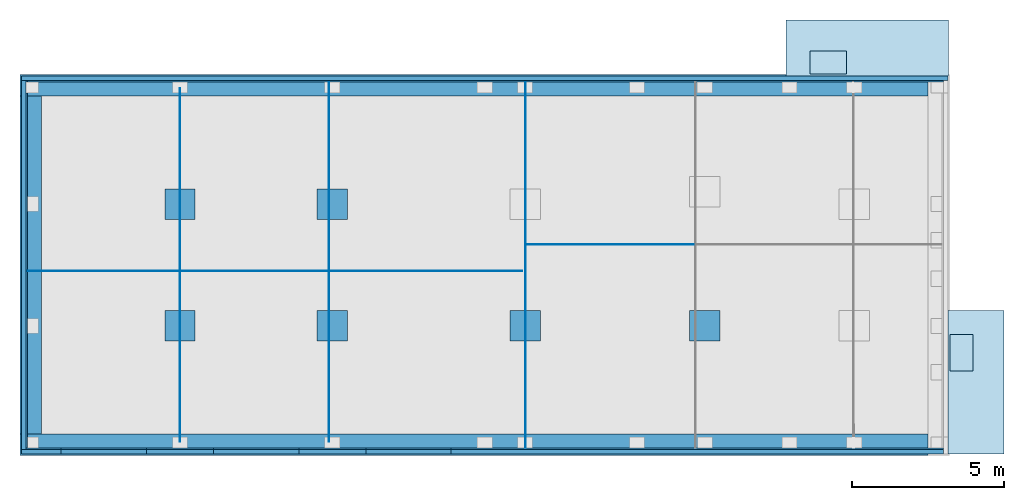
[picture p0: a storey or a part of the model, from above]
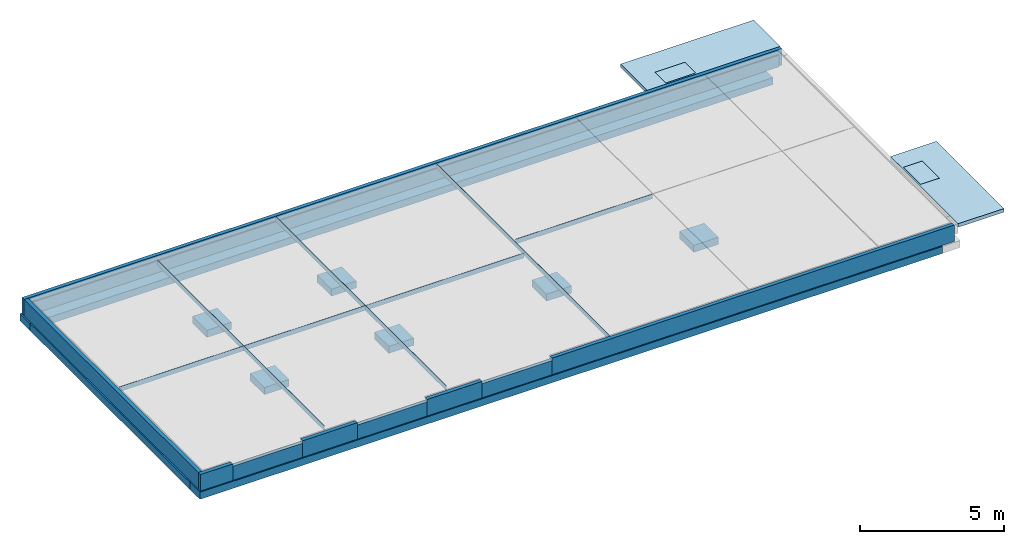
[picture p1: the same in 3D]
Properties of the parts of a building model (IFC2X3), part 1 of 7

# File
Description: IFC2x3 Coordination View
File name: Z:\11023 HEKF Nybygg Måkeveien\00 Tegninger\00 sibsas\HEKF Administrasjonbygg måkeveien Bygg.ifc
Time: 2018-05-01T14:40:47
Author: Bård Sørensen
Organization: Sivilingeniør Bård Sørensen AS, Pb 28, 8455 Stokmarknes, Mob 906 34 144
Written by: EDMsix Version 2.0100.09 Sep 7 2016
Made in: Allplan 2018.0 22.03.2018 - 09:24:33

# IfcBuildingStorey (3)
In: HEKF Administrasjonbygg
Name | Elevation (mm)
Konstruksjoner i grunnen | 6300
Plan 1 | 6500
Plan 2 | 9900

# IfcSpace (44)
InteriorOrExteriorSpace: INTERNAL
Allplan Attributes - Building alteration category: New building; Unit: m²; Area_type_floor_space: 0; BauNVO_FA: 0; BauNVO_FS: 0; Space below stairs (flr spc only > 2m): 0; Factor_floor_area_room: 1; Factor_277: 1
Name | In | LongName | FloorCovering | CeilingCovering | FinishFloorHigh (m) | FinishCeilingHigh (m) | ElevationWithFlooring (m) | GrossWallArea (m2) | NetVolume (m3) | NetFloorArea (m2) | GrossVolume (m3) | CrossSectionArea (m2) | NetPerimeter (m) | NetWallArea (m2) | Allright_Comp_ID | Local_code_story_name | NOI_UUID
101 | Plan 1 | Kontor | Banebelegg, acustikk | Støvbinding, Systemhimling | 0.003 | 2.937 | 6503 | 39.5128 | 30.5853 | 10.4138 | 31.8314 | 10.6105 | 13.1709 | 39.5128 | 0019Roo0000000002 | 1 | ac553d8b-398e-4058-95c3-ac796ec1c327--2 | Pset_SpaceCommon - WallCovering: Ubehandlet SW
107 | Plan 1 | BK | våtromsbelegg m oppkant | støvbinding, systemhimling | 0.003 | 2.937 | 6503 | 21.51 | 8.27036 | 2.81592 | 8.62474 | 2.87491 | 7.17 | 21.51 | 0019Roo0000000085 | 1 | ac553d8b-398e-4058-95c3-ac796ec1c327--85 | Pset_SpaceCommon - WallCovering: Ubehandlet SW
108 | Plan 1 | RWC | våtromsbelegg m oppkant | støvbinding, systemhimling | 0.003 | 2.937 | 6503 | 27.588 | 15.5067 | 5.27978 | 15.8393 | 5.27978 | 9.196 | 27.588 | 0019Roo0000000095 | 1 | ac553d8b-398e-4058-95c3-ac796ec1c327--95
109 | Plan 1 | WCD | våtromsbelegg m oppkant | støvbinding, systemhimling | 0.003 | 2.937 | 6503 | 17.786 | 6.0816 | 2.07068 | 6.36985 | 2.12328 | 5.92866 | 17.786 | 0019Roo0000000105 | 1 | ac553d8b-398e-4058-95c3-ac796ec1c327--105 | Pset_SpaceCommon - WallCovering: Ubehandlet SW
110 | Plan 1 | Fingard-D | våtromsbelegg m oppkant | støvbinding, systemhimling | 0.003 | 2.937 | 6503 | 47.5798 | 37.7168 | 12.842 | 38.7449 | 12.915 | 15.8599 | 47.5798 | 0019Roo0000000115 | 1 | ac553d8b-398e-4058-95c3-ac796ec1c327--115 | Pset_SpaceCommon - WallCovering: Ubehandlet SW
114 | Plan 1 | WCH | våtromsbelegg m oppkant | støvbinding, systemhimling | 0.003 | 2.937 | 6503 | 18.276 | 6.8054 | 2.31713 | 6.95138 | 2.31713 | 6.092 | 18.276 | 0019Roo0000000155 | 1 | ac553d8b-398e-4058-95c3-ac796ec1c327--155
111 | Plan 1 | Dusj D | våtromsbelegg m oppkant | støvbinding, systemhimling | 0.003 | 2.937 | 6503 | 22.8664 | 10.3971 | 3.54004 | 10.6201 | 3.54004 | 7.62212 | 22.8664 | 0019Roo0000000125 | 1 | ac553d8b-398e-4058-95c3-ac796ec1c327--125
115 | Plan 1 | Dusj H | våtromsbelegg m oppkant | støvbinding, systemhimling | 0.003 | 2.937 | 6503 | 20.466 | 8.38554 | 2.85514 | 8.56541 | 2.85514 | 6.822 | 20.466 | 0019Roo0000000165 | 1 | ac553d8b-398e-4058-95c3-ac796ec1c327--165
116 | Plan 1 | Fingard-H | våtromsbelegg m oppkant | støvbinding, systemhimling | 0.003 | 2.937 | 6503 | 52.0936 | 40.4039 | 13.7569 | 41.4585 | 13.8195 | 17.3645 | 52.0936 | 0019Roo0000000185 | 1 | ac553d8b-398e-4058-95c3-ac796ec1c327--185 | Pset_SpaceCommon - WallCovering: Ubehandlet SW
117 | Plan 1 | Grovgard-H | våtromsbelegg m oppkant | støvbinding, systemhimling | 0.03 | 2.91 | 6530 | 48.666 | 38.0572 | 13.0781 | 39.5514 | 13.1838 | 16.222 | 48.666 | 0019Roo0000000175 | 1 | ac553d8b-398e-4058-95c3-ac796ec1c327--175 | Pset_SpaceCommon - WallCovering: Ubehandlet SW
113 | Plan 1 | Gang | Våtromsbelegg | Støvbinding, Systemhimling | 0.003 | 2.937 | 6503 | 24.744 | 12.4317 | 4.2328 | 12.6984 | 4.2328 | 8.248 | 24.744 | 0019Roo0000000145 | 1 | ac553d8b-398e-4058-95c3-ac796ec1c327--145
120 | Plan 1 | Teknisk rom | Golvmaling | Støvbinding x2 | 0.003 | 2.967 | 6503 | 55.866 | 55.4831 | 18.7001 | 56.6694 | 18.8898 | 18.622 | 55.866 | 0019Roo0000000217 | 1 | ac553d8b-398e-4058-95c3-ac796ec1c327--217 | Pset_SpaceCommon - WallCovering: Ubehandlet SW
119 | Plan 1 | Vask | Våtromsbelegg | Støvbinding x2 | 0.003 | 2.967 | 6503 | 25.069 | 12.6974 | 4.27953 | 12.8386 | 4.27953 | 8.35633 | 25.069 | 0019Roo0000000207 | 1 | ac553d8b-398e-4058-95c3-ac796ec1c327--207
121 | Plan 1 | WC | Våtromsbelegg | Støvbinding x2 | 0.003 | 2.967 | 6503 | 18.0177 | 6.42801 | 2.1665 | 6.4995 | 2.1665 | 6.0059 | 18.0177 | 0019Roo0000000227 | 1 | ac553d8b-398e-4058-95c3-ac796ec1c327--227
122 | Plan 1 | Lager | Golvmaling | Støvbinding x2 | 0.003 | 2.967 | 6503 | 31.7213 | 20.5405 | 6.92299 | 20.769 | 6.92299 | 10.5738 | 31.7213 | 0019Roo0000000237 | 1 | ac553d8b-398e-4058-95c3-ac796ec1c327--237
123 | Plan 1 | Lager | Golvmaling | Støvbinding x2 | 0.003 | 2.967 | 6503 | 100.042 | 165.987 | 55.9444 | 168.253 | 56.0843 | 33.3474 | 100.042 | 0019Roo0000000254 | 1 | ac553d8b-398e-4058-95c3-ac796ec1c327--254 | Pset_SpaceCommon - WallCovering: Ubehandlet SW
124 | Plan 1 | Lager | Golvmaling | Støvbinding x2 | 0.003 | 2.967 | 6503 | 101.62 | 174.887 | 58.9441 | 177.721 | 59.2403 | 33.8734 | 101.62 | 0019Roo0000000271 | 1 | ac553d8b-398e-4058-95c3-ac796ec1c327--271 | Pset_SpaceCommon - WallCovering: Ubehandlet SW
118 | Plan 1 | Lager | Golvmaling | Støvbinding x2 | 0.03 | 2.94 | 6530 | 79.422 | 119.839 | 40.7617 | 122.854 | 40.9514 | 26.474 | 79.422 | 0019Roo0000000195 | 1 | ac553d8b-398e-4058-95c3-ac796ec1c327--195 | Pset_SpaceCommon - WallCovering: Ubehandlet SW
102 | Plan 1 | Trapperom | Golvflis | Støvbinding, Systemhimling | 0.003 | 2.937 | 6503 | 40.7104 | 32.4609 | 11.0524 | 33.5148 | 11.1716 | 13.5701 | 32.2758 | 0019Roo0000000046 | 1 | ac553d8b-398e-4058-95c3-ac796ec1c327--46 | Pset_SpaceCommon - WallCovering: Ubehandlet SW
105 | Plan 1 | Kantine | Banebelegg, homogent | Støvbinding, Systemhimling | 0.003 | 2.937 | 6503 | 68.1436 | 92.307 | 31.429 | 94.287 | 31.429 | 22.7145 | 68.1436 | 0019Roo0000000022 | 1 | ac553d8b-398e-4058-95c3-ac796ec1c327--22 | Pset_SpaceCommon - WallCovering: Ubehandlet SW
112 | Plan 1 | Grovgard-D | våtromsbelegg m oppkant | støvbinding, systemhimling | 0.003 | 2.937 | 6503 | 41.31 | 27.864 | 9.48724 | 28.6349 | 9.54496 | 13.77 | 41.31 | 0019Roo0000000135 | 1 | ac553d8b-398e-4058-95c3-ac796ec1c327--135 | Pset_SpaceCommon - WallCovering: Ubehandlet SW; Allplan Attributes - Enclosure: R; Area_type_277: N; Occupancy_type_Din277: USA
103.1 | Plan 1 | Gang | Golvflis | Støvbinding, Systemhimling | 0.003 | 2.937 | 6503 | 30.5276 | 18.5966 | 6.33183 | 19.2004 | 6.40012 | 10.1759 | 17.743 | 0019Roo0000000032 | 1 | ac553d8b-398e-4058-95c3-ac796ec1c327--32 | Pset_SpaceCommon - WallCovering: Ubehandlet SW
103.2 | Plan 1 | Heis |  |  | 0 | 3 | 6500 | 19.8 | 7.7532 | 2.5844 | 8.0475 | 2.6825 | 6.6 | 15.45 | 0019Roo0779929851 | 1 | ac553d8b-398e-4058-95c3-ac796ec1c327--779929851 | Allplan Attributes - Enclosure: R; Area_type_277: N; Occupancy_type_Din277: USA
104 | Plan 1 | Tavlerom | Våtromsbelegg | Støvbinding, Systemhimling | 0.03 | 2.91 | 6530 | 17.7568 | 6.09027 | 2.09287 | 6.38982 | 2.12994 | 5.91893 | 17.7568 | 0019Roo0779929835 | 1 | ac553d8b-398e-4058-95c3-ac796ec1c327--779929835
106 | Plan 1 | Gang | Banebelegg, homogent | Støvbinding, Systemhimling | 0.003 | 2.937 | 6503 | 69.344 | 46.7483 | 15.917 | 47.8954 | 15.9651 | 23.1147 | 69.344 | 0019Roo0000000012 | 1 | ac553d8b-398e-4058-95c3-ac796ec1c327--12 | Pset_SpaceCommon - WallCovering: Ubehandlet SW; Allplan Attributes - Enclosure: R; Area_type_277: N; Occupancy_type_Din277: USA
215 | Plan 2 | BK | Våtromsbelegg m oppkant | Systemhimling | 0.003 | 3.5724 | 9903 | 26.5806 | 11.1277 | 3.11497 | 11.2307 | 3.11497 | 7.37243 | 26.5806 | 0029Roo0000000164 | 2 | ba775db5-6acf-44d4-98dd-11fdd85c2627--164
204 | Plan 2 | WC-H | Våtromsbelegg m oppkant | Systemhimling | 0.03 | 3.5454 | 9930 | 19.3372 | 6.37114 | 1.79705 | 6.47909 | 1.79705 | 5.36341 | 19.3372 | 0029Roo0000000054 | 2 | ba775db5-6acf-44d4-98dd-11fdd85c2627--54
203 | Plan 2 | RWC | Våtromsbelegg m oppkant | Systemhimling | 0.03 | 3.76167 | 9930 | 34.7772 | 19.4475 | 5.17 | 19.758 | 5.17 | 9.1 | 34.7772 | 0029Roo0000000044 | 2 | ba775db5-6acf-44d4-98dd-11fdd85c2627--44
206 | Plan 2 | Kontor |  |  | 0 | 3.26917 | 9900 | 51.3194 | 46.0235 | 14.078 | 46.0235 | 14.078 | 15.698 | 51.3194 | 0029Roo0000000074 | 2 | ba775db5-6acf-44d4-98dd-11fdd85c2627--74
208 | Plan 2 | Kontor |  |  | 0 | 3.26917 | 9900 | 51.3194 | 46.0235 | 14.078 | 46.0235 | 14.078 | 15.698 | 51.3194 | 0029Roo0000000094 | 2 | ba775db5-6acf-44d4-98dd-11fdd85c2627--94
210 | Plan 2 | Kontor |  |  | 0 | 3.26917 | 9900 | 54.9921 | 55.3429 | 16.9288 | 55.3429 | 16.9288 | 16.8214 | 54.9921 | 0029Roo0000000114 | 2 | ba775db5-6acf-44d4-98dd-11fdd85c2627--114
211 | Plan 2 | Kontor |  |  | 0 | 3.73083 | 9900 | 58.2905 | 51.8223 | 13.8903 | 51.8223 | 13.8903 | 15.624 | 58.2905 | 0029Roo0000000124 | 2 | ba775db5-6acf-44d4-98dd-11fdd85c2627--124
207 | Plan 2 | Kontor |  |  | 0 | 3.26917 | 9900 | 51.3194 | 46.0235 | 14.078 | 46.0235 | 14.078 | 15.698 | 51.3194 | 0029Roo0000000084 | 2 | ba775db5-6acf-44d4-98dd-11fdd85c2627--84
213 | Plan 2 | Kontor |  |  | 0 | 3.73083 | 9900 | 58.2009 | 51.5951 | 13.8294 | 51.5951 | 13.8294 | 15.6 | 58.201 | 0029Roo0000000144 | 2 | ba775db5-6acf-44d4-98dd-11fdd85c2627--144
212 | Plan 2 | Kontor |  |  | 0 | 3.73083 | 9900 | 58.186 | 51.5572 | 13.8192 | 51.5572 | 13.8192 | 15.596 | 58.1861 | 0029Roo0000000134 | 2 | ba775db5-6acf-44d4-98dd-11fdd85c2627--134
202 | Plan 2 | Korridor |  |  | 0 | 3.44226 | 9900 | 170.154 | 136.68 | 39.7065 | 136.68 | 39.7065 | 49.4308 | 170.177 | 0029Roo0000000032 | 2 | ba775db5-6acf-44d4-98dd-11fdd85c2627--32
205 | Plan 2 | Garderobe |  |  | 0 | 3.2258 | 9900 | 42.39 | 34.0447 | 10.5539 | 34.0447 | 10.5539 | 13.1409 | 42.39 | 0029Roo0000000064 | 2 | ba775db5-6acf-44d4-98dd-11fdd85c2627--64
209 | Plan 2 | Arkiv/kopi |  |  | 0 | 3.31503 | 9900 | 42.6067 | 33.4428 | 10.0882 | 33.4428 | 10.0882 | 12.8526 | 42.6067 | 0029Roo0000000104 | 2 | ba775db5-6acf-44d4-98dd-11fdd85c2627--104
214 | Plan 2 | Møterom | banebelegg acustikk | Systemhimling | 0.003 | 3.73663 | 9903 | 80.0588 | 91.3179 | 24.439 | 92.126 | 24.439 | 21.2378 | 79.9513 | 0029Roo0000000154 | 2 | ba775db5-6acf-44d4-98dd-11fdd85c2627--154
216 | Plan 2 | IKT | banebelegg acustikk | Systemhimling | 0.003 | 3.80953 | 9903 | 22.2028 | 7.6517 | 2.0086 | 7.71812 | 2.0086 | 5.77816 | 22.2028 | 0029Roo0780027036 | 2 | ba775db5-6acf-44d4-98dd-11fdd85c2627--780027036
218 | Plan 2 | Sjakt |  |  | 0 | 3.14 | 9900 | 24.6633 | 10.2764 | 3.27274 | 10.2764 | 3.27274 | 7.85457 | 24.6633 | 0029Roo0780027340 | 2 | ba775db5-6acf-44d4-98dd-11fdd85c2627--780027340
201 | Plan 2 | Gang | Golvflis | Systemhimling | 0.003 | 3.64271 | 9903 | 60.9532 | 44.2319 | 12.1411 | 44.6334 | 12.1428 | 16.5827 | 41.7609 | 0029Roo0000000020 | 2 | ba775db5-6acf-44d4-98dd-11fdd85c2627--20
200 | Plan 2 | Trapperom | Golvflis | Systemhimling | 0.003 | 3.46033 | 9903 | 47.5754 | 38.886 | 11.2379 | 39.2576 | 11.2379 | 13.6189 | 33.8822 | 0029Roo0000000007 | 2 | ba775db5-6acf-44d4-98dd-11fdd85c2627--7
217 | Plan 2 | Heis |  |  | 0 | 3.83833 | 9900 | 25.333 | 10.2963 | 2.6825 | 10.2963 | 2.6825 | 6.6 | 19.8568 | 0029Roo0780027106 | 2 | ba775db5-6acf-44d4-98dd-11fdd85c2627--780027106

# IfcAnnotation (2236)
Name | In | NOI_UUID
 | HEKF Administrasjonbygg | f3b9140b-d331-4fc5-a6fb-2d5accb557e5--59120
 | HEKF Administrasjonbygg | f3b9140b-d331-4fc5-a6fb-2d5accb557e5--59619
 | HEKF Administrasjonbygg | f3b9140b-d331-4fc5-a6fb-2d5accb557e5--59620
 | HEKF Administrasjonbygg | f3b9140b-d331-4fc5-a6fb-2d5accb557e5--59621
 | HEKF Administrasjonbygg | f3b9140b-d331-4fc5-a6fb-2d5accb557e5--59622
 | HEKF Administrasjonbygg | f3b9140b-d331-4fc5-a6fb-2d5accb557e5--59623
 | HEKF Administrasjonbygg | f3b9140b-d331-4fc5-a6fb-2d5accb557e5--59624
 | HEKF Administrasjonbygg | f3b9140b-d331-4fc5-a6fb-2d5accb557e5--59625
 | HEKF Administrasjonbygg | f3b9140b-d331-4fc5-a6fb-2d5accb557e5--59626
 | HEKF Administrasjonbygg | f3b9140b-d331-4fc5-a6fb-2d5accb557e5--59627
 | HEKF Administrasjonbygg | f3b9140b-d331-4fc5-a6fb-2d5accb557e5--59628
 | HEKF Administrasjonbygg | f3b9140b-d331-4fc5-a6fb-2d5accb557e5--59629
 | HEKF Administrasjonbygg | f3b9140b-d331-4fc5-a6fb-2d5accb557e5--59129
 | HEKF Administrasjonbygg | f3b9140b-d331-4fc5-a6fb-2d5accb557e5--59130
 | HEKF Administrasjonbygg | f3b9140b-d331-4fc5-a6fb-2d5accb557e5--59136
 | HEKF Administrasjonbygg | f3b9140b-d331-4fc5-a6fb-2d5accb557e5--59137
 | HEKF Administrasjonbygg | f3b9140b-d331-4fc5-a6fb-2d5accb557e5--59141
 | HEKF Administrasjonbygg | f3b9140b-d331-4fc5-a6fb-2d5accb557e5--59142
 | HEKF Administrasjonbygg | f3b9140b-d331-4fc5-a6fb-2d5accb557e5--59160
 | HEKF Administrasjonbygg | f3b9140b-d331-4fc5-a6fb-2d5accb557e5--59161
 | HEKF Administrasjonbygg | f3b9140b-d331-4fc5-a6fb-2d5accb557e5--59163
 | HEKF Administrasjonbygg | f3b9140b-d331-4fc5-a6fb-2d5accb557e5--59164
 | HEKF Administrasjonbygg | f3b9140b-d331-4fc5-a6fb-2d5accb557e5--59157
 | HEKF Administrasjonbygg | f3b9140b-d331-4fc5-a6fb-2d5accb557e5--59158
 | HEKF Administrasjonbygg | f3b9140b-d331-4fc5-a6fb-2d5accb557e5--59569
 | HEKF Administrasjonbygg | f3b9140b-d331-4fc5-a6fb-2d5accb557e5--59571
 | HEKF Administrasjonbygg | f3b9140b-d331-4fc5-a6fb-2d5accb557e5--59573
 | HEKF Administrasjonbygg | f3b9140b-d331-4fc5-a6fb-2d5accb557e5--59575
 | HEKF Administrasjonbygg | f3b9140b-d331-4fc5-a6fb-2d5accb557e5--59580
 | HEKF Administrasjonbygg | f3b9140b-d331-4fc5-a6fb-2d5accb557e5--59582
 | HEKF Administrasjonbygg | f3b9140b-d331-4fc5-a6fb-2d5accb557e5--59584
 | HEKF Administrasjonbygg | f3b9140b-d331-4fc5-a6fb-2d5accb557e5--59586
 | HEKF Administrasjonbygg | f3b9140b-d331-4fc5-a6fb-2d5accb557e5--59591
 | HEKF Administrasjonbygg | f3b9140b-d331-4fc5-a6fb-2d5accb557e5--59593
 | HEKF Administrasjonbygg | f3b9140b-d331-4fc5-a6fb-2d5accb557e5--59595
 | HEKF Administrasjonbygg | f3b9140b-d331-4fc5-a6fb-2d5accb557e5--59597
 | HEKF Administrasjonbygg | f3b9140b-d331-4fc5-a6fb-2d5accb557e5--59323
 | HEKF Administrasjonbygg | f3b9140b-d331-4fc5-a6fb-2d5accb557e5--59325
 | HEKF Administrasjonbygg | f3b9140b-d331-4fc5-a6fb-2d5accb557e5--59327
 | HEKF Administrasjonbygg | f3b9140b-d331-4fc5-a6fb-2d5accb557e5--59329
 | HEKF Administrasjonbygg | f3b9140b-d331-4fc5-a6fb-2d5accb557e5--59331
 | HEKF Administrasjonbygg | f3b9140b-d331-4fc5-a6fb-2d5accb557e5--59333
 | HEKF Administrasjonbygg | f3b9140b-d331-4fc5-a6fb-2d5accb557e5--59335
 | HEKF Administrasjonbygg | f3b9140b-d331-4fc5-a6fb-2d5accb557e5--59343
 | HEKF Administrasjonbygg | f3b9140b-d331-4fc5-a6fb-2d5accb557e5--59345
 | HEKF Administrasjonbygg | f3b9140b-d331-4fc5-a6fb-2d5accb557e5--59347
 | HEKF Administrasjonbygg | f3b9140b-d331-4fc5-a6fb-2d5accb557e5--59349
 | HEKF Administrasjonbygg | f3b9140b-d331-4fc5-a6fb-2d5accb557e5--59351
 | HEKF Administrasjonbygg | f3b9140b-d331-4fc5-a6fb-2d5accb557e5--59353
 | HEKF Administrasjonbygg | f3b9140b-d331-4fc5-a6fb-2d5accb557e5--59355
 | HEKF Administrasjonbygg | f3b9140b-d331-4fc5-a6fb-2d5accb557e5--59361
 | HEKF Administrasjonbygg | f3b9140b-d331-4fc5-a6fb-2d5accb557e5--59363
 | HEKF Administrasjonbygg | f3b9140b-d331-4fc5-a6fb-2d5accb557e5--59365
 | HEKF Administrasjonbygg | f3b9140b-d331-4fc5-a6fb-2d5accb557e5--59367
 | HEKF Administrasjonbygg | f3b9140b-d331-4fc5-a6fb-2d5accb557e5--59369
 | HEKF Administrasjonbygg | f3b9140b-d331-4fc5-a6fb-2d5accb557e5--59371
 | HEKF Administrasjonbygg | f3b9140b-d331-4fc5-a6fb-2d5accb557e5--59373
6 x  | HEKF Administrasjonbygg | f3b9140b-d331-4fc5-a6fb-2d5accb557e5--0
 | Konstruksjoner i grunnen | dea4e5d4-67a8-4f71-a690-1e4c8fd9c290--779824159
 | Konstruksjoner i grunnen | dea4e5d4-67a8-4f71-a690-1e4c8fd9c290--779824162
 | Konstruksjoner i grunnen | dea4e5d4-67a8-4f71-a690-1e4c8fd9c290--779847592
 | Konstruksjoner i grunnen | dea4e5d4-67a8-4f71-a690-1e4c8fd9c290--779847591
 | Konstruksjoner i grunnen | dea4e5d4-67a8-4f71-a690-1e4c8fd9c290--779847593
 | Konstruksjoner i grunnen | dea4e5d4-67a8-4f71-a690-1e4c8fd9c290--779847594
 | Konstruksjoner i grunnen | dea4e5d4-67a8-4f71-a690-1e4c8fd9c290--779847596
 | Konstruksjoner i grunnen | dea4e5d4-67a8-4f71-a690-1e4c8fd9c290--779847595
 | Konstruksjoner i grunnen | dea4e5d4-67a8-4f71-a690-1e4c8fd9c290--779847590
 | Konstruksjoner i grunnen | dea4e5d4-67a8-4f71-a690-1e4c8fd9c290--779847589
 | Konstruksjoner i grunnen | dea4e5d4-67a8-4f71-a690-1e4c8fd9c290--779847619
 | Konstruksjoner i grunnen | dea4e5d4-67a8-4f71-a690-1e4c8fd9c290--779847625
 | Konstruksjoner i grunnen | dea4e5d4-67a8-4f71-a690-1e4c8fd9c290--779847626
 | Konstruksjoner i grunnen | dea4e5d4-67a8-4f71-a690-1e4c8fd9c290--779847631
 | Konstruksjoner i grunnen | dea4e5d4-67a8-4f71-a690-1e4c8fd9c290--779847688
 | Konstruksjoner i grunnen | dea4e5d4-67a8-4f71-a690-1e4c8fd9c290--779847689
 | Konstruksjoner i grunnen | dea4e5d4-67a8-4f71-a690-1e4c8fd9c290--779847690
 | Konstruksjoner i grunnen | dea4e5d4-67a8-4f71-a690-1e4c8fd9c290--779847691
 | Konstruksjoner i grunnen | dea4e5d4-67a8-4f71-a690-1e4c8fd9c290--779847692
 | Konstruksjoner i grunnen | dea4e5d4-67a8-4f71-a690-1e4c8fd9c290--779847693
 | Konstruksjoner i grunnen | dea4e5d4-67a8-4f71-a690-1e4c8fd9c290--779847694
 | Konstruksjoner i grunnen | dea4e5d4-67a8-4f71-a690-1e4c8fd9c290--779847695
 | Konstruksjoner i grunnen | dea4e5d4-67a8-4f71-a690-1e4c8fd9c290--779847711
 | Konstruksjoner i grunnen | dea4e5d4-67a8-4f71-a690-1e4c8fd9c290--779847712
 | Konstruksjoner i grunnen | dea4e5d4-67a8-4f71-a690-1e4c8fd9c290--779847713
 | Konstruksjoner i grunnen | dea4e5d4-67a8-4f71-a690-1e4c8fd9c290--779847714
 | Konstruksjoner i grunnen | dea4e5d4-67a8-4f71-a690-1e4c8fd9c290--779847715
 | Konstruksjoner i grunnen | dea4e5d4-67a8-4f71-a690-1e4c8fd9c290--779847716
 | Konstruksjoner i grunnen | dea4e5d4-67a8-4f71-a690-1e4c8fd9c290--779847717
 | Konstruksjoner i grunnen | dea4e5d4-67a8-4f71-a690-1e4c8fd9c290--779847718
 | Konstruksjoner i grunnen | dea4e5d4-67a8-4f71-a690-1e4c8fd9c290--779847719
 | Konstruksjoner i grunnen | dea4e5d4-67a8-4f71-a690-1e4c8fd9c290--779847720
 | Konstruksjoner i grunnen | dea4e5d4-67a8-4f71-a690-1e4c8fd9c290--779847721
 | Konstruksjoner i grunnen | dea4e5d4-67a8-4f71-a690-1e4c8fd9c290--779847722
 | Konstruksjoner i grunnen | dea4e5d4-67a8-4f71-a690-1e4c8fd9c290--779847723
 | Konstruksjoner i grunnen | dea4e5d4-67a8-4f71-a690-1e4c8fd9c290--779847724
 | Konstruksjoner i grunnen | dea4e5d4-67a8-4f71-a690-1e4c8fd9c290--779847725
 | Konstruksjoner i grunnen | dea4e5d4-67a8-4f71-a690-1e4c8fd9c290--779847726
 | Konstruksjoner i grunnen | dea4e5d4-67a8-4f71-a690-1e4c8fd9c290--779847727
 | Konstruksjoner i grunnen | dea4e5d4-67a8-4f71-a690-1e4c8fd9c290--779847728
 | Konstruksjoner i grunnen | dea4e5d4-67a8-4f71-a690-1e4c8fd9c290--779847729
 | Konstruksjoner i grunnen | dea4e5d4-67a8-4f71-a690-1e4c8fd9c290--779847730
 | Konstruksjoner i grunnen | dea4e5d4-67a8-4f71-a690-1e4c8fd9c290--779847731
 | Konstruksjoner i grunnen | dea4e5d4-67a8-4f71-a690-1e4c8fd9c290--779847732
 | Konstruksjoner i grunnen | dea4e5d4-67a8-4f71-a690-1e4c8fd9c290--779847733
 | Konstruksjoner i grunnen | dea4e5d4-67a8-4f71-a690-1e4c8fd9c290--779847734
 | Konstruksjoner i grunnen | dea4e5d4-67a8-4f71-a690-1e4c8fd9c290--779847735
 | Konstruksjoner i grunnen | dea4e5d4-67a8-4f71-a690-1e4c8fd9c290--779847736
 | Konstruksjoner i grunnen | dea4e5d4-67a8-4f71-a690-1e4c8fd9c290--779847737
 | Konstruksjoner i grunnen | dea4e5d4-67a8-4f71-a690-1e4c8fd9c290--779847700
 | Konstruksjoner i grunnen | dea4e5d4-67a8-4f71-a690-1e4c8fd9c290--779847701
 | Konstruksjoner i grunnen | dea4e5d4-67a8-4f71-a690-1e4c8fd9c290--779847702
 | Konstruksjoner i grunnen | dea4e5d4-67a8-4f71-a690-1e4c8fd9c290--779847703
 | Konstruksjoner i grunnen | dea4e5d4-67a8-4f71-a690-1e4c8fd9c290--779847704
 | Konstruksjoner i grunnen | dea4e5d4-67a8-4f71-a690-1e4c8fd9c290--779847705
 | Konstruksjoner i grunnen | dea4e5d4-67a8-4f71-a690-1e4c8fd9c290--779847706
 | Konstruksjoner i grunnen | dea4e5d4-67a8-4f71-a690-1e4c8fd9c290--779847707
 | Konstruksjoner i grunnen | dea4e5d4-67a8-4f71-a690-1e4c8fd9c290--779847708
 | Konstruksjoner i grunnen | dea4e5d4-67a8-4f71-a690-1e4c8fd9c290--779847745
 | Konstruksjoner i grunnen | dea4e5d4-67a8-4f71-a690-1e4c8fd9c290--779847623
 | Konstruksjoner i grunnen | dea4e5d4-67a8-4f71-a690-1e4c8fd9c290--779847624
 | Konstruksjoner i grunnen | dea4e5d4-67a8-4f71-a690-1e4c8fd9c290--779847621
 | Konstruksjoner i grunnen | dea4e5d4-67a8-4f71-a690-1e4c8fd9c290--779847622
 | Konstruksjoner i grunnen | dea4e5d4-67a8-4f71-a690-1e4c8fd9c290--779847627
 | Konstruksjoner i grunnen | dea4e5d4-67a8-4f71-a690-1e4c8fd9c290--779847628
 | Konstruksjoner i grunnen | dea4e5d4-67a8-4f71-a690-1e4c8fd9c290--779847629
 | Konstruksjoner i grunnen | dea4e5d4-67a8-4f71-a690-1e4c8fd9c290--779847630
 | Konstruksjoner i grunnen | dea4e5d4-67a8-4f71-a690-1e4c8fd9c290--780050101
 | Konstruksjoner i grunnen | dea4e5d4-67a8-4f71-a690-1e4c8fd9c290--780050104
 | Konstruksjoner i grunnen | dea4e5d4-67a8-4f71-a690-1e4c8fd9c290--780050085
 | Konstruksjoner i grunnen | dea4e5d4-67a8-4f71-a690-1e4c8fd9c290--780050108
 | Konstruksjoner i grunnen | dea4e5d4-67a8-4f71-a690-1e4c8fd9c290--780050110
 | Konstruksjoner i grunnen | dea4e5d4-67a8-4f71-a690-1e4c8fd9c290--780050111
 | Konstruksjoner i grunnen | dea4e5d4-67a8-4f71-a690-1e4c8fd9c290--780050083
 | Konstruksjoner i grunnen | dea4e5d4-67a8-4f71-a690-1e4c8fd9c290--780050084
 | Konstruksjoner i grunnen | dea4e5d4-67a8-4f71-a690-1e4c8fd9c290--779847743
 | Konstruksjoner i grunnen | dea4e5d4-67a8-4f71-a690-1e4c8fd9c290--779847744
 | Konstruksjoner i grunnen | dea4e5d4-67a8-4f71-a690-1e4c8fd9c290--779824157
 | Konstruksjoner i grunnen | dea4e5d4-67a8-4f71-a690-1e4c8fd9c290--779824158
 | Konstruksjoner i grunnen | dea4e5d4-67a8-4f71-a690-1e4c8fd9c290--779824160
 | Konstruksjoner i grunnen | dea4e5d4-67a8-4f71-a690-1e4c8fd9c290--779824161
 | Konstruksjoner i grunnen | dea4e5d4-67a8-4f71-a690-1e4c8fd9c290--780050214
 | Konstruksjoner i grunnen | dea4e5d4-67a8-4f71-a690-1e4c8fd9c290--780050222
 | Konstruksjoner i grunnen | dea4e5d4-67a8-4f71-a690-1e4c8fd9c290--780050223
 | Konstruksjoner i grunnen | dea4e5d4-67a8-4f71-a690-1e4c8fd9c290--780050224
 | Konstruksjoner i grunnen | dea4e5d4-67a8-4f71-a690-1e4c8fd9c290--780050225
 | Konstruksjoner i grunnen | dea4e5d4-67a8-4f71-a690-1e4c8fd9c290--780050226
 | Konstruksjoner i grunnen | dea4e5d4-67a8-4f71-a690-1e4c8fd9c290--780050227
 | Konstruksjoner i grunnen | dea4e5d4-67a8-4f71-a690-1e4c8fd9c290--780050228
 | Konstruksjoner i grunnen | dea4e5d4-67a8-4f71-a690-1e4c8fd9c290--780050229
 | Konstruksjoner i grunnen | dea4e5d4-67a8-4f71-a690-1e4c8fd9c290--780050230
 | Konstruksjoner i grunnen | dea4e5d4-67a8-4f71-a690-1e4c8fd9c290--780050240
 | Konstruksjoner i grunnen | dea4e5d4-67a8-4f71-a690-1e4c8fd9c290--780050166
 | Konstruksjoner i grunnen | dea4e5d4-67a8-4f71-a690-1e4c8fd9c290--780050167
 | Konstruksjoner i grunnen | dea4e5d4-67a8-4f71-a690-1e4c8fd9c290--780050168
 | Konstruksjoner i grunnen | dea4e5d4-67a8-4f71-a690-1e4c8fd9c290--780050179
 | Konstruksjoner i grunnen | dea4e5d4-67a8-4f71-a690-1e4c8fd9c290--780050182
 | Konstruksjoner i grunnen | dea4e5d4-67a8-4f71-a690-1e4c8fd9c290--780050185
 | Konstruksjoner i grunnen | dea4e5d4-67a8-4f71-a690-1e4c8fd9c290--780050190
 | Konstruksjoner i grunnen | dea4e5d4-67a8-4f71-a690-1e4c8fd9c290--780050193
 | Konstruksjoner i grunnen | dea4e5d4-67a8-4f71-a690-1e4c8fd9c290--780050196
 | Konstruksjoner i grunnen | dea4e5d4-67a8-4f71-a690-1e4c8fd9c290--780050199
 | Konstruksjoner i grunnen | dea4e5d4-67a8-4f71-a690-1e4c8fd9c290--780050202
 | Konstruksjoner i grunnen | dea4e5d4-67a8-4f71-a690-1e4c8fd9c290--780050205
 | Konstruksjoner i grunnen | dea4e5d4-67a8-4f71-a690-1e4c8fd9c290--780050237
 | Konstruksjoner i grunnen | dea4e5d4-67a8-4f71-a690-1e4c8fd9c290--780050209
 | Konstruksjoner i grunnen | dea4e5d4-67a8-4f71-a690-1e4c8fd9c290--779824197
 | Konstruksjoner i grunnen | dea4e5d4-67a8-4f71-a690-1e4c8fd9c290--779824207
 | Konstruksjoner i grunnen | dea4e5d4-67a8-4f71-a690-1e4c8fd9c290--779824217
 | Konstruksjoner i grunnen | dea4e5d4-67a8-4f71-a690-1e4c8fd9c290--779824227
 | Konstruksjoner i grunnen | dea4e5d4-67a8-4f71-a690-1e4c8fd9c290--779824237
 | Konstruksjoner i grunnen | dea4e5d4-67a8-4f71-a690-1e4c8fd9c290--779999040
 | Konstruksjoner i grunnen | dea4e5d4-67a8-4f71-a690-1e4c8fd9c290--779999089
 | Konstruksjoner i grunnen | dea4e5d4-67a8-4f71-a690-1e4c8fd9c290--780050217
 | Konstruksjoner i grunnen | dea4e5d4-67a8-4f71-a690-1e4c8fd9c290--780050270
 | Konstruksjoner i grunnen | dea4e5d4-67a8-4f71-a690-1e4c8fd9c290--779847588
 | Konstruksjoner i grunnen | dea4e5d4-67a8-4f71-a690-1e4c8fd9c290--779847587
 | Konstruksjoner i grunnen | dea4e5d4-67a8-4f71-a690-1e4c8fd9c290--779847618
 | Konstruksjoner i grunnen | dea4e5d4-67a8-4f71-a690-1e4c8fd9c290--779847614
 | Konstruksjoner i grunnen | dea4e5d4-67a8-4f71-a690-1e4c8fd9c290--779847610
 | Konstruksjoner i grunnen | dea4e5d4-67a8-4f71-a690-1e4c8fd9c290--779847603
 | Konstruksjoner i grunnen | dea4e5d4-67a8-4f71-a690-1e4c8fd9c290--779847647
 | Konstruksjoner i grunnen | dea4e5d4-67a8-4f71-a690-1e4c8fd9c290--779847639
 | Konstruksjoner i grunnen | dea4e5d4-67a8-4f71-a690-1e4c8fd9c290--779847635
 | Konstruksjoner i grunnen | dea4e5d4-67a8-4f71-a690-1e4c8fd9c290--779824203
 | Konstruksjoner i grunnen | dea4e5d4-67a8-4f71-a690-1e4c8fd9c290--779847675
 | Konstruksjoner i grunnen | dea4e5d4-67a8-4f71-a690-1e4c8fd9c290--779847671
 | Konstruksjoner i grunnen | dea4e5d4-67a8-4f71-a690-1e4c8fd9c290--779847679
 | Konstruksjoner i grunnen | dea4e5d4-67a8-4f71-a690-1e4c8fd9c290--779847663
 | Konstruksjoner i grunnen | dea4e5d4-67a8-4f71-a690-1e4c8fd9c290--779847651
 | Konstruksjoner i grunnen | dea4e5d4-67a8-4f71-a690-1e4c8fd9c290--779847659
 | Konstruksjoner i grunnen | dea4e5d4-67a8-4f71-a690-1e4c8fd9c290--779847655
 | Konstruksjoner i grunnen | dea4e5d4-67a8-4f71-a690-1e4c8fd9c290--779847667
 | Konstruksjoner i grunnen | dea4e5d4-67a8-4f71-a690-1e4c8fd9c290--779998561
 | Konstruksjoner i grunnen | dea4e5d4-67a8-4f71-a690-1e4c8fd9c290--779998562
 | Konstruksjoner i grunnen | dea4e5d4-67a8-4f71-a690-1e4c8fd9c290--779998563
 | Konstruksjoner i grunnen | dea4e5d4-67a8-4f71-a690-1e4c8fd9c290--779998565
 | Konstruksjoner i grunnen | dea4e5d4-67a8-4f71-a690-1e4c8fd9c290--779998566
 | Konstruksjoner i grunnen | dea4e5d4-67a8-4f71-a690-1e4c8fd9c290--779998567
 | Konstruksjoner i grunnen | dea4e5d4-67a8-4f71-a690-1e4c8fd9c290--779998568
 | Konstruksjoner i grunnen | dea4e5d4-67a8-4f71-a690-1e4c8fd9c290--779998692
 | Konstruksjoner i grunnen | dea4e5d4-67a8-4f71-a690-1e4c8fd9c290--779998564
 | Konstruksjoner i grunnen | dea4e5d4-67a8-4f71-a690-1e4c8fd9c290--780050215
 | Konstruksjoner i grunnen | dea4e5d4-67a8-4f71-a690-1e4c8fd9c290--780050216
 | Konstruksjoner i grunnen | dea4e5d4-67a8-4f71-a690-1e4c8fd9c290--780050233
 | Konstruksjoner i grunnen | 4201cc08-73ef-4c73-a438-824d10b54809--16813612
 | Konstruksjoner i grunnen | 4201cc08-73ef-4c73-a438-824d10b54809--16813613
 | Konstruksjoner i grunnen | 4201cc08-73ef-4c73-a438-824d10b54809--16813614
 | Konstruksjoner i grunnen | 4201cc08-73ef-4c73-a438-824d10b54809--16813615
 | Konstruksjoner i grunnen | 4201cc08-73ef-4c73-a438-824d10b54809--16813605
 | Konstruksjoner i grunnen | 4201cc08-73ef-4c73-a438-824d10b54809--16813606
 | Konstruksjoner i grunnen | 4201cc08-73ef-4c73-a438-824d10b54809--16813621
 | Konstruksjoner i grunnen | 4201cc08-73ef-4c73-a438-824d10b54809--16813622
 | Konstruksjoner i grunnen | 4201cc08-73ef-4c73-a438-824d10b54809--16813598
 | Konstruksjoner i grunnen | 4201cc08-73ef-4c73-a438-824d10b54809--16813599
 | Konstruksjoner i grunnen | 4201cc08-73ef-4c73-a438-824d10b54809--16813918
 | Konstruksjoner i grunnen | 4201cc08-73ef-4c73-a438-824d10b54809--16813919
 | Konstruksjoner i grunnen | 4201cc08-73ef-4c73-a438-824d10b54809--16814150
 | Konstruksjoner i grunnen | 4201cc08-73ef-4c73-a438-824d10b54809--16814151
 | Konstruksjoner i grunnen | 4201cc08-73ef-4c73-a438-824d10b54809--16814156
 | Konstruksjoner i grunnen | 4201cc08-73ef-4c73-a438-824d10b54809--16814157
 | Konstruksjoner i grunnen | 4201cc08-73ef-4c73-a438-824d10b54809--16814162
 | Konstruksjoner i grunnen | 4201cc08-73ef-4c73-a438-824d10b54809--16814163
 | Konstruksjoner i grunnen | 4201cc08-73ef-4c73-a438-824d10b54809--16814168
 | Konstruksjoner i grunnen | 4201cc08-73ef-4c73-a438-824d10b54809--16814169
 | Konstruksjoner i grunnen | 4201cc08-73ef-4c73-a438-824d10b54809--16814174
 | Konstruksjoner i grunnen | 4201cc08-73ef-4c73-a438-824d10b54809--16814175
 | Konstruksjoner i grunnen | 4201cc08-73ef-4c73-a438-824d10b54809--16814180
 | Konstruksjoner i grunnen | 4201cc08-73ef-4c73-a438-824d10b54809--16814181
 | Konstruksjoner i grunnen | 4201cc08-73ef-4c73-a438-824d10b54809--16814186
 | Konstruksjoner i grunnen | 4201cc08-73ef-4c73-a438-824d10b54809--16814187
 | Konstruksjoner i grunnen | 4201cc08-73ef-4c73-a438-824d10b54809--16814192
 | Konstruksjoner i grunnen | 4201cc08-73ef-4c73-a438-824d10b54809--16814193
 | Konstruksjoner i grunnen | 7f7a4b69-a8bb-45a3-b6d6-f0093fb4d01a--16819793
 | Konstruksjoner i grunnen | 7f7a4b69-a8bb-45a3-b6d6-f0093fb4d01a--16819828
 | Konstruksjoner i grunnen | 7f7a4b69-a8bb-45a3-b6d6-f0093fb4d01a--16819802
 | Konstruksjoner i grunnen | 7f7a4b69-a8bb-45a3-b6d6-f0093fb4d01a--16819829
 | Konstruksjoner i grunnen | 7f7a4b69-a8bb-45a3-b6d6-f0093fb4d01a--779928282
 | Konstruksjoner i grunnen | 7f7a4b69-a8bb-45a3-b6d6-f0093fb4d01a--779928283
 | Konstruksjoner i grunnen | 7f7a4b69-a8bb-45a3-b6d6-f0093fb4d01a--779928284
 | Konstruksjoner i grunnen | 7f7a4b69-a8bb-45a3-b6d6-f0093fb4d01a--779928285
 | Konstruksjoner i grunnen | 7f7a4b69-a8bb-45a3-b6d6-f0093fb4d01a--779928286
 | Konstruksjoner i grunnen | 7f7a4b69-a8bb-45a3-b6d6-f0093fb4d01a--779928287
 | Konstruksjoner i grunnen | 7f7a4b69-a8bb-45a3-b6d6-f0093fb4d01a--779928288
 | Konstruksjoner i grunnen | 7f7a4b69-a8bb-45a3-b6d6-f0093fb4d01a--779928289
 | Konstruksjoner i grunnen | 7f7a4b69-a8bb-45a3-b6d6-f0093fb4d01a--779928290
 | Konstruksjoner i grunnen | 7f7a4b69-a8bb-45a3-b6d6-f0093fb4d01a--779928291
 | Konstruksjoner i grunnen | 7f7a4b69-a8bb-45a3-b6d6-f0093fb4d01a--16819707
 | Konstruksjoner i grunnen | 7f7a4b69-a8bb-45a3-b6d6-f0093fb4d01a--16824202
 | Konstruksjoner i grunnen | 7f7a4b69-a8bb-45a3-b6d6-f0093fb4d01a--16824203
 | Konstruksjoner i grunnen | 7f7a4b69-a8bb-45a3-b6d6-f0093fb4d01a--779928930
 | Konstruksjoner i grunnen | 7f7a4b69-a8bb-45a3-b6d6-f0093fb4d01a--779928931
 | Konstruksjoner i grunnen | 7f7a4b69-a8bb-45a3-b6d6-f0093fb4d01a--779928933
 | Konstruksjoner i grunnen | 7f7a4b69-a8bb-45a3-b6d6-f0093fb4d01a--779928934
 | Konstruksjoner i grunnen | 7f7a4b69-a8bb-45a3-b6d6-f0093fb4d01a--779928882
 | Konstruksjoner i grunnen | 7f7a4b69-a8bb-45a3-b6d6-f0093fb4d01a--779928883
 | Konstruksjoner i grunnen | 7f7a4b69-a8bb-45a3-b6d6-f0093fb4d01a--779931406
 | Konstruksjoner i grunnen | 7f7a4b69-a8bb-45a3-b6d6-f0093fb4d01a--779931407
 | Konstruksjoner i grunnen | 7f7a4b69-a8bb-45a3-b6d6-f0093fb4d01a--779931417
 | Konstruksjoner i grunnen | 7f7a4b69-a8bb-45a3-b6d6-f0093fb4d01a--779931418
 | Konstruksjoner i grunnen | 7f7a4b69-a8bb-45a3-b6d6-f0093fb4d01a--779931428
 | Konstruksjoner i grunnen | 7f7a4b69-a8bb-45a3-b6d6-f0093fb4d01a--779931429
 | Konstruksjoner i grunnen | 7f7a4b69-a8bb-45a3-b6d6-f0093fb4d01a--16824249
 | Konstruksjoner i grunnen | 7f7a4b69-a8bb-45a3-b6d6-f0093fb4d01a--16824250
 | Konstruksjoner i grunnen | 7f7a4b69-a8bb-45a3-b6d6-f0093fb4d01a--16824229
 | Konstruksjoner i grunnen | 7f7a4b69-a8bb-45a3-b6d6-f0093fb4d01a--16824230
 | Konstruksjoner i grunnen | 7f7a4b69-a8bb-45a3-b6d6-f0093fb4d01a--16824219
 | Konstruksjoner i grunnen | 7f7a4b69-a8bb-45a3-b6d6-f0093fb4d01a--16824220
 | Konstruksjoner i grunnen | 7f7a4b69-a8bb-45a3-b6d6-f0093fb4d01a--779928296
 | Konstruksjoner i grunnen | 7f7a4b69-a8bb-45a3-b6d6-f0093fb4d01a--779928294
 | Konstruksjoner i grunnen | 7f7a4b69-a8bb-45a3-b6d6-f0093fb4d01a--779928292
 | Plan 1 | 3244f7b8-136b-492f-bad8-2462ae0dead0--16821207
 | Plan 1 | 3244f7b8-136b-492f-bad8-2462ae0dead0--16821208
 | Plan 1 | 3244f7b8-136b-492f-bad8-2462ae0dead0--16821233
 | Plan 1 | 3244f7b8-136b-492f-bad8-2462ae0dead0--16821240
 | Plan 1 | 3244f7b8-136b-492f-bad8-2462ae0dead0--16821253
 | Plan 1 | 480282cb-d55c-48df-bc97-d2a65b1fac34--6947
 | Plan 1 | 480282cb-d55c-48df-bc97-d2a65b1fac34--6948
 | Plan 1 | 480282cb-d55c-48df-bc97-d2a65b1fac34--6997
 | Plan 1 | 480282cb-d55c-48df-bc97-d2a65b1fac34--6998
 | Plan 1 | 480282cb-d55c-48df-bc97-d2a65b1fac34--7001
 | Plan 1 | 480282cb-d55c-48df-bc97-d2a65b1fac34--7002
 | Plan 1 | 480282cb-d55c-48df-bc97-d2a65b1fac34--7003
 | Plan 1 | 480282cb-d55c-48df-bc97-d2a65b1fac34--7004
 | Plan 1 | 480282cb-d55c-48df-bc97-d2a65b1fac34--7005
 | Plan 1 | 480282cb-d55c-48df-bc97-d2a65b1fac34--7006
 | Plan 1 | 480282cb-d55c-48df-bc97-d2a65b1fac34--7007
 | Plan 1 | 480282cb-d55c-48df-bc97-d2a65b1fac34--6999
 | Plan 1 | 480282cb-d55c-48df-bc97-d2a65b1fac34--7000
 | Plan 1 | d1eb0bd9-ddf6-4315-a806-967de25454b1--779969358
 | Plan 1 | d1eb0bd9-ddf6-4315-a806-967de25454b1--780004765
 | Plan 1 | d1eb0bd9-ddf6-4315-a806-967de25454b1--780004766
 | Plan 1 | d1eb0bd9-ddf6-4315-a806-967de25454b1--780004767
 | Plan 1 | d1eb0bd9-ddf6-4315-a806-967de25454b1--780004768
 | Plan 1 | d1eb0bd9-ddf6-4315-a806-967de25454b1--780004769
 | Plan 1 | d1eb0bd9-ddf6-4315-a806-967de25454b1--780004770
 | Plan 1 | d1eb0bd9-ddf6-4315-a806-967de25454b1--780004783
 | Plan 1 | d1eb0bd9-ddf6-4315-a806-967de25454b1--780004784
 | Plan 1 | d1eb0bd9-ddf6-4315-a806-967de25454b1--780004785
 | Plan 1 | d1eb0bd9-ddf6-4315-a806-967de25454b1--780004786
 | Plan 1 | d1eb0bd9-ddf6-4315-a806-967de25454b1--780004787
 | Plan 1 | d1eb0bd9-ddf6-4315-a806-967de25454b1--780004788
 | Plan 1 | d1eb0bd9-ddf6-4315-a806-967de25454b1--780050082
 | Plan 1 | d1eb0bd9-ddf6-4315-a806-967de25454b1--780050083
 | Plan 1 | d1eb0bd9-ddf6-4315-a806-967de25454b1--780050084
 | Plan 1 | d1eb0bd9-ddf6-4315-a806-967de25454b1--780050085
 | Plan 1 | d1eb0bd9-ddf6-4315-a806-967de25454b1--780050086
 | Plan 1 | d1eb0bd9-ddf6-4315-a806-967de25454b1--780050087
 | Plan 1 | d1eb0bd9-ddf6-4315-a806-967de25454b1--780050088
 | Plan 1 | d1eb0bd9-ddf6-4315-a806-967de25454b1--780050089
 | Plan 1 | d1eb0bd9-ddf6-4315-a806-967de25454b1--780004795
 | Plan 1 | d1eb0bd9-ddf6-4315-a806-967de25454b1--780004796
 | Plan 1 | d1eb0bd9-ddf6-4315-a806-967de25454b1--780004797
 | Plan 1 | d1eb0bd9-ddf6-4315-a806-967de25454b1--780004798
 | Plan 1 | d1eb0bd9-ddf6-4315-a806-967de25454b1--780004799
 | Plan 1 | d1eb0bd9-ddf6-4315-a806-967de25454b1--780004800
 | Plan 1 | d1eb0bd9-ddf6-4315-a806-967de25454b1--780006781
 | Plan 1 | d1eb0bd9-ddf6-4315-a806-967de25454b1--779994925
 | Plan 1 | d1eb0bd9-ddf6-4315-a806-967de25454b1--779994926
 | Plan 1 | d1eb0bd9-ddf6-4315-a806-967de25454b1--780006775
 | Plan 1 | d1eb0bd9-ddf6-4315-a806-967de25454b1--780050349
 | Plan 1 | d1eb0bd9-ddf6-4315-a806-967de25454b1--780006380
 | Plan 1 | d1eb0bd9-ddf6-4315-a806-967de25454b1--780006384
 | Plan 1 | d1eb0bd9-ddf6-4315-a806-967de25454b1--780050384
 | Plan 1 | d1eb0bd9-ddf6-4315-a806-967de25454b1--780050223
 | Plan 1 | d1eb0bd9-ddf6-4315-a806-967de25454b1--780050423
 | Plan 1 | d1eb0bd9-ddf6-4315-a806-967de25454b1--780050424
 | Plan 1 | d1eb0bd9-ddf6-4315-a806-967de25454b1--780050425
 | Plan 1 | d1eb0bd9-ddf6-4315-a806-967de25454b1--780050430
 | Plan 1 | d1eb0bd9-ddf6-4315-a806-967de25454b1--780050781
 | Plan 1 | d1eb0bd9-ddf6-4315-a806-967de25454b1--780050782
 | Plan 1 | d1eb0bd9-ddf6-4315-a806-967de25454b1--780050784
 | Plan 1 | d1eb0bd9-ddf6-4315-a806-967de25454b1--779993688
 | Plan 1 | d1eb0bd9-ddf6-4315-a806-967de25454b1--779993692
 | Plan 1 | d1eb0bd9-ddf6-4315-a806-967de25454b1--779969059
 | Plan 1 | d1eb0bd9-ddf6-4315-a806-967de25454b1--779969063
 | Plan 1 | d1eb0bd9-ddf6-4315-a806-967de25454b1--779993840
 | Plan 1 | d1eb0bd9-ddf6-4315-a806-967de25454b1--779993844
 | Plan 1 | d1eb0bd9-ddf6-4315-a806-967de25454b1--779993878
 | Plan 1 | d1eb0bd9-ddf6-4315-a806-967de25454b1--779993882
 | Plan 1 | d1eb0bd9-ddf6-4315-a806-967de25454b1--779993916
 | Plan 1 | d1eb0bd9-ddf6-4315-a806-967de25454b1--779993920
 | Plan 1 | d1eb0bd9-ddf6-4315-a806-967de25454b1--779993954
 | Plan 1 | d1eb0bd9-ddf6-4315-a806-967de25454b1--779993958
 | Plan 1 | d1eb0bd9-ddf6-4315-a806-967de25454b1--780006436
 | Plan 1 | d1eb0bd9-ddf6-4315-a806-967de25454b1--780006440
 | Plan 1 | d1eb0bd9-ddf6-4315-a806-967de25454b1--779993802
 | Plan 1 | d1eb0bd9-ddf6-4315-a806-967de25454b1--779993806
 | Plan 1 | d1eb0bd9-ddf6-4315-a806-967de25454b1--780051193
 | Plan 1 | d1eb0bd9-ddf6-4315-a806-967de25454b1--779972669
 | Plan 1 | d1eb0bd9-ddf6-4315-a806-967de25454b1--779972673
 | Plan 1 | d1eb0bd9-ddf6-4315-a806-967de25454b1--780051243
 | Plan 1 | d1eb0bd9-ddf6-4315-a806-967de25454b1--780050426
 | Plan 1 | d1eb0bd9-ddf6-4315-a806-967de25454b1--780051390
 | Plan 1 | d1eb0bd9-ddf6-4315-a806-967de25454b1--780051394
 | Plan 1 | d1eb0bd9-ddf6-4315-a806-967de25454b1--780050431
 | Plan 1 | d1eb0bd9-ddf6-4315-a806-967de25454b1--779993574
 | Plan 1 | d1eb0bd9-ddf6-4315-a806-967de25454b1--779993578
 | Plan 1 | d1eb0bd9-ddf6-4315-a806-967de25454b1--780051425
 | Plan 1 | d1eb0bd9-ddf6-4315-a806-967de25454b1--779993612
 | Plan 1 | d1eb0bd9-ddf6-4315-a806-967de25454b1--779993616
 | Plan 1 | d1eb0bd9-ddf6-4315-a806-967de25454b1--779993650
 | Plan 1 | d1eb0bd9-ddf6-4315-a806-967de25454b1--779993654
 | Plan 1 | d1eb0bd9-ddf6-4315-a806-967de25454b1--780051472
 | Plan 1 | d1eb0bd9-ddf6-4315-a806-967de25454b1--780051456
 | Plan 1 | d1eb0bd9-ddf6-4315-a806-967de25454b1--780051431
 | Plan 1 | d1eb0bd9-ddf6-4315-a806-967de25454b1--780050434
 | Plan 1 | d1eb0bd9-ddf6-4315-a806-967de25454b1--780050433
 | Plan 1 | d1eb0bd9-ddf6-4315-a806-967de25454b1--780050432
 | Plan 1 | d1eb0bd9-ddf6-4315-a806-967de25454b1--780051218
 | Plan 1 | d1eb0bd9-ddf6-4315-a806-967de25454b1--779993764
 | Plan 1 | d1eb0bd9-ddf6-4315-a806-967de25454b1--779993768
 | Plan 1 | b4870d4d-918a-46e5-81bc-d8f6664cc458--780028435
 | Plan 1 | b4870d4d-918a-46e5-81bc-d8f6664cc458--780024137
 | Plan 1 | b4870d4d-918a-46e5-81bc-d8f6664cc458--779996757
 | Plan 1 | b4870d4d-918a-46e5-81bc-d8f6664cc458--780023168
 | Plan 1 | b4870d4d-918a-46e5-81bc-d8f6664cc458--780025048
 | Plan 1 | b4870d4d-918a-46e5-81bc-d8f6664cc458--780028533
 | Plan 1 | b4870d4d-918a-46e5-81bc-d8f6664cc458--779979399
 | Plan 1 | b4870d4d-918a-46e5-81bc-d8f6664cc458--779979403
 | Plan 1 | b4870d4d-918a-46e5-81bc-d8f6664cc458--779981714
 | Plan 1 | b4870d4d-918a-46e5-81bc-d8f6664cc458--779981718
 | Plan 1 | b4870d4d-918a-46e5-81bc-d8f6664cc458--780029530
 | Plan 1 | b4870d4d-918a-46e5-81bc-d8f6664cc458--780030278
 | Plan 1 | b4870d4d-918a-46e5-81bc-d8f6664cc458--780030339
 | Plan 1 | b4870d4d-918a-46e5-81bc-d8f6664cc458--779979455
 | Plan 1 | b4870d4d-918a-46e5-81bc-d8f6664cc458--779979459
 | Plan 1 | b4870d4d-918a-46e5-81bc-d8f6664cc458--780030415
 | Plan 1 | b4870d4d-918a-46e5-81bc-d8f6664cc458--780030456
 | Plan 1 | b4870d4d-918a-46e5-81bc-d8f6664cc458--780030588
 | Plan 1 | b4870d4d-918a-46e5-81bc-d8f6664cc458--780030802
 | Plan 1 | b4870d4d-918a-46e5-81bc-d8f6664cc458--780030921
 | Plan 1 | b4870d4d-918a-46e5-81bc-d8f6664cc458--780030973
 | Plan 1 | b4870d4d-918a-46e5-81bc-d8f6664cc458--780031048
 | Plan 1 | b4870d4d-918a-46e5-81bc-d8f6664cc458--780031124
 | Plan 1 | b4870d4d-918a-46e5-81bc-d8f6664cc458--780031199
 | Plan 1 | b4870d4d-918a-46e5-81bc-d8f6664cc458--780031332
 | Plan 1 | b4870d4d-918a-46e5-81bc-d8f6664cc458--780028685
 | Plan 1 | b4870d4d-918a-46e5-81bc-d8f6664cc458--779969808
 | Plan 1 | b4870d4d-918a-46e5-81bc-d8f6664cc458--779969810
 | Plan 1 | b4870d4d-918a-46e5-81bc-d8f6664cc458--780031405
 | Plan 1 | b4870d4d-918a-46e5-81bc-d8f6664cc458--780031433
 | Plan 1 | b4870d4d-918a-46e5-81bc-d8f6664cc458--780031484
 | Plan 1 | b4870d4d-918a-46e5-81bc-d8f6664cc458--779980516
 | Plan 1 | b4870d4d-918a-46e5-81bc-d8f6664cc458--779980520
 | Plan 1 | b4870d4d-918a-46e5-81bc-d8f6664cc458--779981827
 | Plan 1 | b4870d4d-918a-46e5-81bc-d8f6664cc458--779981831
 | Plan 1 | b4870d4d-918a-46e5-81bc-d8f6664cc458--780031582
 | Plan 1 | b4870d4d-918a-46e5-81bc-d8f6664cc458--780031644
 | Plan 1 | b4870d4d-918a-46e5-81bc-d8f6664cc458--780025047
 | Plan 1 | b4870d4d-918a-46e5-81bc-d8f6664cc458--780031640
 | Plan 1 | b4870d4d-918a-46e5-81bc-d8f6664cc458--780028574
 | Plan 1 | b4870d4d-918a-46e5-81bc-d8f6664cc458--780028019
 | Plan 1 | b4870d4d-918a-46e5-81bc-d8f6664cc458--780032142
 | Plan 1 | b4870d4d-918a-46e5-81bc-d8f6664cc458--780032146
 | Plan 1 | b4870d4d-918a-46e5-81bc-d8f6664cc458--780032152
 | Plan 1 | b4870d4d-918a-46e5-81bc-d8f6664cc458--779979044
 | Plan 1 | b4870d4d-918a-46e5-81bc-d8f6664cc458--779979048
 | Plan 1 | b4870d4d-918a-46e5-81bc-d8f6664cc458--780024078
 | Plan 1 | b4870d4d-918a-46e5-81bc-d8f6664cc458--780024082
 | Plan 1 | b4870d4d-918a-46e5-81bc-d8f6664cc458--779982155
 | Plan 1 | b4870d4d-918a-46e5-81bc-d8f6664cc458--779982159
 | Plan 1 | b4870d4d-918a-46e5-81bc-d8f6664cc458--779982031
 | Plan 1 | b4870d4d-918a-46e5-81bc-d8f6664cc458--779982035
 | Plan 1 | b4870d4d-918a-46e5-81bc-d8f6664cc458--779980254
 | Plan 1 | b4870d4d-918a-46e5-81bc-d8f6664cc458--779980258
 | Plan 1 | b4870d4d-918a-46e5-81bc-d8f6664cc458--779996734
 | Plan 1 | b4870d4d-918a-46e5-81bc-d8f6664cc458--779996738
 | Plan 1 | b4870d4d-918a-46e5-81bc-d8f6664cc458--780022477
 | Plan 1 | b4870d4d-918a-46e5-81bc-d8f6664cc458--780022481
 | Plan 1 | b4870d4d-918a-46e5-81bc-d8f6664cc458--780022421
 | Plan 1 | b4870d4d-918a-46e5-81bc-d8f6664cc458--780022425
 | Plan 1 | b4870d4d-918a-46e5-81bc-d8f6664cc458--780022383
 | Plan 1 | b4870d4d-918a-46e5-81bc-d8f6664cc458--780022387
 | Plan 1 | b4870d4d-918a-46e5-81bc-d8f6664cc458--779980292
 | Plan 1 | b4870d4d-918a-46e5-81bc-d8f6664cc458--779980296
 | Plan 1 | b4870d4d-918a-46e5-81bc-d8f6664cc458--779981676
 | Plan 1 | b4870d4d-918a-46e5-81bc-d8f6664cc458--779981680
 | Plan 1 | b4870d4d-918a-46e5-81bc-d8f6664cc458--779980405
 | Plan 1 | b4870d4d-918a-46e5-81bc-d8f6664cc458--779980409
 | Plan 1 | b4870d4d-918a-46e5-81bc-d8f6664cc458--779996566
 | Plan 1 | b4870d4d-918a-46e5-81bc-d8f6664cc458--779996570
 | Plan 1 | b4870d4d-918a-46e5-81bc-d8f6664cc458--779980330
 | Plan 1 | b4870d4d-918a-46e5-81bc-d8f6664cc458--779980334
 | Plan 1 | b4870d4d-918a-46e5-81bc-d8f6664cc458--779979639
 | Plan 1 | b4870d4d-918a-46e5-81bc-d8f6664cc458--779979643
 | Plan 1 | b4870d4d-918a-46e5-81bc-d8f6664cc458--779969837
 | Plan 1 | b4870d4d-918a-46e5-81bc-d8f6664cc458--779969838
 | Plan 1 | b4870d4d-918a-46e5-81bc-d8f6664cc458--780028828
 | Plan 1 | b4870d4d-918a-46e5-81bc-d8f6664cc458--779983068
 | Plan 1 | b4870d4d-918a-46e5-81bc-d8f6664cc458--779983072
 | Plan 1 | b4870d4d-918a-46e5-81bc-d8f6664cc458--779979511
 | Plan 1 | b4870d4d-918a-46e5-81bc-d8f6664cc458--779979515
 | Plan 1 | b4870d4d-918a-46e5-81bc-d8f6664cc458--780032243
 | Plan 1 | b4870d4d-918a-46e5-81bc-d8f6664cc458--780026475
 | Plan 1 | b4870d4d-918a-46e5-81bc-d8f6664cc458--780026479
 | Plan 1 | b4870d4d-918a-46e5-81bc-d8f6664cc458--780032240
 | Plan 1 | b4870d4d-918a-46e5-81bc-d8f6664cc458--780026437
 | Plan 1 | b4870d4d-918a-46e5-81bc-d8f6664cc458--780026441
 | Plan 1 | cbab19c6-f7f3-4c25-9028-8574def17b1d--16826125
 | Plan 1 | cbab19c6-f7f3-4c25-9028-8574def17b1d--16826190
 | Plan 1 | cbab19c6-f7f3-4c25-9028-8574def17b1d--16826191
 | Plan 1 | cbab19c6-f7f3-4c25-9028-8574def17b1d--16826195
 | Plan 1 | cbab19c6-f7f3-4c25-9028-8574def17b1d--16826196
 | Plan 1 | cbab19c6-f7f3-4c25-9028-8574def17b1d--16826126
 | Plan 1 | cbab19c6-f7f3-4c25-9028-8574def17b1d--16826127
 | Plan 1 | cbab19c6-f7f3-4c25-9028-8574def17b1d--16826192
 | Plan 1 | 1b5c68a0-5855-473d-bc40-02b9771d55a8--779989732
 | Plan 1 | 1b5c68a0-5855-473d-bc40-02b9771d55a8--779989733
 | Plan 1 | 1b5c68a0-5855-473d-bc40-02b9771d55a8--779989734
 | Plan 1 | 1b5c68a0-5855-473d-bc40-02b9771d55a8--779989735
 | Plan 1 | 1b5c68a0-5855-473d-bc40-02b9771d55a8--779989736
 | Plan 1 | 1b5c68a0-5855-473d-bc40-02b9771d55a8--779989737
 | Plan 1 | 1b5c68a0-5855-473d-bc40-02b9771d55a8--779989738
 | Plan 1 | 1b5c68a0-5855-473d-bc40-02b9771d55a8--779989739
 | Plan 1 | 1b5c68a0-5855-473d-bc40-02b9771d55a8--779989742
 | Plan 1 | 1b5c68a0-5855-473d-bc40-02b9771d55a8--779989743
 | Plan 1 | 1b5c68a0-5855-473d-bc40-02b9771d55a8--779989744
 | Plan 1 | 1b5c68a0-5855-473d-bc40-02b9771d55a8--779989745
 | Plan 1 | 1b5c68a0-5855-473d-bc40-02b9771d55a8--779989746
 | Plan 1 | 1b5c68a0-5855-473d-bc40-02b9771d55a8--779989747
 | Plan 1 | 1b5c68a0-5855-473d-bc40-02b9771d55a8--779989748
 | Plan 1 | 1b5c68a0-5855-473d-bc40-02b9771d55a8--779989749
 | Plan 1 | 1b5c68a0-5855-473d-bc40-02b9771d55a8--779989750
 | Plan 1 | 1b5c68a0-5855-473d-bc40-02b9771d55a8--779989751
 | Plan 1 | 1b5c68a0-5855-473d-bc40-02b9771d55a8--779989752
 | Plan 1 | 1b5c68a0-5855-473d-bc40-02b9771d55a8--779989753
 | Plan 1 | 1b5c68a0-5855-473d-bc40-02b9771d55a8--779989754
 | Plan 1 | 1b5c68a0-5855-473d-bc40-02b9771d55a8--779989755
 | Plan 1 | 1b5c68a0-5855-473d-bc40-02b9771d55a8--779989756
 | Plan 1 | 1b5c68a0-5855-473d-bc40-02b9771d55a8--779989757
 | Plan 1 | 1b5c68a0-5855-473d-bc40-02b9771d55a8--779989758
 | Plan 1 | 1b5c68a0-5855-473d-bc40-02b9771d55a8--779989760
 | Plan 1 | 1b5c68a0-5855-473d-bc40-02b9771d55a8--779988425
 | Plan 1 | 1b5c68a0-5855-473d-bc40-02b9771d55a8--779988426
 | Plan 1 | 1b5c68a0-5855-473d-bc40-02b9771d55a8--779988427
 | Plan 1 | 1b5c68a0-5855-473d-bc40-02b9771d55a8--779988428
 | Plan 1 | 1b5c68a0-5855-473d-bc40-02b9771d55a8--779988429
 | Plan 1 | 1b5c68a0-5855-473d-bc40-02b9771d55a8--779988430
 | Plan 1 | 1b5c68a0-5855-473d-bc40-02b9771d55a8--779988431
 | Plan 1 | 1b5c68a0-5855-473d-bc40-02b9771d55a8--779988432
 | Plan 1 | 1b5c68a0-5855-473d-bc40-02b9771d55a8--779988433
 | Plan 1 | 1b5c68a0-5855-473d-bc40-02b9771d55a8--779988434
 | Plan 1 | 1b5c68a0-5855-473d-bc40-02b9771d55a8--779988435
 | Plan 1 | 1b5c68a0-5855-473d-bc40-02b9771d55a8--779988436
 | Plan 1 | 1b5c68a0-5855-473d-bc40-02b9771d55a8--779988437
 | Plan 1 | 1b5c68a0-5855-473d-bc40-02b9771d55a8--779988438
 | Plan 1 | 1b5c68a0-5855-473d-bc40-02b9771d55a8--779988439
 | Plan 1 | 1b5c68a0-5855-473d-bc40-02b9771d55a8--779988441
 | Plan 1 | 1b5c68a0-5855-473d-bc40-02b9771d55a8--779988442
 | Plan 1 | 1b5c68a0-5855-473d-bc40-02b9771d55a8--779988443
 | Plan 1 | 1b5c68a0-5855-473d-bc40-02b9771d55a8--779988444
 | Plan 1 | 1b5c68a0-5855-473d-bc40-02b9771d55a8--779988445
 | Plan 1 | 1b5c68a0-5855-473d-bc40-02b9771d55a8--779988440
 | Plan 1 | 1b5c68a0-5855-473d-bc40-02b9771d55a8--779989239
 | Plan 1 | 1b5c68a0-5855-473d-bc40-02b9771d55a8--779988461
 | Plan 1 | 1b5c68a0-5855-473d-bc40-02b9771d55a8--779988453
 | Plan 1 | 1b5c68a0-5855-473d-bc40-02b9771d55a8--779988454
 | Plan 1 | 1b5c68a0-5855-473d-bc40-02b9771d55a8--779988455
 | Plan 1 | 1b5c68a0-5855-473d-bc40-02b9771d55a8--779988456
 | Plan 1 | 1b5c68a0-5855-473d-bc40-02b9771d55a8--779988457
 | Plan 1 | 1b5c68a0-5855-473d-bc40-02b9771d55a8--779988458
 | Plan 1 | 1b5c68a0-5855-473d-bc40-02b9771d55a8--779988459
 | Plan 1 | 1b5c68a0-5855-473d-bc40-02b9771d55a8--779988938
 | Plan 1 | 1b5c68a0-5855-473d-bc40-02b9771d55a8--779988939
 | Plan 1 | 1b5c68a0-5855-473d-bc40-02b9771d55a8--779988940
 | Plan 1 | 1b5c68a0-5855-473d-bc40-02b9771d55a8--779988941
 | Plan 1 | 1b5c68a0-5855-473d-bc40-02b9771d55a8--779988942
 | Plan 1 | 1b5c68a0-5855-473d-bc40-02b9771d55a8--779988937
 | Plan 1 | 1b5c68a0-5855-473d-bc40-02b9771d55a8--779988460
 | Plan 1 | 1b5c68a0-5855-473d-bc40-02b9771d55a8--779989225
 | Plan 1 | 1b5c68a0-5855-473d-bc40-02b9771d55a8--779989226
 | Plan 1 | 1b5c68a0-5855-473d-bc40-02b9771d55a8--779989227
 | Plan 1 | 1b5c68a0-5855-473d-bc40-02b9771d55a8--779989228
 | Plan 1 | 1b5c68a0-5855-473d-bc40-02b9771d55a8--779989229
 | Plan 1 | 1b5c68a0-5855-473d-bc40-02b9771d55a8--779989230
 | Plan 1 | 1b5c68a0-5855-473d-bc40-02b9771d55a8--779989231
 | Plan 1 | 1b5c68a0-5855-473d-bc40-02b9771d55a8--779989232
 | Plan 1 | 1b5c68a0-5855-473d-bc40-02b9771d55a8--779989233
 | Plan 1 | 1b5c68a0-5855-473d-bc40-02b9771d55a8--779989234
 | Plan 1 | 1b5c68a0-5855-473d-bc40-02b9771d55a8--779989235
 | Plan 1 | 1b5c68a0-5855-473d-bc40-02b9771d55a8--779989236
 | Plan 1 | 1b5c68a0-5855-473d-bc40-02b9771d55a8--779989237
 | Plan 1 | 1b5c68a0-5855-473d-bc40-02b9771d55a8--779989238
 | Plan 1 | 1b5c68a0-5855-473d-bc40-02b9771d55a8--779992097
 | Plan 1 | 1b5c68a0-5855-473d-bc40-02b9771d55a8--779992100
 | Plan 1 | 1b5c68a0-5855-473d-bc40-02b9771d55a8--779993048
 | Plan 1 | 1b5c68a0-5855-473d-bc40-02b9771d55a8--779988544
 | Plan 1 | 1b5c68a0-5855-473d-bc40-02b9771d55a8--779988545
 | Plan 1 | 1b5c68a0-5855-473d-bc40-02b9771d55a8--779988546
 | Plan 1 | 1b5c68a0-5855-473d-bc40-02b9771d55a8--779988547
 | Plan 1 | 1b5c68a0-5855-473d-bc40-02b9771d55a8--779988548
 | Plan 1 | 1b5c68a0-5855-473d-bc40-02b9771d55a8--779988549
 | Plan 1 | 1b5c68a0-5855-473d-bc40-02b9771d55a8--779988550
 | Plan 1 | 1b5c68a0-5855-473d-bc40-02b9771d55a8--779989763
 | Plan 1 | 1b5c68a0-5855-473d-bc40-02b9771d55a8--779934746
 | Plan 1 | 1b5c68a0-5855-473d-bc40-02b9771d55a8--779946384
 | Plan 1 | 1b5c68a0-5855-473d-bc40-02b9771d55a8--779958012
 | Plan 1 | 1b5c68a0-5855-473d-bc40-02b9771d55a8--779988530
 | Plan 1 | 1b5c68a0-5855-473d-bc40-02b9771d55a8--779988531
 | Plan 1 | 1b5c68a0-5855-473d-bc40-02b9771d55a8--779988532
 | Plan 1 | 1b5c68a0-5855-473d-bc40-02b9771d55a8--779988533
 | Plan 1 | 1b5c68a0-5855-473d-bc40-02b9771d55a8--779988534
 | Plan 1 | 1b5c68a0-5855-473d-bc40-02b9771d55a8--779988535
 | Plan 1 | 1b5c68a0-5855-473d-bc40-02b9771d55a8--779988536
 | Plan 1 | 1b5c68a0-5855-473d-bc40-02b9771d55a8--779988537
 | Plan 1 | 1b5c68a0-5855-473d-bc40-02b9771d55a8--779988538
 | Plan 1 | 1b5c68a0-5855-473d-bc40-02b9771d55a8--779988539
 | Plan 1 | 1b5c68a0-5855-473d-bc40-02b9771d55a8--779988540
 | Plan 1 | 1b5c68a0-5855-473d-bc40-02b9771d55a8--779988541
 | Plan 1 | 1b5c68a0-5855-473d-bc40-02b9771d55a8--779988542
 | Plan 1 | 1b5c68a0-5855-473d-bc40-02b9771d55a8--779988543
 | Plan 1 | 1b5c68a0-5855-473d-bc40-02b9771d55a8--779989766
 | Plan 1 | 1b5c68a0-5855-473d-bc40-02b9771d55a8--779993724
 | Plan 1 | 1b5c68a0-5855-473d-bc40-02b9771d55a8--779993725
 | Plan 1 | 1b5c68a0-5855-473d-bc40-02b9771d55a8--779993726
 | Plan 1 | 1b5c68a0-5855-473d-bc40-02b9771d55a8--779993727
 | Plan 1 | 1b5c68a0-5855-473d-bc40-02b9771d55a8--779993728
 | Plan 1 | 1b5c68a0-5855-473d-bc40-02b9771d55a8--779993729
 | Plan 1 | 1b5c68a0-5855-473d-bc40-02b9771d55a8--779993730
 | Plan 1 | 1b5c68a0-5855-473d-bc40-02b9771d55a8--779993731
 | Plan 1 | 1b5c68a0-5855-473d-bc40-02b9771d55a8--779993732
 | Plan 1 | 1b5c68a0-5855-473d-bc40-02b9771d55a8--779993733
 | Plan 1 | 1b5c68a0-5855-473d-bc40-02b9771d55a8--779993734
 | Plan 1 | 1b5c68a0-5855-473d-bc40-02b9771d55a8--779993735
 | Plan 1 | 1b5c68a0-5855-473d-bc40-02b9771d55a8--779993736
 | Plan 1 | 1b5c68a0-5855-473d-bc40-02b9771d55a8--779993737
 | Plan 1 | 1b5c68a0-5855-473d-bc40-02b9771d55a8--779993738
 | Plan 1 | 1b5c68a0-5855-473d-bc40-02b9771d55a8--779993739
 | Plan 1 | 1b5c68a0-5855-473d-bc40-02b9771d55a8--779993804
 | Plan 1 | 1b5c68a0-5855-473d-bc40-02b9771d55a8--779993756
 | Plan 1 | 1b5c68a0-5855-473d-bc40-02b9771d55a8--779993757
 | Plan 1 | 1b5c68a0-5855-473d-bc40-02b9771d55a8--779993758
 | Plan 1 | 1b5c68a0-5855-473d-bc40-02b9771d55a8--779993759
 | Plan 1 | 1b5c68a0-5855-473d-bc40-02b9771d55a8--779993760
 | Plan 1 | 1b5c68a0-5855-473d-bc40-02b9771d55a8--779993761
 | Plan 1 | 1b5c68a0-5855-473d-bc40-02b9771d55a8--779993762
 | Plan 1 | 1b5c68a0-5855-473d-bc40-02b9771d55a8--779993763
 | Plan 1 | 1b5c68a0-5855-473d-bc40-02b9771d55a8--779993772
 | Plan 1 | 1b5c68a0-5855-473d-bc40-02b9771d55a8--779993773
 | Plan 1 | 1b5c68a0-5855-473d-bc40-02b9771d55a8--779993774
 | Plan 1 | 1b5c68a0-5855-473d-bc40-02b9771d55a8--779993775
 | Plan 1 | 1b5c68a0-5855-473d-bc40-02b9771d55a8--779993776
 | Plan 1 | 1b5c68a0-5855-473d-bc40-02b9771d55a8--779993777
 | Plan 1 | 1b5c68a0-5855-473d-bc40-02b9771d55a8--779993778
 | Plan 1 | 1b5c68a0-5855-473d-bc40-02b9771d55a8--779993779
 | Plan 1 | 1b5c68a0-5855-473d-bc40-02b9771d55a8--779993807
 | Plan 1 | 1b5c68a0-5855-473d-bc40-02b9771d55a8--779993808
 | Plan 1 | 1b5c68a0-5855-473d-bc40-02b9771d55a8--779993812
 | Plan 1 | 1b5c68a0-5855-473d-bc40-02b9771d55a8--779993813
 | Plan 1 | 1b5c68a0-5855-473d-bc40-02b9771d55a8--779993814
 | Plan 1 | 1b5c68a0-5855-473d-bc40-02b9771d55a8--779993815
 | Plan 1 | 1b5c68a0-5855-473d-bc40-02b9771d55a8--779993816
 | Plan 1 | 1b5c68a0-5855-473d-bc40-02b9771d55a8--779993817
 | Plan 1 | 1b5c68a0-5855-473d-bc40-02b9771d55a8--779993818
 | Plan 1 | 1b5c68a0-5855-473d-bc40-02b9771d55a8--779993819
 | Plan 1 | 1b5c68a0-5855-473d-bc40-02b9771d55a8--779993820
 | Plan 1 | 1b5c68a0-5855-473d-bc40-02b9771d55a8--779993821
 | Plan 1 | 1b5c68a0-5855-473d-bc40-02b9771d55a8--779993822
 | Plan 1 | 1b5c68a0-5855-473d-bc40-02b9771d55a8--779993823
 | Plan 1 | 1b5c68a0-5855-473d-bc40-02b9771d55a8--779993824
 | Plan 1 | 1b5c68a0-5855-473d-bc40-02b9771d55a8--779993825
 | Plan 1 | 1b5c68a0-5855-473d-bc40-02b9771d55a8--779993826
 | Plan 1 | 1b5c68a0-5855-473d-bc40-02b9771d55a8--779993827
 | Plan 1 | 1b5c68a0-5855-473d-bc40-02b9771d55a8--779993740
 | Plan 1 | 1b5c68a0-5855-473d-bc40-02b9771d55a8--779993741
 | Plan 1 | 1b5c68a0-5855-473d-bc40-02b9771d55a8--779993742
 | Plan 1 | 1b5c68a0-5855-473d-bc40-02b9771d55a8--779993743
 | Plan 1 | 1b5c68a0-5855-473d-bc40-02b9771d55a8--779993744
 | Plan 1 | 1b5c68a0-5855-473d-bc40-02b9771d55a8--779993745
 | Plan 1 | 1b5c68a0-5855-473d-bc40-02b9771d55a8--779993746
 | Plan 1 | 1b5c68a0-5855-473d-bc40-02b9771d55a8--779993747
 | Plan 1 | 1b5c68a0-5855-473d-bc40-02b9771d55a8--779993748
 | Plan 1 | 1b5c68a0-5855-473d-bc40-02b9771d55a8--779993749
 | Plan 1 | 1b5c68a0-5855-473d-bc40-02b9771d55a8--779993750
 | Plan 1 | 1b5c68a0-5855-473d-bc40-02b9771d55a8--779993751
 | Plan 1 | 1b5c68a0-5855-473d-bc40-02b9771d55a8--779993752
 | Plan 1 | 1b5c68a0-5855-473d-bc40-02b9771d55a8--779993753
 | Plan 1 | 1b5c68a0-5855-473d-bc40-02b9771d55a8--779993754
 | Plan 1 | 1b5c68a0-5855-473d-bc40-02b9771d55a8--779993755
 | Plan 1 | 1b5c68a0-5855-473d-bc40-02b9771d55a8--779993805
 | Plan 1 | 1b5c68a0-5855-473d-bc40-02b9771d55a8--779993806
 | Plan 1 | 1b5c68a0-5855-473d-bc40-02b9771d55a8--779993764
 | Plan 1 | 1b5c68a0-5855-473d-bc40-02b9771d55a8--779993765
 | Plan 1 | 1b5c68a0-5855-473d-bc40-02b9771d55a8--779993766
 | Plan 1 | 1b5c68a0-5855-473d-bc40-02b9771d55a8--779993767
 | Plan 1 | 1b5c68a0-5855-473d-bc40-02b9771d55a8--779993768
 | Plan 1 | 1b5c68a0-5855-473d-bc40-02b9771d55a8--779993769
 | Plan 1 | 1b5c68a0-5855-473d-bc40-02b9771d55a8--779993770
 | Plan 1 | 1b5c68a0-5855-473d-bc40-02b9771d55a8--779993771
 | Plan 1 | 1b5c68a0-5855-473d-bc40-02b9771d55a8--779993780
 | Plan 1 | 1b5c68a0-5855-473d-bc40-02b9771d55a8--779993781
 | Plan 1 | 1b5c68a0-5855-473d-bc40-02b9771d55a8--779993782
 | Plan 1 | 1b5c68a0-5855-473d-bc40-02b9771d55a8--779993783
 | Plan 1 | 1b5c68a0-5855-473d-bc40-02b9771d55a8--779993784
 | Plan 1 | 1b5c68a0-5855-473d-bc40-02b9771d55a8--779993785
 | Plan 1 | 1b5c68a0-5855-473d-bc40-02b9771d55a8--779993786
 | Plan 1 | 1b5c68a0-5855-473d-bc40-02b9771d55a8--779993787
 | Plan 1 | 1b5c68a0-5855-473d-bc40-02b9771d55a8--779993809
 | Plan 1 | 1b5c68a0-5855-473d-bc40-02b9771d55a8--779993810
 | Plan 1 | 1b5c68a0-5855-473d-bc40-02b9771d55a8--779993811
 | Plan 1 | 1b5c68a0-5855-473d-bc40-02b9771d55a8--779993828
 | Plan 1 | 1b5c68a0-5855-473d-bc40-02b9771d55a8--779993829
 | Plan 1 | 1b5c68a0-5855-473d-bc40-02b9771d55a8--779993830
 | Plan 1 | 1b5c68a0-5855-473d-bc40-02b9771d55a8--779993831
 | Plan 1 | 1b5c68a0-5855-473d-bc40-02b9771d55a8--779993832
 | Plan 1 | 1b5c68a0-5855-473d-bc40-02b9771d55a8--779993833
 | Plan 1 | 1b5c68a0-5855-473d-bc40-02b9771d55a8--779993834
 | Plan 1 | 1b5c68a0-5855-473d-bc40-02b9771d55a8--779993835
 | Plan 1 | 1b5c68a0-5855-473d-bc40-02b9771d55a8--779993836
 | Plan 1 | 1b5c68a0-5855-473d-bc40-02b9771d55a8--779993837
 | Plan 1 | 1b5c68a0-5855-473d-bc40-02b9771d55a8--779993838
 | Plan 1 | 1b5c68a0-5855-473d-bc40-02b9771d55a8--779993839
 | Plan 1 | 1b5c68a0-5855-473d-bc40-02b9771d55a8--779993840
 | Plan 1 | 1b5c68a0-5855-473d-bc40-02b9771d55a8--779993841
 | Plan 1 | 1b5c68a0-5855-473d-bc40-02b9771d55a8--779993842
 | Plan 1 | 1b5c68a0-5855-473d-bc40-02b9771d55a8--779993843
 | Plan 1 | 1b5c68a0-5855-473d-bc40-02b9771d55a8--779993788
 | Plan 1 | 1b5c68a0-5855-473d-bc40-02b9771d55a8--779993789
 | Plan 1 | 1b5c68a0-5855-473d-bc40-02b9771d55a8--779993790
 | Plan 1 | 1b5c68a0-5855-473d-bc40-02b9771d55a8--779993791
 | Plan 1 | 1b5c68a0-5855-473d-bc40-02b9771d55a8--779993792
 | Plan 1 | 1b5c68a0-5855-473d-bc40-02b9771d55a8--779993793
 | Plan 1 | 1b5c68a0-5855-473d-bc40-02b9771d55a8--779993794
 | Plan 1 | 1b5c68a0-5855-473d-bc40-02b9771d55a8--779993795
 | Plan 1 | 1b5c68a0-5855-473d-bc40-02b9771d55a8--779993796
 | Plan 1 | 1b5c68a0-5855-473d-bc40-02b9771d55a8--779993797
 | Plan 1 | 1b5c68a0-5855-473d-bc40-02b9771d55a8--779993798
 | Plan 1 | 1b5c68a0-5855-473d-bc40-02b9771d55a8--779993799
 | Plan 1 | 1b5c68a0-5855-473d-bc40-02b9771d55a8--779993800
 | Plan 1 | 1b5c68a0-5855-473d-bc40-02b9771d55a8--779993801
 | Plan 1 | 1b5c68a0-5855-473d-bc40-02b9771d55a8--779993802
 | Plan 1 | 1b5c68a0-5855-473d-bc40-02b9771d55a8--779993803
 | Plan 1 | 1b5c68a0-5855-473d-bc40-02b9771d55a8--779993844
 | Plan 1 | 1b5c68a0-5855-473d-bc40-02b9771d55a8--779993845
 | Plan 1 | 1b5c68a0-5855-473d-bc40-02b9771d55a8--779993846
 | Plan 1 | 1b5c68a0-5855-473d-bc40-02b9771d55a8--779993847
 | Plan 1 | 1b5c68a0-5855-473d-bc40-02b9771d55a8--779993848
 | Plan 1 | 1b5c68a0-5855-473d-bc40-02b9771d55a8--779993849
 | Plan 1 | 1b5c68a0-5855-473d-bc40-02b9771d55a8--779993850
 | Plan 1 | 1b5c68a0-5855-473d-bc40-02b9771d55a8--779993851
 | Plan 1 | 1b5c68a0-5855-473d-bc40-02b9771d55a8--779993852
 | Plan 1 | 1b5c68a0-5855-473d-bc40-02b9771d55a8--779993853
 | Plan 1 | 1b5c68a0-5855-473d-bc40-02b9771d55a8--779993854
 | Plan 1 | 1b5c68a0-5855-473d-bc40-02b9771d55a8--779993855
 | Plan 1 | 1b5c68a0-5855-473d-bc40-02b9771d55a8--779993856
 | Plan 1 | 1b5c68a0-5855-473d-bc40-02b9771d55a8--779993857
 | Plan 1 | 1b5c68a0-5855-473d-bc40-02b9771d55a8--779993858
 | Plan 1 | 1b5c68a0-5855-473d-bc40-02b9771d55a8--779993859
 | Plan 1 | 1b5c68a0-5855-473d-bc40-02b9771d55a8--779923479
 | Plan 1 | 1b5c68a0-5855-473d-bc40-02b9771d55a8--779923480
 | Plan 1 | 1b5c68a0-5855-473d-bc40-02b9771d55a8--779923481
 | Plan 1 | 1b5c68a0-5855-473d-bc40-02b9771d55a8--779923482
 | Plan 1 | 1b5c68a0-5855-473d-bc40-02b9771d55a8--779923483
 | Plan 1 | 1b5c68a0-5855-473d-bc40-02b9771d55a8--779923484
 | Plan 1 | 1b5c68a0-5855-473d-bc40-02b9771d55a8--779923485
 | Plan 1 | 1b5c68a0-5855-473d-bc40-02b9771d55a8--779923486
 | Plan 1 | 1b5c68a0-5855-473d-bc40-02b9771d55a8--779923490
 | Plan 1 | 1b5c68a0-5855-473d-bc40-02b9771d55a8--779923491
 | Plan 1 | 1b5c68a0-5855-473d-bc40-02b9771d55a8--779923492
 | Plan 1 | 1b5c68a0-5855-473d-bc40-02b9771d55a8--779923487
 | Plan 1 | 1b5c68a0-5855-473d-bc40-02b9771d55a8--779923488
 | Plan 1 | 1b5c68a0-5855-473d-bc40-02b9771d55a8--779923489
 | Plan 1 | 1b5c68a0-5855-473d-bc40-02b9771d55a8--779988411
 | Plan 1 | 1b5c68a0-5855-473d-bc40-02b9771d55a8--779988412
 | Plan 1 | 1b5c68a0-5855-473d-bc40-02b9771d55a8--779988413
 | Plan 1 | 1b5c68a0-5855-473d-bc40-02b9771d55a8--779988414
 | Plan 1 | 1b5c68a0-5855-473d-bc40-02b9771d55a8--779988415
 | Plan 1 | 1b5c68a0-5855-473d-bc40-02b9771d55a8--779988416
 | Plan 1 | 1b5c68a0-5855-473d-bc40-02b9771d55a8--779988417
 | Plan 1 | 1b5c68a0-5855-473d-bc40-02b9771d55a8--779988418
 | Plan 1 | 1b5c68a0-5855-473d-bc40-02b9771d55a8--779988419
 | Plan 1 | 1b5c68a0-5855-473d-bc40-02b9771d55a8--779988420
 | Plan 1 | 1b5c68a0-5855-473d-bc40-02b9771d55a8--779988470
 | Plan 1 | 1b5c68a0-5855-473d-bc40-02b9771d55a8--779988471
 | Plan 1 | 1b5c68a0-5855-473d-bc40-02b9771d55a8--779988474
 | Plan 1 | 1b5c68a0-5855-473d-bc40-02b9771d55a8--779988421
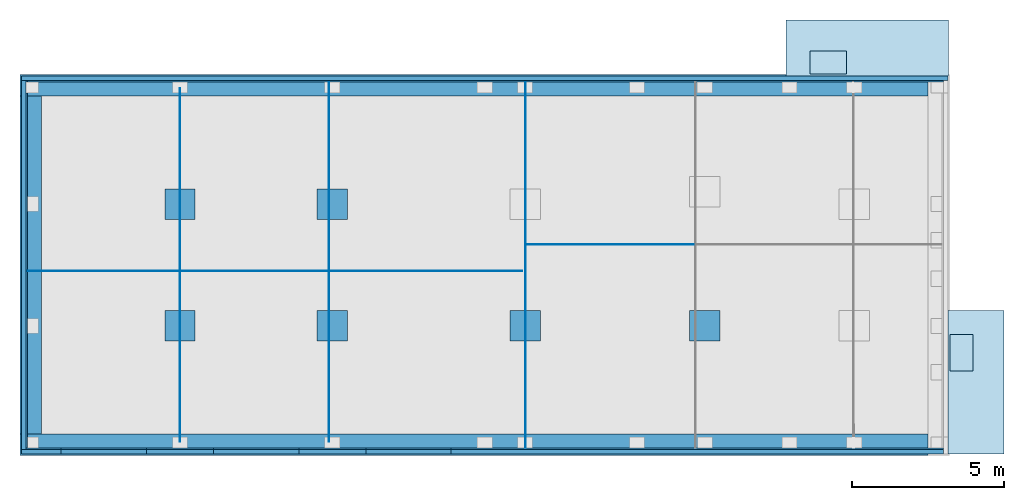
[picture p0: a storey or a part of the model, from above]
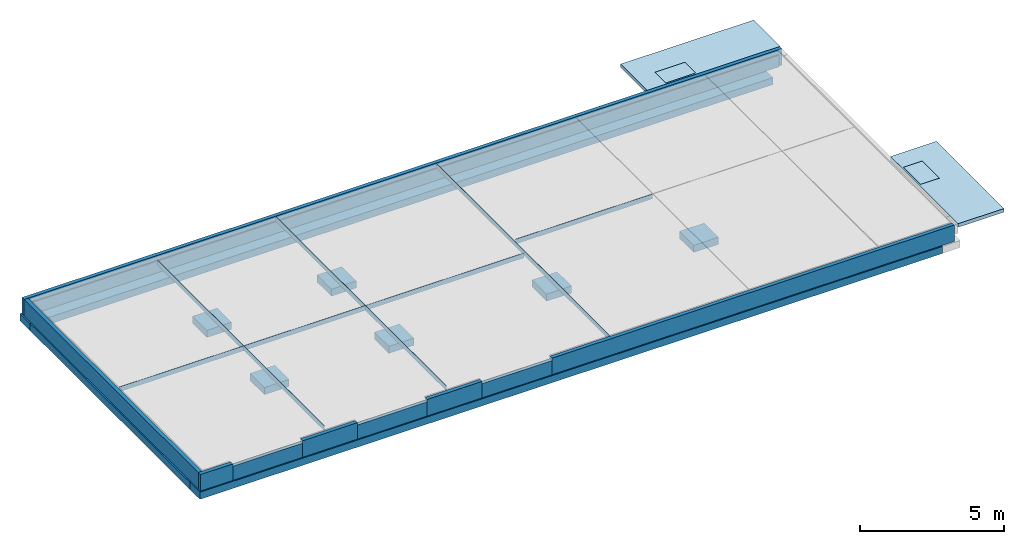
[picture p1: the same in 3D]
Properties of the parts of a building model (IFC2X3), part 2 of 7

# IfcAnnotation (2236)
Name | In | NOI_UUID
 | Plan 1 | 1b5c68a0-5855-473d-bc40-02b9771d55a8--779988422
 | Plan 1 | 1b5c68a0-5855-473d-bc40-02b9771d55a8--779988423
 | Plan 1 | 1b5c68a0-5855-473d-bc40-02b9771d55a8--779988424
 | Plan 1 | 1b5c68a0-5855-473d-bc40-02b9771d55a8--779993070
 | Plan 1 | 1b5c68a0-5855-473d-bc40-02b9771d55a8--779993071
 | Plan 1 | 1b5c68a0-5855-473d-bc40-02b9771d55a8--779993072
 | Plan 1 | 1b5c68a0-5855-473d-bc40-02b9771d55a8--779993073
 | Plan 1 | 1b5c68a0-5855-473d-bc40-02b9771d55a8--779993074
 | Plan 1 | 1b5c68a0-5855-473d-bc40-02b9771d55a8--779993075
 | Plan 1 | 1b5c68a0-5855-473d-bc40-02b9771d55a8--779993076
 | Plan 1 | 1b5c68a0-5855-473d-bc40-02b9771d55a8--779993077
 | Plan 1 | 1b5c68a0-5855-473d-bc40-02b9771d55a8--779993078
 | Plan 1 | 1b5c68a0-5855-473d-bc40-02b9771d55a8--779993079
 | Plan 1 | 1b5c68a0-5855-473d-bc40-02b9771d55a8--779993080
 | Plan 1 | 1b5c68a0-5855-473d-bc40-02b9771d55a8--779993081
 | Plan 1 | 1b5c68a0-5855-473d-bc40-02b9771d55a8--779993082
 | Plan 1 | 1b5c68a0-5855-473d-bc40-02b9771d55a8--779993083
 | Plan 1 | 1b5c68a0-5855-473d-bc40-02b9771d55a8--779993084
 | Plan 1 | 1b5c68a0-5855-473d-bc40-02b9771d55a8--779993085
 | Plan 1 | 1b5c68a0-5855-473d-bc40-02b9771d55a8--779993086
 | Plan 1 | 1b5c68a0-5855-473d-bc40-02b9771d55a8--779993087
 | Plan 1 | 1b5c68a0-5855-473d-bc40-02b9771d55a8--779993088
 | Plan 1 | 1b5c68a0-5855-473d-bc40-02b9771d55a8--779993089
 | Plan 1 | 1b5c68a0-5855-473d-bc40-02b9771d55a8--779993090
 | Plan 1 | 1b5c68a0-5855-473d-bc40-02b9771d55a8--779993091
 | Plan 1 | 1b5c68a0-5855-473d-bc40-02b9771d55a8--779993092
 | Plan 1 | 1b5c68a0-5855-473d-bc40-02b9771d55a8--779993093
 | Plan 1 | 1b5c68a0-5855-473d-bc40-02b9771d55a8--779993094
 | Plan 1 | 1b5c68a0-5855-473d-bc40-02b9771d55a8--779993095
 | Plan 1 | 1b5c68a0-5855-473d-bc40-02b9771d55a8--779993096
 | Plan 1 | 1b5c68a0-5855-473d-bc40-02b9771d55a8--779993097
 | Plan 1 | 1b5c68a0-5855-473d-bc40-02b9771d55a8--779993098
 | Plan 1 | 1b5c68a0-5855-473d-bc40-02b9771d55a8--779993099
 | Plan 1 | 1b5c68a0-5855-473d-bc40-02b9771d55a8--779988501
 | Plan 1 | 1b5c68a0-5855-473d-bc40-02b9771d55a8--779988502
 | Plan 1 | 1b5c68a0-5855-473d-bc40-02b9771d55a8--779988503
 | Plan 1 | 1b5c68a0-5855-473d-bc40-02b9771d55a8--779988504
 | Plan 1 | 1b5c68a0-5855-473d-bc40-02b9771d55a8--779988505
 | Plan 1 | 1b5c68a0-5855-473d-bc40-02b9771d55a8--779988506
 | Plan 1 | 1b5c68a0-5855-473d-bc40-02b9771d55a8--779988507
 | Plan 1 | 1b5c68a0-5855-473d-bc40-02b9771d55a8--779988508
 | Plan 1 | 1b5c68a0-5855-473d-bc40-02b9771d55a8--779988509
 | Plan 1 | 1b5c68a0-5855-473d-bc40-02b9771d55a8--779988510
 | Plan 1 | 1b5c68a0-5855-473d-bc40-02b9771d55a8--779988511
 | Plan 1 | 1b5c68a0-5855-473d-bc40-02b9771d55a8--779988512
 | Plan 1 | 1b5c68a0-5855-473d-bc40-02b9771d55a8--779988513
 | Plan 1 | 1b5c68a0-5855-473d-bc40-02b9771d55a8--779988514
 | Plan 1 | 1b5c68a0-5855-473d-bc40-02b9771d55a8--779988515
 | Plan 1 | 1b5c68a0-5855-473d-bc40-02b9771d55a8--779988516
 | Plan 1 | 1b5c68a0-5855-473d-bc40-02b9771d55a8--779988517
 | Plan 1 | 1b5c68a0-5855-473d-bc40-02b9771d55a8--779988518
 | Plan 1 | 1b5c68a0-5855-473d-bc40-02b9771d55a8--779988519
 | Plan 1 | 1b5c68a0-5855-473d-bc40-02b9771d55a8--779988520
 | Plan 1 | 1b5c68a0-5855-473d-bc40-02b9771d55a8--779988521
 | Plan 1 | 1b5c68a0-5855-473d-bc40-02b9771d55a8--779988522
 | Plan 1 | 1b5c68a0-5855-473d-bc40-02b9771d55a8--779988529
 | Plan 1 | 1b5c68a0-5855-473d-bc40-02b9771d55a8--779988593
 | Plan 1 | 1b5c68a0-5855-473d-bc40-02b9771d55a8--779988594
 | Plan 1 | 1b5c68a0-5855-473d-bc40-02b9771d55a8--779988595
 | Plan 1 | 1b5c68a0-5855-473d-bc40-02b9771d55a8--779988596
 | Plan 1 | 1b5c68a0-5855-473d-bc40-02b9771d55a8--779988597
 | Plan 1 | 1b5c68a0-5855-473d-bc40-02b9771d55a8--779988598
 | Plan 1 | 1b5c68a0-5855-473d-bc40-02b9771d55a8--779988599
 | Plan 1 | 1b5c68a0-5855-473d-bc40-02b9771d55a8--779989769
 | Plan 1 | 1b5c68a0-5855-473d-bc40-02b9771d55a8--780021406
 | Plan 1 | 1b5c68a0-5855-473d-bc40-02b9771d55a8--780021407
 | Plan 1 | 1b5c68a0-5855-473d-bc40-02b9771d55a8--780021408
 | Plan 1 | 1b5c68a0-5855-473d-bc40-02b9771d55a8--780021409
 | Plan 1 | 1b5c68a0-5855-473d-bc40-02b9771d55a8--780021410
 | Plan 1 | 1b5c68a0-5855-473d-bc40-02b9771d55a8--780021411
 | Plan 1 | 1b5c68a0-5855-473d-bc40-02b9771d55a8--780021412
 | Plan 1 | 1b5c68a0-5855-473d-bc40-02b9771d55a8--780021413
 | Plan 1 | 1b5c68a0-5855-473d-bc40-02b9771d55a8--780021414
 | Plan 1 | 1b5c68a0-5855-473d-bc40-02b9771d55a8--780021415
 | Plan 1 | 1b5c68a0-5855-473d-bc40-02b9771d55a8--780021416
 | Plan 1 | 1b5c68a0-5855-473d-bc40-02b9771d55a8--780021417
 | Plan 1 | 1b5c68a0-5855-473d-bc40-02b9771d55a8--780021418
 | Plan 1 | 1b5c68a0-5855-473d-bc40-02b9771d55a8--780021419
 | Plan 1 | 1b5c68a0-5855-473d-bc40-02b9771d55a8--780021420
 | Plan 1 | 1b5c68a0-5855-473d-bc40-02b9771d55a8--779989519
 | Plan 1 | 1b5c68a0-5855-473d-bc40-02b9771d55a8--779989520
 | Plan 1 | 1b5c68a0-5855-473d-bc40-02b9771d55a8--779989521
 | Plan 1 | 1b5c68a0-5855-473d-bc40-02b9771d55a8--779989522
 | Plan 1 | 1b5c68a0-5855-473d-bc40-02b9771d55a8--779989523
 | Plan 1 | 1b5c68a0-5855-473d-bc40-02b9771d55a8--779989524
 | Plan 1 | 1b5c68a0-5855-473d-bc40-02b9771d55a8--779989525
 | Plan 1 | 1b5c68a0-5855-473d-bc40-02b9771d55a8--779989526
 | Plan 1 | 1b5c68a0-5855-473d-bc40-02b9771d55a8--779989527
 | Plan 1 | 1b5c68a0-5855-473d-bc40-02b9771d55a8--779989528
 | Plan 1 | 1b5c68a0-5855-473d-bc40-02b9771d55a8--779988479
 | Plan 1 | 1b5c68a0-5855-473d-bc40-02b9771d55a8--779988480
 | Plan 1 | 1b5c68a0-5855-473d-bc40-02b9771d55a8--779988483
 | Plan 1 | 1b5c68a0-5855-473d-bc40-02b9771d55a8--779988499
 | Plan 1 | 1b5c68a0-5855-473d-bc40-02b9771d55a8--779988500
 | Plan 1 | 1b5c68a0-5855-473d-bc40-02b9771d55a8--779988484
 | Plan 1 | 1b5c68a0-5855-473d-bc40-02b9771d55a8--779988485
 | Plan 1 | 1b5c68a0-5855-473d-bc40-02b9771d55a8--779988486
 | Plan 1 | 1b5c68a0-5855-473d-bc40-02b9771d55a8--779988487
 | Plan 1 | 1b5c68a0-5855-473d-bc40-02b9771d55a8--779988671
 | Plan 1 | 1b5c68a0-5855-473d-bc40-02b9771d55a8--779988672
 | Plan 1 | 1b5c68a0-5855-473d-bc40-02b9771d55a8--779988673
 | Plan 1 | 1b5c68a0-5855-473d-bc40-02b9771d55a8--779988674
 | Plan 1 | 1b5c68a0-5855-473d-bc40-02b9771d55a8--779988675
 | Plan 1 | 1b5c68a0-5855-473d-bc40-02b9771d55a8--779988676
 | Plan 1 | 1b5c68a0-5855-473d-bc40-02b9771d55a8--779988677
 | Plan 1 | 1b5c68a0-5855-473d-bc40-02b9771d55a8--779988678
 | Plan 1 | 1b5c68a0-5855-473d-bc40-02b9771d55a8--779988679
 | Plan 1 | 1b5c68a0-5855-473d-bc40-02b9771d55a8--779988680
 | Plan 1 | 1b5c68a0-5855-473d-bc40-02b9771d55a8--779988681
 | Plan 1 | 1b5c68a0-5855-473d-bc40-02b9771d55a8--779988682
 | Plan 1 | 1b5c68a0-5855-473d-bc40-02b9771d55a8--779988683
 | Plan 1 | 1b5c68a0-5855-473d-bc40-02b9771d55a8--779988684
 | Plan 1 | 1b5c68a0-5855-473d-bc40-02b9771d55a8--779988685
 | Plan 1 | 1b5c68a0-5855-473d-bc40-02b9771d55a8--779988686
 | Plan 1 | 1b5c68a0-5855-473d-bc40-02b9771d55a8--779988687
 | Plan 1 | 1b5c68a0-5855-473d-bc40-02b9771d55a8--779988688
 | Plan 1 | 1b5c68a0-5855-473d-bc40-02b9771d55a8--779988689
 | Plan 1 | 1b5c68a0-5855-473d-bc40-02b9771d55a8--779988690
 | Plan 1 | 1b5c68a0-5855-473d-bc40-02b9771d55a8--779988691
 | Plan 1 | 1b5c68a0-5855-473d-bc40-02b9771d55a8--779988692
 | Plan 1 | 1b5c68a0-5855-473d-bc40-02b9771d55a8--779988697
 | Plan 1 | 1b5c68a0-5855-473d-bc40-02b9771d55a8--779988698
 | Plan 1 | 1b5c68a0-5855-473d-bc40-02b9771d55a8--779988699
 | Plan 1 | 1b5c68a0-5855-473d-bc40-02b9771d55a8--779988700
 | Plan 1 | 1b5c68a0-5855-473d-bc40-02b9771d55a8--779988705
 | Plan 1 | 1b5c68a0-5855-473d-bc40-02b9771d55a8--779988707
 | Plan 1 | 1b5c68a0-5855-473d-bc40-02b9771d55a8--779988708
 | Plan 1 | 1b5c68a0-5855-473d-bc40-02b9771d55a8--779988709
 | Plan 1 | 1b5c68a0-5855-473d-bc40-02b9771d55a8--779988710
 | Plan 1 | 1b5c68a0-5855-473d-bc40-02b9771d55a8--779988711
 | Plan 1 | 1b5c68a0-5855-473d-bc40-02b9771d55a8--779988712
 | Plan 1 | 1b5c68a0-5855-473d-bc40-02b9771d55a8--779988722
 | Plan 1 | 1b5c68a0-5855-473d-bc40-02b9771d55a8--779988726
 | Plan 1 | 1b5c68a0-5855-473d-bc40-02b9771d55a8--779988749
 | Plan 1 | 1b5c68a0-5855-473d-bc40-02b9771d55a8--779988750
 | Plan 1 | 1b5c68a0-5855-473d-bc40-02b9771d55a8--779988751
 | Plan 1 | 1b5c68a0-5855-473d-bc40-02b9771d55a8--779988752
 | Plan 1 | 1b5c68a0-5855-473d-bc40-02b9771d55a8--779988753
 | Plan 1 | 1b5c68a0-5855-473d-bc40-02b9771d55a8--779988754
 | Plan 1 | 1b5c68a0-5855-473d-bc40-02b9771d55a8--779988756
 | Plan 1 | 1b5c68a0-5855-473d-bc40-02b9771d55a8--779988757
 | Plan 1 | 1b5c68a0-5855-473d-bc40-02b9771d55a8--779988758
 | Plan 1 | 1b5c68a0-5855-473d-bc40-02b9771d55a8--779988759
 | Plan 1 | 1b5c68a0-5855-473d-bc40-02b9771d55a8--779988760
 | Plan 1 | 1b5c68a0-5855-473d-bc40-02b9771d55a8--779988761
 | Plan 1 | 1b5c68a0-5855-473d-bc40-02b9771d55a8--779988762
 | Plan 1 | 1b5c68a0-5855-473d-bc40-02b9771d55a8--779988763
 | Plan 1 | 1b5c68a0-5855-473d-bc40-02b9771d55a8--779988764
 | Plan 1 | 1b5c68a0-5855-473d-bc40-02b9771d55a8--779988765
 | Plan 1 | 1b5c68a0-5855-473d-bc40-02b9771d55a8--779988766
 | Plan 1 | 1b5c68a0-5855-473d-bc40-02b9771d55a8--779988767
 | Plan 1 | 1b5c68a0-5855-473d-bc40-02b9771d55a8--779988768
 | Plan 1 | 1b5c68a0-5855-473d-bc40-02b9771d55a8--779988769
 | Plan 1 | 1b5c68a0-5855-473d-bc40-02b9771d55a8--779988770
 | Plan 1 | 1b5c68a0-5855-473d-bc40-02b9771d55a8--779988771
 | Plan 1 | 1b5c68a0-5855-473d-bc40-02b9771d55a8--779988772
 | Plan 1 | 1b5c68a0-5855-473d-bc40-02b9771d55a8--779988773
 | Plan 1 | 1b5c68a0-5855-473d-bc40-02b9771d55a8--780021481
 | Plan 1 | 1b5c68a0-5855-473d-bc40-02b9771d55a8--780021482
 | Plan 1 | 1b5c68a0-5855-473d-bc40-02b9771d55a8--780021483
 | Plan 1 | 1b5c68a0-5855-473d-bc40-02b9771d55a8--780021484
 | Plan 1 | 1b5c68a0-5855-473d-bc40-02b9771d55a8--780021485
 | Plan 1 | 1b5c68a0-5855-473d-bc40-02b9771d55a8--780021486
 | Plan 1 | 1b5c68a0-5855-473d-bc40-02b9771d55a8--780021487
 | Plan 1 | 1b5c68a0-5855-473d-bc40-02b9771d55a8--780021488
 | Plan 1 | 1b5c68a0-5855-473d-bc40-02b9771d55a8--780021489
 | Plan 1 | 1b5c68a0-5855-473d-bc40-02b9771d55a8--780021490
 | Plan 1 | 1b5c68a0-5855-473d-bc40-02b9771d55a8--780021491
 | Plan 1 | 1b5c68a0-5855-473d-bc40-02b9771d55a8--780021492
 | Plan 1 | 1b5c68a0-5855-473d-bc40-02b9771d55a8--780021493
 | Plan 1 | 1b5c68a0-5855-473d-bc40-02b9771d55a8--780021494
 | Plan 1 | 1b5c68a0-5855-473d-bc40-02b9771d55a8--780021495
 | Plan 1 | 1b5c68a0-5855-473d-bc40-02b9771d55a8--779993055
 | Plan 1 | 1b5c68a0-5855-473d-bc40-02b9771d55a8--779993056
 | Plan 1 | 1b5c68a0-5855-473d-bc40-02b9771d55a8--779993057
 | Plan 1 | 1b5c68a0-5855-473d-bc40-02b9771d55a8--779993058
 | Plan 1 | 1b5c68a0-5855-473d-bc40-02b9771d55a8--779993059
 | Plan 1 | 1b5c68a0-5855-473d-bc40-02b9771d55a8--779993060
 | Plan 1 | 1b5c68a0-5855-473d-bc40-02b9771d55a8--779993061
 | Plan 1 | 1b5c68a0-5855-473d-bc40-02b9771d55a8--779993062
 | Plan 1 | 1b5c68a0-5855-473d-bc40-02b9771d55a8--779993063
 | Plan 1 | 1b5c68a0-5855-473d-bc40-02b9771d55a8--779993064
 | Plan 1 | 1b5c68a0-5855-473d-bc40-02b9771d55a8--779993065
 | Plan 1 | 1b5c68a0-5855-473d-bc40-02b9771d55a8--779993066
 | Plan 1 | 1b5c68a0-5855-473d-bc40-02b9771d55a8--779993067
 | Plan 1 | 1b5c68a0-5855-473d-bc40-02b9771d55a8--779993068
 | Plan 1 | 1b5c68a0-5855-473d-bc40-02b9771d55a8--779993069
 | Plan 1 | 1b5c68a0-5855-473d-bc40-02b9771d55a8--780049537
 | Plan 1 | 1b5c68a0-5855-473d-bc40-02b9771d55a8--780049536
 | Plan 1 | 1b5c68a0-5855-473d-bc40-02b9771d55a8--779988572
 | Plan 1 | 1b5c68a0-5855-473d-bc40-02b9771d55a8--779988573
 | Plan 1 | 1b5c68a0-5855-473d-bc40-02b9771d55a8--779988574
 | Plan 1 | 1b5c68a0-5855-473d-bc40-02b9771d55a8--779988575
 | Plan 1 | 1b5c68a0-5855-473d-bc40-02b9771d55a8--779988576
 | Plan 1 | 1b5c68a0-5855-473d-bc40-02b9771d55a8--779988577
 | Plan 1 | 1b5c68a0-5855-473d-bc40-02b9771d55a8--779988578
 | Plan 1 | 1b5c68a0-5855-473d-bc40-02b9771d55a8--779993051
 | Plan 1 | 1b5c68a0-5855-473d-bc40-02b9771d55a8--779988481
 | Plan 1 | 1b5c68a0-5855-473d-bc40-02b9771d55a8--779988482
 | Plan 1 | 1b5c68a0-5855-473d-bc40-02b9771d55a8--779989436
 | Plan 1 | 1b5c68a0-5855-473d-bc40-02b9771d55a8--779989437
 | Plan 1 | 1b5c68a0-5855-473d-bc40-02b9771d55a8--779989438
 | Plan 1 | 1b5c68a0-5855-473d-bc40-02b9771d55a8--779989439
 | Plan 1 | 1b5c68a0-5855-473d-bc40-02b9771d55a8--779988774
 | Plan 1 | 1b5c68a0-5855-473d-bc40-02b9771d55a8--779988775
 | Plan 1 | 1b5c68a0-5855-473d-bc40-02b9771d55a8--779988776
 | Plan 1 | 1b5c68a0-5855-473d-bc40-02b9771d55a8--779988777
 | Plan 1 | 1b5c68a0-5855-473d-bc40-02b9771d55a8--779988778
 | Plan 1 | 1b5c68a0-5855-473d-bc40-02b9771d55a8--779988779
 | Plan 1 | 1b5c68a0-5855-473d-bc40-02b9771d55a8--779988780
 | Plan 1 | 1b5c68a0-5855-473d-bc40-02b9771d55a8--779988781
 | Plan 1 | 1b5c68a0-5855-473d-bc40-02b9771d55a8--779988782
 | Plan 1 | 1b5c68a0-5855-473d-bc40-02b9771d55a8--779988783
 | Plan 1 | 1b5c68a0-5855-473d-bc40-02b9771d55a8--779988784
 | Plan 1 | 1b5c68a0-5855-473d-bc40-02b9771d55a8--779988785
 | Plan 1 | 1b5c68a0-5855-473d-bc40-02b9771d55a8--779988786
 | Plan 1 | 1b5c68a0-5855-473d-bc40-02b9771d55a8--779988787
 | Plan 1 | 1b5c68a0-5855-473d-bc40-02b9771d55a8--779988788
 | Plan 1 | 1b5c68a0-5855-473d-bc40-02b9771d55a8--779988789
 | Plan 1 | 1b5c68a0-5855-473d-bc40-02b9771d55a8--779988790
 | Plan 1 | 1b5c68a0-5855-473d-bc40-02b9771d55a8--779988791
 | Plan 1 | 1b5c68a0-5855-473d-bc40-02b9771d55a8--779988792
 | Plan 1 | 1b5c68a0-5855-473d-bc40-02b9771d55a8--779988793
 | Plan 1 | 1b5c68a0-5855-473d-bc40-02b9771d55a8--779988794
 | Plan 1 | 1b5c68a0-5855-473d-bc40-02b9771d55a8--779988795
 | Plan 1 | 1b5c68a0-5855-473d-bc40-02b9771d55a8--779988796
 | Plan 1 | 1b5c68a0-5855-473d-bc40-02b9771d55a8--779988797
 | Plan 1 | 1b5c68a0-5855-473d-bc40-02b9771d55a8--779988798
 | Plan 1 | 1b5c68a0-5855-473d-bc40-02b9771d55a8--779988799
 | Plan 1 | 1b5c68a0-5855-473d-bc40-02b9771d55a8--779988800
 | Plan 1 | 1b5c68a0-5855-473d-bc40-02b9771d55a8--779988801
 | Plan 1 | 1b5c68a0-5855-473d-bc40-02b9771d55a8--779988802
 | Plan 1 | 1b5c68a0-5855-473d-bc40-02b9771d55a8--779988803
 | Plan 1 | 1b5c68a0-5855-473d-bc40-02b9771d55a8--779988804
 | Plan 1 | 1b5c68a0-5855-473d-bc40-02b9771d55a8--779988805
 | Plan 1 | 1b5c68a0-5855-473d-bc40-02b9771d55a8--779988806
 | Plan 1 | 1b5c68a0-5855-473d-bc40-02b9771d55a8--779988807
 | Plan 1 | 1b5c68a0-5855-473d-bc40-02b9771d55a8--779988808
 | Plan 1 | 1b5c68a0-5855-473d-bc40-02b9771d55a8--779988809
 | Plan 1 | 1b5c68a0-5855-473d-bc40-02b9771d55a8--779988810
 | Plan 1 | 1b5c68a0-5855-473d-bc40-02b9771d55a8--779988811
 | Plan 1 | 1b5c68a0-5855-473d-bc40-02b9771d55a8--779988812
 | Plan 1 | 1b5c68a0-5855-473d-bc40-02b9771d55a8--779988813
 | Plan 1 | 1b5c68a0-5855-473d-bc40-02b9771d55a8--779988814
 | Plan 1 | 1b5c68a0-5855-473d-bc40-02b9771d55a8--779988815
 | Plan 1 | 1b5c68a0-5855-473d-bc40-02b9771d55a8--779988816
 | Plan 1 | 1b5c68a0-5855-473d-bc40-02b9771d55a8--779988817
 | Plan 1 | 1b5c68a0-5855-473d-bc40-02b9771d55a8--779988818
 | Plan 1 | 1b5c68a0-5855-473d-bc40-02b9771d55a8--779988819
 | Plan 1 | 1b5c68a0-5855-473d-bc40-02b9771d55a8--779988820
 | Plan 1 | 1b5c68a0-5855-473d-bc40-02b9771d55a8--779988821
 | Plan 1 | 1b5c68a0-5855-473d-bc40-02b9771d55a8--779988822
 | Plan 1 | 1b5c68a0-5855-473d-bc40-02b9771d55a8--779988823
 | Plan 1 | 1b5c68a0-5855-473d-bc40-02b9771d55a8--779988824
 | Plan 1 | 1b5c68a0-5855-473d-bc40-02b9771d55a8--779988825
 | Plan 1 | 1b5c68a0-5855-473d-bc40-02b9771d55a8--779988826
 | Plan 1 | 1b5c68a0-5855-473d-bc40-02b9771d55a8--779988827
 | Plan 1 | 1b5c68a0-5855-473d-bc40-02b9771d55a8--779988828
 | Plan 1 | 1b5c68a0-5855-473d-bc40-02b9771d55a8--779988829
 | Plan 1 | 1b5c68a0-5855-473d-bc40-02b9771d55a8--779988830
 | Plan 1 | 1b5c68a0-5855-473d-bc40-02b9771d55a8--779988831
 | Plan 1 | 1b5c68a0-5855-473d-bc40-02b9771d55a8--779988832
 | Plan 1 | 1b5c68a0-5855-473d-bc40-02b9771d55a8--779988833
 | Plan 1 | 1b5c68a0-5855-473d-bc40-02b9771d55a8--779988834
 | Plan 1 | 1b5c68a0-5855-473d-bc40-02b9771d55a8--779988835
 | Plan 1 | 1b5c68a0-5855-473d-bc40-02b9771d55a8--779988836
 | Plan 1 | 1b5c68a0-5855-473d-bc40-02b9771d55a8--779988837
 | Plan 1 | 1b5c68a0-5855-473d-bc40-02b9771d55a8--779988838
 | Plan 1 | 1b5c68a0-5855-473d-bc40-02b9771d55a8--779988839
 | Plan 1 | 1b5c68a0-5855-473d-bc40-02b9771d55a8--779988840
 | Plan 1 | 1b5c68a0-5855-473d-bc40-02b9771d55a8--779988841
 | Plan 1 | 1b5c68a0-5855-473d-bc40-02b9771d55a8--779988842
 | Plan 1 | 1b5c68a0-5855-473d-bc40-02b9771d55a8--779988843
 | Plan 1 | 1b5c68a0-5855-473d-bc40-02b9771d55a8--779988844
 | Plan 1 | 1b5c68a0-5855-473d-bc40-02b9771d55a8--779988845
 | Plan 1 | 1b5c68a0-5855-473d-bc40-02b9771d55a8--779988846
 | Plan 1 | 1b5c68a0-5855-473d-bc40-02b9771d55a8--779988847
 | Plan 1 | 1b5c68a0-5855-473d-bc40-02b9771d55a8--779988848
 | Plan 1 | 1b5c68a0-5855-473d-bc40-02b9771d55a8--779988849
 | Plan 1 | 1b5c68a0-5855-473d-bc40-02b9771d55a8--779988850
 | Plan 1 | 1b5c68a0-5855-473d-bc40-02b9771d55a8--779988851
 | Plan 1 | 1b5c68a0-5855-473d-bc40-02b9771d55a8--779988852
 | Plan 1 | 1b5c68a0-5855-473d-bc40-02b9771d55a8--779988853
 | Plan 1 | 1b5c68a0-5855-473d-bc40-02b9771d55a8--779988854
 | Plan 1 | 1b5c68a0-5855-473d-bc40-02b9771d55a8--779988855
 | Plan 1 | 1b5c68a0-5855-473d-bc40-02b9771d55a8--779988856
 | Plan 1 | 1b5c68a0-5855-473d-bc40-02b9771d55a8--779988857
 | Plan 1 | 1b5c68a0-5855-473d-bc40-02b9771d55a8--779988858
 | Plan 1 | 1b5c68a0-5855-473d-bc40-02b9771d55a8--779988859
 | Plan 1 | 1b5c68a0-5855-473d-bc40-02b9771d55a8--779988860
 | Plan 1 | 1b5c68a0-5855-473d-bc40-02b9771d55a8--779988861
 | Plan 1 | 1b5c68a0-5855-473d-bc40-02b9771d55a8--779988862
 | Plan 1 | 1b5c68a0-5855-473d-bc40-02b9771d55a8--779988863
 | Plan 1 | 1b5c68a0-5855-473d-bc40-02b9771d55a8--779988864
 | Plan 1 | 1b5c68a0-5855-473d-bc40-02b9771d55a8--779988865
 | Plan 1 | 1b5c68a0-5855-473d-bc40-02b9771d55a8--779988866
 | Plan 1 | 1b5c68a0-5855-473d-bc40-02b9771d55a8--779988867
 | Plan 1 | 1b5c68a0-5855-473d-bc40-02b9771d55a8--779988868
 | Plan 1 | 1b5c68a0-5855-473d-bc40-02b9771d55a8--779988869
 | Plan 1 | 1b5c68a0-5855-473d-bc40-02b9771d55a8--779988870
 | Plan 1 | 1b5c68a0-5855-473d-bc40-02b9771d55a8--779988871
 | Plan 1 | 1b5c68a0-5855-473d-bc40-02b9771d55a8--779988872
 | Plan 1 | 1b5c68a0-5855-473d-bc40-02b9771d55a8--779988873
 | Plan 1 | 1b5c68a0-5855-473d-bc40-02b9771d55a8--779988874
 | Plan 1 | 1b5c68a0-5855-473d-bc40-02b9771d55a8--779988875
 | Plan 1 | 1b5c68a0-5855-473d-bc40-02b9771d55a8--779988876
 | Plan 1 | 1b5c68a0-5855-473d-bc40-02b9771d55a8--779988877
 | Plan 1 | 1b5c68a0-5855-473d-bc40-02b9771d55a8--779988878
 | Plan 1 | 1b5c68a0-5855-473d-bc40-02b9771d55a8--779988879
 | Plan 1 | 1b5c68a0-5855-473d-bc40-02b9771d55a8--779988880
 | Plan 1 | 1b5c68a0-5855-473d-bc40-02b9771d55a8--779988881
 | Plan 1 | 1b5c68a0-5855-473d-bc40-02b9771d55a8--779988882
 | Plan 1 | 1b5c68a0-5855-473d-bc40-02b9771d55a8--779988883
 | Plan 1 | 1b5c68a0-5855-473d-bc40-02b9771d55a8--779988884
 | Plan 1 | 1b5c68a0-5855-473d-bc40-02b9771d55a8--779988885
 | Plan 1 | 1b5c68a0-5855-473d-bc40-02b9771d55a8--779988886
 | Plan 1 | 1b5c68a0-5855-473d-bc40-02b9771d55a8--779988887
 | Plan 1 | 1b5c68a0-5855-473d-bc40-02b9771d55a8--779988888
 | Plan 1 | 1b5c68a0-5855-473d-bc40-02b9771d55a8--779988889
 | Plan 1 | 1b5c68a0-5855-473d-bc40-02b9771d55a8--779988890
 | Plan 1 | 1b5c68a0-5855-473d-bc40-02b9771d55a8--779988891
 | Plan 1 | 1b5c68a0-5855-473d-bc40-02b9771d55a8--779988892
 | Plan 1 | 1b5c68a0-5855-473d-bc40-02b9771d55a8--779988893
 | Plan 1 | 1b5c68a0-5855-473d-bc40-02b9771d55a8--779988894
 | Plan 1 | 1b5c68a0-5855-473d-bc40-02b9771d55a8--779988895
 | Plan 1 | 1b5c68a0-5855-473d-bc40-02b9771d55a8--779988896
 | Plan 1 | 1b5c68a0-5855-473d-bc40-02b9771d55a8--779988897
 | Plan 1 | 1b5c68a0-5855-473d-bc40-02b9771d55a8--779988898
 | Plan 1 | 1b5c68a0-5855-473d-bc40-02b9771d55a8--779988899
 | Plan 1 | 1b5c68a0-5855-473d-bc40-02b9771d55a8--779988900
 | Plan 1 | 1b5c68a0-5855-473d-bc40-02b9771d55a8--779988901
 | Plan 1 | 1b5c68a0-5855-473d-bc40-02b9771d55a8--779988902
 | Plan 1 | 1b5c68a0-5855-473d-bc40-02b9771d55a8--779988903
 | Plan 1 | 1b5c68a0-5855-473d-bc40-02b9771d55a8--779988904
 | Plan 1 | 1b5c68a0-5855-473d-bc40-02b9771d55a8--779988905
 | Plan 1 | 1b5c68a0-5855-473d-bc40-02b9771d55a8--779988906
 | Plan 1 | 1b5c68a0-5855-473d-bc40-02b9771d55a8--779988907
 | Plan 1 | 1b5c68a0-5855-473d-bc40-02b9771d55a8--779988908
 | Plan 1 | 1b5c68a0-5855-473d-bc40-02b9771d55a8--779988909
 | Plan 1 | 1b5c68a0-5855-473d-bc40-02b9771d55a8--779988910
 | Plan 1 | 1b5c68a0-5855-473d-bc40-02b9771d55a8--779988911
 | Plan 1 | 1b5c68a0-5855-473d-bc40-02b9771d55a8--779988912
 | Plan 1 | 1b5c68a0-5855-473d-bc40-02b9771d55a8--779988913
 | Plan 1 | 1b5c68a0-5855-473d-bc40-02b9771d55a8--779988914
 | Plan 1 | 1b5c68a0-5855-473d-bc40-02b9771d55a8--779988915
 | Plan 1 | 1b5c68a0-5855-473d-bc40-02b9771d55a8--779988916
 | Plan 1 | 1b5c68a0-5855-473d-bc40-02b9771d55a8--779988917
 | Plan 1 | 1b5c68a0-5855-473d-bc40-02b9771d55a8--779988918
 | Plan 1 | 1b5c68a0-5855-473d-bc40-02b9771d55a8--779988919
 | Plan 1 | 1b5c68a0-5855-473d-bc40-02b9771d55a8--779988920
 | Plan 1 | 1b5c68a0-5855-473d-bc40-02b9771d55a8--779988921
 | Plan 1 | 1b5c68a0-5855-473d-bc40-02b9771d55a8--779988922
 | Plan 1 | 1b5c68a0-5855-473d-bc40-02b9771d55a8--779988923
 | Plan 1 | 1b5c68a0-5855-473d-bc40-02b9771d55a8--779988924
 | Plan 1 | 1b5c68a0-5855-473d-bc40-02b9771d55a8--779988925
 | Plan 1 | 1b5c68a0-5855-473d-bc40-02b9771d55a8--779988926
 | Plan 1 | 1b5c68a0-5855-473d-bc40-02b9771d55a8--779988927
 | Plan 1 | 1b5c68a0-5855-473d-bc40-02b9771d55a8--779988928
 | Plan 1 | 1b5c68a0-5855-473d-bc40-02b9771d55a8--779988929
 | Plan 1 | 1b5c68a0-5855-473d-bc40-02b9771d55a8--779988930
 | Plan 1 | 1b5c68a0-5855-473d-bc40-02b9771d55a8--779988931
 | Plan 1 | 1b5c68a0-5855-473d-bc40-02b9771d55a8--779988932
 | Plan 1 | 1b5c68a0-5855-473d-bc40-02b9771d55a8--779988933
 | Plan 1 | 1b5c68a0-5855-473d-bc40-02b9771d55a8--779985200
 | Plan 1 | 1b5c68a0-5855-473d-bc40-02b9771d55a8--779985201
 | Plan 1 | 1b5c68a0-5855-473d-bc40-02b9771d55a8--779985202
 | Plan 1 | 1b5c68a0-5855-473d-bc40-02b9771d55a8--779985203
 | Plan 1 | 1b5c68a0-5855-473d-bc40-02b9771d55a8--779985204
 | Plan 1 | 1b5c68a0-5855-473d-bc40-02b9771d55a8--779985205
 | Plan 1 | 1b5c68a0-5855-473d-bc40-02b9771d55a8--779985206
 | Plan 1 | 1b5c68a0-5855-473d-bc40-02b9771d55a8--779985207
 | Plan 1 | 1b5c68a0-5855-473d-bc40-02b9771d55a8--779985208
 | Plan 1 | 1b5c68a0-5855-473d-bc40-02b9771d55a8--779985209
 | Plan 1 | 1b5c68a0-5855-473d-bc40-02b9771d55a8--779988600
 | Plan 1 | 1b5c68a0-5855-473d-bc40-02b9771d55a8--779988601
 | Plan 1 | 1b5c68a0-5855-473d-bc40-02b9771d55a8--779988602
 | Plan 1 | 1b5c68a0-5855-473d-bc40-02b9771d55a8--779988603
 | Plan 1 | 1b5c68a0-5855-473d-bc40-02b9771d55a8--779988604
 | Plan 1 | 1b5c68a0-5855-473d-bc40-02b9771d55a8--779988605
 | Plan 1 | 1b5c68a0-5855-473d-bc40-02b9771d55a8--779988606
 | Plan 1 | 1b5c68a0-5855-473d-bc40-02b9771d55a8--779988607
 | Plan 1 | 1b5c68a0-5855-473d-bc40-02b9771d55a8--779988608
 | Plan 1 | 1b5c68a0-5855-473d-bc40-02b9771d55a8--779988609
 | Plan 1 | 1b5c68a0-5855-473d-bc40-02b9771d55a8--779988610
 | Plan 1 | 1b5c68a0-5855-473d-bc40-02b9771d55a8--779988611
 | Plan 1 | 1b5c68a0-5855-473d-bc40-02b9771d55a8--779988612
 | Plan 1 | 1b5c68a0-5855-473d-bc40-02b9771d55a8--779988613
 | Plan 1 | 1b5c68a0-5855-473d-bc40-02b9771d55a8--779989802
 | Plan 1 | 1b5c68a0-5855-473d-bc40-02b9771d55a8--779988614
 | Plan 1 | 1b5c68a0-5855-473d-bc40-02b9771d55a8--779988615
 | Plan 1 | 1b5c68a0-5855-473d-bc40-02b9771d55a8--779988616
 | Plan 1 | 1b5c68a0-5855-473d-bc40-02b9771d55a8--779988617
 | Plan 1 | 1b5c68a0-5855-473d-bc40-02b9771d55a8--779988618
 | Plan 1 | 1b5c68a0-5855-473d-bc40-02b9771d55a8--779988619
 | Plan 1 | 1b5c68a0-5855-473d-bc40-02b9771d55a8--779988620
 | Plan 1 | 1b5c68a0-5855-473d-bc40-02b9771d55a8--779988621
 | Plan 1 | 1b5c68a0-5855-473d-bc40-02b9771d55a8--779988622
 | Plan 1 | 1b5c68a0-5855-473d-bc40-02b9771d55a8--779988623
 | Plan 1 | 1b5c68a0-5855-473d-bc40-02b9771d55a8--779988624
 | Plan 1 | 1b5c68a0-5855-473d-bc40-02b9771d55a8--779988625
 | Plan 1 | 1b5c68a0-5855-473d-bc40-02b9771d55a8--779988626
 | Plan 1 | 1b5c68a0-5855-473d-bc40-02b9771d55a8--779988627
 | Plan 1 | 1b5c68a0-5855-473d-bc40-02b9771d55a8--779988628
 | Plan 1 | 1b5c68a0-5855-473d-bc40-02b9771d55a8--779988631
 | Plan 1 | 1b5c68a0-5855-473d-bc40-02b9771d55a8--779988632
 | Plan 1 | 1b5c68a0-5855-473d-bc40-02b9771d55a8--779988633
 | Plan 1 | 1b5c68a0-5855-473d-bc40-02b9771d55a8--779988634
 | Plan 1 | 1b5c68a0-5855-473d-bc40-02b9771d55a8--779988635
 | Plan 1 | 1b5c68a0-5855-473d-bc40-02b9771d55a8--779988636
 | Plan 1 | 1b5c68a0-5855-473d-bc40-02b9771d55a8--779988637
 | Plan 1 | 1b5c68a0-5855-473d-bc40-02b9771d55a8--779988638
 | Plan 1 | 1b5c68a0-5855-473d-bc40-02b9771d55a8--779988640
 | Plan 1 | 1b5c68a0-5855-473d-bc40-02b9771d55a8--779988641
 | Plan 1 | 1b5c68a0-5855-473d-bc40-02b9771d55a8--779988642
 | Plan 1 | 1b5c68a0-5855-473d-bc40-02b9771d55a8--779988643
 | Plan 1 | 1b5c68a0-5855-473d-bc40-02b9771d55a8--779988644
 | Plan 1 | 1b5c68a0-5855-473d-bc40-02b9771d55a8--779988645
 | Plan 1 | 1b5c68a0-5855-473d-bc40-02b9771d55a8--779988646
 | Plan 1 | 1b5c68a0-5855-473d-bc40-02b9771d55a8--779988647
 | Plan 1 | 1b5c68a0-5855-473d-bc40-02b9771d55a8--779988648
 | Plan 1 | 1b5c68a0-5855-473d-bc40-02b9771d55a8--779988649
 | Plan 1 | 1b5c68a0-5855-473d-bc40-02b9771d55a8--779988650
 | Plan 1 | 1b5c68a0-5855-473d-bc40-02b9771d55a8--779988651
 | Plan 1 | 1b5c68a0-5855-473d-bc40-02b9771d55a8--779988652
 | Plan 1 | 1b5c68a0-5855-473d-bc40-02b9771d55a8--779988653
 | Plan 1 | 1b5c68a0-5855-473d-bc40-02b9771d55a8--779988654
 | Plan 1 | 1b5c68a0-5855-473d-bc40-02b9771d55a8--779988655
 | Plan 1 | 1b5c68a0-5855-473d-bc40-02b9771d55a8--779988657
 | Plan 1 | 1b5c68a0-5855-473d-bc40-02b9771d55a8--779988658
 | Plan 1 | 1b5c68a0-5855-473d-bc40-02b9771d55a8--779988659
 | Plan 1 | 1b5c68a0-5855-473d-bc40-02b9771d55a8--779988660
 | Plan 1 | 1b5c68a0-5855-473d-bc40-02b9771d55a8--779988662
 | Plan 1 | 1b5c68a0-5855-473d-bc40-02b9771d55a8--779988663
 | Plan 1 | 1b5c68a0-5855-473d-bc40-02b9771d55a8--779988664
 | Plan 1 | 1b5c68a0-5855-473d-bc40-02b9771d55a8--779988665
 | Plan 1 | 1b5c68a0-5855-473d-bc40-02b9771d55a8--779988666
 | Plan 1 | 1b5c68a0-5855-473d-bc40-02b9771d55a8--779988667
 | Plan 1 | 1b5c68a0-5855-473d-bc40-02b9771d55a8--779988668
 | Plan 1 | 1b5c68a0-5855-473d-bc40-02b9771d55a8--779988669
 | Plan 1 | 1b5c68a0-5855-473d-bc40-02b9771d55a8--779988670
 | Plan 1 | 1b5c68a0-5855-473d-bc40-02b9771d55a8--779988693
 | Plan 1 | 1b5c68a0-5855-473d-bc40-02b9771d55a8--779988694
 | Plan 1 | 1b5c68a0-5855-473d-bc40-02b9771d55a8--779988695
 | Plan 1 | 1b5c68a0-5855-473d-bc40-02b9771d55a8--779988696
 | Plan 1 | 1b5c68a0-5855-473d-bc40-02b9771d55a8--779988701
 | Plan 1 | 1b5c68a0-5855-473d-bc40-02b9771d55a8--779988702
 | Plan 1 | 1b5c68a0-5855-473d-bc40-02b9771d55a8--779988703
 | Plan 1 | 1b5c68a0-5855-473d-bc40-02b9771d55a8--779988704
 | Plan 1 | 1b5c68a0-5855-473d-bc40-02b9771d55a8--779988706
 | Plan 1 | 1b5c68a0-5855-473d-bc40-02b9771d55a8--779988713
 | Plan 1 | 1b5c68a0-5855-473d-bc40-02b9771d55a8--779988714
 | Plan 1 | 1b5c68a0-5855-473d-bc40-02b9771d55a8--779988715
 | Plan 1 | 1b5c68a0-5855-473d-bc40-02b9771d55a8--779988716
 | Plan 1 | 1b5c68a0-5855-473d-bc40-02b9771d55a8--779988717
 | Plan 1 | 1b5c68a0-5855-473d-bc40-02b9771d55a8--779988718
 | Plan 1 | 1b5c68a0-5855-473d-bc40-02b9771d55a8--779988719
 | Plan 1 | 1b5c68a0-5855-473d-bc40-02b9771d55a8--779988720
 | Plan 1 | 1b5c68a0-5855-473d-bc40-02b9771d55a8--779988721
 | Plan 1 | 1b5c68a0-5855-473d-bc40-02b9771d55a8--779988723
 | Plan 1 | 1b5c68a0-5855-473d-bc40-02b9771d55a8--779988724
 | Plan 1 | 1b5c68a0-5855-473d-bc40-02b9771d55a8--779988725
 | Plan 1 | 1b5c68a0-5855-473d-bc40-02b9771d55a8--779988727
 | Plan 1 | 1b5c68a0-5855-473d-bc40-02b9771d55a8--779988728
 | Plan 1 | 1b5c68a0-5855-473d-bc40-02b9771d55a8--779988731
 | Plan 1 | 1b5c68a0-5855-473d-bc40-02b9771d55a8--779988732
 | Plan 1 | 1b5c68a0-5855-473d-bc40-02b9771d55a8--779988733
 | Plan 1 | 1b5c68a0-5855-473d-bc40-02b9771d55a8--779988734
 | Plan 1 | 1b5c68a0-5855-473d-bc40-02b9771d55a8--779988735
 | Plan 1 | 1b5c68a0-5855-473d-bc40-02b9771d55a8--779988736
 | Plan 1 | 1b5c68a0-5855-473d-bc40-02b9771d55a8--779988737
 | Plan 1 | 1b5c68a0-5855-473d-bc40-02b9771d55a8--779988738
 | Plan 1 | 1b5c68a0-5855-473d-bc40-02b9771d55a8--779988741
 | Plan 1 | 1b5c68a0-5855-473d-bc40-02b9771d55a8--779988742
 | Plan 1 | 1b5c68a0-5855-473d-bc40-02b9771d55a8--779988743
 | Plan 1 | 1b5c68a0-5855-473d-bc40-02b9771d55a8--779988744
 | Plan 1 | 1b5c68a0-5855-473d-bc40-02b9771d55a8--779988745
 | Plan 1 | 1b5c68a0-5855-473d-bc40-02b9771d55a8--779988746
 | Plan 1 | 1b5c68a0-5855-473d-bc40-02b9771d55a8--779988747
 | Plan 1 | 1b5c68a0-5855-473d-bc40-02b9771d55a8--779988748
 | Plan 1 | 1b5c68a0-5855-473d-bc40-02b9771d55a8--779993716
 | Plan 1 | 1b5c68a0-5855-473d-bc40-02b9771d55a8--779993717
 | Plan 1 | 1b5c68a0-5855-473d-bc40-02b9771d55a8--779993718
 | Plan 1 | 1b5c68a0-5855-473d-bc40-02b9771d55a8--779993719
 | Plan 1 | 1b5c68a0-5855-473d-bc40-02b9771d55a8--779993720
 | Plan 1 | 1b5c68a0-5855-473d-bc40-02b9771d55a8--779993722
 | Plan 1 | 1b5c68a0-5855-473d-bc40-02b9771d55a8--779993723
 | Plan 1 | 1b5c68a0-5855-473d-bc40-02b9771d55a8--780049538
 | Plan 1 | 1b5c68a0-5855-473d-bc40-02b9771d55a8--780049539
 | Plan 1 | 1b5c68a0-5855-473d-bc40-02b9771d55a8--780049540
 | Plan 1 | 1b5c68a0-5855-473d-bc40-02b9771d55a8--780049541
 | Plan 1 | 1b5c68a0-5855-473d-bc40-02b9771d55a8--780049542
 | Plan 1 | 1b5c68a0-5855-473d-bc40-02b9771d55a8--780049543
 | Plan 1 | 1b5c68a0-5855-473d-bc40-02b9771d55a8--780049544
 | Plan 1 | 1b5c68a0-5855-473d-bc40-02b9771d55a8--780049545
 | Plan 1 | 1b5c68a0-5855-473d-bc40-02b9771d55a8--780049546
 | Plan 1 | 1b5c68a0-5855-473d-bc40-02b9771d55a8--780049547
 | Plan 1 | 1b5c68a0-5855-473d-bc40-02b9771d55a8--780049548
 | Plan 1 | 1b5c68a0-5855-473d-bc40-02b9771d55a8--780049764
 | Plan 1 | 1b5c68a0-5855-473d-bc40-02b9771d55a8--780049765
 | Plan 1 | 1b5c68a0-5855-473d-bc40-02b9771d55a8--780049766
 | Plan 1 | 1b5c68a0-5855-473d-bc40-02b9771d55a8--780049767
 | Plan 1 | 1b5c68a0-5855-473d-bc40-02b9771d55a8--780049768
 | Plan 1 | 1b5c68a0-5855-473d-bc40-02b9771d55a8--780049769
 | Plan 1 | 1b5c68a0-5855-473d-bc40-02b9771d55a8--780049770
 | Plan 1 | 1b5c68a0-5855-473d-bc40-02b9771d55a8--780049771
 | Plan 1 | 1b5c68a0-5855-473d-bc40-02b9771d55a8--780049772
 | Plan 1 | 1b5c68a0-5855-473d-bc40-02b9771d55a8--779923407
 | Plan 1 | 1b5c68a0-5855-473d-bc40-02b9771d55a8--779923412
 | Plan 1 | 1b5c68a0-5855-473d-bc40-02b9771d55a8--779958075
 | Plan 1 | 1b5c68a0-5855-473d-bc40-02b9771d55a8--779958076
 | Plan 1 | 1b5c68a0-5855-473d-bc40-02b9771d55a8--779990375
 | Plan 1 | 1b5c68a0-5855-473d-bc40-02b9771d55a8--779991308
 | Plan 1 | 1b5c68a0-5855-473d-bc40-02b9771d55a8--779991851
 | Plan 1 | 1b5c68a0-5855-473d-bc40-02b9771d55a8--779992094
 | Plan 1 | 1b5c68a0-5855-473d-bc40-02b9771d55a8--779923373
 | Plan 1 | 1b5c68a0-5855-473d-bc40-02b9771d55a8--779923375
 | Plan 1 | 1b5c68a0-5855-473d-bc40-02b9771d55a8--779958067
 | Plan 1 | 1b5c68a0-5855-473d-bc40-02b9771d55a8--779958069
 | Plan 1 | 1b5c68a0-5855-473d-bc40-02b9771d55a8--779958058
 | Plan 1 | 1b5c68a0-5855-473d-bc40-02b9771d55a8--779958031
 | Plan 1 | 1b5c68a0-5855-473d-bc40-02b9771d55a8--779958065
 | Plan 1 | 1b5c68a0-5855-473d-bc40-02b9771d55a8--779923394
 | Plan 1 | 1b5c68a0-5855-473d-bc40-02b9771d55a8--779923406
 | Plan 1 | 1b5c68a0-5855-473d-bc40-02b9771d55a8--779923376
 | Plan 1 | 1b5c68a0-5855-473d-bc40-02b9771d55a8--779923377
 | Plan 1 | 1b5c68a0-5855-473d-bc40-02b9771d55a8--779923378
 | Plan 1 | 1b5c68a0-5855-473d-bc40-02b9771d55a8--779923379
 | Plan 1 | 1b5c68a0-5855-473d-bc40-02b9771d55a8--779923380
 | Plan 1 | 1b5c68a0-5855-473d-bc40-02b9771d55a8--779923381
 | Plan 1 | 1b5c68a0-5855-473d-bc40-02b9771d55a8--779958057
 | Plan 1 | 1b5c68a0-5855-473d-bc40-02b9771d55a8--779958059
 | Plan 1 | 1b5c68a0-5855-473d-bc40-02b9771d55a8--779958068
 | Plan 1 | 1b5c68a0-5855-473d-bc40-02b9771d55a8--779958070
 | Plan 1 | 1b5c68a0-5855-473d-bc40-02b9771d55a8--779958071
 | Plan 1 | 1b5c68a0-5855-473d-bc40-02b9771d55a8--779958072
 | Plan 1 | 1b5c68a0-5855-473d-bc40-02b9771d55a8--779958073
 | Plan 1 | 1b5c68a0-5855-473d-bc40-02b9771d55a8--779958074
 | Plan 1 | 1b5c68a0-5855-473d-bc40-02b9771d55a8--779923387
 | Plan 1 | 1b5c68a0-5855-473d-bc40-02b9771d55a8--779985188
 | Plan 1 | 1b5c68a0-5855-473d-bc40-02b9771d55a8--779988403
 | Plan 1 | 1b5c68a0-5855-473d-bc40-02b9771d55a8--779988404
 | Plan 1 | 1b5c68a0-5855-473d-bc40-02b9771d55a8--779993942
 | Plan 1 | 1b5c68a0-5855-473d-bc40-02b9771d55a8--779993944
 | Plan 1 | 1b5c68a0-5855-473d-bc40-02b9771d55a8--779923388
 | Plan 1 | 1b5c68a0-5855-473d-bc40-02b9771d55a8--779923389
 | Plan 1 | 1b5c68a0-5855-473d-bc40-02b9771d55a8--779923385
 | Plan 1 | 1b5c68a0-5855-473d-bc40-02b9771d55a8--779923362
 | Plan 1 | 1b5c68a0-5855-473d-bc40-02b9771d55a8--779923363
 | Plan 1 | 1b5c68a0-5855-473d-bc40-02b9771d55a8--779923364
 | Plan 1 | 1b5c68a0-5855-473d-bc40-02b9771d55a8--779923382
 | Plan 1 | 1b5c68a0-5855-473d-bc40-02b9771d55a8--779923384
 | Plan 1 | 1b5c68a0-5855-473d-bc40-02b9771d55a8--779923371
 | Plan 1 | 1b5c68a0-5855-473d-bc40-02b9771d55a8--779923370
 | Plan 1 | 1b5c68a0-5855-473d-bc40-02b9771d55a8--779923383
 | Plan 1 | 1b5c68a0-5855-473d-bc40-02b9771d55a8--779985154
 | Plan 1 | 1b5c68a0-5855-473d-bc40-02b9771d55a8--779988397
 | Plan 1 | 1b5c68a0-5855-473d-bc40-02b9771d55a8--779988405
 | Plan 1 | 1b5c68a0-5855-473d-bc40-02b9771d55a8--779923418
 | Plan 1 | 1b5c68a0-5855-473d-bc40-02b9771d55a8--779923422
 | Plan 1 | 1b5c68a0-5855-473d-bc40-02b9771d55a8--779923423
 | Plan 1 | 1b5c68a0-5855-473d-bc40-02b9771d55a8--779993946
 | Plan 1 | 1b5c68a0-5855-473d-bc40-02b9771d55a8--780021397
 | Plan 1 | 1b5c68a0-5855-473d-bc40-02b9771d55a8--779923395
 | Plan 1 | 1b5c68a0-5855-473d-bc40-02b9771d55a8--779923396
 | Plan 1 | 1b5c68a0-5855-473d-bc40-02b9771d55a8--779923419
 | Plan 1 | 1b5c68a0-5855-473d-bc40-02b9771d55a8--779923421
 | Plan 1 | 1b5c68a0-5855-473d-bc40-02b9771d55a8--779923425
 | Plan 1 | 1b5c68a0-5855-473d-bc40-02b9771d55a8--779923420
 | Plan 1 | 1b5c68a0-5855-473d-bc40-02b9771d55a8--779923393
 | Plan 1 | 1b5c68a0-5855-473d-bc40-02b9771d55a8--779993945
 | Plan 1 | 1b5c68a0-5855-473d-bc40-02b9771d55a8--779993947
 | Plan 1 | 1b5c68a0-5855-473d-bc40-02b9771d55a8--780021401
 | Plan 1 | 1b5c68a0-5855-473d-bc40-02b9771d55a8--779923436
 | Plan 1 | 1b5c68a0-5855-473d-bc40-02b9771d55a8--779923397
 | Plan 1 | 1b5c68a0-5855-473d-bc40-02b9771d55a8--779923398
 | Plan 1 | 1b5c68a0-5855-473d-bc40-02b9771d55a8--779923399
 | Plan 1 | 1b5c68a0-5855-473d-bc40-02b9771d55a8--779923400
 | Plan 1 | 1b5c68a0-5855-473d-bc40-02b9771d55a8--779923401
 | Plan 1 | 1b5c68a0-5855-473d-bc40-02b9771d55a8--779923402
 | Plan 1 | 1b5c68a0-5855-473d-bc40-02b9771d55a8--779923403
 | Plan 1 | 1b5c68a0-5855-473d-bc40-02b9771d55a8--779923404
 | Plan 1 | 1b5c68a0-5855-473d-bc40-02b9771d55a8--780049991
 | Plan 1 | 1b5c68a0-5855-473d-bc40-02b9771d55a8--780049990
 | Plan 1 | 1b5c68a0-5855-473d-bc40-02b9771d55a8--780049992
 | Plan 1 | 1b5c68a0-5855-473d-bc40-02b9771d55a8--780049993
 | Plan 1 | 1b5c68a0-5855-473d-bc40-02b9771d55a8--780049994
 | Plan 1 | 1b5c68a0-5855-473d-bc40-02b9771d55a8--780049995
 | Plan 1 | 1b5c68a0-5855-473d-bc40-02b9771d55a8--780049996
 | Plan 1 | 1b5c68a0-5855-473d-bc40-02b9771d55a8--780049997
 | Plan 1 | 1b5c68a0-5855-473d-bc40-02b9771d55a8--780049999
 | Plan 1 | 1b5c68a0-5855-473d-bc40-02b9771d55a8--780050000
 | Plan 1 | 1b5c68a0-5855-473d-bc40-02b9771d55a8--780050001
 | Plan 1 | 1b5c68a0-5855-473d-bc40-02b9771d55a8--780050002
 | Plan 1 | 1b5c68a0-5855-473d-bc40-02b9771d55a8--780050003
 | Plan 1 | 1b5c68a0-5855-473d-bc40-02b9771d55a8--780050004
 | Plan 1 | 1b5c68a0-5855-473d-bc40-02b9771d55a8--780050005
 | Plan 1 | 1b5c68a0-5855-473d-bc40-02b9771d55a8--780050006
 | Plan 1 | 1b5c68a0-5855-473d-bc40-02b9771d55a8--780050089
 | Plan 1 | 1b5c68a0-5855-473d-bc40-02b9771d55a8--780050090
 | Plan 1 | 1b5c68a0-5855-473d-bc40-02b9771d55a8--780050091
 | Plan 1 | 1b5c68a0-5855-473d-bc40-02b9771d55a8--780050092
 | Plan 1 | 1b5c68a0-5855-473d-bc40-02b9771d55a8--780050093
 | Plan 1 | 1b5c68a0-5855-473d-bc40-02b9771d55a8--780050043
 | Plan 1 | 1b5c68a0-5855-473d-bc40-02b9771d55a8--780050044
 | Plan 1 | 1b5c68a0-5855-473d-bc40-02b9771d55a8--780050045
 | Plan 1 | 1b5c68a0-5855-473d-bc40-02b9771d55a8--780050046
 | Plan 1 | 1b5c68a0-5855-473d-bc40-02b9771d55a8--780050047
 | Plan 1 | 1b5c68a0-5855-473d-bc40-02b9771d55a8--780050095
 | Plan 1 | 1b5c68a0-5855-473d-bc40-02b9771d55a8--780050096
 | Plan 1 | 1b5c68a0-5855-473d-bc40-02b9771d55a8--780050097
 | Plan 1 | 1b5c68a0-5855-473d-bc40-02b9771d55a8--780050098
 | Plan 1 | 1b5c68a0-5855-473d-bc40-02b9771d55a8--780050099
 | Plan 1 | 1b5c68a0-5855-473d-bc40-02b9771d55a8--780050101
 | Plan 1 | 1b5c68a0-5855-473d-bc40-02b9771d55a8--780050102
 | Plan 1 | 1b5c68a0-5855-473d-bc40-02b9771d55a8--780050103
 | Plan 1 | 1b5c68a0-5855-473d-bc40-02b9771d55a8--780050104
 | Plan 1 | 1b5c68a0-5855-473d-bc40-02b9771d55a8--780050105
 | Plan 1 | 1b5c68a0-5855-473d-bc40-02b9771d55a8--780050107
 | Plan 1 | 1b5c68a0-5855-473d-bc40-02b9771d55a8--780050108
 | Plan 1 | 1b5c68a0-5855-473d-bc40-02b9771d55a8--780050109
 | Plan 1 | 1b5c68a0-5855-473d-bc40-02b9771d55a8--780050110
 | Plan 1 | 1b5c68a0-5855-473d-bc40-02b9771d55a8--780050111
 | Plan 1 | 1b5c68a0-5855-473d-bc40-02b9771d55a8--780050113
 | Plan 1 | 1b5c68a0-5855-473d-bc40-02b9771d55a8--780050114
 | Plan 1 | 1b5c68a0-5855-473d-bc40-02b9771d55a8--780050115
 | Plan 1 | 1b5c68a0-5855-473d-bc40-02b9771d55a8--780050116
 | Plan 1 | 1b5c68a0-5855-473d-bc40-02b9771d55a8--780050117
 | Plan 1 | 1b5c68a0-5855-473d-bc40-02b9771d55a8--779959406
 | Plan 1 | 1b5c68a0-5855-473d-bc40-02b9771d55a8--779959837
 | Plan 1 | 1b5c68a0-5855-473d-bc40-02b9771d55a8--780049773
 | Plan 1 | 1b5c68a0-5855-473d-bc40-02b9771d55a8--779958013
 | Plan 1 | 1b5c68a0-5855-473d-bc40-02b9771d55a8--779985155
 | Plan 1 | 1b5c68a0-5855-473d-bc40-02b9771d55a8--780050211
 | Plan 1 | 1b5c68a0-5855-473d-bc40-02b9771d55a8--780050212
 | Plan 1 | 1b5c68a0-5855-473d-bc40-02b9771d55a8--780050213
 | Plan 1 | 1b5c68a0-5855-473d-bc40-02b9771d55a8--780050214
 | Plan 1 | 1b5c68a0-5855-473d-bc40-02b9771d55a8--780050215
 | Plan 1 | 2b163d4f-5c70-4d8b-a784-0af841b40480--779868660
 | Plan 1 | ac553d8b-398e-4058-95c3-ac796ec1c327--779930368
 | Plan 1 | ac553d8b-398e-4058-95c3-ac796ec1c327--779930369
 | Plan 1 | ac553d8b-398e-4058-95c3-ac796ec1c327--779930370
 | Plan 1 | ac553d8b-398e-4058-95c3-ac796ec1c327--779930394
 | Plan 1 | ac553d8b-398e-4058-95c3-ac796ec1c327--779930395
 | Plan 1 | ac553d8b-398e-4058-95c3-ac796ec1c327--779930396
 | Plan 1 | ac553d8b-398e-4058-95c3-ac796ec1c327--779930414
 | Plan 1 | ac553d8b-398e-4058-95c3-ac796ec1c327--779930415
 | Plan 1 | ac553d8b-398e-4058-95c3-ac796ec1c327--779930416
 | Plan 1 | ac553d8b-398e-4058-95c3-ac796ec1c327--779930421
 | Plan 1 | ac553d8b-398e-4058-95c3-ac796ec1c327--779930422
 | Plan 1 | ac553d8b-398e-4058-95c3-ac796ec1c327--779930423
 | Plan 1 | ac553d8b-398e-4058-95c3-ac796ec1c327--779930428
 | Plan 1 | ac553d8b-398e-4058-95c3-ac796ec1c327--779930429
 | Plan 1 | ac553d8b-398e-4058-95c3-ac796ec1c327--779930430
 | Plan 1 | ac553d8b-398e-4058-95c3-ac796ec1c327--779930441
 | Plan 1 | ac553d8b-398e-4058-95c3-ac796ec1c327--779930442
 | Plan 1 | ac553d8b-398e-4058-95c3-ac796ec1c327--779930443
 | Plan 1 | ac553d8b-398e-4058-95c3-ac796ec1c327--779930448
 | Plan 1 | ac553d8b-398e-4058-95c3-ac796ec1c327--779930449
 | Plan 1 | ac553d8b-398e-4058-95c3-ac796ec1c327--779930450
 | Plan 1 | ac553d8b-398e-4058-95c3-ac796ec1c327--779930455
 | Plan 1 | ac553d8b-398e-4058-95c3-ac796ec1c327--779930456
 | Plan 1 | ac553d8b-398e-4058-95c3-ac796ec1c327--779930457
 | Plan 1 | ac553d8b-398e-4058-95c3-ac796ec1c327--779930469
 | Plan 1 | ac553d8b-398e-4058-95c3-ac796ec1c327--779930470
 | Plan 1 | ac553d8b-398e-4058-95c3-ac796ec1c327--779930471
 | Plan 1 | ac553d8b-398e-4058-95c3-ac796ec1c327--779930476
 | Plan 1 | ac553d8b-398e-4058-95c3-ac796ec1c327--779930477
 | Plan 1 | ac553d8b-398e-4058-95c3-ac796ec1c327--779930478
 | Plan 1 | ac553d8b-398e-4058-95c3-ac796ec1c327--779930496
 | Plan 1 | ac553d8b-398e-4058-95c3-ac796ec1c327--779930497
 | Plan 1 | ac553d8b-398e-4058-95c3-ac796ec1c327--779930498
 | Plan 1 | ac553d8b-398e-4058-95c3-ac796ec1c327--779930509
 | Plan 1 | ac553d8b-398e-4058-95c3-ac796ec1c327--779930510
 | Plan 1 | ac553d8b-398e-4058-95c3-ac796ec1c327--779930511
 | Plan 1 | ac553d8b-398e-4058-95c3-ac796ec1c327--779930516
 | Plan 1 | ac553d8b-398e-4058-95c3-ac796ec1c327--779930517
 | Plan 1 | ac553d8b-398e-4058-95c3-ac796ec1c327--779930518
 | Plan 1 | ac553d8b-398e-4058-95c3-ac796ec1c327--779930523
 | Plan 1 | ac553d8b-398e-4058-95c3-ac796ec1c327--779930524
 | Plan 1 | ac553d8b-398e-4058-95c3-ac796ec1c327--779930525
 | Plan 1 | ac553d8b-398e-4058-95c3-ac796ec1c327--779930337
 | Plan 1 | ac553d8b-398e-4058-95c3-ac796ec1c327--779930338
 | Plan 1 | ac553d8b-398e-4058-95c3-ac796ec1c327--779930339
 | Plan 1 | ac553d8b-398e-4058-95c3-ac796ec1c327--779930483
 | Plan 1 | ac553d8b-398e-4058-95c3-ac796ec1c327--779930484
 | Plan 1 | ac553d8b-398e-4058-95c3-ac796ec1c327--779930485
 | Plan 1 | ac553d8b-398e-4058-95c3-ac796ec1c327--779930316
 | Plan 1 | ac553d8b-398e-4058-95c3-ac796ec1c327--779930317
 | Plan 1 | ac553d8b-398e-4058-95c3-ac796ec1c327--779930318
 | Plan 1 | ac553d8b-398e-4058-95c3-ac796ec1c327--779930330
 | Plan 1 | ac553d8b-398e-4058-95c3-ac796ec1c327--779930331
 | Plan 1 | ac553d8b-398e-4058-95c3-ac796ec1c327--779930332
 | Plan 1 | ac553d8b-398e-4058-95c3-ac796ec1c327--779930462
 | Plan 1 | ac553d8b-398e-4058-95c3-ac796ec1c327--779930463
 | Plan 1 | ac553d8b-398e-4058-95c3-ac796ec1c327--779930464
 | Plan 1 | ac553d8b-398e-4058-95c3-ac796ec1c327--779930323
 | Plan 1 | ac553d8b-398e-4058-95c3-ac796ec1c327--779930324
 | Plan 1 | ac553d8b-398e-4058-95c3-ac796ec1c327--779930325
 | Plan 1 | ac553d8b-398e-4058-95c3-ac796ec1c327--779930539
 | Plan 1 | ac553d8b-398e-4058-95c3-ac796ec1c327--779930540
 | Plan 1 | ac553d8b-398e-4058-95c3-ac796ec1c327--779930541
 | Plan 1 | ac553d8b-398e-4058-95c3-ac796ec1c327--779929849
 | Plan 1 | ac553d8b-398e-4058-95c3-ac796ec1c327--779929850
 | Plan 1 | ac553d8b-398e-4058-95c3-ac796ec1c327--779929848
 | Plan 1 | ac553d8b-398e-4058-95c3-ac796ec1c327--779930344
 | Plan 1 | ac553d8b-398e-4058-95c3-ac796ec1c327--779930345
 | Plan 1 | ac553d8b-398e-4058-95c3-ac796ec1c327--779930346
 | Plan 1 | ac553d8b-398e-4058-95c3-ac796ec1c327--779930381
 | Plan 1 | ac553d8b-398e-4058-95c3-ac796ec1c327--779930382
 | Plan 1 | ac553d8b-398e-4058-95c3-ac796ec1c327--779930383
 | Plan 1 | ac553d8b-398e-4058-95c3-ac796ec1c327--779930361
 | Plan 1 | ac553d8b-398e-4058-95c3-ac796ec1c327--779930362
 | Plan 1 | ac553d8b-398e-4058-95c3-ac796ec1c327--779930363
 | Plan 2 | 84cb5e05-e28d-4939-8977-531e4630a18c--780007082
 | Plan 2 | 84cb5e05-e28d-4939-8977-531e4630a18c--780007083
 | Plan 2 | 84cb5e05-e28d-4939-8977-531e4630a18c--780007084
 | Plan 2 | 84cb5e05-e28d-4939-8977-531e4630a18c--780007085
 | Plan 2 | 84cb5e05-e28d-4939-8977-531e4630a18c--780007086
 | Plan 2 | 84cb5e05-e28d-4939-8977-531e4630a18c--780007087
 | Plan 2 | 84cb5e05-e28d-4939-8977-531e4630a18c--780007088
 | Plan 2 | 84cb5e05-e28d-4939-8977-531e4630a18c--780007089
 | Plan 2 | 84cb5e05-e28d-4939-8977-531e4630a18c--780007090
 | Plan 2 | 84cb5e05-e28d-4939-8977-531e4630a18c--780007091
 | Plan 2 | 84cb5e05-e28d-4939-8977-531e4630a18c--780007092
 | Plan 2 | 84cb5e05-e28d-4939-8977-531e4630a18c--780007093
 | Plan 2 | 84cb5e05-e28d-4939-8977-531e4630a18c--780007094
 | Plan 2 | 84cb5e05-e28d-4939-8977-531e4630a18c--780007095
 | Plan 2 | 84cb5e05-e28d-4939-8977-531e4630a18c--780007096
 | Plan 2 | 84cb5e05-e28d-4939-8977-531e4630a18c--780007097
 | Plan 2 | 84cb5e05-e28d-4939-8977-531e4630a18c--780007098
 | Plan 2 | 84cb5e05-e28d-4939-8977-531e4630a18c--780007099
 | Plan 2 | 84cb5e05-e28d-4939-8977-531e4630a18c--779986446
 | Plan 2 | 84cb5e05-e28d-4939-8977-531e4630a18c--779986450
 | Plan 2 | 84cb5e05-e28d-4939-8977-531e4630a18c--779986484
 | Plan 2 | 84cb5e05-e28d-4939-8977-531e4630a18c--779986488
 | Plan 2 | 84cb5e05-e28d-4939-8977-531e4630a18c--780007237
 | Plan 2 | 84cb5e05-e28d-4939-8977-531e4630a18c--780007240
 | Plan 2 | 84cb5e05-e28d-4939-8977-531e4630a18c--779986522
 | Plan 2 | 84cb5e05-e28d-4939-8977-531e4630a18c--779986526
 | Plan 2 | 84cb5e05-e28d-4939-8977-531e4630a18c--779994873
 | Plan 2 | 84cb5e05-e28d-4939-8977-531e4630a18c--779994877
 | Plan 2 | 84cb5e05-e28d-4939-8977-531e4630a18c--779986332
 | Plan 2 | 84cb5e05-e28d-4939-8977-531e4630a18c--779986336
 | Plan 2 | 84cb5e05-e28d-4939-8977-531e4630a18c--779986370
 | Plan 2 | 84cb5e05-e28d-4939-8977-531e4630a18c--779986374
 | Plan 2 | 84cb5e05-e28d-4939-8977-531e4630a18c--779986294
 | Plan 2 | 84cb5e05-e28d-4939-8977-531e4630a18c--779986298
 | Plan 2 | 84cb5e05-e28d-4939-8977-531e4630a18c--779986408
 | Plan 2 | 84cb5e05-e28d-4939-8977-531e4630a18c--779986412
 | Plan 2 | 84cb5e05-e28d-4939-8977-531e4630a18c--779986560
 | Plan 2 | 84cb5e05-e28d-4939-8977-531e4630a18c--779986564
 | Plan 2 | 84cb5e05-e28d-4939-8977-531e4630a18c--779991094
 | Plan 2 | 84cb5e05-e28d-4939-8977-531e4630a18c--779991095
 | Plan 2 | 84cb5e05-e28d-4939-8977-531e4630a18c--780007469
 | Plan 2 | 84cb5e05-e28d-4939-8977-531e4630a18c--780007461
 | Plan 2 | 84cb5e05-e28d-4939-8977-531e4630a18c--779986598
 | Plan 2 | 84cb5e05-e28d-4939-8977-531e4630a18c--779986602
 | Plan 2 | 84cb5e05-e28d-4939-8977-531e4630a18c--780007551
 | Plan 2 | 84cb5e05-e28d-4939-8977-531e4630a18c--779990323
 | Plan 2 | 84cb5e05-e28d-4939-8977-531e4630a18c--779990324
 | Plan 2 | 84cb5e05-e28d-4939-8977-531e4630a18c--780007645
 | Plan 2 | 84cb5e05-e28d-4939-8977-531e4630a18c--779986654
 | Plan 2 | 84cb5e05-e28d-4939-8977-531e4630a18c--779986658
 | Plan 2 | 84cb5e05-e28d-4939-8977-531e4630a18c--780007695
 | Plan 2 | 84cb5e05-e28d-4939-8977-531e4630a18c--779994988
 | Plan 2 | 84cb5e05-e28d-4939-8977-531e4630a18c--779994989
 | Plan 2 | 84cb5e05-e28d-4939-8977-531e4630a18c--780007740
 | Plan 2 | 84cb5e05-e28d-4939-8977-531e4630a18c--779986730
 | Plan 2 | 84cb5e05-e28d-4939-8977-531e4630a18c--779986734
 | Plan 2 | 84cb5e05-e28d-4939-8977-531e4630a18c--780007748
 | Plan 2 | 84cb5e05-e28d-4939-8977-531e4630a18c--780007243
 | Plan 2 | 84cb5e05-e28d-4939-8977-531e4630a18c--780007307
 | Plan 2 | 84cb5e05-e28d-4939-8977-531e4630a18c--780007325
 | Plan 2 | 84cb5e05-e28d-4939-8977-531e4630a18c--780007334
 | Plan 2 | 84cb5e05-e28d-4939-8977-531e4630a18c--780007316
 | Plan 2 | 84cb5e05-e28d-4939-8977-531e4630a18c--780007343
 | Plan 2 | 84cb5e05-e28d-4939-8977-531e4630a18c--780005767
 | Plan 2 | 84cb5e05-e28d-4939-8977-531e4630a18c--780005771
 | Plan 2 | 84cb5e05-e28d-4939-8977-531e4630a18c--780007887
 | Plan 2 | 84cb5e05-e28d-4939-8977-531e4630a18c--780007101
 | Plan 2 | 84cb5e05-e28d-4939-8977-531e4630a18c--780007100
 | Plan 2 | 84cb5e05-e28d-4939-8977-531e4630a18c--779986200
 | Plan 2 | 84cb5e05-e28d-4939-8977-531e4630a18c--779986204
 | Plan 2 | 84cb5e05-e28d-4939-8977-531e4630a18c--779986124
 | Plan 2 | 84cb5e05-e28d-4939-8977-531e4630a18c--779986128
 | Plan 2 | 84cb5e05-e28d-4939-8977-531e4630a18c--780008014
 | Plan 2 | 84cb5e05-e28d-4939-8977-531e4630a18c--780007895
 | Plan 2 | ffc0a4b9-6ff1-450c-9901-90887e5cf058--779995313
 | Plan 2 | ffc0a4b9-6ff1-450c-9901-90887e5cf058--779995314
 | Plan 2 | ffc0a4b9-6ff1-450c-9901-90887e5cf058--780023188
 | Plan 2 | ffc0a4b9-6ff1-450c-9901-90887e5cf058--780026961
 | Plan 2 | ffc0a4b9-6ff1-450c-9901-90887e5cf058--780026965
 | Plan 2 | ffc0a4b9-6ff1-450c-9901-90887e5cf058--780027819
 | Plan 2 | ffc0a4b9-6ff1-450c-9901-90887e5cf058--779993281
 | Plan 2 | ffc0a4b9-6ff1-450c-9901-90887e5cf058--779993285
 | Plan 2 | ffc0a4b9-6ff1-450c-9901-90887e5cf058--780027843
 | Plan 2 | ffc0a4b9-6ff1-450c-9901-90887e5cf058--779993337
 | Plan 2 | ffc0a4b9-6ff1-450c-9901-90887e5cf058--779993341
 | Plan 2 | ffc0a4b9-6ff1-450c-9901-90887e5cf058--780027894
 | Plan 2 | ffc0a4b9-6ff1-450c-9901-90887e5cf058--779993375
 | Plan 2 | ffc0a4b9-6ff1-450c-9901-90887e5cf058--779993379
 | Plan 2 | ffc0a4b9-6ff1-450c-9901-90887e5cf058--780027962
 | Plan 2 | ffc0a4b9-6ff1-450c-9901-90887e5cf058--779994441
 | Plan 2 | ffc0a4b9-6ff1-450c-9901-90887e5cf058--779994445
 | Plan 2 | ffc0a4b9-6ff1-450c-9901-90887e5cf058--780028166
 | Plan 2 | ffc0a4b9-6ff1-450c-9901-90887e5cf058--779993487
 | Plan 2 | ffc0a4b9-6ff1-450c-9901-90887e5cf058--779993491
 | Plan 2 | ffc0a4b9-6ff1-450c-9901-90887e5cf058--780028202
 | Plan 2 | ffc0a4b9-6ff1-450c-9901-90887e5cf058--779986210
 | Plan 2 | ffc0a4b9-6ff1-450c-9901-90887e5cf058--779986212
 | Plan 2 | ffc0a4b9-6ff1-450c-9901-90887e5cf058--779988963
 | Plan 2 | ffc0a4b9-6ff1-450c-9901-90887e5cf058--779988965
 | Plan 2 | ffc0a4b9-6ff1-450c-9901-90887e5cf058--779989013
 | Plan 2 | ffc0a4b9-6ff1-450c-9901-90887e5cf058--779989015
 | Plan 2 | ffc0a4b9-6ff1-450c-9901-90887e5cf058--780026127
 | Plan 2 | ffc0a4b9-6ff1-450c-9901-90887e5cf058--780026131
 | Plan 2 | ffc0a4b9-6ff1-450c-9901-90887e5cf058--779988820
 | Plan 2 | ffc0a4b9-6ff1-450c-9901-90887e5cf058--779988822
 | Plan 2 | ffc0a4b9-6ff1-450c-9901-90887e5cf058--779987388
 | Plan 2 | ffc0a4b9-6ff1-450c-9901-90887e5cf058--779987390
 | Plan 2 | ffc0a4b9-6ff1-450c-9901-90887e5cf058--779986870
 | Plan 2 | ffc0a4b9-6ff1-450c-9901-90887e5cf058--779986872
 | Plan 2 | ffc0a4b9-6ff1-450c-9901-90887e5cf058--779986777
 | Plan 2 | ffc0a4b9-6ff1-450c-9901-90887e5cf058--779986779
 | Plan 2 | ffc0a4b9-6ff1-450c-9901-90887e5cf058--779993431
 | Plan 2 | ffc0a4b9-6ff1-450c-9901-90887e5cf058--779993435
 | Plan 2 | ffc0a4b9-6ff1-450c-9901-90887e5cf058--780028288
 | Plan 2 | ffc0a4b9-6ff1-450c-9901-90887e5cf058--780028350
 | Plan 2 | ffc0a4b9-6ff1-450c-9901-90887e5cf058--780028379
 | Plan 2 | ffc0a4b9-6ff1-450c-9901-90887e5cf058--780028405
 | Plan 2 | ffc0a4b9-6ff1-450c-9901-90887e5cf058--780028431
 | Plan 2 | ffc0a4b9-6ff1-450c-9901-90887e5cf058--780028457
 | Plan 2 | ffc0a4b9-6ff1-450c-9901-90887e5cf058--780028483
 | Plan 2 | ffc0a4b9-6ff1-450c-9901-90887e5cf058--780028509
 | Plan 2 | ffc0a4b9-6ff1-450c-9901-90887e5cf058--780028626
 | Plan 2 | ffc0a4b9-6ff1-450c-9901-90887e5cf058--779995679
 | Plan 2 | ffc0a4b9-6ff1-450c-9901-90887e5cf058--779995683
 | Plan 2 | ffc0a4b9-6ff1-450c-9901-90887e5cf058--780028756
 | Plan 2 | ffc0a4b9-6ff1-450c-9901-90887e5cf058--779995621
 | Plan 2 | ffc0a4b9-6ff1-450c-9901-90887e5cf058--779995625
 | Plan 2 | ffc0a4b9-6ff1-450c-9901-90887e5cf058--780028783
 | Plan 2 | ffc0a4b9-6ff1-450c-9901-90887e5cf058--779993621
 | Plan 2 | ffc0a4b9-6ff1-450c-9901-90887e5cf058--779993625
 | Plan 2 | ffc0a4b9-6ff1-450c-9901-90887e5cf058--779993813
 | Plan 2 | ffc0a4b9-6ff1-450c-9901-90887e5cf058--779993817
 | Plan 2 | ffc0a4b9-6ff1-450c-9901-90887e5cf058--779993775
 | Plan 2 | ffc0a4b9-6ff1-450c-9901-90887e5cf058--779993779
 | Plan 2 | ffc0a4b9-6ff1-450c-9901-90887e5cf058--779993851
 | Plan 2 | ffc0a4b9-6ff1-450c-9901-90887e5cf058--779993855
 | Plan 2 | ffc0a4b9-6ff1-450c-9901-90887e5cf058--779993737
 | Plan 2 | ffc0a4b9-6ff1-450c-9901-90887e5cf058--779993741
 | Plan 2 | ffc0a4b9-6ff1-450c-9901-90887e5cf058--779993659
 | Plan 2 | ffc0a4b9-6ff1-450c-9901-90887e5cf058--779993663
 | Plan 2 | ffc0a4b9-6ff1-450c-9901-90887e5cf058--780025423
 | Plan 2 | ffc0a4b9-6ff1-450c-9901-90887e5cf058--780025427
 | Plan 2 | ffc0a4b9-6ff1-450c-9901-90887e5cf058--780028809
 | Plan 2 | ffc0a4b9-6ff1-450c-9901-90887e5cf058--780028835
 | Plan 2 | ffc0a4b9-6ff1-450c-9901-90887e5cf058--780028857
 | Plan 2 | ffc0a4b9-6ff1-450c-9901-90887e5cf058--780028890
 | Plan 2 | ffc0a4b9-6ff1-450c-9901-90887e5cf058--780028846
 | Plan 2 | ffc0a4b9-6ff1-450c-9901-90887e5cf058--780028879
 | Plan 2 | ffc0a4b9-6ff1-450c-9901-90887e5cf058--780028868
 | Plan 2 | 3ec40862-3d69-4019-a81b-24095b11a5d8--779993814
 | Plan 2 | 3ec40862-3d69-4019-a81b-24095b11a5d8--779993815
 | Plan 2 | 3ec40862-3d69-4019-a81b-24095b11a5d8--779993816
 | Plan 2 | 3ec40862-3d69-4019-a81b-24095b11a5d8--779993817
 | Plan 2 | 3ec40862-3d69-4019-a81b-24095b11a5d8--779993818
 | Plan 2 | 3ec40862-3d69-4019-a81b-24095b11a5d8--779993819
 | Plan 2 | 3ec40862-3d69-4019-a81b-24095b11a5d8--779993820
 | Plan 2 | 3ec40862-3d69-4019-a81b-24095b11a5d8--779993821
 | Plan 2 | 3ec40862-3d69-4019-a81b-24095b11a5d8--779993822
 | Plan 2 | 3ec40862-3d69-4019-a81b-24095b11a5d8--779993823
 | Plan 2 | 3ec40862-3d69-4019-a81b-24095b11a5d8--779993824
 | Plan 2 | 3ec40862-3d69-4019-a81b-24095b11a5d8--779993830
 | Plan 2 | 3ec40862-3d69-4019-a81b-24095b11a5d8--779993832
 | Plan 2 | 3ec40862-3d69-4019-a81b-24095b11a5d8--779993833
 | Plan 2 | 3ec40862-3d69-4019-a81b-24095b11a5d8--779993834
 | Plan 2 | 3ec40862-3d69-4019-a81b-24095b11a5d8--779993835
 | Plan 2 | 3ec40862-3d69-4019-a81b-24095b11a5d8--779993836
 | Plan 2 | 3ec40862-3d69-4019-a81b-24095b11a5d8--779993837
 | Plan 2 | 3ec40862-3d69-4019-a81b-24095b11a5d8--779993838
 | Plan 2 | 3ec40862-3d69-4019-a81b-24095b11a5d8--779993839
 | Plan 2 | 3ec40862-3d69-4019-a81b-24095b11a5d8--779993840
 | Plan 2 | 3ec40862-3d69-4019-a81b-24095b11a5d8--779993841
 | Plan 2 | 3ec40862-3d69-4019-a81b-24095b11a5d8--779993828
 | Plan 2 | 3ec40862-3d69-4019-a81b-24095b11a5d8--779993829
 | Plan 2 | 3ec40862-3d69-4019-a81b-24095b11a5d8--779993831
 | Plan 2 | 3ec40862-3d69-4019-a81b-24095b11a5d8--779993940
 | Plan 2 | 3ec40862-3d69-4019-a81b-24095b11a5d8--779993941
 | Plan 2 | 3ec40862-3d69-4019-a81b-24095b11a5d8--779993942
 | Plan 2 | 3ec40862-3d69-4019-a81b-24095b11a5d8--779993943
 | Plan 2 | 3ec40862-3d69-4019-a81b-24095b11a5d8--779993944
 | Plan 2 | 3ec40862-3d69-4019-a81b-24095b11a5d8--779993945
 | Plan 2 | 3ec40862-3d69-4019-a81b-24095b11a5d8--779993946
 | Plan 2 | 3ec40862-3d69-4019-a81b-24095b11a5d8--779993947
 | Plan 2 | 3ec40862-3d69-4019-a81b-24095b11a5d8--779993948
 | Plan 2 | 3ec40862-3d69-4019-a81b-24095b11a5d8--779993949
 | Plan 2 | 3ec40862-3d69-4019-a81b-24095b11a5d8--779993950
 | Plan 2 | 3ec40862-3d69-4019-a81b-24095b11a5d8--779993951
 | Plan 2 | 3ec40862-3d69-4019-a81b-24095b11a5d8--779993952
 | Plan 2 | 3ec40862-3d69-4019-a81b-24095b11a5d8--779993953
 | Plan 2 | 3ec40862-3d69-4019-a81b-24095b11a5d8--779993954
 | Plan 2 | 3ec40862-3d69-4019-a81b-24095b11a5d8--779993955
 | Plan 2 | 3ec40862-3d69-4019-a81b-24095b11a5d8--779993956
 | Plan 2 | 3ec40862-3d69-4019-a81b-24095b11a5d8--779993957
 | Plan 2 | 3ec40862-3d69-4019-a81b-24095b11a5d8--779993958
 | Plan 2 | 3ec40862-3d69-4019-a81b-24095b11a5d8--779993959
 | Plan 2 | 3ec40862-3d69-4019-a81b-24095b11a5d8--779993960
 | Plan 2 | 3ec40862-3d69-4019-a81b-24095b11a5d8--779993961
 | Plan 2 | 3ec40862-3d69-4019-a81b-24095b11a5d8--779993962
 | Plan 2 | 3ec40862-3d69-4019-a81b-24095b11a5d8--779993963
 | Plan 2 | 3ec40862-3d69-4019-a81b-24095b11a5d8--779993964
 | Plan 2 | 3ec40862-3d69-4019-a81b-24095b11a5d8--779993965
 | Plan 2 | 3ec40862-3d69-4019-a81b-24095b11a5d8--779993966
 | Plan 2 | 3ec40862-3d69-4019-a81b-24095b11a5d8--779993967
 | Plan 2 | 3ec40862-3d69-4019-a81b-24095b11a5d8--779993968
 | Plan 2 | 3ec40862-3d69-4019-a81b-24095b11a5d8--779993969
 | Plan 2 | 3ec40862-3d69-4019-a81b-24095b11a5d8--779993970
 | Plan 2 | 3ec40862-3d69-4019-a81b-24095b11a5d8--779993971
 | Plan 2 | 3ec40862-3d69-4019-a81b-24095b11a5d8--779993972
 | Plan 2 | 3ec40862-3d69-4019-a81b-24095b11a5d8--779993973
 | Plan 2 | 3ec40862-3d69-4019-a81b-24095b11a5d8--779993974
 | Plan 2 | 3ec40862-3d69-4019-a81b-24095b11a5d8--779993975
 | Plan 2 | 3ec40862-3d69-4019-a81b-24095b11a5d8--779993976
 | Plan 2 | 3ec40862-3d69-4019-a81b-24095b11a5d8--779993977
 | Plan 2 | 3ec40862-3d69-4019-a81b-24095b11a5d8--779993978
 | Plan 2 | 3ec40862-3d69-4019-a81b-24095b11a5d8--779993979
 | Plan 2 | 3ec40862-3d69-4019-a81b-24095b11a5d8--779993980
 | Plan 2 | 3ec40862-3d69-4019-a81b-24095b11a5d8--779993981
 | Plan 2 | 3ec40862-3d69-4019-a81b-24095b11a5d8--779993982
 | Plan 2 | 3ec40862-3d69-4019-a81b-24095b11a5d8--779993983
 | Plan 2 | 3ec40862-3d69-4019-a81b-24095b11a5d8--779993984
 | Plan 2 | 3ec40862-3d69-4019-a81b-24095b11a5d8--779993985
 | Plan 2 | 3ec40862-3d69-4019-a81b-24095b11a5d8--779993986
 | Plan 2 | 3ec40862-3d69-4019-a81b-24095b11a5d8--779993987
 | Plan 2 | 3ec40862-3d69-4019-a81b-24095b11a5d8--779993988
 | Plan 2 | 3ec40862-3d69-4019-a81b-24095b11a5d8--779993989
 | Plan 2 | 3ec40862-3d69-4019-a81b-24095b11a5d8--779993990
 | Plan 2 | 3ec40862-3d69-4019-a81b-24095b11a5d8--779993991
 | Plan 2 | 3ec40862-3d69-4019-a81b-24095b11a5d8--779993992
 | Plan 2 | 3ec40862-3d69-4019-a81b-24095b11a5d8--779993993
 | Plan 2 | 3ec40862-3d69-4019-a81b-24095b11a5d8--779993994
 | Plan 2 | 3ec40862-3d69-4019-a81b-24095b11a5d8--779993995
 | Plan 2 | 3ec40862-3d69-4019-a81b-24095b11a5d8--779993996
 | Plan 2 | 3ec40862-3d69-4019-a81b-24095b11a5d8--779993997
 | Plan 2 | 3ec40862-3d69-4019-a81b-24095b11a5d8--779993998
 | Plan 2 | 3ec40862-3d69-4019-a81b-24095b11a5d8--779993999
 | Plan 2 | 3ec40862-3d69-4019-a81b-24095b11a5d8--779994000
 | Plan 2 | 3ec40862-3d69-4019-a81b-24095b11a5d8--779994001
 | Plan 2 | 3ec40862-3d69-4019-a81b-24095b11a5d8--779994002
 | Plan 2 | 3ec40862-3d69-4019-a81b-24095b11a5d8--779994003
 | Plan 2 | 3ec40862-3d69-4019-a81b-24095b11a5d8--779994004
 | Plan 2 | 3ec40862-3d69-4019-a81b-24095b11a5d8--779994005
 | Plan 2 | 3ec40862-3d69-4019-a81b-24095b11a5d8--779994006
 | Plan 2 | 3ec40862-3d69-4019-a81b-24095b11a5d8--779994007
 | Plan 2 | 3ec40862-3d69-4019-a81b-24095b11a5d8--779994008
 | Plan 2 | 3ec40862-3d69-4019-a81b-24095b11a5d8--779994009
 | Plan 2 | 3ec40862-3d69-4019-a81b-24095b11a5d8--779994010
 | Plan 2 | 3ec40862-3d69-4019-a81b-24095b11a5d8--779994011
 | Plan 2 | 3ec40862-3d69-4019-a81b-24095b11a5d8--779994012
 | Plan 2 | 3ec40862-3d69-4019-a81b-24095b11a5d8--779994013
 | Plan 2 | 3ec40862-3d69-4019-a81b-24095b11a5d8--779994014
 | Plan 2 | 3ec40862-3d69-4019-a81b-24095b11a5d8--779994015
 | Plan 2 | 3ec40862-3d69-4019-a81b-24095b11a5d8--779994016
 | Plan 2 | 3ec40862-3d69-4019-a81b-24095b11a5d8--779994017
 | Plan 2 | 3ec40862-3d69-4019-a81b-24095b11a5d8--779994018
 | Plan 2 | 3ec40862-3d69-4019-a81b-24095b11a5d8--779994019
 | Plan 2 | 3ec40862-3d69-4019-a81b-24095b11a5d8--779994020
 | Plan 2 | 3ec40862-3d69-4019-a81b-24095b11a5d8--779994021
 | Plan 2 | 3ec40862-3d69-4019-a81b-24095b11a5d8--779994022
 | Plan 2 | 3ec40862-3d69-4019-a81b-24095b11a5d8--779994023
 | Plan 2 | 3ec40862-3d69-4019-a81b-24095b11a5d8--779994024
 | Plan 2 | 3ec40862-3d69-4019-a81b-24095b11a5d8--779994025
 | Plan 2 | 3ec40862-3d69-4019-a81b-24095b11a5d8--779994026
 | Plan 2 | 3ec40862-3d69-4019-a81b-24095b11a5d8--779994027
 | Plan 2 | 3ec40862-3d69-4019-a81b-24095b11a5d8--779994028
 | Plan 2 | 3ec40862-3d69-4019-a81b-24095b11a5d8--779994029
 | Plan 2 | 3ec40862-3d69-4019-a81b-24095b11a5d8--779994030
 | Plan 2 | 3ec40862-3d69-4019-a81b-24095b11a5d8--779994031
 | Plan 2 | 3ec40862-3d69-4019-a81b-24095b11a5d8--779994032
 | Plan 2 | 3ec40862-3d69-4019-a81b-24095b11a5d8--779994033
 | Plan 2 | 3ec40862-3d69-4019-a81b-24095b11a5d8--779994034
 | Plan 2 | 3ec40862-3d69-4019-a81b-24095b11a5d8--779994035
 | Plan 2 | 3ec40862-3d69-4019-a81b-24095b11a5d8--779994036
 | Plan 2 | 3ec40862-3d69-4019-a81b-24095b11a5d8--779994037
 | Plan 2 | 3ec40862-3d69-4019-a81b-24095b11a5d8--779993825
 | Plan 2 | 3ec40862-3d69-4019-a81b-24095b11a5d8--779993826
 | Plan 2 | 3ec40862-3d69-4019-a81b-24095b11a5d8--779993827
 | Plan 2 | 3ec40862-3d69-4019-a81b-24095b11a5d8--779994052
 | Plan 2 | 3ec40862-3d69-4019-a81b-24095b11a5d8--779994053
 | Plan 2 | 3ec40862-3d69-4019-a81b-24095b11a5d8--779994054
 | Plan 2 | 3ec40862-3d69-4019-a81b-24095b11a5d8--779994055
 | Plan 2 | 3ec40862-3d69-4019-a81b-24095b11a5d8--779994072
 | Plan 2 | 3ec40862-3d69-4019-a81b-24095b11a5d8--779994073
 | Plan 2 | 3ec40862-3d69-4019-a81b-24095b11a5d8--779994074
 | Plan 2 | 3ec40862-3d69-4019-a81b-24095b11a5d8--779994075
 | Plan 2 | 3ec40862-3d69-4019-a81b-24095b11a5d8--779994076
 | Plan 2 | 3ec40862-3d69-4019-a81b-24095b11a5d8--779994077
 | Plan 2 | 3ec40862-3d69-4019-a81b-24095b11a5d8--779994078
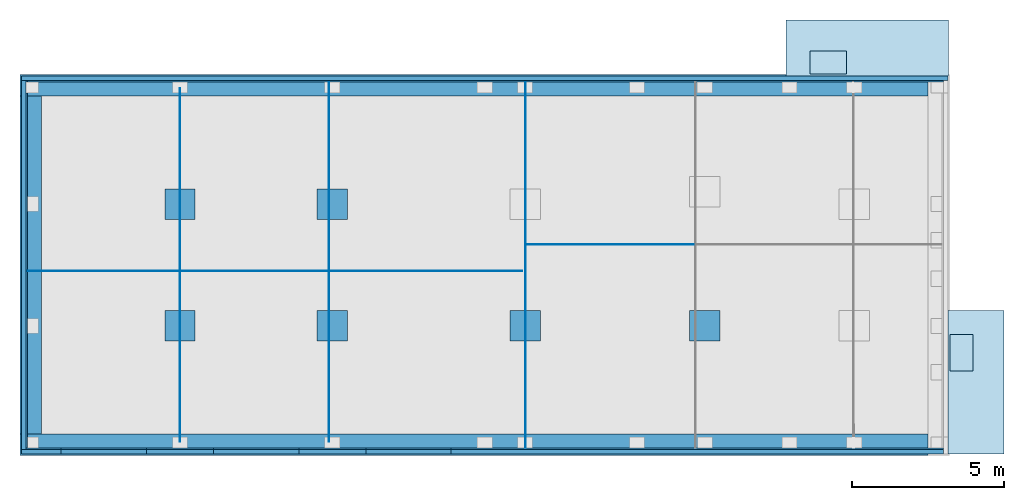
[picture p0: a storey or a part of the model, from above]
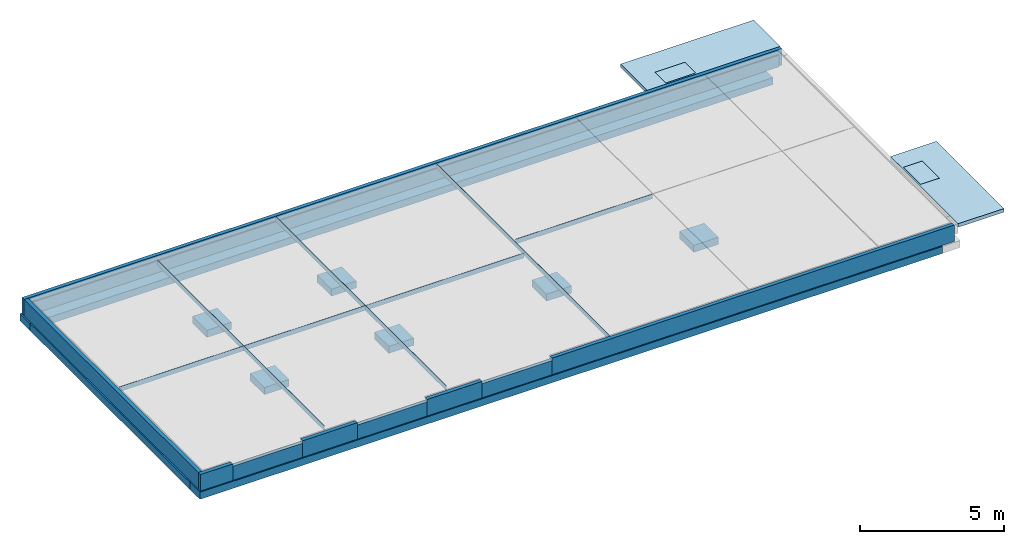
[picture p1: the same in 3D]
Properties of the parts of a building model (IFC2X3), part 3 of 7

# IfcAnnotation (2236)
Name | In | NOI_UUID
 | Plan 2 | 3ec40862-3d69-4019-a81b-24095b11a5d8--779994089
 | Plan 2 | 3ec40862-3d69-4019-a81b-24095b11a5d8--779994058
 | Plan 2 | 3ec40862-3d69-4019-a81b-24095b11a5d8--779994059
 | Plan 2 | 3ec40862-3d69-4019-a81b-24095b11a5d8--779994060
 | Plan 2 | 3ec40862-3d69-4019-a81b-24095b11a5d8--779994061
 | Plan 2 | 3ec40862-3d69-4019-a81b-24095b11a5d8--779994062
 | Plan 2 | 3ec40862-3d69-4019-a81b-24095b11a5d8--779994063
 | Plan 2 | 3ec40862-3d69-4019-a81b-24095b11a5d8--779994064
 | Plan 2 | 3ec40862-3d69-4019-a81b-24095b11a5d8--779994065
 | Plan 2 | 3ec40862-3d69-4019-a81b-24095b11a5d8--779994066
 | Plan 2 | 3ec40862-3d69-4019-a81b-24095b11a5d8--779994067
 | Plan 2 | 3ec40862-3d69-4019-a81b-24095b11a5d8--779994068
 | Plan 2 | 3ec40862-3d69-4019-a81b-24095b11a5d8--779994069
 | Plan 2 | 3ec40862-3d69-4019-a81b-24095b11a5d8--779994070
 | Plan 2 | 3ec40862-3d69-4019-a81b-24095b11a5d8--779994071
 | Plan 2 | 3ec40862-3d69-4019-a81b-24095b11a5d8--779994090
 | Plan 2 | 3ec40862-3d69-4019-a81b-24095b11a5d8--779994227
 | Plan 2 | 3ec40862-3d69-4019-a81b-24095b11a5d8--779993884
 | Plan 2 | 3ec40862-3d69-4019-a81b-24095b11a5d8--779993885
 | Plan 2 | 3ec40862-3d69-4019-a81b-24095b11a5d8--779993886
 | Plan 2 | 3ec40862-3d69-4019-a81b-24095b11a5d8--779993887
 | Plan 2 | 3ec40862-3d69-4019-a81b-24095b11a5d8--779993888
 | Plan 2 | 3ec40862-3d69-4019-a81b-24095b11a5d8--779993889
 | Plan 2 | 3ec40862-3d69-4019-a81b-24095b11a5d8--779993890
 | Plan 2 | 3ec40862-3d69-4019-a81b-24095b11a5d8--779993891
 | Plan 2 | 3ec40862-3d69-4019-a81b-24095b11a5d8--779993892
 | Plan 2 | 3ec40862-3d69-4019-a81b-24095b11a5d8--779993893
 | Plan 2 | 3ec40862-3d69-4019-a81b-24095b11a5d8--779993894
 | Plan 2 | 3ec40862-3d69-4019-a81b-24095b11a5d8--779993898
 | Plan 2 | 3ec40862-3d69-4019-a81b-24095b11a5d8--779993899
 | Plan 2 | 3ec40862-3d69-4019-a81b-24095b11a5d8--779993900
 | Plan 2 | 3ec40862-3d69-4019-a81b-24095b11a5d8--779993901
 | Plan 2 | 3ec40862-3d69-4019-a81b-24095b11a5d8--779993902
 | Plan 2 | 3ec40862-3d69-4019-a81b-24095b11a5d8--779993903
 | Plan 2 | 3ec40862-3d69-4019-a81b-24095b11a5d8--779993904
 | Plan 2 | 3ec40862-3d69-4019-a81b-24095b11a5d8--779993905
 | Plan 2 | 3ec40862-3d69-4019-a81b-24095b11a5d8--779993906
 | Plan 2 | 3ec40862-3d69-4019-a81b-24095b11a5d8--779993907
 | Plan 2 | 3ec40862-3d69-4019-a81b-24095b11a5d8--779993908
 | Plan 2 | 3ec40862-3d69-4019-a81b-24095b11a5d8--779993909
 | Plan 2 | 3ec40862-3d69-4019-a81b-24095b11a5d8--779993910
 | Plan 2 | 3ec40862-3d69-4019-a81b-24095b11a5d8--779993911
 | Plan 2 | 3ec40862-3d69-4019-a81b-24095b11a5d8--779993895
 | Plan 2 | 3ec40862-3d69-4019-a81b-24095b11a5d8--779993896
 | Plan 2 | 3ec40862-3d69-4019-a81b-24095b11a5d8--779993897
 | Plan 2 | 3ec40862-3d69-4019-a81b-24095b11a5d8--779993912
 | Plan 2 | 3ec40862-3d69-4019-a81b-24095b11a5d8--779993913
 | Plan 2 | 3ec40862-3d69-4019-a81b-24095b11a5d8--779993914
 | Plan 2 | 3ec40862-3d69-4019-a81b-24095b11a5d8--779993915
 | Plan 2 | 3ec40862-3d69-4019-a81b-24095b11a5d8--779993916
 | Plan 2 | 3ec40862-3d69-4019-a81b-24095b11a5d8--779993917
 | Plan 2 | 3ec40862-3d69-4019-a81b-24095b11a5d8--779993918
 | Plan 2 | 3ec40862-3d69-4019-a81b-24095b11a5d8--779993919
 | Plan 2 | 3ec40862-3d69-4019-a81b-24095b11a5d8--779993920
 | Plan 2 | 3ec40862-3d69-4019-a81b-24095b11a5d8--779993921
 | Plan 2 | 3ec40862-3d69-4019-a81b-24095b11a5d8--779993922
 | Plan 2 | 3ec40862-3d69-4019-a81b-24095b11a5d8--779993926
 | Plan 2 | 3ec40862-3d69-4019-a81b-24095b11a5d8--779993927
 | Plan 2 | 3ec40862-3d69-4019-a81b-24095b11a5d8--779993928
 | Plan 2 | 3ec40862-3d69-4019-a81b-24095b11a5d8--779993929
 | Plan 2 | 3ec40862-3d69-4019-a81b-24095b11a5d8--779993930
 | Plan 2 | 3ec40862-3d69-4019-a81b-24095b11a5d8--779993931
 | Plan 2 | 3ec40862-3d69-4019-a81b-24095b11a5d8--779993932
 | Plan 2 | 3ec40862-3d69-4019-a81b-24095b11a5d8--779993933
 | Plan 2 | 3ec40862-3d69-4019-a81b-24095b11a5d8--779993934
 | Plan 2 | 3ec40862-3d69-4019-a81b-24095b11a5d8--779993935
 | Plan 2 | 3ec40862-3d69-4019-a81b-24095b11a5d8--779993936
 | Plan 2 | 3ec40862-3d69-4019-a81b-24095b11a5d8--779993937
 | Plan 2 | 3ec40862-3d69-4019-a81b-24095b11a5d8--779993938
 | Plan 2 | 3ec40862-3d69-4019-a81b-24095b11a5d8--779993939
 | Plan 2 | 3ec40862-3d69-4019-a81b-24095b11a5d8--779993923
 | Plan 2 | 3ec40862-3d69-4019-a81b-24095b11a5d8--779993924
 | Plan 2 | 3ec40862-3d69-4019-a81b-24095b11a5d8--779993925
 | Plan 2 | 3ec40862-3d69-4019-a81b-24095b11a5d8--779993708
 | Plan 2 | 3ec40862-3d69-4019-a81b-24095b11a5d8--779993709
 | Plan 2 | 3ec40862-3d69-4019-a81b-24095b11a5d8--779993710
 | Plan 2 | 3ec40862-3d69-4019-a81b-24095b11a5d8--779993711
 | Plan 2 | 3ec40862-3d69-4019-a81b-24095b11a5d8--779993712
 | Plan 2 | 3ec40862-3d69-4019-a81b-24095b11a5d8--779993714
 | Plan 2 | 3ec40862-3d69-4019-a81b-24095b11a5d8--779993715
 | Plan 2 | 3ec40862-3d69-4019-a81b-24095b11a5d8--779994243
 | Plan 2 | 3ec40862-3d69-4019-a81b-24095b11a5d8--779994244
 | Plan 2 | 3ec40862-3d69-4019-a81b-24095b11a5d8--779994245
 | Plan 2 | 3ec40862-3d69-4019-a81b-24095b11a5d8--779994246
 | Plan 2 | 3ec40862-3d69-4019-a81b-24095b11a5d8--779994247
 | Plan 2 | 3ec40862-3d69-4019-a81b-24095b11a5d8--779994248
 | Plan 2 | 3ec40862-3d69-4019-a81b-24095b11a5d8--779994251
 | Plan 2 | 3ec40862-3d69-4019-a81b-24095b11a5d8--779994252
 | Plan 2 | 3ec40862-3d69-4019-a81b-24095b11a5d8--779994253
 | Plan 2 | 3ec40862-3d69-4019-a81b-24095b11a5d8--779994254
 | Plan 2 | 3ec40862-3d69-4019-a81b-24095b11a5d8--779994255
 | Plan 2 | 3ec40862-3d69-4019-a81b-24095b11a5d8--779994256
 | Plan 2 | 3ec40862-3d69-4019-a81b-24095b11a5d8--779994257
 | Plan 2 | 3ec40862-3d69-4019-a81b-24095b11a5d8--779994258
 | Plan 2 | 3ec40862-3d69-4019-a81b-24095b11a5d8--779994623
 | Plan 2 | 3ec40862-3d69-4019-a81b-24095b11a5d8--779994624
 | Plan 2 | 3ec40862-3d69-4019-a81b-24095b11a5d8--779994625
 | Plan 2 | 3ec40862-3d69-4019-a81b-24095b11a5d8--779994626
 | Plan 2 | 3ec40862-3d69-4019-a81b-24095b11a5d8--779994627
 | Plan 2 | 3ec40862-3d69-4019-a81b-24095b11a5d8--779994628
 | Plan 2 | 3ec40862-3d69-4019-a81b-24095b11a5d8--779994629
 | Plan 2 | 3ec40862-3d69-4019-a81b-24095b11a5d8--779994630
 | Plan 2 | 3ec40862-3d69-4019-a81b-24095b11a5d8--779994631
 | Plan 2 | 3ec40862-3d69-4019-a81b-24095b11a5d8--779994632
 | Plan 2 | 3ec40862-3d69-4019-a81b-24095b11a5d8--779994633
 | Plan 2 | 3ec40862-3d69-4019-a81b-24095b11a5d8--779994634
 | Plan 2 | 3ec40862-3d69-4019-a81b-24095b11a5d8--779994635
 | Plan 2 | 3ec40862-3d69-4019-a81b-24095b11a5d8--779994636
 | Plan 2 | 3ec40862-3d69-4019-a81b-24095b11a5d8--779994637
 | Plan 2 | 3ec40862-3d69-4019-a81b-24095b11a5d8--779994638
 | Plan 2 | 3ec40862-3d69-4019-a81b-24095b11a5d8--779994639
 | Plan 2 | 3ec40862-3d69-4019-a81b-24095b11a5d8--779994640
 | Plan 2 | 3ec40862-3d69-4019-a81b-24095b11a5d8--779994641
 | Plan 2 | 3ec40862-3d69-4019-a81b-24095b11a5d8--779994642
 | Plan 2 | 3ec40862-3d69-4019-a81b-24095b11a5d8--779994643
 | Plan 2 | 3ec40862-3d69-4019-a81b-24095b11a5d8--779994644
 | Plan 2 | 3ec40862-3d69-4019-a81b-24095b11a5d8--779994645
 | Plan 2 | 3ec40862-3d69-4019-a81b-24095b11a5d8--779994646
 | Plan 2 | 3ec40862-3d69-4019-a81b-24095b11a5d8--779994647
 | Plan 2 | 3ec40862-3d69-4019-a81b-24095b11a5d8--779994648
 | Plan 2 | 3ec40862-3d69-4019-a81b-24095b11a5d8--779994649
 | Plan 2 | 3ec40862-3d69-4019-a81b-24095b11a5d8--779994650
 | Plan 2 | 3ec40862-3d69-4019-a81b-24095b11a5d8--779994651
 | Plan 2 | 3ec40862-3d69-4019-a81b-24095b11a5d8--779994652
 | Plan 2 | 3ec40862-3d69-4019-a81b-24095b11a5d8--779994653
 | Plan 2 | 3ec40862-3d69-4019-a81b-24095b11a5d8--779994654
 | Plan 2 | 3ec40862-3d69-4019-a81b-24095b11a5d8--779994655
 | Plan 2 | 3ec40862-3d69-4019-a81b-24095b11a5d8--779994656
 | Plan 2 | 3ec40862-3d69-4019-a81b-24095b11a5d8--779994657
 | Plan 2 | 3ec40862-3d69-4019-a81b-24095b11a5d8--779994658
 | Plan 2 | 3ec40862-3d69-4019-a81b-24095b11a5d8--779994659
 | Plan 2 | 3ec40862-3d69-4019-a81b-24095b11a5d8--779994660
 | Plan 2 | 3ec40862-3d69-4019-a81b-24095b11a5d8--779994661
 | Plan 2 | 3ec40862-3d69-4019-a81b-24095b11a5d8--779994662
 | Plan 2 | 3ec40862-3d69-4019-a81b-24095b11a5d8--779994663
 | Plan 2 | 3ec40862-3d69-4019-a81b-24095b11a5d8--779994664
 | Plan 2 | 3ec40862-3d69-4019-a81b-24095b11a5d8--779994665
 | Plan 2 | 3ec40862-3d69-4019-a81b-24095b11a5d8--779994666
 | Plan 2 | 3ec40862-3d69-4019-a81b-24095b11a5d8--779994667
 | Plan 2 | 3ec40862-3d69-4019-a81b-24095b11a5d8--779994668
 | Plan 2 | 3ec40862-3d69-4019-a81b-24095b11a5d8--779994669
 | Plan 2 | 3ec40862-3d69-4019-a81b-24095b11a5d8--779994670
 | Plan 2 | 3ec40862-3d69-4019-a81b-24095b11a5d8--779994671
 | Plan 2 | 3ec40862-3d69-4019-a81b-24095b11a5d8--779994672
 | Plan 2 | 3ec40862-3d69-4019-a81b-24095b11a5d8--779994673
 | Plan 2 | 3ec40862-3d69-4019-a81b-24095b11a5d8--779994674
 | Plan 2 | 3ec40862-3d69-4019-a81b-24095b11a5d8--779994675
 | Plan 2 | 3ec40862-3d69-4019-a81b-24095b11a5d8--779994676
 | Plan 2 | 3ec40862-3d69-4019-a81b-24095b11a5d8--779994677
 | Plan 2 | 3ec40862-3d69-4019-a81b-24095b11a5d8--779994678
 | Plan 2 | 3ec40862-3d69-4019-a81b-24095b11a5d8--779994679
 | Plan 2 | 3ec40862-3d69-4019-a81b-24095b11a5d8--779994680
 | Plan 2 | 3ec40862-3d69-4019-a81b-24095b11a5d8--779994681
 | Plan 2 | 3ec40862-3d69-4019-a81b-24095b11a5d8--779994682
 | Plan 2 | 3ec40862-3d69-4019-a81b-24095b11a5d8--779994683
 | Plan 2 | 3ec40862-3d69-4019-a81b-24095b11a5d8--779994684
 | Plan 2 | 3ec40862-3d69-4019-a81b-24095b11a5d8--779994685
 | Plan 2 | 3ec40862-3d69-4019-a81b-24095b11a5d8--779994686
 | Plan 2 | 3ec40862-3d69-4019-a81b-24095b11a5d8--779994687
 | Plan 2 | 3ec40862-3d69-4019-a81b-24095b11a5d8--779994688
 | Plan 2 | 3ec40862-3d69-4019-a81b-24095b11a5d8--779994689
 | Plan 2 | 3ec40862-3d69-4019-a81b-24095b11a5d8--779994690
 | Plan 2 | 3ec40862-3d69-4019-a81b-24095b11a5d8--779994691
 | Plan 2 | 3ec40862-3d69-4019-a81b-24095b11a5d8--779994692
 | Plan 2 | 3ec40862-3d69-4019-a81b-24095b11a5d8--779994693
 | Plan 2 | 3ec40862-3d69-4019-a81b-24095b11a5d8--779994694
 | Plan 2 | 3ec40862-3d69-4019-a81b-24095b11a5d8--779994695
 | Plan 2 | 3ec40862-3d69-4019-a81b-24095b11a5d8--779994696
 | Plan 2 | 3ec40862-3d69-4019-a81b-24095b11a5d8--779994697
 | Plan 2 | 3ec40862-3d69-4019-a81b-24095b11a5d8--779994698
 | Plan 2 | 3ec40862-3d69-4019-a81b-24095b11a5d8--779994699
 | Plan 2 | 3ec40862-3d69-4019-a81b-24095b11a5d8--779994700
 | Plan 2 | 3ec40862-3d69-4019-a81b-24095b11a5d8--779994701
 | Plan 2 | 3ec40862-3d69-4019-a81b-24095b11a5d8--779994702
 | Plan 2 | 3ec40862-3d69-4019-a81b-24095b11a5d8--779994703
 | Plan 2 | 3ec40862-3d69-4019-a81b-24095b11a5d8--779994704
 | Plan 2 | 3ec40862-3d69-4019-a81b-24095b11a5d8--779994705
 | Plan 2 | 3ec40862-3d69-4019-a81b-24095b11a5d8--779994706
 | Plan 2 | 3ec40862-3d69-4019-a81b-24095b11a5d8--779994707
 | Plan 2 | 3ec40862-3d69-4019-a81b-24095b11a5d8--779994708
 | Plan 2 | 3ec40862-3d69-4019-a81b-24095b11a5d8--779994709
 | Plan 2 | 3ec40862-3d69-4019-a81b-24095b11a5d8--779994710
 | Plan 2 | 3ec40862-3d69-4019-a81b-24095b11a5d8--779994711
 | Plan 2 | 3ec40862-3d69-4019-a81b-24095b11a5d8--779994712
 | Plan 2 | 3ec40862-3d69-4019-a81b-24095b11a5d8--779994713
 | Plan 2 | 3ec40862-3d69-4019-a81b-24095b11a5d8--779994714
 | Plan 2 | 3ec40862-3d69-4019-a81b-24095b11a5d8--779994715
 | Plan 2 | 3ec40862-3d69-4019-a81b-24095b11a5d8--779994716
 | Plan 2 | 3ec40862-3d69-4019-a81b-24095b11a5d8--779994717
 | Plan 2 | 3ec40862-3d69-4019-a81b-24095b11a5d8--779994718
 | Plan 2 | 3ec40862-3d69-4019-a81b-24095b11a5d8--779994719
 | Plan 2 | 3ec40862-3d69-4019-a81b-24095b11a5d8--779994720
 | Plan 2 | 3ec40862-3d69-4019-a81b-24095b11a5d8--779994721
 | Plan 2 | 3ec40862-3d69-4019-a81b-24095b11a5d8--779994722
 | Plan 2 | 3ec40862-3d69-4019-a81b-24095b11a5d8--779994723
 | Plan 2 | 3ec40862-3d69-4019-a81b-24095b11a5d8--779994724
 | Plan 2 | 3ec40862-3d69-4019-a81b-24095b11a5d8--779994725
 | Plan 2 | 3ec40862-3d69-4019-a81b-24095b11a5d8--779994726
 | Plan 2 | 3ec40862-3d69-4019-a81b-24095b11a5d8--779994727
 | Plan 2 | 3ec40862-3d69-4019-a81b-24095b11a5d8--779994728
 | Plan 2 | 3ec40862-3d69-4019-a81b-24095b11a5d8--779994729
 | Plan 2 | 3ec40862-3d69-4019-a81b-24095b11a5d8--779994730
 | Plan 2 | 3ec40862-3d69-4019-a81b-24095b11a5d8--779994731
 | Plan 2 | 3ec40862-3d69-4019-a81b-24095b11a5d8--779994732
 | Plan 2 | 3ec40862-3d69-4019-a81b-24095b11a5d8--779994733
 | Plan 2 | 3ec40862-3d69-4019-a81b-24095b11a5d8--779994734
 | Plan 2 | 3ec40862-3d69-4019-a81b-24095b11a5d8--779994735
 | Plan 2 | 3ec40862-3d69-4019-a81b-24095b11a5d8--779994736
 | Plan 2 | 3ec40862-3d69-4019-a81b-24095b11a5d8--779994737
 | Plan 2 | 3ec40862-3d69-4019-a81b-24095b11a5d8--779994738
 | Plan 2 | 3ec40862-3d69-4019-a81b-24095b11a5d8--779994739
 | Plan 2 | 3ec40862-3d69-4019-a81b-24095b11a5d8--779994740
 | Plan 2 | 3ec40862-3d69-4019-a81b-24095b11a5d8--779994741
 | Plan 2 | 3ec40862-3d69-4019-a81b-24095b11a5d8--779994742
 | Plan 2 | 3ec40862-3d69-4019-a81b-24095b11a5d8--779994743
 | Plan 2 | 3ec40862-3d69-4019-a81b-24095b11a5d8--779994744
 | Plan 2 | 3ec40862-3d69-4019-a81b-24095b11a5d8--779994745
 | Plan 2 | 3ec40862-3d69-4019-a81b-24095b11a5d8--779994746
 | Plan 2 | 3ec40862-3d69-4019-a81b-24095b11a5d8--779994747
 | Plan 2 | 3ec40862-3d69-4019-a81b-24095b11a5d8--779994748
 | Plan 2 | 3ec40862-3d69-4019-a81b-24095b11a5d8--779994749
 | Plan 2 | 3ec40862-3d69-4019-a81b-24095b11a5d8--779994750
 | Plan 2 | 3ec40862-3d69-4019-a81b-24095b11a5d8--779994751
 | Plan 2 | 3ec40862-3d69-4019-a81b-24095b11a5d8--779994752
 | Plan 2 | 3ec40862-3d69-4019-a81b-24095b11a5d8--779994753
 | Plan 2 | 3ec40862-3d69-4019-a81b-24095b11a5d8--779994754
 | Plan 2 | 3ec40862-3d69-4019-a81b-24095b11a5d8--779994755
 | Plan 2 | 3ec40862-3d69-4019-a81b-24095b11a5d8--779994756
 | Plan 2 | 3ec40862-3d69-4019-a81b-24095b11a5d8--779994757
 | Plan 2 | 3ec40862-3d69-4019-a81b-24095b11a5d8--779994758
 | Plan 2 | 3ec40862-3d69-4019-a81b-24095b11a5d8--779993724
 | Plan 2 | 3ec40862-3d69-4019-a81b-24095b11a5d8--779993725
 | Plan 2 | 3ec40862-3d69-4019-a81b-24095b11a5d8--779993726
 | Plan 2 | 3ec40862-3d69-4019-a81b-24095b11a5d8--779993727
 | Plan 2 | 3ec40862-3d69-4019-a81b-24095b11a5d8--779993728
 | Plan 2 | 3ec40862-3d69-4019-a81b-24095b11a5d8--779993729
 | Plan 2 | 3ec40862-3d69-4019-a81b-24095b11a5d8--779993730
 | Plan 2 | 3ec40862-3d69-4019-a81b-24095b11a5d8--779993731
 | Plan 2 | 3ec40862-3d69-4019-a81b-24095b11a5d8--779993732
 | Plan 2 | 3ec40862-3d69-4019-a81b-24095b11a5d8--779993733
 | Plan 2 | 3ec40862-3d69-4019-a81b-24095b11a5d8--779993734
 | Plan 2 | 3ec40862-3d69-4019-a81b-24095b11a5d8--779994219
 | Plan 2 | 3ec40862-3d69-4019-a81b-24095b11a5d8--779993746
 | Plan 2 | 3ec40862-3d69-4019-a81b-24095b11a5d8--779993749
 | Plan 2 | 3ec40862-3d69-4019-a81b-24095b11a5d8--779993750
 | Plan 2 | 3ec40862-3d69-4019-a81b-24095b11a5d8--779993747
 | Plan 2 | 3ec40862-3d69-4019-a81b-24095b11a5d8--779993748
 | Plan 2 | 3ec40862-3d69-4019-a81b-24095b11a5d8--779993751
 | Plan 2 | 3ec40862-3d69-4019-a81b-24095b11a5d8--779993752
 | Plan 2 | 3ec40862-3d69-4019-a81b-24095b11a5d8--779993753
 | Plan 2 | 3ec40862-3d69-4019-a81b-24095b11a5d8--779993754
 | Plan 2 | 3ec40862-3d69-4019-a81b-24095b11a5d8--779993755
 | Plan 2 | 3ec40862-3d69-4019-a81b-24095b11a5d8--779993756
 | Plan 2 | 3ec40862-3d69-4019-a81b-24095b11a5d8--779994056
 | Plan 2 | 3ec40862-3d69-4019-a81b-24095b11a5d8--779994038
 | Plan 2 | 3ec40862-3d69-4019-a81b-24095b11a5d8--779994039
 | Plan 2 | 3ec40862-3d69-4019-a81b-24095b11a5d8--779994040
 | Plan 2 | 3ec40862-3d69-4019-a81b-24095b11a5d8--779994041
 | Plan 2 | 3ec40862-3d69-4019-a81b-24095b11a5d8--779994042
 | Plan 2 | 3ec40862-3d69-4019-a81b-24095b11a5d8--779994043
 | Plan 2 | 3ec40862-3d69-4019-a81b-24095b11a5d8--779994044
 | Plan 2 | 3ec40862-3d69-4019-a81b-24095b11a5d8--779994045
 | Plan 2 | 3ec40862-3d69-4019-a81b-24095b11a5d8--779994046
 | Plan 2 | 3ec40862-3d69-4019-a81b-24095b11a5d8--779994047
 | Plan 2 | 3ec40862-3d69-4019-a81b-24095b11a5d8--779994048
 | Plan 2 | 3ec40862-3d69-4019-a81b-24095b11a5d8--779994049
 | Plan 2 | 3ec40862-3d69-4019-a81b-24095b11a5d8--779994050
 | Plan 2 | 3ec40862-3d69-4019-a81b-24095b11a5d8--779994051
 | Plan 2 | 3ec40862-3d69-4019-a81b-24095b11a5d8--780000289
 | Plan 2 | 3ec40862-3d69-4019-a81b-24095b11a5d8--780000290
 | Plan 2 | 3ec40862-3d69-4019-a81b-24095b11a5d8--780000291
 | Plan 2 | 3ec40862-3d69-4019-a81b-24095b11a5d8--780000292
 | Plan 2 | 3ec40862-3d69-4019-a81b-24095b11a5d8--780000293
 | Plan 2 | 3ec40862-3d69-4019-a81b-24095b11a5d8--780000294
 | Plan 2 | 3ec40862-3d69-4019-a81b-24095b11a5d8--780000295
 | Plan 2 | 3ec40862-3d69-4019-a81b-24095b11a5d8--780000296
 | Plan 2 | 3ec40862-3d69-4019-a81b-24095b11a5d8--780000297
 | Plan 2 | 3ec40862-3d69-4019-a81b-24095b11a5d8--780000298
 | Plan 2 | 3ec40862-3d69-4019-a81b-24095b11a5d8--780000299
 | Plan 2 | 3ec40862-3d69-4019-a81b-24095b11a5d8--780000300
 | Plan 2 | 3ec40862-3d69-4019-a81b-24095b11a5d8--780000301
 | Plan 2 | 3ec40862-3d69-4019-a81b-24095b11a5d8--780000302
 | Plan 2 | 3ec40862-3d69-4019-a81b-24095b11a5d8--780000303
 | Plan 2 | 3ec40862-3d69-4019-a81b-24095b11a5d8--780000304
 | Plan 2 | 3ec40862-3d69-4019-a81b-24095b11a5d8--780000305
 | Plan 2 | 3ec40862-3d69-4019-a81b-24095b11a5d8--780000306
 | Plan 2 | 3ec40862-3d69-4019-a81b-24095b11a5d8--780000307
 | Plan 2 | 3ec40862-3d69-4019-a81b-24095b11a5d8--780000308
 | Plan 2 | 3ec40862-3d69-4019-a81b-24095b11a5d8--780000309
 | Plan 2 | 3ec40862-3d69-4019-a81b-24095b11a5d8--780000310
 | Plan 2 | 3ec40862-3d69-4019-a81b-24095b11a5d8--780000311
 | Plan 2 | 3ec40862-3d69-4019-a81b-24095b11a5d8--780000322
 | Plan 2 | 3ec40862-3d69-4019-a81b-24095b11a5d8--780000323
 | Plan 2 | 3ec40862-3d69-4019-a81b-24095b11a5d8--780000324
 | Plan 2 | 3ec40862-3d69-4019-a81b-24095b11a5d8--780000325
 | Plan 2 | 3ec40862-3d69-4019-a81b-24095b11a5d8--780000326
 | Plan 2 | 3ec40862-3d69-4019-a81b-24095b11a5d8--780000327
 | Plan 2 | 3ec40862-3d69-4019-a81b-24095b11a5d8--780000328
 | Plan 2 | 3ec40862-3d69-4019-a81b-24095b11a5d8--780000329
 | Plan 2 | 3ec40862-3d69-4019-a81b-24095b11a5d8--780000330
 | Plan 2 | 3ec40862-3d69-4019-a81b-24095b11a5d8--780000331
 | Plan 2 | 3ec40862-3d69-4019-a81b-24095b11a5d8--780000333
 | Plan 2 | 3ec40862-3d69-4019-a81b-24095b11a5d8--780000334
 | Plan 2 | 3ec40862-3d69-4019-a81b-24095b11a5d8--780000335
 | Plan 2 | 3ec40862-3d69-4019-a81b-24095b11a5d8--780000336
 | Plan 2 | 3ec40862-3d69-4019-a81b-24095b11a5d8--780000337
 | Plan 2 | 3ec40862-3d69-4019-a81b-24095b11a5d8--780000365
 | Plan 2 | 3ec40862-3d69-4019-a81b-24095b11a5d8--780000366
 | Plan 2 | 3ec40862-3d69-4019-a81b-24095b11a5d8--780000367
 | Plan 2 | 3ec40862-3d69-4019-a81b-24095b11a5d8--780000368
 | Plan 2 | 3ec40862-3d69-4019-a81b-24095b11a5d8--780000369
 | Plan 2 | 3ec40862-3d69-4019-a81b-24095b11a5d8--780000370
 | Plan 2 | 3ec40862-3d69-4019-a81b-24095b11a5d8--780000371
 | Plan 2 | 3ec40862-3d69-4019-a81b-24095b11a5d8--780000372
 | Plan 2 | 3ec40862-3d69-4019-a81b-24095b11a5d8--780000373
 | Plan 2 | 3ec40862-3d69-4019-a81b-24095b11a5d8--780000374
 | Plan 2 | 3ec40862-3d69-4019-a81b-24095b11a5d8--780000375
 | Plan 2 | 3ec40862-3d69-4019-a81b-24095b11a5d8--780000376
 | Plan 2 | 3ec40862-3d69-4019-a81b-24095b11a5d8--780000377
 | Plan 2 | 3ec40862-3d69-4019-a81b-24095b11a5d8--780000378
 | Plan 2 | 3ec40862-3d69-4019-a81b-24095b11a5d8--780000379
 | Plan 2 | 3ec40862-3d69-4019-a81b-24095b11a5d8--780000380
 | Plan 2 | 3ec40862-3d69-4019-a81b-24095b11a5d8--780000381
 | Plan 2 | 3ec40862-3d69-4019-a81b-24095b11a5d8--780000382
 | Plan 2 | 3ec40862-3d69-4019-a81b-24095b11a5d8--780000383
 | Plan 2 | 3ec40862-3d69-4019-a81b-24095b11a5d8--780000384
 | Plan 2 | 3ec40862-3d69-4019-a81b-24095b11a5d8--780000385
 | Plan 2 | 3ec40862-3d69-4019-a81b-24095b11a5d8--780000386
 | Plan 2 | 3ec40862-3d69-4019-a81b-24095b11a5d8--780000387
 | Plan 2 | 3ec40862-3d69-4019-a81b-24095b11a5d8--780000388
 | Plan 2 | 3ec40862-3d69-4019-a81b-24095b11a5d8--780000393
 | Plan 2 | 3ec40862-3d69-4019-a81b-24095b11a5d8--780000396
 | Plan 2 | 3ec40862-3d69-4019-a81b-24095b11a5d8--780000397
 | Plan 2 | 3ec40862-3d69-4019-a81b-24095b11a5d8--780000398
 | Plan 2 | 3ec40862-3d69-4019-a81b-24095b11a5d8--780000399
 | Plan 2 | 3ec40862-3d69-4019-a81b-24095b11a5d8--780000402
 | Plan 2 | 3ec40862-3d69-4019-a81b-24095b11a5d8--780000403
 | Plan 2 | 3ec40862-3d69-4019-a81b-24095b11a5d8--780000404
 | Plan 2 | 3ec40862-3d69-4019-a81b-24095b11a5d8--780000405
 | Plan 2 | 3ec40862-3d69-4019-a81b-24095b11a5d8--780000406
 | Plan 2 | 3ec40862-3d69-4019-a81b-24095b11a5d8--780000407
 | Plan 2 | 3ec40862-3d69-4019-a81b-24095b11a5d8--780000408
 | Plan 2 | 3ec40862-3d69-4019-a81b-24095b11a5d8--780000409
 | Plan 2 | 3ec40862-3d69-4019-a81b-24095b11a5d8--780000410
 | Plan 2 | 3ec40862-3d69-4019-a81b-24095b11a5d8--780000411
 | Plan 2 | 3ec40862-3d69-4019-a81b-24095b11a5d8--780000412
 | Plan 2 | 3ec40862-3d69-4019-a81b-24095b11a5d8--780000395
 | Plan 2 | 3ec40862-3d69-4019-a81b-24095b11a5d8--780000414
 | Plan 2 | 3ec40862-3d69-4019-a81b-24095b11a5d8--780000401
 | Plan 2 | 3ec40862-3d69-4019-a81b-24095b11a5d8--780000394
 | Plan 2 | 3ec40862-3d69-4019-a81b-24095b11a5d8--780000312
 | Plan 2 | 3ec40862-3d69-4019-a81b-24095b11a5d8--780000313
 | Plan 2 | 3ec40862-3d69-4019-a81b-24095b11a5d8--780000314
 | Plan 2 | 3ec40862-3d69-4019-a81b-24095b11a5d8--780000315
 | Plan 2 | 3ec40862-3d69-4019-a81b-24095b11a5d8--780000316
 | Plan 2 | 3ec40862-3d69-4019-a81b-24095b11a5d8--780000317
 | Plan 2 | 3ec40862-3d69-4019-a81b-24095b11a5d8--780000320
 | Plan 2 | 3ec40862-3d69-4019-a81b-24095b11a5d8--780000321
 | Plan 2 | 3ec40862-3d69-4019-a81b-24095b11a5d8--780000318
 | Plan 2 | 3ec40862-3d69-4019-a81b-24095b11a5d8--780000319
 | Plan 2 | 3ec40862-3d69-4019-a81b-24095b11a5d8--780000332
 | Plan 2 | 3ec40862-3d69-4019-a81b-24095b11a5d8--780000415
 | Plan 2 | 3ec40862-3d69-4019-a81b-24095b11a5d8--779994187
 | Plan 2 | 3ec40862-3d69-4019-a81b-24095b11a5d8--779994188
 | Plan 2 | 3ec40862-3d69-4019-a81b-24095b11a5d8--779994189
 | Plan 2 | 3ec40862-3d69-4019-a81b-24095b11a5d8--779994190
 | Plan 2 | 3ec40862-3d69-4019-a81b-24095b11a5d8--779994191
 | Plan 2 | 3ec40862-3d69-4019-a81b-24095b11a5d8--779994192
 | Plan 2 | 3ec40862-3d69-4019-a81b-24095b11a5d8--779994193
 | Plan 2 | 3ec40862-3d69-4019-a81b-24095b11a5d8--779994194
 | Plan 2 | 3ec40862-3d69-4019-a81b-24095b11a5d8--779994195
 | Plan 2 | 3ec40862-3d69-4019-a81b-24095b11a5d8--779994196
 | Plan 2 | 3ec40862-3d69-4019-a81b-24095b11a5d8--779994197
 | Plan 2 | 3ec40862-3d69-4019-a81b-24095b11a5d8--779994198
 | Plan 2 | 3ec40862-3d69-4019-a81b-24095b11a5d8--779994199
 | Plan 2 | 3ec40862-3d69-4019-a81b-24095b11a5d8--779994200
 | Plan 2 | 3ec40862-3d69-4019-a81b-24095b11a5d8--779994201
 | Plan 2 | 3ec40862-3d69-4019-a81b-24095b11a5d8--779994203
 | Plan 2 | 3ec40862-3d69-4019-a81b-24095b11a5d8--779994204
 | Plan 2 | 3ec40862-3d69-4019-a81b-24095b11a5d8--779994205
 | Plan 2 | 3ec40862-3d69-4019-a81b-24095b11a5d8--779994226
 | Plan 2 | 3ec40862-3d69-4019-a81b-24095b11a5d8--779994178
 | Plan 2 | 3ec40862-3d69-4019-a81b-24095b11a5d8--779994179
 | Plan 2 | 3ec40862-3d69-4019-a81b-24095b11a5d8--779994180
 | Plan 2 | 3ec40862-3d69-4019-a81b-24095b11a5d8--779994181
 | Plan 2 | 3ec40862-3d69-4019-a81b-24095b11a5d8--779994182
 | Plan 2 | 3ec40862-3d69-4019-a81b-24095b11a5d8--779994183
 | Plan 2 | 3ec40862-3d69-4019-a81b-24095b11a5d8--779994184
 | Plan 2 | 3ec40862-3d69-4019-a81b-24095b11a5d8--779994206
 | Plan 2 | 3ec40862-3d69-4019-a81b-24095b11a5d8--779994177
 | Plan 2 | 3ec40862-3d69-4019-a81b-24095b11a5d8--780014477
 | Plan 2 | 3ec40862-3d69-4019-a81b-24095b11a5d8--780014478
 | Plan 2 | 3ec40862-3d69-4019-a81b-24095b11a5d8--780014479
 | Plan 2 | 3ec40862-3d69-4019-a81b-24095b11a5d8--780014480
 | Plan 2 | 3ec40862-3d69-4019-a81b-24095b11a5d8--779994079
 | Plan 2 | 3ec40862-3d69-4019-a81b-24095b11a5d8--779994080
 | Plan 2 | 3ec40862-3d69-4019-a81b-24095b11a5d8--779994081
 | Plan 2 | 3ec40862-3d69-4019-a81b-24095b11a5d8--779994082
 | Plan 2 | 3ec40862-3d69-4019-a81b-24095b11a5d8--779994083
 | Plan 2 | 3ec40862-3d69-4019-a81b-24095b11a5d8--779994084
 | Plan 2 | 3ec40862-3d69-4019-a81b-24095b11a5d8--779994085
 | Plan 2 | 3ec40862-3d69-4019-a81b-24095b11a5d8--779994086
 | Plan 2 | 3ec40862-3d69-4019-a81b-24095b11a5d8--779994087
 | Plan 2 | 3ec40862-3d69-4019-a81b-24095b11a5d8--779994088
 | Plan 2 | 3ec40862-3d69-4019-a81b-24095b11a5d8--779994259
 | Plan 2 | c4a0b384-ec84-45b7-803d-fbac94fce1af--780361544
 | Plan 2 | c4a0b384-ec84-45b7-803d-fbac94fce1af--780361543
 | Plan 2 | ba775db5-6acf-44d4-98dd-11fdd85c2627--2
 | Plan 2 | ba775db5-6acf-44d4-98dd-11fdd85c2627--216
 | Plan 2 | ba775db5-6acf-44d4-98dd-11fdd85c2627--218
 | Plan 2 | ba775db5-6acf-44d4-98dd-11fdd85c2627--3
 | Plan 2 | ba775db5-6acf-44d4-98dd-11fdd85c2627--175
 | Plan 2 | ba775db5-6acf-44d4-98dd-11fdd85c2627--219
 | Plan 2 | ba775db5-6acf-44d4-98dd-11fdd85c2627--217
 | Plan 2 | ba775db5-6acf-44d4-98dd-11fdd85c2627--171
 | Plan 2 | ba775db5-6acf-44d4-98dd-11fdd85c2627--173
 | Plan 2 | ba775db5-6acf-44d4-98dd-11fdd85c2627--172
 | Plan 2 | ba775db5-6acf-44d4-98dd-11fdd85c2627--61
 | Plan 2 | ba775db5-6acf-44d4-98dd-11fdd85c2627--63
 | Plan 2 | ba775db5-6acf-44d4-98dd-11fdd85c2627--62
 | Plan 2 | ba775db5-6acf-44d4-98dd-11fdd85c2627--51
 | Plan 2 | ba775db5-6acf-44d4-98dd-11fdd85c2627--53
 | Plan 2 | ba775db5-6acf-44d4-98dd-11fdd85c2627--52
 | Plan 2 | ba775db5-6acf-44d4-98dd-11fdd85c2627--81
 | Plan 2 | ba775db5-6acf-44d4-98dd-11fdd85c2627--82
 | Plan 2 | ba775db5-6acf-44d4-98dd-11fdd85c2627--83
 | Plan 2 | ba775db5-6acf-44d4-98dd-11fdd85c2627--101
 | Plan 2 | ba775db5-6acf-44d4-98dd-11fdd85c2627--102
 | Plan 2 | ba775db5-6acf-44d4-98dd-11fdd85c2627--103
 | Plan 2 | ba775db5-6acf-44d4-98dd-11fdd85c2627--121
 | Plan 2 | ba775db5-6acf-44d4-98dd-11fdd85c2627--122
 | Plan 2 | ba775db5-6acf-44d4-98dd-11fdd85c2627--123
 | Plan 2 | ba775db5-6acf-44d4-98dd-11fdd85c2627--131
 | Plan 2 | ba775db5-6acf-44d4-98dd-11fdd85c2627--132
 | Plan 2 | ba775db5-6acf-44d4-98dd-11fdd85c2627--133
 | Plan 2 | ba775db5-6acf-44d4-98dd-11fdd85c2627--91
 | Plan 2 | ba775db5-6acf-44d4-98dd-11fdd85c2627--92
 | Plan 2 | ba775db5-6acf-44d4-98dd-11fdd85c2627--93
 | Plan 2 | ba775db5-6acf-44d4-98dd-11fdd85c2627--151
 | Plan 2 | ba775db5-6acf-44d4-98dd-11fdd85c2627--152
 | Plan 2 | ba775db5-6acf-44d4-98dd-11fdd85c2627--153
 | Plan 2 | ba775db5-6acf-44d4-98dd-11fdd85c2627--141
 | Plan 2 | ba775db5-6acf-44d4-98dd-11fdd85c2627--142
 | Plan 2 | ba775db5-6acf-44d4-98dd-11fdd85c2627--143
 | Plan 2 | ba775db5-6acf-44d4-98dd-11fdd85c2627--43
 | Plan 2 | ba775db5-6acf-44d4-98dd-11fdd85c2627--42
 | Plan 2 | ba775db5-6acf-44d4-98dd-11fdd85c2627--41
 | Plan 2 | ba775db5-6acf-44d4-98dd-11fdd85c2627--71
 | Plan 2 | ba775db5-6acf-44d4-98dd-11fdd85c2627--73
 | Plan 2 | ba775db5-6acf-44d4-98dd-11fdd85c2627--72
 | Plan 2 | ba775db5-6acf-44d4-98dd-11fdd85c2627--111
 | Plan 2 | ba775db5-6acf-44d4-98dd-11fdd85c2627--113
 | Plan 2 | ba775db5-6acf-44d4-98dd-11fdd85c2627--112
 | Plan 2 | ba775db5-6acf-44d4-98dd-11fdd85c2627--161
 | Plan 2 | ba775db5-6acf-44d4-98dd-11fdd85c2627--163
 | Plan 2 | ba775db5-6acf-44d4-98dd-11fdd85c2627--162
 | Plan 2 | ba775db5-6acf-44d4-98dd-11fdd85c2627--780027038
 | Plan 2 | ba775db5-6acf-44d4-98dd-11fdd85c2627--780027039
 | Plan 2 | ba775db5-6acf-44d4-98dd-11fdd85c2627--780027040
 | Plan 2 | ba775db5-6acf-44d4-98dd-11fdd85c2627--780027353
 | Plan 2 | ba775db5-6acf-44d4-98dd-11fdd85c2627--780027354
 | Plan 2 | ba775db5-6acf-44d4-98dd-11fdd85c2627--780027355
 | Plan 2 | ba775db5-6acf-44d4-98dd-11fdd85c2627--31
 | Plan 2 | ba775db5-6acf-44d4-98dd-11fdd85c2627--29
 | Plan 2 | ba775db5-6acf-44d4-98dd-11fdd85c2627--30
 | Plan 2 | ba775db5-6acf-44d4-98dd-11fdd85c2627--19
 | Plan 2 | ba775db5-6acf-44d4-98dd-11fdd85c2627--17
 | Plan 2 | ba775db5-6acf-44d4-98dd-11fdd85c2627--18
 | Plan 2 | ba775db5-6acf-44d4-98dd-11fdd85c2627--780027115
 | Plan 2 | ba775db5-6acf-44d4-98dd-11fdd85c2627--780027116
 | Plan 2 | ba775db5-6acf-44d4-98dd-11fdd85c2627--780027117
 | Plan 2 | 9b8806e7-4009-424f-bd57-ff5b061054b9--448
 | Plan 2 | 9b8806e7-4009-424f-bd57-ff5b061054b9--445
 | Plan 2 | 9b8806e7-4009-424f-bd57-ff5b061054b9--446
 | Plan 2 | 9b8806e7-4009-424f-bd57-ff5b061054b9--447
 | HEKF Administrasjonbygg | c1af80ed-b34b-4069-a01c-5597e74ec40f--23615
 | HEKF Administrasjonbygg | c1af80ed-b34b-4069-a01c-5597e74ec40f--23618
 | HEKF Administrasjonbygg | c1af80ed-b34b-4069-a01c-5597e74ec40f--23621
 | HEKF Administrasjonbygg | c1af80ed-b34b-4069-a01c-5597e74ec40f--23624
 | HEKF Administrasjonbygg | c1af80ed-b34b-4069-a01c-5597e74ec40f--23627
 | HEKF Administrasjonbygg | c1af80ed-b34b-4069-a01c-5597e74ec40f--23630
 | HEKF Administrasjonbygg | c1af80ed-b34b-4069-a01c-5597e74ec40f--23633
 | HEKF Administrasjonbygg | c1af80ed-b34b-4069-a01c-5597e74ec40f--23614
 | HEKF Administrasjonbygg | c1af80ed-b34b-4069-a01c-5597e74ec40f--23617
 | HEKF Administrasjonbygg | c1af80ed-b34b-4069-a01c-5597e74ec40f--23620
 | HEKF Administrasjonbygg | c1af80ed-b34b-4069-a01c-5597e74ec40f--23623
 | HEKF Administrasjonbygg | c1af80ed-b34b-4069-a01c-5597e74ec40f--23626
 | HEKF Administrasjonbygg | c1af80ed-b34b-4069-a01c-5597e74ec40f--23629
 | HEKF Administrasjonbygg | c1af80ed-b34b-4069-a01c-5597e74ec40f--23632
 | HEKF Administrasjonbygg | c1af80ed-b34b-4069-a01c-5597e74ec40f--23636
 | HEKF Administrasjonbygg | c1af80ed-b34b-4069-a01c-5597e74ec40f--23639
 | HEKF Administrasjonbygg | c1af80ed-b34b-4069-a01c-5597e74ec40f--23642
 | HEKF Administrasjonbygg | c1af80ed-b34b-4069-a01c-5597e74ec40f--23645
 | HEKF Administrasjonbygg | c1af80ed-b34b-4069-a01c-5597e74ec40f--23635
 | HEKF Administrasjonbygg | c1af80ed-b34b-4069-a01c-5597e74ec40f--23638
 | HEKF Administrasjonbygg | c1af80ed-b34b-4069-a01c-5597e74ec40f--23641
 | HEKF Administrasjonbygg | c1af80ed-b34b-4069-a01c-5597e74ec40f--23644

# IfcBeam (88)
Allplan Attributes - Building alteration category: New building
Name | In | GrossFootprintArea (m2) | Length (m) | GrossVolume (m3) = NetVolume (m3) | OuterSurfaceArea (m2) | Allright_Comp_ID | Unit | NOI_UUID
 | Plan 1 | 0.01 | 2.8 | 0.028 | 1.14 | 0011Bea0016820974 | m | 3244f7b8-136b-492f-bad8-2462ae0dead0--16820974 | Material: Betong i drager
 | Plan 1 | 0.01 | 2.8 | 0.028 | 1.14 | 0011Bea0016820987 | m | 3244f7b8-136b-492f-bad8-2462ae0dead0--16820987 | Material: Betong i drager
 | Plan 1 | 0.01 | 2.8 | 0.028 | 1.14 | 0011Bea0016821000 | m | 3244f7b8-136b-492f-bad8-2462ae0dead0--16821000 | Material: Betong i drager
 | Plan 1 | 0.01 | 1.175 | 0.01175 | 0.49 | 0011Bea0016821008 | m | 3244f7b8-136b-492f-bad8-2462ae0dead0--16821008 | Material: Betong i drager
 | Plan 1 | 0.00518806 | 3.775 | 0.0195849 | 4.48677 | 0012Bea0000000017 | m | 480282cb-d55c-48df-bc97-d2a65b1fac34--17 | Material: Betong i drager
 | Plan 1 | 0.00518806 | 3.85 | 0.019974 | 4.57571 | 0012Bea0000000027 | m | 480282cb-d55c-48df-bc97-d2a65b1fac34--27 | Material: Betong i drager
 | Plan 1 | 0.00518806 | 3.775 | 0.0195849 | 4.48677 | 0012Bea0000000037 | m | 480282cb-d55c-48df-bc97-d2a65b1fac34--37 | Material: Betong i drager
 | Plan 1 | 0.01475 | 12 | 0.177 | 23.6695 | 0012Bea0000006854 | m | 480282cb-d55c-48df-bc97-d2a65b1fac34--6854 | Material: HSQ
 | Plan 1 | 0.01475 | 12 | 0.177 | 23.6695 | 0012Bea0000006875 | m | 480282cb-d55c-48df-bc97-d2a65b1fac34--6875 | Material: HSQ
 | Plan 1 | 0.01475 | 12 | 0.177 | 23.6695 | 0012Bea0000006885 | m | 480282cb-d55c-48df-bc97-d2a65b1fac34--6885 | Material: HSQ
 | Plan 1 | 0.01475 | 12 | 0.177 | 23.6695 | 0012Bea0000006880 | m | 480282cb-d55c-48df-bc97-d2a65b1fac34--6880 | Material: HSQ
 | Plan 1 | 0.00518806 | 3.775 | 0.0195849 | 4.48677 | 0012Bea0000006929 | m | 480282cb-d55c-48df-bc97-d2a65b1fac34--6929 | Material: Betong i drager
 | Plan 1 | 0.00518806 | 3.775 | 0.0195849 | 4.48677 | 0012Bea0000006925 | m | 480282cb-d55c-48df-bc97-d2a65b1fac34--6925 | Material: Betong i drager
 | Plan 1 | 0.01475 | 4 | 0.059 | 7.9095 | 0012Bea0000006890 | m | 480282cb-d55c-48df-bc97-d2a65b1fac34--6890 | Material: HSQ
 | Plan 1 | 0.01475 | 4 | 0.059 | 7.9095 | 0012Bea0000006973 | m | 480282cb-d55c-48df-bc97-d2a65b1fac34--6973 | Material: HSQ
 | Plan 1 | 0.01275 | 4 | 0.051 | 7.1055 | 0012Bea0000006953 | m | 480282cb-d55c-48df-bc97-d2a65b1fac34--6953 | Material: HSQ; Allplan Attributes - Material: HSQ
 | Plan 1 | 0.02 | 2.64946 | 0.0529893 | 1.62968 | 0012Bea0000007070 | m | 480282cb-d55c-48df-bc97-d2a65b1fac34--7070 | Material: Betong i drager
 | Plan 1 | 0.00279252 | 4.7 | 0.0131248 | 5.25577 | 0012Bea0000007142 | m | 480282cb-d55c-48df-bc97-d2a65b1fac34--7142 | Material: HUP100x200; Allplan Attributes - Material: HUP100x200
 | Plan 1 | 0.00279252 | 4.7 | 0.0131248 | 5.25577 | 0012Bea0000007102 | m | 480282cb-d55c-48df-bc97-d2a65b1fac34--7102 | Material: HUP100x200; Allplan Attributes - Material: HUP100x200
 | Plan 1 | 0.00279252 | 5.33609 | 0.0149011 | 5.96633 | 0012Bea0000007168 | m | 480282cb-d55c-48df-bc97-d2a65b1fac34--7168 | Material: HUP100x200; Allplan Attributes - Material: HUP100x200
 | Plan 1 | 0.00279252 | 5.33609 | 0.0149011 | 5.96633 | 0012Bea0000007163 | m | 480282cb-d55c-48df-bc97-d2a65b1fac34--7163 | Material: HUP100x200; Allplan Attributes - Material: HUP100x200
 | Plan 1 | 0.130861 | 4.815 | 0.630097 | 27.1441 | 0015Bea0016819049 | m³ | cbab19c6-f7f3-4c25-9028-8574def17b1d--16819049
 | Plan 1 | 0.130861 | 4.815 | 0.630097 | 27.1441 | 0015Bea0016819026 | m³ | cbab19c6-f7f3-4c25-9028-8574def17b1d--16819026
 | Plan 1 | 0.130861 | 4.815 | 0.630097 | 27.1441 | 0015Bea0016819003 | m³ | cbab19c6-f7f3-4c25-9028-8574def17b1d--16819003
 | Plan 1 | 0.130861 | 4.815 | 0.630097 | 27.1441 | 0015Bea0016818980 | m³ | cbab19c6-f7f3-4c25-9028-8574def17b1d--16818980
 | Plan 1 | 0.130861 | 4.815 | 0.630097 | 27.1441 | 0015Bea0016818957 | m³ | cbab19c6-f7f3-4c25-9028-8574def17b1d--16818957
 | Plan 1 | 0.130861 | 4.815 | 0.630097 | 27.1441 | 0015Bea0016818934 | m³ | cbab19c6-f7f3-4c25-9028-8574def17b1d--16818934
 | Plan 1 | 0.130861 | 4.815 | 0.630097 | 27.1441 | 0015Bea0016818911 | m³ | cbab19c6-f7f3-4c25-9028-8574def17b1d--16818911
 | Plan 1 | 0.130861 | 4.815 | 0.630097 | 27.1441 | 0015Bea0016818888 | m³ | cbab19c6-f7f3-4c25-9028-8574def17b1d--16818888
 | Plan 1 | 0.130861 | 4.815 | 0.630097 | 27.1441 | 0015Bea0016818865 | m³ | cbab19c6-f7f3-4c25-9028-8574def17b1d--16818865
 | Plan 1 | 0.130861 | 4.815 | 0.630097 | 27.1441 | 0015Bea0016816935 | m³ | cbab19c6-f7f3-4c25-9028-8574def17b1d--16816935
 | Plan 1 | 0.130861 | 4.73 | 0.618974 | 26.6696 | 0015Bea0016819063 | m³ | cbab19c6-f7f3-4c25-9028-8574def17b1d--16819063
 | Plan 1 | 0.130861 | 4.73 | 0.618974 | 26.6696 | 0015Bea0016819076 | m³ | cbab19c6-f7f3-4c25-9028-8574def17b1d--16819076
 | Plan 1 | 0.130861 | 4.73 | 0.618974 | 26.6696 | 0015Bea0016819093 | m³ | cbab19c6-f7f3-4c25-9028-8574def17b1d--16819093
 | Plan 1 | 0.130861 | 4.73 | 0.618974 | 26.6696 | 0015Bea0016819110 | m³ | cbab19c6-f7f3-4c25-9028-8574def17b1d--16819110
 | Plan 1 | 0.130861 | 4.73 | 0.618974 | 26.6696 | 0015Bea0016819127 | m³ | cbab19c6-f7f3-4c25-9028-8574def17b1d--16819127
 | Plan 1 | 0.130861 | 4.73 | 0.618974 | 26.6696 | 0015Bea0016819144 | m³ | cbab19c6-f7f3-4c25-9028-8574def17b1d--16819144
 | Plan 1 | 0.130861 | 4.73 | 0.618974 | 26.6696 | 0015Bea0016819161 | m³ | cbab19c6-f7f3-4c25-9028-8574def17b1d--16819161
 | Plan 1 | 0.130861 | 4.73 | 0.618974 | 26.6696 | 0015Bea0016819178 | m³ | cbab19c6-f7f3-4c25-9028-8574def17b1d--16819178
 | Plan 1 | 0.130861 | 4.73 | 0.618974 | 26.6696 | 0015Bea0016819195 | m³ | cbab19c6-f7f3-4c25-9028-8574def17b1d--16819195
 | Plan 1 | 0.130861 | 4.73 | 0.618974 | 26.6696 | 0015Bea0016819221 | m³ | cbab19c6-f7f3-4c25-9028-8574def17b1d--16819221
 | Plan 1 | 0.130861 | 6.055 | 0.792365 | 34.0671 | 0015Bea0016819457 | m³ | cbab19c6-f7f3-4c25-9028-8574def17b1d--16819457
 | Plan 1 | 0.130861 | 6.055 | 0.792365 | 34.0671 | 0015Bea0016819459 | m³ | cbab19c6-f7f3-4c25-9028-8574def17b1d--16819459
 | Plan 1 | 0.130861 | 6.055 | 0.792365 | 34.0671 | 0015Bea0016819461 | m³ | cbab19c6-f7f3-4c25-9028-8574def17b1d--16819461
 | Plan 1 | 0.130861 | 6.055 | 0.792365 | 34.0671 | 0015Bea0016819463 | m³ | cbab19c6-f7f3-4c25-9028-8574def17b1d--16819463
 | Plan 1 | 0.130861 | 6.055 | 0.792365 | 34.0671 | 0015Bea0016819465 | m³ | cbab19c6-f7f3-4c25-9028-8574def17b1d--16819465
 | Plan 1 | 0.130861 | 6.055 | 0.792365 | 34.0671 | 0015Bea0016819467 | m³ | cbab19c6-f7f3-4c25-9028-8574def17b1d--16819467
 | Plan 1 | 0.130861 | 6.055 | 0.792365 | 34.0671 | 0015Bea0016819469 | m³ | cbab19c6-f7f3-4c25-9028-8574def17b1d--16819469
 | Plan 1 | 0.130861 | 6.055 | 0.792365 | 34.0671 | 0015Bea0016819471 | m³ | cbab19c6-f7f3-4c25-9028-8574def17b1d--16819471
 | Plan 1 | 0.130861 | 6.055 | 0.792365 | 34.0671 | 0015Bea0016819473 | m³ | cbab19c6-f7f3-4c25-9028-8574def17b1d--16819473
 | Plan 1 | 0.130861 | 5.63027 | 0.736784 | 31.6958 | 0015Bea0016819715 | m³ | cbab19c6-f7f3-4c25-9028-8574def17b1d--16819715
 | Plan 1 | 0.130861 | 5.63027 | 0.736784 | 31.6958 | 0015Bea0016819717 | m³ | cbab19c6-f7f3-4c25-9028-8574def17b1d--16819717
 | Plan 1 | 0.130861 | 5.63027 | 0.736784 | 31.6958 | 0015Bea0016819719 | m³ | cbab19c6-f7f3-4c25-9028-8574def17b1d--16819719
 | Plan 1 | 0.130861 | 5.63027 | 0.736784 | 31.6958 | 0015Bea0016819721 | m³ | cbab19c6-f7f3-4c25-9028-8574def17b1d--16819721
 | Plan 1 | 0.130861 | 5.63027 | 0.736784 | 31.6958 | 0015Bea0016819723 | m³ | cbab19c6-f7f3-4c25-9028-8574def17b1d--16819723
 | Plan 1 | 0.130861 | 5.63027 | 0.736784 | 31.6958 | 0015Bea0016819725 | m³ | cbab19c6-f7f3-4c25-9028-8574def17b1d--16819725
 | Plan 1 | 0.130861 | 5.63027 | 0.736784 | 31.6958 | 0015Bea0016819727 | m³ | cbab19c6-f7f3-4c25-9028-8574def17b1d--16819727
 | Plan 1 | 0.130861 | 5.63027 | 0.736784 | 31.6958 | 0015Bea0016819729 | m³ | cbab19c6-f7f3-4c25-9028-8574def17b1d--16819729
 | Plan 1 | 0.130861 | 5.63027 | 0.736784 | 31.6958 | 0015Bea0016819731 | m³ | cbab19c6-f7f3-4c25-9028-8574def17b1d--16819731
 | Plan 1 | 0.130861 | 5.63027 | 0.736784 | 31.6958 | 0015Bea0016819733 | m³ | cbab19c6-f7f3-4c25-9028-8574def17b1d--16819733
 | Plan 1 | 0.130861 | 4.63027 | 0.605923 | 26.1128 | 0015Bea0016820006 | m³ | cbab19c6-f7f3-4c25-9028-8574def17b1d--16820006
 | Plan 1 | 0.130861 | 4.63027 | 0.605923 | 26.1128 | 0015Bea0016820008 | m³ | cbab19c6-f7f3-4c25-9028-8574def17b1d--16820008
 | Plan 1 | 0.130861 | 4.63027 | 0.605923 | 26.1128 | 0015Bea0016820010 | m³ | cbab19c6-f7f3-4c25-9028-8574def17b1d--16820010
 | Plan 1 | 0.130861 | 4.63027 | 0.605923 | 26.1128 | 0015Bea0016820012 | m³ | cbab19c6-f7f3-4c25-9028-8574def17b1d--16820012
 | Plan 1 | 0.130861 | 4.63027 | 0.605923 | 26.1128 | 0015Bea0016820014 | m³ | cbab19c6-f7f3-4c25-9028-8574def17b1d--16820014
 | Plan 1 | 0.130861 | 4.63027 | 0.605923 | 26.1128 | 0015Bea0016820016 | m³ | cbab19c6-f7f3-4c25-9028-8574def17b1d--16820016
 | Plan 1 | 0.130861 | 4.63027 | 0.605923 | 26.1128 | 0015Bea0016820018 | m³ | cbab19c6-f7f3-4c25-9028-8574def17b1d--16820018
 | Plan 1 | 0.130861 | 4.63027 | 0.605923 | 26.1128 | 0015Bea0016820020 | m³ | cbab19c6-f7f3-4c25-9028-8574def17b1d--16820020
 | Plan 1 | 0.130861 | 4.63027 | 0.605923 | 26.1128 | 0015Bea0016820022 | m³ | cbab19c6-f7f3-4c25-9028-8574def17b1d--16820022
 | Plan 1 | 0.130861 | 4.63027 | 0.605923 | 26.1128 | 0015Bea0016820024 | m³ | cbab19c6-f7f3-4c25-9028-8574def17b1d--16820024
 | Plan 1 | 0.130861 | 2.68946 | 0.351947 | 15.2771 | 0015Bea0016820146 | m³ | cbab19c6-f7f3-4c25-9028-8574def17b1d--16820146
 | Plan 1 | 0.130861 | 2.68946 | 0.351947 | 15.2771 | 0015Bea0016820189 | m³ | cbab19c6-f7f3-4c25-9028-8574def17b1d--16820189
 | Plan 1 | 0.130861 | 2.68946 | 0.351947 | 15.2771 | 0015Bea0016820212 | m³ | cbab19c6-f7f3-4c25-9028-8574def17b1d--16820212
 | Plan 1 | 0.0327154 | 2.68946 | 0.0879867 | 7.88681 | 0015Bea0016826062 | m³ | cbab19c6-f7f3-4c25-9028-8574def17b1d--16826062
 | Plan 1 | 0.130861 | 3.26372 | 0.427094 | 18.4832 | 0015Bea0016819475 | m³ | cbab19c6-f7f3-4c25-9028-8574def17b1d--16819475
 | Plan 2 | 0.00323305 | 4.85033 | 0.0156814 | 2.8227 | 0021Bea0000000636 | m | 1c7d8068-a719-483d-a287-e335b917de17--636 | Material: Betong i drager
 | Plan 2 | 0.00323305 | 4.85033 | 0.0156814 | 2.8227 | 0021Bea0000000650 | m | 1c7d8068-a719-483d-a287-e335b917de17--650 | Material: Betong i drager
 | Plan 2 | 0.00323305 | 4.87533 | 0.0157622 | 2.83721 | 0021Bea0000000664 | m | 1c7d8068-a719-483d-a287-e335b917de17--664 | Material: Betong i drager
 | Plan 2 | 0.00323305 | 4.85033 | 0.0156814 | 2.8227 | 0021Bea0000000563 | m | 1c7d8068-a719-483d-a287-e335b917de17--563 | Material: Betong i drager
 | Plan 2 | 0.00323305 | 4.85033 | 0.0156814 | 2.8227 | 0021Bea0000000577 | m | 1c7d8068-a719-483d-a287-e335b917de17--577 | Material: Betong i drager
 | Plan 2 | 0.00323305 | 4.85033 | 0.0156814 | 2.8227 | 0021Bea0000000591 | m | 1c7d8068-a719-483d-a287-e335b917de17--591 | Material: Betong i drager
 | Plan 2 | 0.00323305 | 4.77533 | 0.0154389 | 2.77915 | 0021Bea0000000605 | m | 1c7d8068-a719-483d-a287-e335b917de17--605 | Material: Betong i drager
 | Plan 2 | 0.00323305 | 4.77533 | 0.0154389 | 2.77915 | 0021Bea0000000619 | m | 1c7d8068-a719-483d-a287-e335b917de17--619 | Material: Betong i drager
 | Plan 2 | 0.00518806 | 12.0266 | 0.0623949 | 14.2716 | 0022Bea0780005958 | m | bf1069d1-83e8-43c2-a8ca-5ca0e7b3f951--780005958 | Material: Betong i drager
 | Plan 2 | 0.00518806 | 12.0266 | 0.0623949 | 14.2716 | 0022Bea0780005968 | m | bf1069d1-83e8-43c2-a8ca-5ca0e7b3f951--780005968 | Material: Betong i drager
 | Plan 2 | 0.01 | 4.85 | 0.0485 | 1.96 | 0022Bea0780006022 | m | bf1069d1-83e8-43c2-a8ca-5ca0e7b3f951--780006022 | Material: Betong i drager
 | Plan 2 | 0.01 | 4.85 | 0.0485 | 1.96 | 0022Bea0780006028 | m | bf1069d1-83e8-43c2-a8ca-5ca0e7b3f951--780006028 | Material: Betong i drager
 | Plan 2 | 0.0037912 | 1.41146 | 0.00535113 | 0.821943 | 0028Bea0780361548 | m³ | c4a0b384-ec84-45b7-803d-fbac94fce1af--780361548

# IfcBuildingElementPart (16)
Name | In | Material
 | Konstruksjoner i grunnen | Golvbelegg
 | Konstruksjoner i grunnen | Betong
 | Konstruksjoner i grunnen | Radonsperre
2 x  | Plan 1 | dERBIGUM
2 x  | Plan 1 | RW 300
2 x  | Plan 1 | TRP111
 | Plan 2 | Decra
 | Plan 2 | Taktro
 | Plan 2 | Utstikk
 | Plan 2 | Sperresjikt
 | Plan 2 | Derbigum
 | Plan 2 | Rockwool
 | Plan 2 | P111

# IfcBuildingElementProxy (37)
Name | In | Material = Allplan Attributes, Material | Allright_Comp_ID | Building alteration category | Unit | Background_fill_color | NOI_UUID
 | Plan 1 | HUP100x200 | 0011AdE0016821199 | New building | m | 28 | 3244f7b8-136b-492f-bad8-2462ae0dead0--0
 | Plan 1 | HUP100x200 | 0011AdE0016821200 | New building | m | 28 | 3244f7b8-136b-492f-bad8-2462ae0dead0--0
 | Plan 1 | HUP100x200 | 0011AdE0016821222 | New building | m | 28 | 3244f7b8-136b-492f-bad8-2462ae0dead0--0
 | Plan 1 | HUP100x200 | 0011AdE0016821266 | New building | m | 28 | 3244f7b8-136b-492f-bad8-2462ae0dead0--0
 | Plan 1 | HUP100x200 | 0011AdE0016821276 | New building | m | 28 | 3244f7b8-136b-492f-bad8-2462ae0dead0--0
 | Plan 1 | T24 | 0013AdE0780003607 | New building | m³ | 9 | d1eb0bd9-ddf6-4315-a806-967de25454b1--0
 | Plan 1 | T24 | 0013AdE0780003608 | New building | m³ | 9 | d1eb0bd9-ddf6-4315-a806-967de25454b1--0
 | Plan 1 | T24 | 0013AdE0780003609 | New building | m³ | 9 | d1eb0bd9-ddf6-4315-a806-967de25454b1--0
 | Plan 1 | T24 | 0013AdE0780003610 | New building | m³ | 9 | d1eb0bd9-ddf6-4315-a806-967de25454b1--0
 | Plan 1 | T24 | 0013AdE0780003611 | New building | m³ | 9 | d1eb0bd9-ddf6-4315-a806-967de25454b1--0
 | Plan 1 | T24 | 0013AdE0780003613 | New building | m³ | 9 | d1eb0bd9-ddf6-4315-a806-967de25454b1--0
 | Plan 1 | T24 | 0013AdE0780003614 | New building | m³ | 9 | d1eb0bd9-ddf6-4315-a806-967de25454b1--0
 | Plan 1 | T24 | 0013AdE0780003615 | New building | m³ | 9 | d1eb0bd9-ddf6-4315-a806-967de25454b1--0
 | Plan 1 | T24 | 0013AdE0780003616 | New building | m³ | 9 | d1eb0bd9-ddf6-4315-a806-967de25454b1--0
 | Plan 1 | T24 | 0013AdE0780003617 | New building | m³ | 9 | d1eb0bd9-ddf6-4315-a806-967de25454b1--0
 | Plan 1 | T24 | 0013AdE0780003618 | New building | m³ | 9 | d1eb0bd9-ddf6-4315-a806-967de25454b1--0
 | Plan 1 | T24 | 0013AdE0780003619 | New building | m³ | 9 | d1eb0bd9-ddf6-4315-a806-967de25454b1--0
 | Plan 1 | T24 | 0013AdE0780003620 | New building | m³ | 9 | d1eb0bd9-ddf6-4315-a806-967de25454b1--0
 | Plan 1 | T24 | 0013AdE0780003621 | New building | m³ | 9 | d1eb0bd9-ddf6-4315-a806-967de25454b1--0
 | Plan 1 | T24 | 0013AdE0780003622 | New building | m³ | 9 | d1eb0bd9-ddf6-4315-a806-967de25454b1--0
 | Plan 1 | T24 | 0013AdE0780003623 | New building | m³ | 9 | d1eb0bd9-ddf6-4315-a806-967de25454b1--0
WC_2 | Plan 1 |  | 0017Sym0779989741 |  | m³ |  | 1b5c68a0-5855-473d-bc40-02b9771d55a8--779989741 | Allplan Attributes - V6: 0; V7: 0; V8: 0; V9: 0
SPUELBECKEN_100_ | Plan 1 |  | 0017Sym0779923392 |  | m³ |  | 1b5c68a0-5855-473d-bc40-02b9771d55a8--779923392 | Allplan Attributes - V6: 0; V7: 0; V8: 0; V9: 0
 | Plan 2 | Betong i drager | 0021AdE0000001085 | New building | m | 28 | 1c7d8068-a719-483d-a287-e335b917de17--0
 | Plan 2 | HUP100x200 | 0021AdE0000001089 | New building | m | 28 | 1c7d8068-a719-483d-a287-e335b917de17--0
 | Plan 2 | HUP100x200 | 0021AdE0000001207 | New building | m | 28 | 1c7d8068-a719-483d-a287-e335b917de17--0
 | Plan 2 | HUP100x200 | 0021AdE0001011537 | New building | m | 28 | 1c7d8068-a719-483d-a287-e335b917de17--0
Gitterdrager | Plan 2 |  | 0022Sym0780005928 |  | Pc |  | bf1069d1-83e8-43c2-a8ca-5ca0e7b3f951--780005928 | Allplan Attributes - V6: 0; V7: 0; V8: 0; V9: 0; Bottom_Level: 0; Top_Level: 0; Name: Gitterdrager
Gitterdrager | Plan 2 |  | 0022Sym0780005929 |  | Pc |  | bf1069d1-83e8-43c2-a8ca-5ca0e7b3f951--780005929 | Allplan Attributes - V6: 0; V7: 0; V8: 0; V9: 0; Bottom_Level: 0; Top_Level: 0; Name: Gitterdrager
Gitterdrager | Plan 2 |  | 0022Sym0780005930 |  | Pc |  | bf1069d1-83e8-43c2-a8ca-5ca0e7b3f951--780005930 | Allplan Attributes - V6: 0; V7: 0; V8: 0; V9: 0; Bottom_Level: 0; Top_Level: 0; Name: Gitterdrager
 | Plan 2 | T24 | 0023AdE0780004018 | New building | m³ | 9 | 84cb5e05-e28d-4939-8977-531e4630a18c--0
 | Plan 2 | T24 | 0023AdE0780004019 | New building | m³ | 9 | 84cb5e05-e28d-4939-8977-531e4630a18c--0
 | Plan 2 | T24 | 0023AdE0780004020 | New building | m³ | 9 | 84cb5e05-e28d-4939-8977-531e4630a18c--0
 | Plan 2 | T24 | 0023AdE0780004015 | New building | m³ | 9 | 84cb5e05-e28d-4939-8977-531e4630a18c--0
 | Plan 2 | T24 | 0023AdE0780004016 | New building | m³ | 9 | 84cb5e05-e28d-4939-8977-531e4630a18c--0
 | Plan 2 | T24 | 0023AdE0780004017 | New building | m³ | 9 | 84cb5e05-e28d-4939-8977-531e4630a18c--0
WC_2 | Plan 2 |  | 0027Sym0779994186 |  | m³ |  | 3ec40862-3d69-4019-a81b-24095b11a5d8--779994186 | Allplan Attributes - V6: 0; V7: 0; V8: 0; V9: 0

# IfcColumn (73)
Material: Stål
Allplan Attributes - Building alteration category: New building; Unit: m³
Name | In | Height (m) | GrossVolume (m3) = NetVolume (m3) | OuterSurfaceArea (m2) | GrossFloorArea (m2) | Allright_Comp_ID | NOI_UUID | Material
 | Plan 1 | 3.47 | 0.078075 | 2.127 | 0.0225 | 0011Col0016820700 | 3244f7b8-136b-492f-bad8-2462ae0dead0--16820700
 | Plan 1 | 3.47 | 0.078075 | 2.127 | 0.0225 | 0011Col0016820691 | 3244f7b8-136b-492f-bad8-2462ae0dead0--16820691
 | Plan 1 | 3.47 | 0.078075 | 2.127 | 0.0225 | 0011Col0016820686 | 3244f7b8-136b-492f-bad8-2462ae0dead0--16820686
 | Plan 1 | 3.47 | 0.078075 | 2.127 | 0.0225 | 0011Col0016820685 | 3244f7b8-136b-492f-bad8-2462ae0dead0--16820685
 | Plan 1 | 3.47 | 0.078075 | 2.127 | 0.0225 | 0011Col0016820680 | 3244f7b8-136b-492f-bad8-2462ae0dead0--16820680
 | Plan 1 | 3.47 | 0.078075 | 2.127 | 0.0225 | 0011Col0016820675 | 3244f7b8-136b-492f-bad8-2462ae0dead0--16820675
 | Plan 1 | 3.47 | 0.078075 | 2.127 | 0.0225 | 0011Col0016820670 | 3244f7b8-136b-492f-bad8-2462ae0dead0--16820670
 | Plan 1 | 3.47 | 0.078075 | 2.127 | 0.0225 | 0011Col0016820665 | 3244f7b8-136b-492f-bad8-2462ae0dead0--16820665
 | Plan 1 | 3.47 | 0.078075 | 2.127 | 0.0225 | 0011Col0016820659 | 3244f7b8-136b-492f-bad8-2462ae0dead0--16820659
 | Plan 1 | 3.47 | 0.078075 | 2.127 | 0.0225 | 0011Col0016820654 | 3244f7b8-136b-492f-bad8-2462ae0dead0--16820654
 | Plan 1 | 3.47 | 0.078075 | 2.127 | 0.0225 | 0011Col0016820649 | 3244f7b8-136b-492f-bad8-2462ae0dead0--16820649
 | Plan 1 | 3.47 | 0.078075 | 2.127 | 0.0225 | 0011Col0016819636 | 3244f7b8-136b-492f-bad8-2462ae0dead0--16819636
 | Plan 1 | 3.47 | 0.078075 | 2.127 | 0.0225 | 0011Col0016819614 | 3244f7b8-136b-492f-bad8-2462ae0dead0--16819614
 | Plan 1 | 3.47 | 0.078075 | 2.127 | 0.0225 | 0011Col0016819628 | 3244f7b8-136b-492f-bad8-2462ae0dead0--16819628 | Stål
 | Plan 1 | 3.47 | 0.078075 | 2.127 | 0.0225 | 0011Col0016819815 | 3244f7b8-136b-492f-bad8-2462ae0dead0--16819815
 | Plan 1 | 3.47 | 0.078075 | 2.127 | 0.0225 | 0011Col0016819814 | 3244f7b8-136b-492f-bad8-2462ae0dead0--16819814
 | Plan 1 | 3.47 | 0.078075 | 2.127 | 0.0225 | 0011Col0016819630 | 3244f7b8-136b-492f-bad8-2462ae0dead0--16819630
 | Plan 1 | 3.47 | 0.078075 | 2.127 | 0.0225 | 0011Col0016820531 | 3244f7b8-136b-492f-bad8-2462ae0dead0--16820531
 | Plan 1 | 3.47 | 0.078075 | 2.127 | 0.0225 | 0011Col0016820532 | 3244f7b8-136b-492f-bad8-2462ae0dead0--16820532
 | Plan 1 | 3.47 | 0.0347 | 1.408 | 0.01 | 0011Col0016820955 | 3244f7b8-136b-492f-bad8-2462ae0dead0--16820955
 | Plan 1 | 3.47 | 0.0347 | 1.408 | 0.01 | 0011Col0016820949 | 3244f7b8-136b-492f-bad8-2462ae0dead0--16820949
 | Plan 1 | 3.47 | 0.0347 | 1.408 | 0.01 | 0011Col0016820986 | 3244f7b8-136b-492f-bad8-2462ae0dead0--16820986
 | Plan 1 | 3.47 | 0.0347 | 1.408 | 0.01 | 0011Col0016820985 | 3244f7b8-136b-492f-bad8-2462ae0dead0--16820985
 | Plan 1 | 3.47 | 0.0347 | 1.408 | 0.01 | 0011Col0016820999 | 3244f7b8-136b-492f-bad8-2462ae0dead0--16820999
 | Plan 1 | 3.47 | 0.0347 | 1.408 | 0.01 | 0011Col0016820998 | 3244f7b8-136b-492f-bad8-2462ae0dead0--16820998
 | Plan 1 | 3.47 | 0.078075 | 2.127 | 0.0225 | 0011Col0016819608 | 3244f7b8-136b-492f-bad8-2462ae0dead0--16819608
 | Plan 1 | 3.47 | 0.078075 | 2.127 | 0.0225 | 0011Col0016819807 | 3244f7b8-136b-492f-bad8-2462ae0dead0--16819807
 | Plan 1 | 3.47 | 0.078075 | 2.127 | 0.0225 | 0011Col0016819806 | 3244f7b8-136b-492f-bad8-2462ae0dead0--16819806
 | Plan 1 | 3.47 | 0.078075 | 2.127 | 0.0225 | 0011Col0016819620 | 3244f7b8-136b-492f-bad8-2462ae0dead0--16819620
 | Plan 1 | 3.47 | 0.078075 | 2.127 | 0.0225 | 0011Col0016819618 | 3244f7b8-136b-492f-bad8-2462ae0dead0--16819618
 | Plan 1 | 3.7 | 0.08325 | 2.265 | 0.0225 | 0011Col0016819632 | 3244f7b8-136b-492f-bad8-2462ae0dead0--16819632 | Stål
 | Plan 1 | 3.7 | 0.08325 | 2.265 | 0.0225 | 0011Col0016821019 | 3244f7b8-136b-492f-bad8-2462ae0dead0--16821019 | Stål
 | Plan 1 | 3.7 | 0.08325 | 2.265 | 0.0225 | 0011Col0016821018 | 3244f7b8-136b-492f-bad8-2462ae0dead0--16821018 | Stål
 | Plan 1 | 3.7 | 0.08325 | 2.265 | 0.0225 | 0011Col0016819626 | 3244f7b8-136b-492f-bad8-2462ae0dead0--16819626 | Stål
 | Plan 1 | 3.7 | 0.08325 | 2.265 | 0.0225 | 0011Col0016819694 | 3244f7b8-136b-492f-bad8-2462ae0dead0--16819694 | Stål
 | Plan 1 | 3.7 | 0.08325 | 2.265 | 0.0225 | 0011Col0016819624 | 3244f7b8-136b-492f-bad8-2462ae0dead0--16819624 | Stål
 | Plan 1 | 3.7 | 0.08325 | 2.265 | 0.0225 | 0011Col0016819622 | 3244f7b8-136b-492f-bad8-2462ae0dead0--16819622 | Stål
 | Plan 1 | 3.7 | 0.08325 | 2.265 | 0.0225 | 0011Col0016820948 | 3244f7b8-136b-492f-bad8-2462ae0dead0--16820948 | Stål
 | Plan 1 | 3.7 | 0.08325 | 2.265 | 0.0225 | 0011Col0016819610 | 3244f7b8-136b-492f-bad8-2462ae0dead0--16819610 | Stål
 | Plan 1 | 3.7 | 0.08325 | 2.265 | 0.0225 | 0011Col0016819693 | 3244f7b8-136b-492f-bad8-2462ae0dead0--16819693 | Stål
 | Plan 1 | 3.7 | 0.08325 | 2.265 | 0.0225 | 0011Col0016819634 | 3244f7b8-136b-492f-bad8-2462ae0dead0--16819634 | Stål
 | Plan 1 | 3.17 | 0.071325 | 1.947 | 0.0225 | 0011Col0016821022 | 3244f7b8-136b-492f-bad8-2462ae0dead0--16821022 | Stål
 | Plan 1 | 3.7 | 0.08325 | 2.265 | 0.0225 | 0011Col0016819805 | 3244f7b8-136b-492f-bad8-2462ae0dead0--16819805 | Stål
 | Plan 1 | 2.62905 | 0.0262905 | 1.07162 | 0.01 | 0011Col0016821096 | 3244f7b8-136b-492f-bad8-2462ae0dead0--16821096 | Stål
 | Plan 1 | 2.5 | 0.025 | 1.02 | 0.01 | 0011Col0016819816 | 3244f7b8-136b-492f-bad8-2462ae0dead0--16819816 | Stål
 | Plan 1 | 2.62905 | 0.0262905 | 1.07162 | 0.01 | 0011Col0016821095 | 3244f7b8-136b-492f-bad8-2462ae0dead0--16821095 | Stål
 | Plan 1 | 2.5 | 0.025 | 1.02 | 0.01 | 0011Col0016819817 | 3244f7b8-136b-492f-bad8-2462ae0dead0--16819817 | Stål
 | Plan 1 | 2.62905 | 0.0262905 | 1.07162 | 0.01 | 0011Col0016821123 | 3244f7b8-136b-492f-bad8-2462ae0dead0--16821123 | Stål
 | Plan 1 | 2.5 | 0.025 | 1.02 | 0.01 | 0011Col0016821120 | 3244f7b8-136b-492f-bad8-2462ae0dead0--16821120 | Stål
 | Plan 1 | 2.5 | 0.025 | 1.02 | 0.01 | 0011Col0016821121 | 3244f7b8-136b-492f-bad8-2462ae0dead0--16821121 | Stål
 | Plan 1 | 2.62905 | 0.0262905 | 1.07162 | 0.01 | 0011Col0016821124 | 3244f7b8-136b-492f-bad8-2462ae0dead0--16821124 | Stål
 | Plan 2 | 2.41 | 0.0241 | 0.984 | 0.01 | 0021Col0000001007 | 1c7d8068-a719-483d-a287-e335b917de17--1007 | Stål
 | Plan 2 | 2.41 | 0.0241 | 0.984 | 0.01 | 0021Col0000001004 | 1c7d8068-a719-483d-a287-e335b917de17--1004 | Stål
 | Plan 2 | 2.41 | 0.0241 | 0.984 | 0.01 | 0021Col0000001010 | 1c7d8068-a719-483d-a287-e335b917de17--1010 | Stål
 | Plan 2 | 2.41 | 0.0241 | 0.984 | 0.01 | 0021Col0000000995 | 1c7d8068-a719-483d-a287-e335b917de17--995 | Stål
 | Plan 2 | 3.2294 | 0.0726616 | 1.98269 | 0.0225 | 0021Col0000001093 | 1c7d8068-a719-483d-a287-e335b917de17--1093 | Stål
 | Plan 2 | 3.1454 | 0.0707716 | 1.93229 | 0.0225 | 0021Col0000001103 | 1c7d8068-a719-483d-a287-e335b917de17--1103 | Stål
 | Plan 2 | 3.1727 | 0.031727 | 1.2891 | 0.01 | 0021Col0000001212 | 1c7d8068-a719-483d-a287-e335b917de17--1212 | Stål
 | Plan 2 | 2.80433 | 0.0630975 | 1.72765 | 0.0225 | 0021Col0000000031 | 1c7d8068-a719-483d-a287-e335b917de17--31 | Stål
 | Plan 2 | 2.8 | 0.063 | 1.725 | 0.0225 | 0021Col0000000035 | 1c7d8068-a719-483d-a287-e335b917de17--35 | Stål
 | Plan 2 | 2.8 | 0.063 | 1.725 | 0.0225 | 0021Col0000000039 | 1c7d8068-a719-483d-a287-e335b917de17--39 | Stål
 | Plan 2 | 2.8 | 0.063 | 1.725 | 0.0225 | 0021Col0000000043 | 1c7d8068-a719-483d-a287-e335b917de17--43 | Stål
 | Plan 2 | 2.80433 | 0.0630975 | 1.72765 | 0.0225 | 0021Col0000000019 | 1c7d8068-a719-483d-a287-e335b917de17--19 | Stål
 | Plan 2 | 3.066 | 0.068985 | 1.88465 | 0.0225 | 0021Col0000000120 | 1c7d8068-a719-483d-a287-e335b917de17--120 | Stål
 | Plan 2 | 3.33267 | 0.074985 | 2.04465 | 0.0225 | 0021Col0000000122 | 1c7d8068-a719-483d-a287-e335b917de17--122 | Stål
 | Plan 2 | 3.66378 | 0.082435 | 2.24332 | 0.0225 | 0021Col0000000982 | 1c7d8068-a719-483d-a287-e335b917de17--982 | Stål
 | Plan 2 | 3.59433 | 0.0808725 | 2.20165 | 0.0225 | 0021Col0000000045 | 1c7d8068-a719-483d-a287-e335b917de17--45 | Stål
 | Plan 2 | 3.6 | 0.081 | 2.205 | 0.0225 | 0021Col0000000041 | 1c7d8068-a719-483d-a287-e335b917de17--41 | Stål
 | Plan 2 | 3.6 | 0.081 | 2.205 | 0.0225 | 0021Col0000000037 | 1c7d8068-a719-483d-a287-e335b917de17--37 | Stål
 | Plan 2 | 3.6 | 0.081 | 2.205 | 0.0225 | 0021Col0000000033 | 1c7d8068-a719-483d-a287-e335b917de17--33 | Stål
 | Plan 2 | 3.59433 | 0.0808725 | 2.20165 | 0.0225 | 0021Col0000000029 | 1c7d8068-a719-483d-a287-e335b917de17--29 | Stål
 | Plan 2 | 3.33267 | 0.074985 | 2.04465 | 0.0225 | 0021Col0000000124 | 1c7d8068-a719-483d-a287-e335b917de17--124 | Stål
 | Plan 2 | 3.066 | 0.068985 | 1.88465 | 0.0225 | 0021Col0000000126 | 1c7d8068-a719-483d-a287-e335b917de17--126 | Stål

# IfcCovering (83)
Name | In | PredefinedType | Material | Allright_Comp_ID | Building alteration category | Unit | Layer_number = Factor | LayerThickness (mm) | Allplan Attributes, Material | NOI_UUID | Reference_Height = Delta_Height | GrossArea (m2)
2 x  | 101 | CLADDING | Ubehandlet SW 30 mm | 0019Sid0779929073/01 | New building | m² | 1 | 30 | Ubehandlet SW | ac553d8b-398e-4058-95c3-ac796ec1c327--779929073 | 0
 | 101 | FLOORING | Banebelegg, acustikk 3 mm | 0019Fsu0779929173/01 | New building | m² | 1 | 3 | Banebelegg, acustikk | ac553d8b-398e-4058-95c3-ac796ec1c327--779929173 | 0 | 10.6105
 | 101 | CEILING | Støvbinding 30 mm, Systemhimling 30 mm |  |  |  |  |  |  |  |  | 10.6105 | Allplan Attributes - Object Layer Attributes #1, Allright_Comp_ID: 0019Csu0779929172/01; Object Layer Attributes #1, Building alteration category: New building; Object Layer Attributes #1, Unit: m²; Object Layer Attributes #1, Layer_number: 1; Object Layer Attributes #1, LayerThickness: 30 mm; Object Layer Attributes #1, Factor: 1; Object Layer Attributes #1, Material: Støvbinding; Object Layer Attributes #1, NOI_UUID: ac553d8b-398e-4058-95c3-ac796ec1c327--779929172; Object Layer Attributes #1, Reference_Height: 0; Object Layer Attributes #1, Delta_Height: 0; Object Layer Attributes #2, Allright_Comp_ID: 0019Csu0779929172/01; Object Layer Attributes #2, Building alteration category: New building; Object Layer Attributes #2, Unit: m²; Object Layer Attributes #2, Layer_number: 2; Object Layer Attributes #2, LayerThickness: 30 mm; Object Layer Attributes #2, Factor: 1; Object Layer Attributes #2, Material: Systemhimling; Object Layer Attributes #2, NOI_UUID: ac553d8b-398e-4058-95c3-ac796ec1c327--779929172; Object Layer Attributes #2, Reference_Height: 0; Object Layer Attributes #2, Delta_Height: 0
 | 107 | CLADDING | Ubehandlet SW 30 mm | 0019Sid0779929058/01 | New building | m² | 1 | 30 | Ubehandlet SW | ac553d8b-398e-4058-95c3-ac796ec1c327--779929058 | 0
 | 107 | CLADDING | Ubehandlet SW 30 mm | 0019Sid0779929063/01 | New building | m² | 1 | 30 | Ubehandlet SW | ac553d8b-398e-4058-95c3-ac796ec1c327--779929063 | 0
 | 107 | FLOORING | våtromsbelegg m oppkant 3 mm | 0019Fsu0779929155/01 | New building | m² | 1 | 3 | våtromsbelegg m oppkant | ac553d8b-398e-4058-95c3-ac796ec1c327--779929155 | 0 | 2.87491
 | 107 | CEILING | støvbinding 30 mm, systemhimling 30 mm |  |  |  |  |  |  |  |  | 2.87491 | Allplan Attributes - Object Layer Attributes #1, Allright_Comp_ID: 0019Csu0779929154/01; Object Layer Attributes #1, Building alteration category: New building; Object Layer Attributes #1, Unit: m²; Object Layer Attributes #1, Layer_number: 1; Object Layer Attributes #1, LayerThickness: 30 mm; Object Layer Attributes #1, Factor: 1; Object Layer Attributes #1, Material: støvbinding; Object Layer Attributes #1, NOI_UUID: ac553d8b-398e-4058-95c3-ac796ec1c327--779929154; Object Layer Attributes #1, Reference_Height: 0; Object Layer Attributes #1, Delta_Height: 0; Object Layer Attributes #2, Allright_Comp_ID: 0019Csu0779929154/01; Object Layer Attributes #2, Building alteration category: New building; Object Layer Attributes #2, Unit: m²; Object Layer Attributes #2, Layer_number: 2; Object Layer Attributes #2, LayerThickness: 30 mm; Object Layer Attributes #2, Factor: 1; Object Layer Attributes #2, Material: systemhimling; Object Layer Attributes #2, NOI_UUID: ac553d8b-398e-4058-95c3-ac796ec1c327--779929154; Object Layer Attributes #2, Reference_Height: 0; Object Layer Attributes #2, Delta_Height: 0
 | 108 | FLOORING | våtromsbelegg m oppkant 3 mm | 0019Fsu0779929152/01 | New building | m² | 1 | 3 | våtromsbelegg m oppkant | ac553d8b-398e-4058-95c3-ac796ec1c327--779929152 | 0 | 5.27978
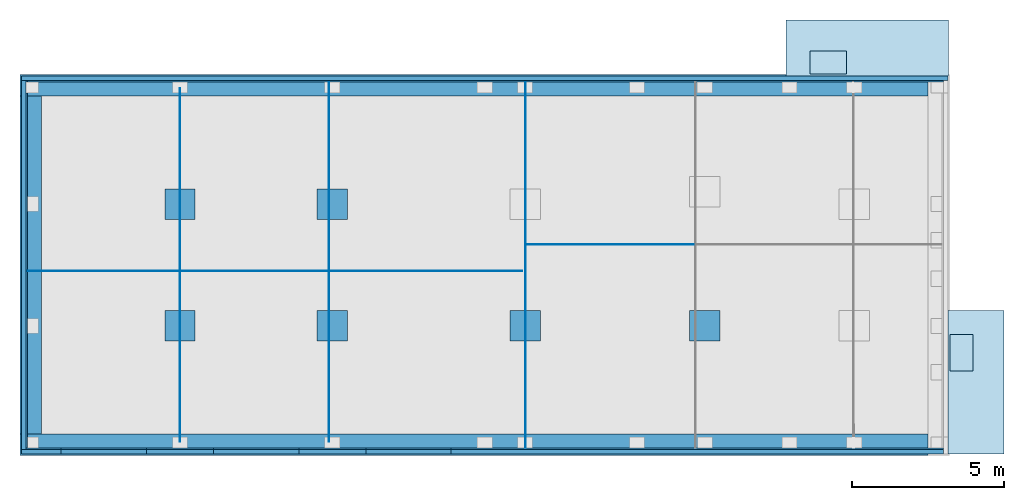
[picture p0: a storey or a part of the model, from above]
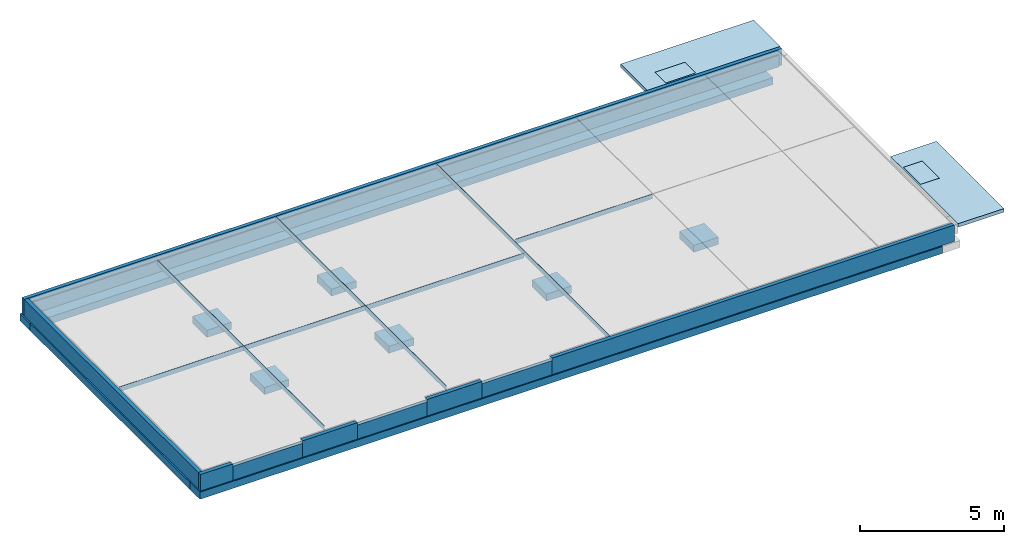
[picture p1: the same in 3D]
Properties of the parts of a building model (IFC2X3), part 4 of 7

# IfcCovering (83)
Name | In | PredefinedType | Material | Allright_Comp_ID | Building alteration category | Unit | Layer_number = Factor | LayerThickness (mm) | Allplan Attributes, Material | NOI_UUID | Reference_Height = Delta_Height | GrossArea (m2)
 | 108 | CEILING | støvbinding 30 mm, systemhimling 30 mm |  |  |  |  |  |  |  |  | 5.27978 | Allplan Attributes - Object Layer Attributes #1, Allright_Comp_ID: 0019Csu0779929151/01; Object Layer Attributes #1, Building alteration category: New building; Object Layer Attributes #1, Unit: m²; Object Layer Attributes #1, Layer_number: 1; Object Layer Attributes #1, LayerThickness: 30 mm; Object Layer Attributes #1, Factor: 1; Object Layer Attributes #1, Material: støvbinding; Object Layer Attributes #1, NOI_UUID: ac553d8b-398e-4058-95c3-ac796ec1c327--779929151; Object Layer Attributes #1, Reference_Height: 0; Object Layer Attributes #1, Delta_Height: 0; Object Layer Attributes #2, Allright_Comp_ID: 0019Csu0779929151/01; Object Layer Attributes #2, Building alteration category: New building; Object Layer Attributes #2, Unit: m²; Object Layer Attributes #2, Layer_number: 2; Object Layer Attributes #2, LayerThickness: 30 mm; Object Layer Attributes #2, Factor: 1; Object Layer Attributes #2, Material: systemhimling; Object Layer Attributes #2, NOI_UUID: ac553d8b-398e-4058-95c3-ac796ec1c327--779929151; Object Layer Attributes #2, Reference_Height: 0; Object Layer Attributes #2, Delta_Height: 0
 | 109 | CLADDING | Ubehandlet SW 30 mm | 0019Sid0779929053/01 | New building | m² | 1 | 30 | Ubehandlet SW | ac553d8b-398e-4058-95c3-ac796ec1c327--779929053 | 0
 | 109 | FLOORING | våtromsbelegg m oppkant 3 mm | 0019Fsu0779929131/01 | New building | m² | 1 | 3 | våtromsbelegg m oppkant | ac553d8b-398e-4058-95c3-ac796ec1c327--779929131 | 0 | 2.12328
 | 109 | CEILING | støvbinding 30 mm, systemhimling 30 mm |  |  |  |  |  |  |  |  | 2.12328 | Allplan Attributes - Object Layer Attributes #1, Allright_Comp_ID: 0019Csu0779929130/01; Object Layer Attributes #1, Building alteration category: New building; Object Layer Attributes #1, Unit: m²; Object Layer Attributes #1, Layer_number: 1; Object Layer Attributes #1, LayerThickness: 30 mm; Object Layer Attributes #1, Factor: 1; Object Layer Attributes #1, Material: støvbinding; Object Layer Attributes #1, NOI_UUID: ac553d8b-398e-4058-95c3-ac796ec1c327--779929130; Object Layer Attributes #1, Reference_Height: 0; Object Layer Attributes #1, Delta_Height: 0; Object Layer Attributes #2, Allright_Comp_ID: 0019Csu0779929130/01; Object Layer Attributes #2, Building alteration category: New building; Object Layer Attributes #2, Unit: m²; Object Layer Attributes #2, Layer_number: 2; Object Layer Attributes #2, LayerThickness: 30 mm; Object Layer Attributes #2, Factor: 1; Object Layer Attributes #2, Material: systemhimling; Object Layer Attributes #2, NOI_UUID: ac553d8b-398e-4058-95c3-ac796ec1c327--779929130; Object Layer Attributes #2, Reference_Height: 0; Object Layer Attributes #2, Delta_Height: 0
 | 110 | CLADDING | Ubehandlet SW 30 mm | 0019Sid0779929048/01 | New building | m² | 1 | 30 | Ubehandlet SW | ac553d8b-398e-4058-95c3-ac796ec1c327--779929048 | 0
 | 110 | FLOORING | våtromsbelegg m oppkant 3 mm | 0019Fsu0779929128/01 | New building | m² | 1 | 3 | våtromsbelegg m oppkant | ac553d8b-398e-4058-95c3-ac796ec1c327--779929128 | 0 | 12.915
 | 110 | CEILING | støvbinding 30 mm, systemhimling 30 mm |  |  |  |  |  |  |  |  | 12.915 | Allplan Attributes - Object Layer Attributes #1, Allright_Comp_ID: 0019Csu0779929127/01; Object Layer Attributes #1, Building alteration category: New building; Object Layer Attributes #1, Unit: m²; Object Layer Attributes #1, Layer_number: 1; Object Layer Attributes #1, LayerThickness: 30 mm; Object Layer Attributes #1, Factor: 1; Object Layer Attributes #1, Material: støvbinding; Object Layer Attributes #1, NOI_UUID: ac553d8b-398e-4058-95c3-ac796ec1c327--779929127; Object Layer Attributes #1, Reference_Height: 0; Object Layer Attributes #1, Delta_Height: 0; Object Layer Attributes #2, Allright_Comp_ID: 0019Csu0779929127/01; Object Layer Attributes #2, Building alteration category: New building; Object Layer Attributes #2, Unit: m²; Object Layer Attributes #2, Layer_number: 2; Object Layer Attributes #2, LayerThickness: 30 mm; Object Layer Attributes #2, Factor: 1; Object Layer Attributes #2, Material: systemhimling; Object Layer Attributes #2, NOI_UUID: ac553d8b-398e-4058-95c3-ac796ec1c327--779929127; Object Layer Attributes #2, Reference_Height: 0; Object Layer Attributes #2, Delta_Height: 0
 | 114 | FLOORING | våtromsbelegg m oppkant 3 mm | 0019Fsu0779929137/01 | New building | m² | 1 | 3 | våtromsbelegg m oppkant | ac553d8b-398e-4058-95c3-ac796ec1c327--779929137 | 0 | 2.31713
 | 114 | CEILING | støvbinding 30 mm, systemhimling 30 mm |  |  |  |  |  |  |  |  | 2.31713 | Allplan Attributes - Object Layer Attributes #1, Allright_Comp_ID: 0019Csu0779929136/01; Object Layer Attributes #1, Building alteration category: New building; Object Layer Attributes #1, Unit: m²; Object Layer Attributes #1, Layer_number: 1; Object Layer Attributes #1, LayerThickness: 30 mm; Object Layer Attributes #1, Factor: 1; Object Layer Attributes #1, Material: støvbinding; Object Layer Attributes #1, NOI_UUID: ac553d8b-398e-4058-95c3-ac796ec1c327--779929136; Object Layer Attributes #1, Reference_Height: 0; Object Layer Attributes #1, Delta_Height: 0; Object Layer Attributes #2, Allright_Comp_ID: 0019Csu0779929136/01; Object Layer Attributes #2, Building alteration category: New building; Object Layer Attributes #2, Unit: m²; Object Layer Attributes #2, Layer_number: 2; Object Layer Attributes #2, LayerThickness: 30 mm; Object Layer Attributes #2, Factor: 1; Object Layer Attributes #2, Material: systemhimling; Object Layer Attributes #2, NOI_UUID: ac553d8b-398e-4058-95c3-ac796ec1c327--779929136; Object Layer Attributes #2, Reference_Height: 0; Object Layer Attributes #2, Delta_Height: 0
 | 111 | FLOORING | våtromsbelegg m oppkant 3 mm | 0019Fsu0779929134/01 | New building | m² | 1 | 3 | våtromsbelegg m oppkant | ac553d8b-398e-4058-95c3-ac796ec1c327--779929134 | 0 | 3.54004
 | 111 | CEILING | støvbinding 30 mm, systemhimling 30 mm |  |  |  |  |  |  |  |  | 3.54004 | Allplan Attributes - Object Layer Attributes #1, Allright_Comp_ID: 0019Csu0779929133/01; Object Layer Attributes #1, Building alteration category: New building; Object Layer Attributes #1, Unit: m²; Object Layer Attributes #1, Layer_number: 1; Object Layer Attributes #1, LayerThickness: 30 mm; Object Layer Attributes #1, Factor: 1; Object Layer Attributes #1, Material: støvbinding; Object Layer Attributes #1, NOI_UUID: ac553d8b-398e-4058-95c3-ac796ec1c327--779929133; Object Layer Attributes #1, Reference_Height: 0; Object Layer Attributes #1, Delta_Height: 0; Object Layer Attributes #2, Allright_Comp_ID: 0019Csu0779929133/01; Object Layer Attributes #2, Building alteration category: New building; Object Layer Attributes #2, Unit: m²; Object Layer Attributes #2, Layer_number: 2; Object Layer Attributes #2, LayerThickness: 30 mm; Object Layer Attributes #2, Factor: 1; Object Layer Attributes #2, Material: systemhimling; Object Layer Attributes #2, NOI_UUID: ac553d8b-398e-4058-95c3-ac796ec1c327--779929133; Object Layer Attributes #2, Reference_Height: 0; Object Layer Attributes #2, Delta_Height: 0
 | 115 | FLOORING | våtromsbelegg m oppkant 3 mm | 0019Fsu0779929140/01 | New building | m² | 1 | 3 | våtromsbelegg m oppkant | ac553d8b-398e-4058-95c3-ac796ec1c327--779929140 | 0 | 2.85514
 | 115 | CEILING | støvbinding 30 mm, systemhimling 30 mm |  |  |  |  |  |  |  |  | 2.85514 | Allplan Attributes - Object Layer Attributes #1, Allright_Comp_ID: 0019Csu0779929139/01; Object Layer Attributes #1, Building alteration category: New building; Object Layer Attributes #1, Unit: m²; Object Layer Attributes #1, Layer_number: 1; Object Layer Attributes #1, LayerThickness: 30 mm; Object Layer Attributes #1, Factor: 1; Object Layer Attributes #1, Material: støvbinding; Object Layer Attributes #1, NOI_UUID: ac553d8b-398e-4058-95c3-ac796ec1c327--779929139; Object Layer Attributes #1, Reference_Height: 0; Object Layer Attributes #1, Delta_Height: 0; Object Layer Attributes #2, Allright_Comp_ID: 0019Csu0779929139/01; Object Layer Attributes #2, Building alteration category: New building; Object Layer Attributes #2, Unit: m²; Object Layer Attributes #2, Layer_number: 2; Object Layer Attributes #2, LayerThickness: 30 mm; Object Layer Attributes #2, Factor: 1; Object Layer Attributes #2, Material: systemhimling; Object Layer Attributes #2, NOI_UUID: ac553d8b-398e-4058-95c3-ac796ec1c327--779929139; Object Layer Attributes #2, Reference_Height: 0; Object Layer Attributes #2, Delta_Height: 0
 | 116 | CLADDING | Ubehandlet SW 30 mm | 0019Sid0779929093/01 | New building | m² | 1 | 30 | Ubehandlet SW | ac553d8b-398e-4058-95c3-ac796ec1c327--779929093 | 0
 | 116 | FLOORING | våtromsbelegg m oppkant 3 mm | 0019Fsu0779929149/01 | New building | m² | 1 | 3 | våtromsbelegg m oppkant | ac553d8b-398e-4058-95c3-ac796ec1c327--779929149 | 0 | 13.8195
 | 116 | CEILING | støvbinding 30 mm, systemhimling 30 mm |  |  |  |  |  |  |  |  | 13.8195 | Allplan Attributes - Object Layer Attributes #1, Allright_Comp_ID: 0019Csu0779929148/01; Object Layer Attributes #1, Building alteration category: New building; Object Layer Attributes #1, Unit: m²; Object Layer Attributes #1, Layer_number: 1; Object Layer Attributes #1, LayerThickness: 30 mm; Object Layer Attributes #1, Factor: 1; Object Layer Attributes #1, Material: støvbinding; Object Layer Attributes #1, NOI_UUID: ac553d8b-398e-4058-95c3-ac796ec1c327--779929148; Object Layer Attributes #1, Reference_Height: 0; Object Layer Attributes #1, Delta_Height: 0; Object Layer Attributes #2, Allright_Comp_ID: 0019Csu0779929148/01; Object Layer Attributes #2, Building alteration category: New building; Object Layer Attributes #2, Unit: m²; Object Layer Attributes #2, Layer_number: 2; Object Layer Attributes #2, LayerThickness: 30 mm; Object Layer Attributes #2, Factor: 1; Object Layer Attributes #2, Material: systemhimling; Object Layer Attributes #2, NOI_UUID: ac553d8b-398e-4058-95c3-ac796ec1c327--779929148; Object Layer Attributes #2, Reference_Height: 0; Object Layer Attributes #2, Delta_Height: 0
 | 117 | CLADDING | Ubehandlet SW 30 mm | 0019Sid0779929098/01 | New building | m² | 1 | 30 | Ubehandlet SW | ac553d8b-398e-4058-95c3-ac796ec1c327--779929098 | 0
 | 117 | FLOORING | våtromsbelegg m oppkant 30 mm | 0019Fsu0779929143/01 | New building | m² | 1 | 30 | våtromsbelegg m oppkant | ac553d8b-398e-4058-95c3-ac796ec1c327--779929143 | 0 | 13.1838
 | 117 | CEILING | støvbinding 30 mm, systemhimling 30 mm |  |  |  |  |  |  |  |  | 13.1838 | Allplan Attributes - Object Layer Attributes #1, Allright_Comp_ID: 0019Csu0779929142/01; Object Layer Attributes #1, Building alteration category: New building; Object Layer Attributes #1, Unit: m²; Object Layer Attributes #1, Layer_number: 1; Object Layer Attributes #1, LayerThickness: 30 mm; Object Layer Attributes #1, Factor: 1; Object Layer Attributes #1, Material: støvbinding; Object Layer Attributes #1, NOI_UUID: ac553d8b-398e-4058-95c3-ac796ec1c327--779929142; Object Layer Attributes #1, Reference_Height: 0; Object Layer Attributes #1, Delta_Height: 0; Object Layer Attributes #2, Allright_Comp_ID: 0019Csu0779929142/01; Object Layer Attributes #2, Building alteration category: New building; Object Layer Attributes #2, Unit: m²; Object Layer Attributes #2, Layer_number: 2; Object Layer Attributes #2, LayerThickness: 30 mm; Object Layer Attributes #2, Factor: 1; Object Layer Attributes #2, Material: systemhimling; Object Layer Attributes #2, NOI_UUID: ac553d8b-398e-4058-95c3-ac796ec1c327--779929142; Object Layer Attributes #2, Reference_Height: 0; Object Layer Attributes #2, Delta_Height: 0
 | 113 | FLOORING | Våtromsbelegg 3 mm | 0019Fsu0779929146/01 | New building | m² | 1 | 3 | Våtromsbelegg | ac553d8b-398e-4058-95c3-ac796ec1c327--779929146 | 0 | 4.2328
 | 113 | CEILING | Støvbinding 30 mm, Systemhimling 30 mm |  |  |  |  |  |  |  |  | 4.2328 | Allplan Attributes - Object Layer Attributes #1, Allright_Comp_ID: 0019Csu0779929145/01; Object Layer Attributes #1, Building alteration category: New building; Object Layer Attributes #1, Unit: m²; Object Layer Attributes #1, Layer_number: 1; Object Layer Attributes #1, LayerThickness: 30 mm; Object Layer Attributes #1, Factor: 1; Object Layer Attributes #1, Material: Støvbinding; Object Layer Attributes #1, NOI_UUID: ac553d8b-398e-4058-95c3-ac796ec1c327--779929145; Object Layer Attributes #1, Reference_Height: 0; Object Layer Attributes #1, Delta_Height: 0; Object Layer Attributes #2, Allright_Comp_ID: 0019Csu0779929145/01; Object Layer Attributes #2, Building alteration category: New building; Object Layer Attributes #2, Unit: m²; Object Layer Attributes #2, Layer_number: 2; Object Layer Attributes #2, LayerThickness: 30 mm; Object Layer Attributes #2, Factor: 1; Object Layer Attributes #2, Material: Systemhimling; Object Layer Attributes #2, NOI_UUID: ac553d8b-398e-4058-95c3-ac796ec1c327--779929145; Object Layer Attributes #2, Reference_Height: 0; Object Layer Attributes #2, Delta_Height: 0
 | 120 | CLADDING | Ubehandlet SW 30 mm | 0019Sid0779929038/01 | New building | m² | 1 | 30 | Ubehandlet SW | ac553d8b-398e-4058-95c3-ac796ec1c327--779929038 | 0
 | 120 | FLOORING | Golvmaling 3 mm | 0019Fsu0779929110/01 | New building | m² | 1 | 3 | Golvmaling | ac553d8b-398e-4058-95c3-ac796ec1c327--779929110 | 0 | 18.8898
 | 120 | CEILING | Støvbinding x2 30 mm | 0019Csu0779929109/01 | New building | m² | 1 | 30 | Støvbinding x2 | ac553d8b-398e-4058-95c3-ac796ec1c327--779929109 | 0 | 18.8898
 | 119 | FLOORING | Våtromsbelegg 3 mm | 0019Fsu0779929119/01 | New building | m² | 1 | 3 | Våtromsbelegg | ac553d8b-398e-4058-95c3-ac796ec1c327--779929119 | 0 | 4.27953
 | 119 | CEILING | Støvbinding x2 30 mm | 0019Csu0779929118/01 | New building | m² | 1 | 30 | Støvbinding x2 | ac553d8b-398e-4058-95c3-ac796ec1c327--779929118 | 0 | 4.27953
 | 121 | FLOORING | Våtromsbelegg 3 mm | 0019Fsu0779929116/01 | New building | m² | 1 | 3 | Våtromsbelegg | ac553d8b-398e-4058-95c3-ac796ec1c327--779929116 | 0 | 2.1665
 | 121 | CEILING | Støvbinding x2 30 mm | 0019Csu0779929115/01 | New building | m² | 1 | 30 | Støvbinding x2 | ac553d8b-398e-4058-95c3-ac796ec1c327--779929115 | 0 | 2.1665
 | 122 | FLOORING | Golvmaling 3 mm | 0019Fsu0779929113/01 | New building | m² | 1 | 3 | Golvmaling | ac553d8b-398e-4058-95c3-ac796ec1c327--779929113 | 0 | 6.92299
 | 122 | CEILING | Støvbinding x2 30 mm | 0019Csu0779929112/01 | New building | m² | 1 | 30 | Støvbinding x2 | ac553d8b-398e-4058-95c3-ac796ec1c327--779929112 | 0 | 6.92299
 | 123 | CLADDING | Ubehandlet SW 30 mm | 0019Sid0779928966/01 | New building | m² | 1 | 30 | Ubehandlet SW | ac553d8b-398e-4058-95c3-ac796ec1c327--779928966 | 0
 | 123 | CLADDING | Ubehandlet SW 30 mm | 0019Sid0779928973/01 | New building | m² | 1 | 30 | Ubehandlet SW | ac553d8b-398e-4058-95c3-ac796ec1c327--779928973 | 0
 | 123 | FLOORING | Golvmaling 3 mm | 0019Fsu0779928759/01 | New building | m² | 1 | 3 | Golvmaling | ac553d8b-398e-4058-95c3-ac796ec1c327--779928759 | 0 | 56.0843
 | 123 | CEILING | Støvbinding x2 30 mm | 0019Csu0779928758/01 | New building | m² | 1 | 30 | Støvbinding x2 | ac553d8b-398e-4058-95c3-ac796ec1c327--779928758 | 0 | 56.0843
3 x  | 124 | CLADDING | Ubehandlet SW 30 mm | 0019Sid0779928946/01 | New building | m² | 1 | 30 | Ubehandlet SW | ac553d8b-398e-4058-95c3-ac796ec1c327--779928946 | 0
 | 124 | FLOORING | Golvmaling 3 mm | 0019Fsu0779928742/01 | New building | m² | 1 | 3 | Golvmaling | ac553d8b-398e-4058-95c3-ac796ec1c327--779928742 | 0 | 59.2403
 | 124 | CEILING | Støvbinding x2 30 mm | 0019Csu0779928741/01 | New building | m² | 1 | 30 | Støvbinding x2 | ac553d8b-398e-4058-95c3-ac796ec1c327--779928741 | 0 | 59.2403
 | 118 | CLADDING | Ubehandlet SW 30 mm | 0019Sid0779929103/01 | New building | m² | 1 | 30 | Ubehandlet SW | ac553d8b-398e-4058-95c3-ac796ec1c327--779929103 | 0
 | 118 | FLOORING | Golvmaling 30 mm | 0019Fsu0779929122/01 | New building | m² | 1 | 30 | Golvmaling | ac553d8b-398e-4058-95c3-ac796ec1c327--779929122 | 0 | 40.9514
 | 118 | CEILING | Støvbinding x2 30 mm | 0019Csu0779929121/01 | New building | m² | 1 | 30 | Støvbinding x2 | ac553d8b-398e-4058-95c3-ac796ec1c327--779929121 | 0 | 40.9514
 | 102 | CLADDING | Ubehandlet SW 30 mm | 0019Sid0779929078/01 | New building | m² | 1 | 30 | Ubehandlet SW | ac553d8b-398e-4058-95c3-ac796ec1c327--779929078 | 0
 | 102 | FLOORING | Golvflis 3 mm | 0019Fsu0779929170/01 | New building | m² | 1 | 3 | Golvflis | ac553d8b-398e-4058-95c3-ac796ec1c327--779929170 | 0 | 11.1716
 | 102 | CEILING | Støvbinding 30 mm, Systemhimling 30 mm |  |  |  |  |  |  |  |  | 11.1716 | Allplan Attributes - Object Layer Attributes #1, Allright_Comp_ID: 0019Csu0779929169/01; Object Layer Attributes #1, Building alteration category: New building; Object Layer Attributes #1, Unit: m²; Object Layer Attributes #1, Layer_number: 1; Object Layer Attributes #1, LayerThickness: 30 mm; Object Layer Attributes #1, Factor: 1; Object Layer Attributes #1, Material: Støvbinding; Object Layer Attributes #1, NOI_UUID: ac553d8b-398e-4058-95c3-ac796ec1c327--779929169; Object Layer Attributes #1, Reference_Height: 0; Object Layer Attributes #1, Delta_Height: 0; Object Layer Attributes #2, Allright_Comp_ID: 0019Csu0779929169/01; Object Layer Attributes #2, Building alteration category: New building; Object Layer Attributes #2, Unit: m²; Object Layer Attributes #2, Layer_number: 2; Object Layer Attributes #2, LayerThickness: 30 mm; Object Layer Attributes #2, Factor: 1; Object Layer Attributes #2, Material: Systemhimling; Object Layer Attributes #2, NOI_UUID: ac553d8b-398e-4058-95c3-ac796ec1c327--779929169; Object Layer Attributes #2, Reference_Height: 0; Object Layer Attributes #2, Delta_Height: 0
 | 105 | CLADDING | Ubehandlet SW 30 mm | 0019Sid0779929088/01 | New building | m² | 1 | 30 | Ubehandlet SW | ac553d8b-398e-4058-95c3-ac796ec1c327--779929088 | 0
 | 105 | FLOORING | Banebelegg, homogent 3 mm | 0019Fsu0779929161/01 | New building | m² | 1 | 3 | Banebelegg, homogent | ac553d8b-398e-4058-95c3-ac796ec1c327--779929161 | 0 | 31.429
 | 105 | CEILING | Støvbinding 30 mm, Systemhimling 30 mm |  |  |  |  |  |  |  |  | 31.429 | Allplan Attributes - Object Layer Attributes #1, Allright_Comp_ID: 0019Csu0779929160/01; Object Layer Attributes #1, Building alteration category: New building; Object Layer Attributes #1, Unit: m²; Object Layer Attributes #1, Layer_number: 1; Object Layer Attributes #1, LayerThickness: 30 mm; Object Layer Attributes #1, Factor: 1; Object Layer Attributes #1, Material: Støvbinding; Object Layer Attributes #1, NOI_UUID: ac553d8b-398e-4058-95c3-ac796ec1c327--779929160; Object Layer Attributes #1, Reference_Height: 0; Object Layer Attributes #1, Delta_Height: 0; Object Layer Attributes #2, Allright_Comp_ID: 0019Csu0779929160/01; Object Layer Attributes #2, Building alteration category: New building; Object Layer Attributes #2, Unit: m²; Object Layer Attributes #2, Layer_number: 2; Object Layer Attributes #2, LayerThickness: 30 mm; Object Layer Attributes #2, Factor: 1; Object Layer Attributes #2, Material: Systemhimling; Object Layer Attributes #2, NOI_UUID: ac553d8b-398e-4058-95c3-ac796ec1c327--779929160; Object Layer Attributes #2, Reference_Height: 0; Object Layer Attributes #2, Delta_Height: 0
 | 112 | CLADDING | Ubehandlet SW 30 mm | 0019Sid0779929043/01 | New building | m² | 1 | 30 | Ubehandlet SW | ac553d8b-398e-4058-95c3-ac796ec1c327--779929043 | 0
 | 112 | FLOORING | våtromsbelegg m oppkant 3 mm | 0019Fsu0779929125/01 | New building | m² | 1 | 3 | våtromsbelegg m oppkant | ac553d8b-398e-4058-95c3-ac796ec1c327--779929125 | 0 | 9.54496
 | 112 | CEILING | støvbinding 30 mm, systemhimling 30 mm |  |  |  |  |  |  |  |  | 9.54496 | Allplan Attributes - Object Layer Attributes #1, Allright_Comp_ID: 0019Csu0779929124/01; Object Layer Attributes #1, Building alteration category: New building; Object Layer Attributes #1, Unit: m²; Object Layer Attributes #1, Layer_number: 1; Object Layer Attributes #1, LayerThickness: 30 mm; Object Layer Attributes #1, Factor: 1; Object Layer Attributes #1, Material: støvbinding; Object Layer Attributes #1, NOI_UUID: ac553d8b-398e-4058-95c3-ac796ec1c327--779929124; Object Layer Attributes #1, Reference_Height: 0; Object Layer Attributes #1, Delta_Height: 0; Object Layer Attributes #2, Allright_Comp_ID: 0019Csu0779929124/01; Object Layer Attributes #2, Building alteration category: New building; Object Layer Attributes #2, Unit: m²; Object Layer Attributes #2, Layer_number: 2; Object Layer Attributes #2, LayerThickness: 30 mm; Object Layer Attributes #2, Factor: 1; Object Layer Attributes #2, Material: systemhimling; Object Layer Attributes #2, NOI_UUID: ac553d8b-398e-4058-95c3-ac796ec1c327--779929124; Object Layer Attributes #2, Reference_Height: 0; Object Layer Attributes #2, Delta_Height: 0
2 x  | 103.1 | CLADDING | Ubehandlet SW 30 mm | 0019Sid0779929083/01 | New building | m² | 1 | 30 | Ubehandlet SW | ac553d8b-398e-4058-95c3-ac796ec1c327--779929083 | 0
 | 103.1 | FLOORING | Golvflis 3 mm | 0019Fsu0779929167/01 | New building | m² | 1 | 3 | Golvflis | ac553d8b-398e-4058-95c3-ac796ec1c327--779929167 | 0 | 6.40012
 | 103.1 | CEILING | Støvbinding 30 mm, Systemhimling 30 mm |  |  |  |  |  |  |  |  | 6.40012 | Allplan Attributes - Object Layer Attributes #1, Allright_Comp_ID: 0019Csu0779929166/01; Object Layer Attributes #1, Building alteration category: New building; Object Layer Attributes #1, Unit: m²; Object Layer Attributes #1, Layer_number: 1; Object Layer Attributes #1, LayerThickness: 30 mm; Object Layer Attributes #1, Factor: 1; Object Layer Attributes #1, Material: Støvbinding; Object Layer Attributes #1, NOI_UUID: ac553d8b-398e-4058-95c3-ac796ec1c327--779929166; Object Layer Attributes #1, Reference_Height: 0; Object Layer Attributes #1, Delta_Height: 0; Object Layer Attributes #2, Allright_Comp_ID: 0019Csu0779929166/01; Object Layer Attributes #2, Building alteration category: New building; Object Layer Attributes #2, Unit: m²; Object Layer Attributes #2, Layer_number: 2; Object Layer Attributes #2, LayerThickness: 30 mm; Object Layer Attributes #2, Factor: 1; Object Layer Attributes #2, Material: Systemhimling; Object Layer Attributes #2, NOI_UUID: ac553d8b-398e-4058-95c3-ac796ec1c327--779929166; Object Layer Attributes #2, Reference_Height: 0; Object Layer Attributes #2, Delta_Height: 0
 | 104 | FLOORING | Våtromsbelegg 30 mm | 0019Fsu0779929838/01 | New building | m² | 1 | 30 | Våtromsbelegg | ac553d8b-398e-4058-95c3-ac796ec1c327--779929838 | 0 | 2.12994
 | 104 | CEILING | Støvbinding 30 mm, Systemhimling 30 mm |  |  |  |  |  |  |  |  | 2.12994 | Allplan Attributes - Object Layer Attributes #1, Allright_Comp_ID: 0019Csu0779929837/01; Object Layer Attributes #1, Building alteration category: New building; Object Layer Attributes #1, Unit: m²; Object Layer Attributes #1, Layer_number: 1; Object Layer Attributes #1, LayerThickness: 30 mm; Object Layer Attributes #1, Factor: 1; Object Layer Attributes #1, Material: Støvbinding; Object Layer Attributes #1, NOI_UUID: ac553d8b-398e-4058-95c3-ac796ec1c327--779929837; Object Layer Attributes #1, Reference_Height: 0; Object Layer Attributes #1, Delta_Height: 0; Object Layer Attributes #2, Allright_Comp_ID: 0019Csu0779929837/01; Object Layer Attributes #2, Building alteration category: New building; Object Layer Attributes #2, Unit: m²; Object Layer Attributes #2, Layer_number: 2; Object Layer Attributes #2, LayerThickness: 30 mm; Object Layer Attributes #2, Factor: 1; Object Layer Attributes #2, Material: Systemhimling; Object Layer Attributes #2, NOI_UUID: ac553d8b-398e-4058-95c3-ac796ec1c327--779929837; Object Layer Attributes #2, Reference_Height: 0; Object Layer Attributes #2, Delta_Height: 0
 | 106 | CLADDING | Ubehandlet SW 30 mm | 0019Sid0779929068/01 | New building | m² | 1 | 30 | Ubehandlet SW | ac553d8b-398e-4058-95c3-ac796ec1c327--779929068 | 0
 | 106 | FLOORING | Banebelegg, homogent 3 mm | 0019Fsu0779929158/01 | New building | m² | 1 | 3 | Banebelegg, homogent | ac553d8b-398e-4058-95c3-ac796ec1c327--779929158 | 0 | 15.9651
 | 106 | CEILING | Støvbinding 30 mm, Systemhimling 30 mm |  |  |  |  |  |  |  |  | 15.9651 | Allplan Attributes - Object Layer Attributes #1, Allright_Comp_ID: 0019Csu0779929157/01; Object Layer Attributes #1, Building alteration category: New building; Object Layer Attributes #1, Unit: m²; Object Layer Attributes #1, Layer_number: 1; Object Layer Attributes #1, LayerThickness: 30 mm; Object Layer Attributes #1, Factor: 1; Object Layer Attributes #1, Material: Støvbinding; Object Layer Attributes #1, NOI_UUID: ac553d8b-398e-4058-95c3-ac796ec1c327--779929157; Object Layer Attributes #1, Reference_Height: 0; Object Layer Attributes #1, Delta_Height: 0; Object Layer Attributes #2, Allright_Comp_ID: 0019Csu0779929157/01; Object Layer Attributes #2, Building alteration category: New building; Object Layer Attributes #2, Unit: m²; Object Layer Attributes #2, Layer_number: 2; Object Layer Attributes #2, LayerThickness: 30 mm; Object Layer Attributes #2, Factor: 1; Object Layer Attributes #2, Material: Systemhimling; Object Layer Attributes #2, NOI_UUID: ac553d8b-398e-4058-95c3-ac796ec1c327--779929157; Object Layer Attributes #2, Reference_Height: 0; Object Layer Attributes #2, Delta_Height: 0
 | 215 | FLOORING | Våtromsbelegg m oppkant 3 mm | 0029Fsu0780027079/01 | New building | m² | 1 | 3 | Våtromsbelegg m oppkant | ba775db5-6acf-44d4-98dd-11fdd85c2627--780027079 | 0 | 3.11497
 | 215 | CEILING | Systemhimling 30 mm | 0029Csu0780027078/01 | New building | m² | 1 | 30 | Systemhimling | ba775db5-6acf-44d4-98dd-11fdd85c2627--780027078 | 0 | 3.12188
 | 204 | FLOORING | Våtromsbelegg m oppkant 30 mm | 0029Fsu0780027082/01 | New building | m² | 1 | 30 | Våtromsbelegg m oppkant | ba775db5-6acf-44d4-98dd-11fdd85c2627--780027082 | 0 | 1.79705
 | 204 | CEILING | Systemhimling 30 mm | 0029Csu0780027081/01 | New building | m² | 1 | 30 | Systemhimling | ba775db5-6acf-44d4-98dd-11fdd85c2627--780027081 | 0 | 1.80104
 | 203 | FLOORING | Våtromsbelegg m oppkant 30 mm | 0029Fsu0780027085/01 | New building | m² | 1 | 30 | Våtromsbelegg m oppkant | ba775db5-6acf-44d4-98dd-11fdd85c2627--780027085 | 0 | 5.17
 | 203 | CEILING | Systemhimling 30 mm | 0029Csu0780027084/01 | New building | m² | 1 | 30 | Systemhimling | ba775db5-6acf-44d4-98dd-11fdd85c2627--780027084 | 0 | 5.18148
 | 214 | FLOORING | banebelegg acustikk 3 mm | 0029Fsu0780027091/01 | New building | m² | 1 | 3 | banebelegg acustikk | ba775db5-6acf-44d4-98dd-11fdd85c2627--780027091 | 0 | 24.439
 | 214 | CEILING | Systemhimling 30 mm | 0029Csu0780027090/01 | New building | m² | 1 | 30 | Systemhimling | ba775db5-6acf-44d4-98dd-11fdd85c2627--780027090 | 0 | 24.4932
 | 216 | FLOORING | banebelegg acustikk 3 mm | 0029Fsu0780027088/01 | New building | m² | 1 | 3 | banebelegg acustikk | ba775db5-6acf-44d4-98dd-11fdd85c2627--780027088 | 0 | 2.0086
 | 216 | CEILING | Systemhimling 30 mm | 0029Csu0780027087/01 | New building | m² | 1 | 30 | Systemhimling | ba775db5-6acf-44d4-98dd-11fdd85c2627--780027087 | 0 | 2.01306
 | 201 | FLOORING | Golvflis 3 mm | 0029Fsu0780027076/01 | New building | m² | 1 | 3 | Golvflis | ba775db5-6acf-44d4-98dd-11fdd85c2627--780027076 | 0 | 12.1428
 | 201 | CEILING | Systemhimling 30 mm | 0029Csu0780027075/01 | New building | m² | 1 | 30 | Systemhimling | ba775db5-6acf-44d4-98dd-11fdd85c2627--780027075 | 0 | 12.1698
 | 200 | FLOORING | Golvflis 3 mm | 0029Fsu0780027586/01 | New building | m² | 1 | 3 | Golvflis | ba775db5-6acf-44d4-98dd-11fdd85c2627--780027586 | 0 | 11.2379
 | 200 | CEILING | Systemhimling 30 mm | 0029Csu0780027585/01 | New building | m² | 1 | 30 | Systemhimling | ba775db5-6acf-44d4-98dd-11fdd85c2627--780027585 | 0 | 11.2628

# IfcDoor
In: Plan 1
Type - OperationType: SINGLE_SWING_LEFT; ParameterTakesPrecedence: yes; Sizeable: no
OverallHeight: 2100 mm; OverallWidth: 1010 mm

# IfcDoor (4)
Type - OperationType: SINGLE_SWING_RIGHT; ParameterTakesPrecedence: yes; Sizeable: no
OverallHeight: 2100 mm
Name | In | OverallWidth (mm)
 | Plan 1 | 1110
 | Plan 1 | 1010
 | Plan 1 | 900
 | Plan 2 | 900

# IfcDoor: D001
In: Plan 1
Type - OperationType: USERDEFINED; ParameterTakesPrecedence: no; Sizeable: no
OverallHeight: 2100 mm; OverallWidth: 1010 mm
Allplan Attributes - Allright_Comp_ID: 0013Sym0780050284; Unit: Pc; V6: 0; V7: 0; V8: 0; V9: 0; NOI_UUID: d1eb0bd9-ddf6-4315-a806-967de25454b1--780050284

# IfcDoor: D002
In: Plan 1
Type - OperationType: USERDEFINED; ParameterTakesPrecedence: no; Sizeable: no
OverallHeight: 2100 mm; OverallWidth: 1010 mm
Allplan Attributes - Allright_Comp_ID: 0013Sym0780004622; Unit: Pc; V6: 0; V7: 0; V8: 0; V9: 0; NOI_UUID: d1eb0bd9-ddf6-4315-a806-967de25454b1--780004622

# IfcDoor: D003
In: Plan 1
Type - OperationType: USERDEFINED; ParameterTakesPrecedence: no; Sizeable: no
OverallHeight: 2100 mm; OverallWidth: 1110 mm
Allplan Attributes - Allright_Comp_ID: 0013Sym0780004365; Unit: Pc; V6: 0; V7: 0; V8: 0; V9: 0; NOI_UUID: d1eb0bd9-ddf6-4315-a806-967de25454b1--780004365

# IfcDoor: D004
In: Plan 1
Type - OperationType: USERDEFINED; ParameterTakesPrecedence: no; Sizeable: no
OverallHeight: 2100 mm; OverallWidth: 1010 mm
Allplan Attributes - Allright_Comp_ID: 0013Sym0780010214; Unit: Pc; V6: 0; V7: 0; V8: 0; V9: 0; NOI_UUID: d1eb0bd9-ddf6-4315-a806-967de25454b1--780010214

# IfcDoor: D005
In: Plan 1
Type - OperationType: USERDEFINED; ParameterTakesPrecedence: no; Sizeable: no
OverallHeight: 2100 mm; OverallWidth: 1010 mm
Allplan Attributes - Allright_Comp_ID: 0013Sym0780050382; Unit: Pc; V6: 0; V7: 0; V8: 0; V9: 0; NOI_UUID: d1eb0bd9-ddf6-4315-a806-967de25454b1--780050382

# IfcDoor: D006
In: Plan 1
Type - OperationType: USERDEFINED; ParameterTakesPrecedence: no; Sizeable: no
OverallHeight: 2100 mm; OverallWidth: 1010 mm
Allplan Attributes - Allright_Comp_ID: 0014Sym0780027363; Unit: Pc; V6: 0; V7: 0; V8: 0; V9: 0; NOI_UUID: b4870d4d-918a-46e5-81bc-d8f6664cc458--780027363

# IfcDoor: D007
In: Plan 1
Type - OperationType: USERDEFINED; ParameterTakesPrecedence: no; Sizeable: no
OverallHeight: 2100 mm; OverallWidth: 1110 mm
Allplan Attributes - Allright_Comp_ID: 0014Sym0780028148; Unit: Pc; V6: 0; V7: 0; V8: 0; V9: 0; NOI_UUID: b4870d4d-918a-46e5-81bc-d8f6664cc458--780028148

# IfcDoor: D008
In: Plan 1
Type - OperationType: USERDEFINED; ParameterTakesPrecedence: no; Sizeable: no
OverallHeight: 2100 mm; OverallWidth: 1010 mm
Allplan Attributes - Allright_Comp_ID: 0014Sym0780028073; Unit: Pc; V6: 0; V7: 0; V8: 0; V9: 0; NOI_UUID: b4870d4d-918a-46e5-81bc-d8f6664cc458--780028073

# IfcDoor: D009
In: Plan 1
Type - OperationType: USERDEFINED; ParameterTakesPrecedence: no; Sizeable: no
OverallHeight: 2110 mm; OverallWidth: 910 mm
Allplan Attributes - Allright_Comp_ID: 0014Sym0780031590; Unit: Pc; V6: 0; V7: 0; V8: 0; V9: 0; NOI_UUID: b4870d4d-918a-46e5-81bc-d8f6664cc458--780031590

# IfcDoor: D010
In: Plan 1
Type - OperationType: USERDEFINED; ParameterTakesPrecedence: no; Sizeable: no
OverallHeight: 2110 mm; OverallWidth: 910 mm
Allplan Attributes - Allright_Comp_ID: 0014Sym0780031560; Unit: Pc; V6: 0; V7: 0; V8: 0; V9: 0; NOI_UUID: b4870d4d-918a-46e5-81bc-d8f6664cc458--780031560

# IfcDoor: D011
In: Plan 1
Type - OperationType: USERDEFINED; ParameterTakesPrecedence: no; Sizeable: no
OverallHeight: 2100 mm; OverallWidth: 1010 mm
Allplan Attributes - Allright_Comp_ID: 0014Sym0780031532; Unit: Pc; V6: 0; V7: 0; V8: 0; V9: 0; NOI_UUID: b4870d4d-918a-46e5-81bc-d8f6664cc458--780031532

# IfcDoor: D012
In: Plan 1
Type - OperationType: USERDEFINED; ParameterTakesPrecedence: no; Sizeable: no
OverallHeight: 2100 mm; OverallWidth: 1010 mm
Allplan Attributes - Allright_Comp_ID: 0014Sym0780031482; Unit: Pc; V6: 0; V7: 0; V8: 0; V9: 0; NOI_UUID: b4870d4d-918a-46e5-81bc-d8f6664cc458--780031482

# IfcDoor: D013
In: Plan 1
Type - OperationType: USERDEFINED; ParameterTakesPrecedence: no; Sizeable: no
OverallHeight: 2100 mm; OverallWidth: 1005.82 mm
Allplan Attributes - Allright_Comp_ID: 0014Sym0780031161; Unit: Pc; V6: 0; V7: 0; V8: 0; V9: 0; NOI_UUID: b4870d4d-918a-46e5-81bc-d8f6664cc458--780031161

# IfcDoor: D014
In: Plan 1
Type - OperationType: USERDEFINED; ParameterTakesPrecedence: no; Sizeable: no
OverallHeight: 2100 mm; OverallWidth: 910 mm
Allplan Attributes - Allright_Comp_ID: 0014Sym0780031085; Unit: Pc; V6: 0; V7: 0; V8: 0; V9: 0; NOI_UUID: b4870d4d-918a-46e5-81bc-d8f6664cc458--780031085

# IfcDoor: D015
In: Plan 1
Type - OperationType: USERDEFINED; ParameterTakesPrecedence: no; Sizeable: no
OverallHeight: 2110 mm; OverallWidth: 910 mm
Allplan Attributes - Allright_Comp_ID: 0014Sym0780031255; Unit: Pc; V6: 0; V7: 0; V8: 0; V9: 0; NOI_UUID: b4870d4d-918a-46e5-81bc-d8f6664cc458--780031255

# IfcDoor: D016
In: Plan 1
Type - OperationType: USERDEFINED; ParameterTakesPrecedence: no; Sizeable: no
OverallHeight: 2100 mm; OverallWidth: 1010 mm
Allplan Attributes - Allright_Comp_ID: 0014Sym0780028658; Unit: Pc; V6: 0; V7: 0; V8: 0; V9: 0; NOI_UUID: b4870d4d-918a-46e5-81bc-d8f6664cc458--780028658

# IfcDoor: D017
In: Plan 1
Type - OperationType: USERDEFINED; ParameterTakesPrecedence: no; Sizeable: no
OverallHeight: 2110 mm; OverallWidth: 910 mm
Allplan Attributes - Allright_Comp_ID: 0014Sym0780031403; Unit: Pc; V6: 0; V7: 0; V8: 0; V9: 0; NOI_UUID: b4870d4d-918a-46e5-81bc-d8f6664cc458--780031403

# IfcDoor: D018
In: Plan 1
Type - OperationType: USERDEFINED; ParameterTakesPrecedence: no; Sizeable: no
OverallHeight: 2110 mm; OverallWidth: 910 mm
Allplan Attributes - Allright_Comp_ID: 0014Sym0780031431; Unit: Pc; V6: 0; V7: 0; V8: 0; V9: 0; NOI_UUID: b4870d4d-918a-46e5-81bc-d8f6664cc458--780031431

# IfcDoor: D019
In: Plan 1
Type - OperationType: USERDEFINED; ParameterTakesPrecedence: no; Sizeable: no
OverallHeight: 2110 mm; OverallWidth: 1010 mm
Allplan Attributes - Allright_Comp_ID: 0014Sym0780032008; Unit: Pc; V6: 0; V7: 0; V8: 0; V9: 0; NOI_UUID: b4870d4d-918a-46e5-81bc-d8f6664cc458--780032008

# IfcDoor: D020
In: Plan 1
Type - OperationType: USERDEFINED; ParameterTakesPrecedence: no; Sizeable: no
OverallHeight: 2100 mm; OverallWidth: 910 mm
Allplan Attributes - Allright_Comp_ID: 0014Sym0780031011; Unit: Pc; V6: 0; V7: 0; V8: 0; V9: 0; NOI_UUID: b4870d4d-918a-46e5-81bc-d8f6664cc458--780031011

# IfcDoor: D021
In: Plan 1
Type - OperationType: USERDEFINED; ParameterTakesPrecedence: no; Sizeable: no
OverallHeight: 2100 mm; OverallWidth: 1010 mm
Allplan Attributes - Allright_Comp_ID: 0014Sym0780030936; Unit: Pc; V6: 0; V7: 0; V8: 0; V9: 0; NOI_UUID: b4870d4d-918a-46e5-81bc-d8f6664cc458--780030936

# IfcDoor: D022
In: Plan 1
Type - OperationType: USERDEFINED; ParameterTakesPrecedence: no; Sizeable: no
OverallHeight: 2100 mm; OverallWidth: 910 mm
Allplan Attributes - Allright_Comp_ID: 0014Sym0780030839; Unit: Pc; V6: 0; V7: 0; V8: 0; V9: 0; NOI_UUID: b4870d4d-918a-46e5-81bc-d8f6664cc458--780030839

# IfcDoor: D023
In: Plan 1
Type - OperationType: USERDEFINED; ParameterTakesPrecedence: no; Sizeable: no
OverallHeight: 2110 mm; OverallWidth: 1010 mm
Allplan Attributes - Allright_Comp_ID: 0014Sym0780030512; Unit: Pc; V6: 0; V7: 0; V8: 0; V9: 0; NOI_UUID: b4870d4d-918a-46e5-81bc-d8f6664cc458--780030512

# IfcDoor: D024
In: Plan 1
Type - OperationType: USERDEFINED; ParameterTakesPrecedence: no; Sizeable: no
OverallHeight: 2100 mm; OverallWidth: 1010 mm
Allplan Attributes - Allright_Comp_ID: 0014Sym0780030418; Unit: Pc; V6: 0; V7: 0; V8: 0; V9: 0; NOI_UUID: b4870d4d-918a-46e5-81bc-d8f6664cc458--780030418

# IfcDoor: D025
In: Plan 1
Type - OperationType: USERDEFINED; ParameterTakesPrecedence: no; Sizeable: no
OverallHeight: 2100 mm; OverallWidth: 1010 mm
Allplan Attributes - Allright_Comp_ID: 0014Sym0780030376; Unit: Pc; V6: 0; V7: 0; V8: 0; V9: 0; NOI_UUID: b4870d4d-918a-46e5-81bc-d8f6664cc458--780030376

# IfcDoor: D026
In: Plan 1
Type - OperationType: USERDEFINED; ParameterTakesPrecedence: no; Sizeable: no
OverallHeight: 2100 mm; OverallWidth: 1000 mm
Allplan Attributes - Allright_Comp_ID: 0014Sym0780030303; Unit: Pc; V6: 0; V7: 0; V8: 0; V9: 0; NOI_UUID: b4870d4d-918a-46e5-81bc-d8f6664cc458--780030303

# IfcDoor: D027
In: Plan 1
Type - OperationType: USERDEFINED; ParameterTakesPrecedence: no; Sizeable: no
OverallHeight: 2110 mm; OverallWidth: 910 mm
Allplan Attributes - Allright_Comp_ID: 0014Sym0780030208; Unit: Pc; V6: 0; V7: 0; V8: 0; V9: 0; NOI_UUID: b4870d4d-918a-46e5-81bc-d8f6664cc458--780030208

# IfcDoor: D028
In: Plan 1
Type - OperationType: USERDEFINED; ParameterTakesPrecedence: no; Sizeable: no
OverallHeight: 2100 mm; OverallWidth: 1010 mm
Allplan Attributes - Allright_Comp_ID: 0014Sym0780029527; Unit: Pc; V6: 0; V7: 0; V8: 0; V9: 0; NOI_UUID: b4870d4d-918a-46e5-81bc-d8f6664cc458--780029527

# IfcDoor: D029
In: Plan 1
Type - OperationType: USERDEFINED; ParameterTakesPrecedence: no; Sizeable: no
OverallHeight: 2110 mm; OverallWidth: 910 mm
Allplan Attributes - Allright_Comp_ID: 0014Sym0780030766; Unit: Pc; V6: 0; V7: 0; V8: 0; V9: 0; NOI_UUID: b4870d4d-918a-46e5-81bc-d8f6664cc458--780030766

# IfcDoor: D030
In: Plan 1
Type - OperationType: USERDEFINED; ParameterTakesPrecedence: no; Sizeable: no
OverallHeight: 2110 mm; OverallWidth: 1010 mm
Allplan Attributes - Allright_Comp_ID: 0014Sym0780028772; Unit: Pc; V6: 0; V7: 0; V8: 0; V9: 0; Name: D030; NOI_UUID: b4870d4d-918a-46e5-81bc-d8f6664cc458--780028772

# IfcDoor: D101
In: Plan 2
Type - OperationType: USERDEFINED; ParameterTakesPrecedence: no; Sizeable: no
OverallHeight: 2110 mm; OverallWidth: 1010 mm
Allplan Attributes - Allright_Comp_ID: 0024Sym0780027785; Unit: Pc; V6: 0; V7: 0; V8: 0; V9: 0; Release: 3.0; Name: D101; Plugin_name: MainObject; Plugin_object_name: SmartPartCompressed; GlazingAreaFraction_Consider: 0; NOI_UUID: ffc0a4b9-6ff1-450c-9901-90887e5cf058--780027785; IFC Object type: IfcDoor; Version: 5.0; Glass surface: 0; Height_window_sill_outside: 0; Height_window_sill_inside: 0; Offset_opening_bottom: 0; Offset_opening_top: 20; Offset_opening_left: 10; Offset_opening_right: 10; Deduction_opening_bottom: 25; Deduction_opening_left: 60; Deduction_opening_right: 60; Deduction_opening_top: 70

# IfcDoor: D102
In: Plan 2
Type - OperationType: USERDEFINED; ParameterTakesPrecedence: no; Sizeable: no
OverallHeight: 2110 mm; OverallWidth: 1010 mm
Allplan Attributes - Allright_Comp_ID: 0024Sym0780027841; Unit: Pc; V6: 0; V7: 0; V8: 0; V9: 0; Release: 3.0; Name: D102; Plugin_name: MainObject; Plugin_object_name: SmartPartCompressed; GlazingAreaFraction_Consider: 0; NOI_UUID: ffc0a4b9-6ff1-450c-9901-90887e5cf058--780027841; IFC Object type: IfcDoor; Version: 5.0; Glass surface: 0; Height_window_sill_outside: 0; Height_window_sill_inside: 0; Offset_opening_bottom: 0; Offset_opening_top: 20; Offset_opening_left: 10; Offset_opening_right: 10; Deduction_opening_bottom: 25; Deduction_opening_left: 60; Deduction_opening_right: 60; Deduction_opening_top: 70

# IfcDoor: D103
In: Plan 2
Type - OperationType: USERDEFINED; ParameterTakesPrecedence: no; Sizeable: no
OverallHeight: 2110 mm; OverallWidth: 1010 mm
Allplan Attributes - Allright_Comp_ID: 0024Sym0780027892; Unit: Pc; V6: 0; V7: 0; V8: 0; V9: 0; Release: 3.0; Name: D103; Plugin_name: MainObject; Plugin_object_name: SmartPartCompressed; GlazingAreaFraction_Consider: 0; NOI_UUID: ffc0a4b9-6ff1-450c-9901-90887e5cf058--780027892; IFC Object type: IfcDoor; Version: 5.0; Glass surface: 0; Height_window_sill_outside: 0; Height_window_sill_inside: 0; Offset_opening_bottom: 0; Offset_opening_top: 20; Offset_opening_left: 10; Offset_opening_right: 10; Deduction_opening_bottom: 25; Deduction_opening_left: 60; Deduction_opening_right: 60; Deduction_opening_top: 70

# IfcDoor: D104
In: Plan 2
Type - OperationType: USERDEFINED; ParameterTakesPrecedence: no; Sizeable: no
OverallHeight: 2110 mm; OverallWidth: 900 mm
Allplan Attributes - Allright_Comp_ID: 0024Sym0780027956; Unit: Pc; V6: 0; V7: 0; V8: 0; V9: 0; Release: 3.0; Name: D104; Plugin_name: MainObject; Plugin_object_name: SmartPartCompressed; GlazingAreaFraction_Consider: 0; NOI_UUID: ffc0a4b9-6ff1-450c-9901-90887e5cf058--780027956; IFC Object type: IfcDoor; Version: 5.0; Glass surface: 0; Height_window_sill_outside: 0; Height_window_sill_inside: 0; Offset_opening_bottom: 0; Offset_opening_top: 20; Offset_opening_left: 10; Offset_opening_right: 10; Deduction_opening_bottom: 25; Deduction_opening_left: 60; Deduction_opening_right: 60; Deduction_opening_top: 70

# IfcDoor: D105
In: Plan 2
Type - OperationType: USERDEFINED; ParameterTakesPrecedence: no; Sizeable: no
OverallHeight: 2110 mm; OverallWidth: 1110 mm
Allplan Attributes - Allright_Comp_ID: 0024Sym0780028160; Unit: Pc; V6: 0; V7: 0; V8: 0; V9: 0; Release: 3.0; Name: D105; Plugin_name: MainObject; Plugin_object_name: SmartPartCompressed; GlazingAreaFraction_Consider: 0; NOI_UUID: ffc0a4b9-6ff1-450c-9901-90887e5cf058--780028160; IFC Object type: IfcDoor; Version: 5.0; Glass surface: 1.3104; Height_window_sill_outside: 0; Height_window_sill_inside: 0; Offset_opening_bottom: 0; Offset_opening_top: 20; Offset_opening_left: 10; Offset_opening_right: 10; Deduction_opening_bottom: 25; Deduction_opening_left: 60; Deduction_opening_right: 60; Deduction_opening_top: 70

# IfcDoor: D106
In: Plan 2
Type - OperationType: USERDEFINED; ParameterTakesPrecedence: no; Sizeable: no
OverallHeight: 2110 mm; OverallWidth: 1010 mm
Allplan Attributes - Allright_Comp_ID: 0024Sym0780028200; Unit: Pc; V6: 0; V7: 0; V8: 0; V9: 0; Release: 3.0; Name: D106; Plugin_name: MainObject; Plugin_object_name: SmartPartCompressed; GlazingAreaFraction_Consider: 0; NOI_UUID: ffc0a4b9-6ff1-450c-9901-90887e5cf058--780028200; IFC Object type: IfcDoor; Version: 5.0; Glass surface: 1.1424; Height_window_sill_outside: 0; Height_window_sill_inside: 0; Offset_opening_bottom: 0; Offset_opening_top: 20; Offset_opening_left: 10; Offset_opening_right: 10; Deduction_opening_bottom: 25; Deduction_opening_left: 60; Deduction_opening_right: 60; Deduction_opening_top: 70

# IfcDoor: D107
In: Plan 2
Type - OperationType: USERDEFINED; ParameterTakesPrecedence: no; Sizeable: no
OverallHeight: 2110 mm; OverallWidth: 1010 mm
Allplan Attributes - Allright_Comp_ID: 0024Sym0780028286; Unit: Pc; V6: 0; V7: 0; V8: 0; V9: 0; Release: 3.0; Name: D107; Plugin_name: MainObject; Plugin_object_name: SmartPartCompressed; GlazingAreaFraction_Consider: 0; NOI_UUID: ffc0a4b9-6ff1-450c-9901-90887e5cf058--780028286; IFC Object type: IfcDoor; Version: 5.0; Glass surface: 1.1424; Height_window_sill_outside: 0; Height_window_sill_inside: 0; Offset_opening_bottom: 0; Offset_opening_top: 20; Offset_opening_left: 10; Offset_opening_right: 10; Deduction_opening_bottom: 25; Deduction_opening_left: 60; Deduction_opening_right: 60; Deduction_opening_top: 70

# IfcDoor: D108
In: Plan 2
Type - OperationType: USERDEFINED; ParameterTakesPrecedence: no; Sizeable: no
OverallHeight: 2110 mm; OverallWidth: 1010 mm
Allplan Attributes - Allright_Comp_ID: 0024Sym0780028348; Unit: Pc; V6: 0; V7: 0; V8: 0; V9: 0; Release: 3.0; Name: D108; Plugin_name: MainObject; Plugin_object_name: SmartPartCompressed; GlazingAreaFraction_Consider: 0; NOI_UUID: ffc0a4b9-6ff1-450c-9901-90887e5cf058--780028348; IFC Object type: IfcDoor; Version: 5.0; Glass surface: 1.1424; Height_window_sill_outside: 0; Height_window_sill_inside: 0; Offset_opening_bottom: 0; Offset_opening_top: 20; Offset_opening_left: 10; Offset_opening_right: 10; Deduction_opening_bottom: 25; Deduction_opening_left: 60; Deduction_opening_right: 60; Deduction_opening_top: 70

# IfcDoor: D109
In: Plan 2
Type - OperationType: USERDEFINED; ParameterTakesPrecedence: no; Sizeable: no
OverallHeight: 2110 mm; OverallWidth: 1010 mm
Allplan Attributes - Allright_Comp_ID: 0024Sym0780028377; Unit: Pc; V6: 0; V7: 0; V8: 0; V9: 0; Release: 3.0; Name: D109; Plugin_name: MainObject; Plugin_object_name: SmartPartCompressed; GlazingAreaFraction_Consider: 0; NOI_UUID: ffc0a4b9-6ff1-450c-9901-90887e5cf058--780028377; IFC Object type: IfcDoor; Version: 5.0; Glass surface: 1.1424; Height_window_sill_outside: 0; Height_window_sill_inside: 0; Offset_opening_bottom: 0; Offset_opening_top: 20; Offset_opening_left: 10; Offset_opening_right: 10; Deduction_opening_bottom: 25; Deduction_opening_left: 60; Deduction_opening_right: 60; Deduction_opening_top: 70

# IfcDoor: D110
In: Plan 2
Type - OperationType: USERDEFINED; ParameterTakesPrecedence: no; Sizeable: no
OverallHeight: 2110 mm; OverallWidth: 1010 mm
Allplan Attributes - Allright_Comp_ID: 0024Sym0780028403; Unit: Pc; V6: 0; V7: 0; V8: 0; V9: 0; Release: 3.0; Name: D110; Plugin_name: MainObject; Plugin_object_name: SmartPartCompressed; GlazingAreaFraction_Consider: 0; NOI_UUID: ffc0a4b9-6ff1-450c-9901-90887e5cf058--780028403; IFC Object type: IfcDoor; Version: 5.0; Glass surface: 1.1424; Height_window_sill_outside: 0; Height_window_sill_inside: 0; Offset_opening_bottom: 0; Offset_opening_top: 20; Offset_opening_left: 10; Offset_opening_right: 10; Deduction_opening_bottom: 25; Deduction_opening_left: 60; Deduction_opening_right: 60; Deduction_opening_top: 70

# IfcDoor: D111
In: Plan 2
Type - OperationType: USERDEFINED; ParameterTakesPrecedence: no; Sizeable: no
OverallHeight: 2110 mm; OverallWidth: 1010 mm
Allplan Attributes - Allright_Comp_ID: 0024Sym0780028429; Unit: Pc; V6: 0; V7: 0; V8: 0; V9: 0; Release: 3.0; Name: D111; Plugin_name: MainObject; Plugin_object_name: SmartPartCompressed; GlazingAreaFraction_Consider: 0; NOI_UUID: ffc0a4b9-6ff1-450c-9901-90887e5cf058--780028429; IFC Object type: IfcDoor; Version: 5.0; Glass surface: 1.1424; Height_window_sill_outside: 0; Height_window_sill_inside: 0; Offset_opening_bottom: 0; Offset_opening_top: 20; Offset_opening_left: 10; Offset_opening_right: 10; Deduction_opening_bottom: 25; Deduction_opening_left: 60; Deduction_opening_right: 60; Deduction_opening_top: 70

# IfcDoor: D112
In: Plan 2
Type - OperationType: USERDEFINED; ParameterTakesPrecedence: no; Sizeable: no
OverallHeight: 2110 mm; OverallWidth: 1010 mm
Allplan Attributes - Allright_Comp_ID: 0024Sym0780028455; Unit: Pc; V6: 0; V7: 0; V8: 0; V9: 0; Release: 3.0; Name: D112; Plugin_name: MainObject; Plugin_object_name: SmartPartCompressed; GlazingAreaFraction_Consider: 0; NOI_UUID: ffc0a4b9-6ff1-450c-9901-90887e5cf058--780028455; IFC Object type: IfcDoor; Version: 5.0; Glass surface: 1.1424; Height_window_sill_outside: 0; Height_window_sill_inside: 0; Offset_opening_bottom: 0; Offset_opening_top: 20; Offset_opening_left: 10; Offset_opening_right: 10; Deduction_opening_bottom: 25; Deduction_opening_left: 60; Deduction_opening_right: 60; Deduction_opening_top: 70

# IfcDoor: D113
In: Plan 2
Type - OperationType: USERDEFINED; ParameterTakesPrecedence: no; Sizeable: no
OverallHeight: 2110 mm; OverallWidth: 1010 mm
Allplan Attributes - Allright_Comp_ID: 0024Sym0780028481; Unit: Pc; V6: 0; V7: 0; V8: 0; V9: 0; Release: 3.0; Name: D113; Plugin_name: MainObject; Plugin_object_name: SmartPartCompressed; GlazingAreaFraction_Consider: 0; NOI_UUID: ffc0a4b9-6ff1-450c-9901-90887e5cf058--780028481; IFC Object type: IfcDoor; Version: 5.0; Glass surface: 1.1424; Height_window_sill_outside: 0; Height_window_sill_inside: 0; Offset_opening_bottom: 0; Offset_opening_top: 20; Offset_opening_left: 10; Offset_opening_right: 10; Deduction_opening_bottom: 25; Deduction_opening_left: 60; Deduction_opening_right: 60; Deduction_opening_top: 70

# IfcDoor: D114
In: Plan 2
Type - OperationType: USERDEFINED; ParameterTakesPrecedence: no; Sizeable: no
OverallHeight: 2110 mm; OverallWidth: 1010 mm
Allplan Attributes - Allright_Comp_ID: 0024Sym0780028507; Unit: Pc; V6: 0; V7: 0; V8: 0; V9: 0; Release: 3.0; Name: D114; Plugin_name: MainObject; Plugin_object_name: SmartPartCompressed; GlazingAreaFraction_Consider: 0; NOI_UUID: ffc0a4b9-6ff1-450c-9901-90887e5cf058--780028507; IFC Object type: IfcDoor; Version: 5.0; Glass surface: 1.1424; Height_window_sill_outside: 0; Height_window_sill_inside: 0; Offset_opening_bottom: 0; Offset_opening_top: 20; Offset_opening_left: 10; Offset_opening_right: 10; Deduction_opening_bottom: 25; Deduction_opening_left: 60; Deduction_opening_right: 60; Deduction_opening_top: 70

# IfcDoor: D115
In: Plan 2
Type - OperationType: USERDEFINED; ParameterTakesPrecedence: no; Sizeable: no
OverallHeight: 2110 mm; OverallWidth: 1010 mm
Allplan Attributes - Allright_Comp_ID: 0024Sym0780028533; Unit: Pc; V6: 0; V7: 0; V8: 0; V9: 0; Release: 3.0; Name: D115; Plugin_name: MainObject; Plugin_object_name: SmartPartCompressed; GlazingAreaFraction_Consider: 0; NOI_UUID: ffc0a4b9-6ff1-450c-9901-90887e5cf058--780028533; IFC Object type: IfcDoor; Version: 5.0; Glass surface: 0; Height_window_sill_outside: 0; Height_window_sill_inside: 0; Offset_opening_bottom: 0; Offset_opening_top: 20; Offset_opening_left: 10; Offset_opening_right: 10; Deduction_opening_bottom: 25; Deduction_opening_left: 60; Deduction_opening_right: 60; Deduction_opening_top: 70

# IfcOpeningElement: Opening (99)
Name | In | Length (m) | Height (m) | GrossVolume (m3) | NominalArea (m2) | Object Layer Attributes #1, Allright_Comp_ID | Object Layer Attributes #1, Building alteration category | Object Layer Attributes #1, Unit | Object Layer Attributes #1, NOI_UUID | Object Layer Attributes #2, Allright_Comp_ID | Object Layer Attributes #2, Building alteration category | Object Layer Attributes #2, Unit | Object Layer Attributes #2, NOI_UUID | Object Layer Attributes #3, Allright_Comp_ID | Object Layer Attributes #3, Building alteration category | Object Layer Attributes #3, Unit | Object Layer Attributes #3, NOI_UUID
Slab Opening | Konstruksjoner i grunnen | 0.75 | 0.15 | -0.135 | -0.9 | 0005SBr0779998925 | New building | m³ | dea4e5d4-67a8-4f71-a690-1e4c8fd9c290--779998925
Slab Opening | Konstruksjoner i grunnen | 0.75 | 0.15 | -0.135 | -0.9 | 0005SBr0779999088 | New building | m³ | dea4e5d4-67a8-4f71-a690-1e4c8fd9c290--779999088
D001 | Plan 1 | 1.01 | 2.1 | -0.4242 | -2.121 | 0013Dor0779998509 | New building | m² | d1eb0bd9-ddf6-4315-a806-967de25454b1--779998509 | Allplan Attributes - Object Layer Attributes #1, Name: D001; Object Layer Attributes #1, Material: Utsparring D/V
D005 | Plan 1 | 1.01 | 2.1 | -0.4242 | -2.121 | 0013Dor0780000815 | New building | m² | d1eb0bd9-ddf6-4315-a806-967de25454b1--780000815 | Allplan Attributes - Object Layer Attributes #1, Name: D005; Object Layer Attributes #1, Material: Utsparring D/V
Por01 | Plan 1 | 2.8 | 2.8 | -1.568 | -7.84 | 0013Dor0779971084 |  | m² | d1eb0bd9-ddf6-4315-a806-967de25454b1--779971084 | Allplan Attributes - Object Layer Attributes #1, Name: Por01
Port02 | Plan 1 | 2.8 | 2.8 | -1.568 | -7.84 | 0013Dor0779971100 |  | m² | d1eb0bd9-ddf6-4315-a806-967de25454b1--779971100 | Allplan Attributes - Object Layer Attributes #1, Name: Port02
V013 | Plan 1 | 1.11 | 2.41 | -0.53502 | -2.6751 | 0013Win0779994914 | New building | m² | d1eb0bd9-ddf6-4315-a806-967de25454b1--779994914 | Allplan Attributes - Object Layer Attributes #1, Name: V013; Object Layer Attributes #1, Material: Utsparring D/V
D003 | Plan 1 | 1.11 | 2.1 | -0.4662 | -2.331 | 0013Dor0779968902 | New building | m² | d1eb0bd9-ddf6-4315-a806-967de25454b1--779968902 | Allplan Attributes - Object Layer Attributes #1, Name: D003; Object Layer Attributes #1, Material: Utsparring D/V
V005 | Plan 1 | 1.71 | 7.71 | -0.37962 | -1.8981 | 0013Win0779969598 | New building | m² | d1eb0bd9-ddf6-4315-a806-967de25454b1--779969598 | Allplan Attributes - Object Layer Attributes #1, Material: Utsparring D/V
Door opening | Plan 1 | 1.11 | 2.1 | -0.107226 | -2.331 | 0013Dor0779992938 | New building | m² | d1eb0bd9-ddf6-4315-a806-967de25454b1--779992938 | 0013Dor0779992937 | New building | m² | d1eb0bd9-ddf6-4315-a806-967de25454b1--779992937 | Allplan Attributes - Object Layer Attributes #1, Material: Utsparring D/V; Object Layer Attributes #2, Trade: Ext. insulation finish systems; Object Layer Attributes #2, Material: Utsparring D/V
Door opening | Plan 1 | 1.01 | 2.1 | -0.097566 | -2.121 | 0013Dor0779993178 | New building | m² | d1eb0bd9-ddf6-4315-a806-967de25454b1--779993178 | 0013Dor0779993177 | New building | m² | d1eb0bd9-ddf6-4315-a806-967de25454b1--779993177 | Allplan Attributes - Object Layer Attributes #1, Material: Utsparring D/V; Object Layer Attributes #2, Trade: Ext. insulation finish systems; Object Layer Attributes #2, Material: Utsparring D/V
Window opening | Plan 1 | 0.61 | 7.71 | -0.13542 | -0.6771 | 0013Win0779971248 | New building | m² | d1eb0bd9-ddf6-4315-a806-967de25454b1--779971248 | Allplan Attributes - Object Layer Attributes #1, Material: Utsparring D/V
Window opening | Plan 1 | 0.61 | 7.71 | -0.13542 | -0.6771 | 0013Win0779971236 | New building | m² | d1eb0bd9-ddf6-4315-a806-967de25454b1--779971236 | Allplan Attributes - Object Layer Attributes #1, Material: Utsparring D/V
V008 | Plan 1 | 0.61 | 7.71 | -0.13542 | -0.6771 | 0013Win0779993523 | New building | m² | d1eb0bd9-ddf6-4315-a806-967de25454b1--779993523 | Allplan Attributes - Object Layer Attributes #1, Material: Utsparring D/V
D004 | Plan 1 | 1.01 | 2.1 | -0.4242 | -2.121 | 0013Dor0779971221 | New building | m² | d1eb0bd9-ddf6-4315-a806-967de25454b1--779971221 | Allplan Attributes - Object Layer Attributes #1, Material: Utsparring D/V
Door opening | Plan 1 | 1.01 | 2.1 | -0.097566 | -2.121 | 0013Dor0779992986 | New building | m² | d1eb0bd9-ddf6-4315-a806-967de25454b1--779992986 | 0013Dor0779992985 | New building | m² | d1eb0bd9-ddf6-4315-a806-967de25454b1--779992985 | Allplan Attributes - Object Layer Attributes #1, Material: Utsparring D/V; Object Layer Attributes #2, Trade: Ext. insulation finish systems; Object Layer Attributes #2, Material: Utsparring D/V
V003 | Plan 1 | 1.11 | 2.41 | -0.53502 | -2.6751 | 0013Win0779969374 | New building | m² | d1eb0bd9-ddf6-4315-a806-967de25454b1--779969374 | Allplan Attributes - Object Layer Attributes #1, Material: Utsparring D/V
V001 | Plan 1 | 0.61 | 7.71 | -0.13542 | -0.6771 | 0013Win0779970746 | New building | m² | d1eb0bd9-ddf6-4315-a806-967de25454b1--779970746 | Allplan Attributes - Object Layer Attributes #1, Material: Utsparring D/V
Port03 | Plan 1 | 2.8 | 2.8 | -1.568 | -7.84 | 0013Dor0779969143 | New building | m² | d1eb0bd9-ddf6-4315-a806-967de25454b1--779969143 | Allplan Attributes - Object Layer Attributes #1, Name: Port03; Object Layer Attributes #1, Material: Utsparring D/V
D002 | Plan 1 | 1.01 | 2.1 | -0.4242 | -2.121 | 0013Dor0779968942 | New building | m² | d1eb0bd9-ddf6-4315-a806-967de25454b1--779968942 | Allplan Attributes - Object Layer Attributes #1, Name: D002; Object Layer Attributes #1, Material: Utsparring D/V
V002 | Plan 1 | 2.41 | 2.41 | -1.16162 | -5.8081 | 0013Win0779969444 | New building | m² | d1eb0bd9-ddf6-4315-a806-967de25454b1--779969444 | Allplan Attributes - Object Layer Attributes #1, Material: Utsparring D/V
D006 | Plan 1 | 1.01 | 2.1 | -0.027573 | -2.121 | 0014Dor0779983015 | New building | m³ | b4870d4d-918a-46e5-81bc-d8f6664cc458--779983015 | 0014Dor0779983016 | New building | m³ | b4870d4d-918a-46e5-81bc-d8f6664cc458--779983016 | 0014Dor0779983017 | New building | m³ | b4870d4d-918a-46e5-81bc-d8f6664cc458--779983017 | Allplan Attributes - Object Layer Attributes #1, Name: D006; Object Layer Attributes #1, Material: Utsparring D/V; Object Layer Attributes #2, Material: Utsparring D/V; Object Layer Attributes #3, Material: Utsparring D/V
garasjeport med glassfelter:45x6 | Plan 1 | 1.01 | 2.1 | -0.027573 | -2.121 | 0014Dor0779974170 | New building | m³ | b4870d4d-918a-46e5-81bc-d8f6664cc458--779974170 | 0014Dor0779974171 | New building | m³ | b4870d4d-918a-46e5-81bc-d8f6664cc458--779974171 | 0014Dor0779974172 | New building | m³ | b4870d4d-918a-46e5-81bc-d8f6664cc458--779974172 | Allplan Attributes - Object Layer Attributes #1, Material: Utsparring D/V; Object Layer Attributes #2, Material: Utsparring D/V; Object Layer Attributes #3, Material: Utsparring D/V; Object Layer Attributes #2, Name: D012
D008 | Plan 1 | 1.01 | 2.1 | -0.027573 | -2.121 | 0014Dor0779978959 | New building | m³ | b4870d4d-918a-46e5-81bc-d8f6664cc458--779978959 | 0014Dor0779978960 | New building | m³ | b4870d4d-918a-46e5-81bc-d8f6664cc458--779978960 | 0014Dor0779978961 | New building | m³ | b4870d4d-918a-46e5-81bc-d8f6664cc458--779978961 | Allplan Attributes - Object Layer Attributes #1, Name: D008; Object Layer Attributes #1, Material: Utsparring D/V; Object Layer Attributes #2, Material: Utsparring D/V; Object Layer Attributes #3, Material: Utsparring D/V
Door opening | Plan 1 | 1.11 | 2.1 | -0.030303 | -2.331 | 0014Dor0779978564 | New building | m³ | b4870d4d-918a-46e5-81bc-d8f6664cc458--779978564 | 0014Dor0779978565 | New building | m³ | b4870d4d-918a-46e5-81bc-d8f6664cc458--779978565 | 0014Dor0779978566 | New building | m³ | b4870d4d-918a-46e5-81bc-d8f6664cc458--779978566 | Allplan Attributes - Object Layer Attributes #1, Material: Utsparring D/V; Object Layer Attributes #2, Material: Utsparring D/V; Object Layer Attributes #3, Material: Utsparring D/V
D009 | Plan 1 | 0.91 | 2.11 | -0.0249613 | -1.9201 | 0014Dor0779996493 | New building | m³ | b4870d4d-918a-46e5-81bc-d8f6664cc458--779996493 | 0014Dor0779996494 | New building | m³ | b4870d4d-918a-46e5-81bc-d8f6664cc458--779996494 | 0014Dor0779996495 | New building | m³ | b4870d4d-918a-46e5-81bc-d8f6664cc458--779996495 | Allplan Attributes - Object Layer Attributes #1, Name: D009; Object Layer Attributes #1, Material: Utsparring D/V; Object Layer Attributes #2, Material: Utsparring D/V; Object Layer Attributes #3, Material: Utsparring D/V
garasjeport med glassfelter:45x6 | Plan 1 | 1.01 | 2.1 | -0.027573 | -2.121 | 0014Dor0779978382 | New building | m² | b4870d4d-918a-46e5-81bc-d8f6664cc458--779978382 | 0014Dor0779978381 | New building | m² | b4870d4d-918a-46e5-81bc-d8f6664cc458--779978381 | 0014Dor0779978380 | New building | m² | b4870d4d-918a-46e5-81bc-d8f6664cc458--779978380 | Allplan Attributes - Object Layer Attributes #1, Material: Utsparring D/V; Object Layer Attributes #2, Material: Utsparring D/V; Object Layer Attributes #3, Material: Utsparring D/V; Object Layer Attributes #3, Name: D011
D010 | Plan 1 | 0.91 | 2.11 | -0.0249613 | -1.9201 | 0014Dor0779978403 | New building | m² | b4870d4d-918a-46e5-81bc-d8f6664cc458--779978403 | 0014Dor0779978402 | New building | m² | b4870d4d-918a-46e5-81bc-d8f6664cc458--779978402 | 0014Dor0779978401 | New building | m² | b4870d4d-918a-46e5-81bc-d8f6664cc458--779978401 | Allplan Attributes - Object Layer Attributes #1, Name: D010; Object Layer Attributes #1, Material: Utsparring D/V; Object Layer Attributes #2, Material: Utsparring D/V; Object Layer Attributes #3, Material: Utsparring D/V
D014 | Plan 1 | 0.91 | 2.1 | -0.024843 | -1.911 | 0014Dor0780002129 | New building | m² | b4870d4d-918a-46e5-81bc-d8f6664cc458--780002129 | 0014Dor0780002128 | New building | m² | b4870d4d-918a-46e5-81bc-d8f6664cc458--780002128 | 0014Dor0780002127 | New building | m² | b4870d4d-918a-46e5-81bc-d8f6664cc458--780002127 | Allplan Attributes - Object Layer Attributes #1, Name: D014; Object Layer Attributes #1, Material: Utsparring D/V; Object Layer Attributes #2, Material: Utsparring D/V; Object Layer Attributes #3, Material: Utsparring D/V
D013 | Plan 1 | 1.00582 | 2.1 | -0.0304449 | -2.11223 | 0014Dor0779979756 | New building | m² | b4870d4d-918a-46e5-81bc-d8f6664cc458--779979756 | 0014Dor0779979754 | New building | m² | b4870d4d-918a-46e5-81bc-d8f6664cc458--779979754 | 0014Dor0779979752 | New building | m² | b4870d4d-918a-46e5-81bc-d8f6664cc458--779979752 | Allplan Attributes - Object Layer Attributes #1, Name: D013; Object Layer Attributes #1, Material: Utsparring D/V; Object Layer Attributes #2, Material: Utsparring D/V; Object Layer Attributes #3, Material: Utsparring D/V
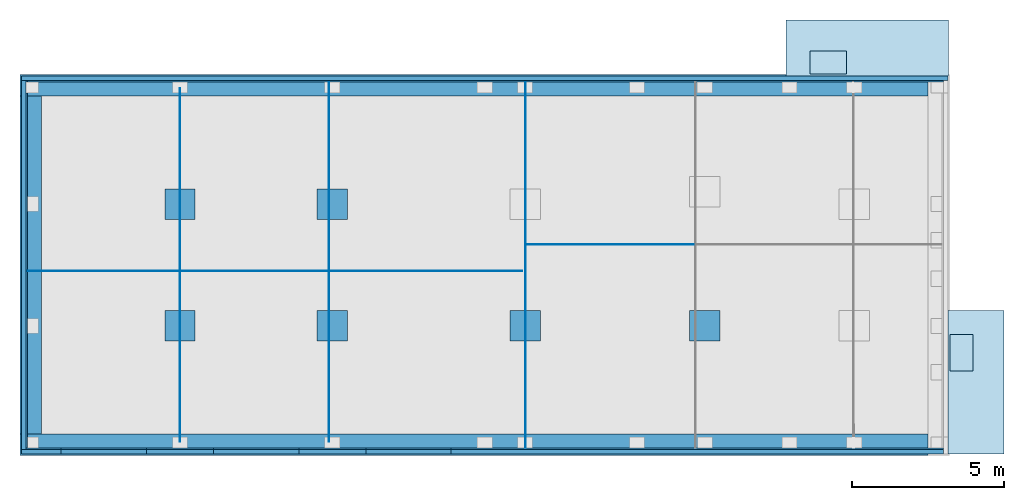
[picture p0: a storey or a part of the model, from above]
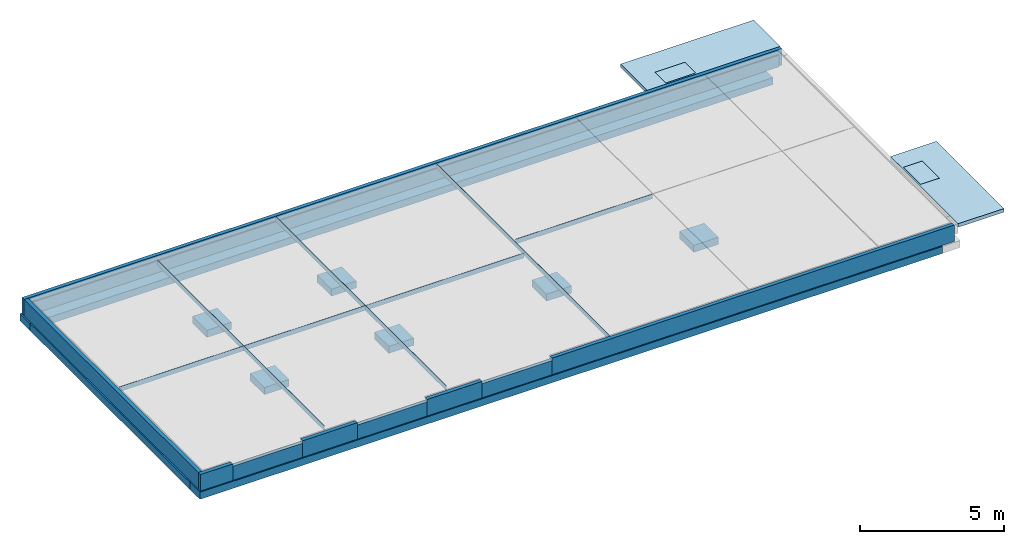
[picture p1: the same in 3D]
Properties of the parts of a building model (IFC2X3), part 5 of 7

# IfcOpeningElement: Opening (99)
Name | In | Length (m) | Height (m) | GrossVolume (m3) | NominalArea (m2) | Object Layer Attributes #1, Allright_Comp_ID | Object Layer Attributes #1, Building alteration category | Object Layer Attributes #1, Unit | Object Layer Attributes #1, NOI_UUID | Object Layer Attributes #2, Allright_Comp_ID | Object Layer Attributes #2, Building alteration category | Object Layer Attributes #2, Unit | Object Layer Attributes #2, NOI_UUID | Object Layer Attributes #3, Allright_Comp_ID | Object Layer Attributes #3, Building alteration category | Object Layer Attributes #3, Unit | Object Layer Attributes #3, NOI_UUID
D016 | Plan 1 | 1.01 | 2.1 | -0.027573 | -2.121 | 0014Dor0779979870 | New building | m² | b4870d4d-918a-46e5-81bc-d8f6664cc458--779979870 | 0014Dor0779979868 | New building | m² | b4870d4d-918a-46e5-81bc-d8f6664cc458--779979868 | 0014Dor0779979866 | New building | m² | b4870d4d-918a-46e5-81bc-d8f6664cc458--779979866 | Allplan Attributes - Object Layer Attributes #1, Name: D016; Object Layer Attributes #1, Material: Utsparring D/V; Object Layer Attributes #2, Material: Utsparring D/V; Object Layer Attributes #3, Material: Utsparring D/V; Object Layer Attributes #3, Name: D016
D026 | Plan 1 | 1 | 2.1 | -0.0273 | -2.1 | 0014Dor0779970392 |  | m³ | b4870d4d-918a-46e5-81bc-d8f6664cc458--779970392 | 0014Dor0779970391 | New building | m³ | b4870d4d-918a-46e5-81bc-d8f6664cc458--779970391 | 0014Dor0779970390 | New building | m³ | b4870d4d-918a-46e5-81bc-d8f6664cc458--779970390 | Allplan Attributes - Object Layer Attributes #1, Name: D026; Object Layer Attributes #2, Material: Utsparring D/V; Object Layer Attributes #3, Material: Utsparring D/V
Door opening | Plan 1 | 0.91 | 2.11 | -0.0249613 | -1.9201 | 0014Dor0779971978 | New building | m² | b4870d4d-918a-46e5-81bc-d8f6664cc458--779971978 | 0014Dor0779971979 | New building | m² | b4870d4d-918a-46e5-81bc-d8f6664cc458--779971979 | 0014Dor0779971980 | New building | m² | b4870d4d-918a-46e5-81bc-d8f6664cc458--779971980 | Allplan Attributes - Object Layer Attributes #1, Material: Utsparring D/V; Object Layer Attributes #2, Material: Utsparring D/V; Object Layer Attributes #3, Material: Utsparring D/V; Object Layer Attributes #3, Name: D029
Door opening | Plan 1 | 1.01 | 2.11 | -0.0277043 | -2.1311 | 0014Dor0779971957 | New building | m³ | b4870d4d-918a-46e5-81bc-d8f6664cc458--779971957 | 0014Dor0779971956 | New building | m³ | b4870d4d-918a-46e5-81bc-d8f6664cc458--779971956 | 0014Dor0779971955 | New building | m³ | b4870d4d-918a-46e5-81bc-d8f6664cc458--779971955 | Allplan Attributes - Object Layer Attributes #1, Material: Utsparring D/V; Object Layer Attributes #2, Material: Utsparring D/V; Object Layer Attributes #3, Material: Utsparring D/V; Object Layer Attributes #3, Name: D023
D015 | Plan 1 | 0.91 | 2.1 | -0.024843 | -1.911 | 0014Dor0780021625 | New building | m³ | b4870d4d-918a-46e5-81bc-d8f6664cc458--780021625 | 0014Dor0780021624 | New building | m³ | b4870d4d-918a-46e5-81bc-d8f6664cc458--780021624 | 0014Dor0780021623 | New building | m³ | b4870d4d-918a-46e5-81bc-d8f6664cc458--780021623 | Allplan Attributes - Object Layer Attributes #1, Material: Utsparring D/V; Object Layer Attributes #2, Material: Utsparring D/V; Object Layer Attributes #3, Material: Utsparring D/V; Object Layer Attributes #3, Name: D022
D025 | Plan 1 | 1.01 | 2.1 | -0.027573 | -2.121 | 0014Dor0779970431 | New building | m³ | b4870d4d-918a-46e5-81bc-d8f6664cc458--779970431 | 0014Dor0779970432 | New building | m³ | b4870d4d-918a-46e5-81bc-d8f6664cc458--779970432 | 0014Dor0779970433 | New building | m³ | b4870d4d-918a-46e5-81bc-d8f6664cc458--779970433 | Allplan Attributes - Object Layer Attributes #1, Material: Utsparring D/V; Object Layer Attributes #2, Material: Utsparring D/V; Object Layer Attributes #3, Material: Utsparring D/V; Object Layer Attributes #3, Name: D024
garasjeport med glassfelter:45x6 | Plan 1 | 1.01 | 2.11 | -0.0275665 | -2.13109 | 0014Dor0779969884 | New building | m² | b4870d4d-918a-46e5-81bc-d8f6664cc458--779969884 | 0014Dor0779969882 | New building | m² | b4870d4d-918a-46e5-81bc-d8f6664cc458--779969882 | 0014Dor0779969886 | New building | m² | b4870d4d-918a-46e5-81bc-d8f6664cc458--779969886 | Allplan Attributes - Object Layer Attributes #1, Material: Utsparring D/V; Object Layer Attributes #2, Material: Utsparring D/V; Object Layer Attributes #3, Material: Utsparring D/V; Object Layer Attributes #3, Name: D019
D017 | Plan 1 | 0.91 | 2.11 | -0.0249613 | -1.9201 | 0014Dor0779969899 | New building | m² | b4870d4d-918a-46e5-81bc-d8f6664cc458--779969899 | 0014Dor0779969897 | New building | m² | b4870d4d-918a-46e5-81bc-d8f6664cc458--779969897 | 0014Dor0779969895 | New building | m² | b4870d4d-918a-46e5-81bc-d8f6664cc458--779969895 | Allplan Attributes - Object Layer Attributes #1, Name: D017; Object Layer Attributes #1, Material: Utsparring D/V; Object Layer Attributes #2, Material: Utsparring D/V; Object Layer Attributes #3, Material: Utsparring D/V; Object Layer Attributes #3, Name: D017
garasjeport med glassfelter:45x6 | Plan 1 | 0.91 | 2.11 | -0.0249613 | -1.9201 | 0014Dor0779969888 | New building | m² | b4870d4d-918a-46e5-81bc-d8f6664cc458--779969888 | 0014Dor0779969893 | New building | m² | b4870d4d-918a-46e5-81bc-d8f6664cc458--779969893 | 0014Dor0779969890 | New building | m² | b4870d4d-918a-46e5-81bc-d8f6664cc458--779969890 | Allplan Attributes - Object Layer Attributes #1, Material: Utsparring D/V; Object Layer Attributes #2, Material: Utsparring D/V; Object Layer Attributes #3, Material: Utsparring D/V; Object Layer Attributes #2, Name: D018; Object Layer Attributes #3, Name: D018
Door opening | Plan 1 | 0.91 | 2.11 | -0.0249613 | -1.9201 | 0014Dor0779976704 | New building | m² | b4870d4d-918a-46e5-81bc-d8f6664cc458--779976704 | 0014Dor0779976703 | New building | m² | b4870d4d-918a-46e5-81bc-d8f6664cc458--779976703 | 0014Dor0779976702 | New building | m² | b4870d4d-918a-46e5-81bc-d8f6664cc458--779976702 | Allplan Attributes - Object Layer Attributes #1, Material: Utsparring D/V; Object Layer Attributes #2, Material: Utsparring D/V; Object Layer Attributes #3, Material: Utsparring D/V; Object Layer Attributes #3, Name: D015
D020 | Plan 1 | 0.91 | 2.1 | -0.024843 | -1.911 | 0014Dor0780021586 | New building | m³ | b4870d4d-918a-46e5-81bc-d8f6664cc458--780021586 | 0014Dor0780021587 | New building | m³ | b4870d4d-918a-46e5-81bc-d8f6664cc458--780021587 | 0014Dor0780021588 | New building | m³ | b4870d4d-918a-46e5-81bc-d8f6664cc458--780021588 | Allplan Attributes - Object Layer Attributes #1, Name: D020; Object Layer Attributes #1, Material: Utsparring D/V; Object Layer Attributes #2, Material: Utsparring D/V; Object Layer Attributes #3, Material: Utsparring D/V
Door opening | Plan 1 | 1.01 | 2.1 | -0.027573 | -2.121 | 0014Dor0780002201 | New building | m³ | b4870d4d-918a-46e5-81bc-d8f6664cc458--780002201 | 0014Dor0780002202 | New building | m³ | b4870d4d-918a-46e5-81bc-d8f6664cc458--780002202 | 0014Dor0780002203 | New building | m³ | b4870d4d-918a-46e5-81bc-d8f6664cc458--780002203 | Allplan Attributes - Object Layer Attributes #1, Material: Utsparring D/V; Object Layer Attributes #2, Material: Utsparring D/V; Object Layer Attributes #3, Material: Utsparring D/V
Door opening | Plan 1 | 1.01 | 2.1 | -0.027573 | -2.121 | 0014Dor0779969166 | New building | m³ | b4870d4d-918a-46e5-81bc-d8f6664cc458--779969166 | 0014Dor0779969165 | New building | m³ | b4870d4d-918a-46e5-81bc-d8f6664cc458--779969165 | 0014Dor0779969164 | New building | m³ | b4870d4d-918a-46e5-81bc-d8f6664cc458--779969164 | Allplan Attributes - Object Layer Attributes #1, Material: Utsparring D/V; Object Layer Attributes #2, Material: Utsparring D/V; Object Layer Attributes #3, Material: Utsparring D/V; Object Layer Attributes #3, Name: D025
Heisdør | Plan 1 | 0.9 | 2.1 | -0.0945 | -1.89 | 0014Dor0780023147 | New building | m² | b4870d4d-918a-46e5-81bc-d8f6664cc458--780023147 | Allplan Attributes - Object Layer Attributes #1, Name: Heisdør; Object Layer Attributes #1, Material: Utsparring D/V
D030 | Plan 1 | 1.01 | 2.11 | -0.0277043 | -2.1311 | 0014Dor0780023987 | New building | m³ | b4870d4d-918a-46e5-81bc-d8f6664cc458--780023987 | 0014Dor0780023988 | New building | m³ | b4870d4d-918a-46e5-81bc-d8f6664cc458--780023988 | 0014Dor0780023989 | New building | m³ | b4870d4d-918a-46e5-81bc-d8f6664cc458--780023989 | Allplan Attributes - Object Layer Attributes #1, Name: D030; Object Layer Attributes #1, Material: Utsparring D/V; Object Layer Attributes #2, Material: Utsparring D/V; Object Layer Attributes #3, Material: Utsparring D/V; Object Layer Attributes #3, Name: D030
GF001 | Plan 1 | 1.01 | 2.11 | -0.0277043 | -2.1311 | 0014Win0779975777 | New building | m³ | b4870d4d-918a-46e5-81bc-d8f6664cc458--779975777 | 0014Win0779975776 | New building | m³ | b4870d4d-918a-46e5-81bc-d8f6664cc458--779975776 | 0014Win0779975775 | New building | m³ | b4870d4d-918a-46e5-81bc-d8f6664cc458--779975775 | Allplan Attributes - Object Layer Attributes #1, Material: Utsparring D/V; Object Layer Attributes #2, Material: Utsparring D/V; Object Layer Attributes #3, Material: Utsparring D/V
GF002 | Plan 1 | 1.01 | 2.11 | -0.0277043 | -2.1311 | 0014Win0779975797 | New building | m³ | b4870d4d-918a-46e5-81bc-d8f6664cc458--779975797 | 0014Win0779975796 | New building | m³ | b4870d4d-918a-46e5-81bc-d8f6664cc458--779975796 | 0014Win0779975795 | New building | m³ | b4870d4d-918a-46e5-81bc-d8f6664cc458--779975795 | Allplan Attributes - Object Layer Attributes #1, Material: Utsparring D/V; Object Layer Attributes #2, Material: Utsparring D/V; Object Layer Attributes #3, Material: Utsparring D/V
Door opening | Plan 1 | 0.91 | 2.11 | -0.0249613 | -1.9201 | 0014Dor0779975717 | New building | m³ | b4870d4d-918a-46e5-81bc-d8f6664cc458--779975717 | 0014Dor0779975718 | New building | m³ | b4870d4d-918a-46e5-81bc-d8f6664cc458--779975718 | 0014Dor0779975719 | New building | m³ | b4870d4d-918a-46e5-81bc-d8f6664cc458--779975719 | Allplan Attributes - Object Layer Attributes #1, Material: Utsparring D/V; Object Layer Attributes #2, Material: Utsparring D/V; Object Layer Attributes #3, Material: Utsparring D/V
Door opening | Plan 1 | 1.01 | 2.1 | -0.027573 | -2.121 | 0014Dor0779967729 | New building | m³ | b4870d4d-918a-46e5-81bc-d8f6664cc458--779967729 | 0014Dor0779967730 | New building | m³ | b4870d4d-918a-46e5-81bc-d8f6664cc458--779967730 | 0014Dor0779967731 | New building | m³ | b4870d4d-918a-46e5-81bc-d8f6664cc458--779967731 | Allplan Attributes - Object Layer Attributes #1, Material: Utsparring D/V; Object Layer Attributes #2, Material: Utsparring D/V; Object Layer Attributes #3, Material: Utsparring D/V; Object Layer Attributes #2, Name: D028
Slab Opening | Plan 1 | 3.925 | 0.03 | -0.335588 | -11.1863 | 0016SBr0000000310 | New building | m² | d953b974-3ce8-491b-9442-2c543fcc668c--310
Window opening | Plan 2 | 1.71 | 1.21 | -0.0951786 | -2.0691 | 0023Win0779993599 | New building | m² | 84cb5e05-e28d-4939-8977-531e4630a18c--779993599 | 0023Win0779993598 | New building | m² | 84cb5e05-e28d-4939-8977-531e4630a18c--779993598 | Allplan Attributes - Object Layer Attributes #2, Trade: Ext. insulation finish systems
Window opening | Plan 2 | 1.11 | 2.11 | -0.107737 | -2.3421 | 0023Win0779993117 | New building | m² | 84cb5e05-e28d-4939-8977-531e4630a18c--779993117 | 0023Win0779993116 | New building | m² | 84cb5e05-e28d-4939-8977-531e4630a18c--779993116 | Allplan Attributes - Object Layer Attributes #2, Trade: Ext. insulation finish systems
Window opening | Plan 2 | 1.11 | 2.11 | -0.46842 | -2.3421 | 0023Win0779970796 | New building | m² | 84cb5e05-e28d-4939-8977-531e4630a18c--779970796
Window opening | Plan 2 | 1.11 | 2.41 | -0.53502 | -2.6751 | 0023Win0779994976 | New building | m² | 84cb5e05-e28d-4939-8977-531e4630a18c--779994976
Window opening | Plan 2 | 1.11 | 2.11 | -0.46842 | -2.3421 | 0023Win0000000056 | New building | m² | 84cb5e05-e28d-4939-8977-531e4630a18c--56
Window opening | Plan 2 | 1.71 | 1.21 | -0.41382 | -2.0691 | 0023Win0779970714 | New building | m² | 84cb5e05-e28d-4939-8977-531e4630a18c--779970714
Window opening | Plan 2 | 1.71 | 1.21 | -0.41382 | -2.0691 | 0023Win0779970635 | New building | m² | 84cb5e05-e28d-4939-8977-531e4630a18c--779970635
Window opening | Plan 2 | 1.71 | 1.21 | -0.41382 | -2.0691 | 0023Win0779970695 | New building | m² | 84cb5e05-e28d-4939-8977-531e4630a18c--779970695
Window opening | Plan 2 | 1.71 | 1.21 | -0.41382 | -2.0691 | 0023Win0779970683 | New building | m² | 84cb5e05-e28d-4939-8977-531e4630a18c--779970683
Window opening | Plan 2 | 1.71 | 1.21 | -0.41382 | -2.0691 | 0023Win0779970633 | New building | m² | 84cb5e05-e28d-4939-8977-531e4630a18c--779970633
Window opening | Plan 2 | 1.71 | 1.21 | -0.0951786 | -2.0691 | 0023Win0779994282 | New building | m² | 84cb5e05-e28d-4939-8977-531e4630a18c--779994282 | 0023Win0779994281 | New building | m² | 84cb5e05-e28d-4939-8977-531e4630a18c--779994281 | Allplan Attributes - Object Layer Attributes #2, Trade: Ext. insulation finish systems
Window opening | Plan 2 | 0.61 | 1.21 | -0.14762 | -0.7381 | 0023Win0779990325 | New building | m² | 84cb5e05-e28d-4939-8977-531e4630a18c--779990325
Window opening | Plan 2 | 2.41 | 2.41 | -1.16162 | -5.8081 | 0023Win0779970518 | New building | m² | 84cb5e05-e28d-4939-8977-531e4630a18c--779970518
Window opening | Plan 2 | 1.11 | 2.41 | -0.53502 | -2.6751 | 0023Win0779991086 | New building | m² | 84cb5e05-e28d-4939-8977-531e4630a18c--779991086
Window opening | Plan 2 | 1.11 | 2.41 | -0.53502 | -2.6751 | 0023Win0779971331 | New building | m² | 84cb5e05-e28d-4939-8977-531e4630a18c--779971331
Window opening | Plan 2 | 1.71 | 1.21 | -0.41382 | -2.0691 | 0023Win0779970543 | New building | m² | 84cb5e05-e28d-4939-8977-531e4630a18c--779970543
Window opening | Plan 2 | 1.71 | 1.21 | -0.41382 | -2.0691 | 0023Win0779970562 | New building | m² | 84cb5e05-e28d-4939-8977-531e4630a18c--779970562
Window opening | Plan 2 | 1.71 | 1.21 | -0.41382 | -2.0691 | 0023Win0779970574 | New building | m² | 84cb5e05-e28d-4939-8977-531e4630a18c--779970574
Window opening | Plan 2 | 1.21 | 1.21 | -0.29282 | -1.4641 | 0023Win0779970744 | New building | m² | 84cb5e05-e28d-4939-8977-531e4630a18c--779970744
Window opening | Plan 2 | 1.41 | 1.21 | -0.34122 | -1.7061 | 0023Win0779970756 | New building | m² | 84cb5e05-e28d-4939-8977-531e4630a18c--779970756
Window opening | Plan 2 | 1.41 | 1.21 | -0.34122 | -1.7061 | 0023Win0779970777 | New building | m² | 84cb5e05-e28d-4939-8977-531e4630a18c--779970777
Window opening | Plan 2 | 1.21 | 1.21 | -0.0673486 | -1.4641 | 0023Win0779993031 | New building | m² | 84cb5e05-e28d-4939-8977-531e4630a18c--779993031 | 0023Win0779993030 | New building | m² | 84cb5e05-e28d-4939-8977-531e4630a18c--779993030 | Allplan Attributes - Object Layer Attributes #2, Trade: Ext. insulation finish systems
Window opening | Plan 2 | 1.41 | 1.21 | -0.0784806 | -1.7061 | 0023Win0779993055 | New building | m² | 84cb5e05-e28d-4939-8977-531e4630a18c--779993055 | 0023Win0779993054 | New building | m² | 84cb5e05-e28d-4939-8977-531e4630a18c--779993054 | Allplan Attributes - Object Layer Attributes #2, Trade: Ext. insulation finish systems
Window opening | Plan 2 | 1.41 | 1.21 | -0.0784806 | -1.7061 | 0023Win0779993007 | New building | m² | 84cb5e05-e28d-4939-8977-531e4630a18c--779993007 | 0023Win0779993006 | New building | m² | 84cb5e05-e28d-4939-8977-531e4630a18c--779993006 | Allplan Attributes - Object Layer Attributes #2, Trade: Ext. insulation finish systems
Window opening | Plan 2 | 1.01 | 2.11 | -0.0277043 | -2.1311 | 0024Win0779986851 | New building | m³ | ffc0a4b9-6ff1-450c-9901-90887e5cf058--779986851 | 0024Win0779986852 | New building | m³ | ffc0a4b9-6ff1-450c-9901-90887e5cf058--779986852 | 0024Win0779986853 | New building | m³ | ffc0a4b9-6ff1-450c-9901-90887e5cf058--779986853
Window opening | Plan 2 | 1.01 | 2.11 | -0.0277043 | -2.1311 | 0024Win0779987398 | New building | m³ | ffc0a4b9-6ff1-450c-9901-90887e5cf058--779987398 | 0024Win0779987397 | New building | m³ | ffc0a4b9-6ff1-450c-9901-90887e5cf058--779987397 | 0024Win0779987396 | New building | m³ | ffc0a4b9-6ff1-450c-9901-90887e5cf058--779987396
Window opening | Plan 2 | 1.01 | 2.11 | -0.0277043 | -2.1311 | 0024Win0779986879 | New building | m³ | ffc0a4b9-6ff1-450c-9901-90887e5cf058--779986879 | 0024Win0779986878 | New building | m³ | ffc0a4b9-6ff1-450c-9901-90887e5cf058--779986878 | 0024Win0779986877 | New building | m³ | ffc0a4b9-6ff1-450c-9901-90887e5cf058--779986877
garasjeport med glassfelter:45x6 | Plan 2 | 1.01 | 2.11 | -0.0277043 | -2.1311 | 0024Dor0779986848 | New building | m³ | ffc0a4b9-6ff1-450c-9901-90887e5cf058--779986848 | 0024Dor0779986849 | New building | m³ | ffc0a4b9-6ff1-450c-9901-90887e5cf058--779986849 | 0024Dor0779986850 | New building | m³ | ffc0a4b9-6ff1-450c-9901-90887e5cf058--779986850
garasjeport med glassfelter:45x6 | Plan 2 | 1.01 | 2.11 | -0.0277043 | -2.1311 | 0024Dor0779986882 | New building | m³ | ffc0a4b9-6ff1-450c-9901-90887e5cf058--779986882 | 0024Dor0779986881 | New building | m³ | ffc0a4b9-6ff1-450c-9901-90887e5cf058--779986881 | 0024Dor0779986880 | New building | m³ | ffc0a4b9-6ff1-450c-9901-90887e5cf058--779986880
garasjeport med glassfelter:45x6 | Plan 2 | 1.01 | 2.11 | -0.0277043 | -2.1311 | 0024Dor0779987401 | New building | m³ | ffc0a4b9-6ff1-450c-9901-90887e5cf058--779987401 | 0024Dor0779987400 | New building | m³ | ffc0a4b9-6ff1-450c-9901-90887e5cf058--779987400 | 0024Dor0779987399 | New building | m³ | ffc0a4b9-6ff1-450c-9901-90887e5cf058--779987399
Window opening | Plan 2 | 1.01 | 2.11 | -0.0277043 | -2.1311 | 0024Win0779995387 | New building | m³ | ffc0a4b9-6ff1-450c-9901-90887e5cf058--779995387 | 0024Win0779995388 | New building | m³ | ffc0a4b9-6ff1-450c-9901-90887e5cf058--779995388 | 0024Win0779995389 | New building | m³ | ffc0a4b9-6ff1-450c-9901-90887e5cf058--779995389
Window opening | Plan 2 | 1.01 | 2.11 | -0.0277043 | -2.1311 | 0024Win0779989307 | New building | m³ | ffc0a4b9-6ff1-450c-9901-90887e5cf058--779989307 | 0024Win0779989308 | New building | m³ | ffc0a4b9-6ff1-450c-9901-90887e5cf058--779989308 | 0024Win0779989309 | New building | m³ | ffc0a4b9-6ff1-450c-9901-90887e5cf058--779989309
Window opening | Plan 2 | 1.01 | 2.11 | -0.0277043 | -2.1311 | 0024Win0779989022 | New building | m³ | ffc0a4b9-6ff1-450c-9901-90887e5cf058--779989022 | 0024Win0779989021 | New building | m³ | ffc0a4b9-6ff1-450c-9901-90887e5cf058--779989021 | 0024Win0779989020 | New building | m³ | ffc0a4b9-6ff1-450c-9901-90887e5cf058--779989020
Window opening | Plan 2 | 1.01 | 2.11 | -0.0277043 | -2.1311 | 0024Win0779988832 | New building | m³ | ffc0a4b9-6ff1-450c-9901-90887e5cf058--779988832 | 0024Win0779988833 | New building | m³ | ffc0a4b9-6ff1-450c-9901-90887e5cf058--779988833 | 0024Win0779988834 | New building | m³ | ffc0a4b9-6ff1-450c-9901-90887e5cf058--779988834
Window opening | Plan 2 | 1.01 | 2.11 | -0.0277043 | -2.1311 | 0024Win0779988973 | New building | m³ | ffc0a4b9-6ff1-450c-9901-90887e5cf058--779988973 | 0024Win0779988974 | New building | m³ | ffc0a4b9-6ff1-450c-9901-90887e5cf058--779988974 | 0024Win0779988975 | New building | m³ | ffc0a4b9-6ff1-450c-9901-90887e5cf058--779988975
Window opening | Plan 2 | 1.01 | 2.11 | -0.0277043 | -2.1311 | 0024Win0779995451 | New building | m³ | ffc0a4b9-6ff1-450c-9901-90887e5cf058--779995451 | 0024Win0779995450 | New building | m³ | ffc0a4b9-6ff1-450c-9901-90887e5cf058--779995450 | 0024Win0779995449 | New building | m³ | ffc0a4b9-6ff1-450c-9901-90887e5cf058--779995449
garasjeport med glassfelter:45x6 | Plan 2 | 1.01 | 2.11 | -0.0277043 | -2.1311 | 0024Dor0779988829 | New building | m³ | ffc0a4b9-6ff1-450c-9901-90887e5cf058--779988829 | 0024Dor0779988830 | New building | m³ | ffc0a4b9-6ff1-450c-9901-90887e5cf058--779988830 | 0024Dor0779988831 | New building | m³ | ffc0a4b9-6ff1-450c-9901-90887e5cf058--779988831
garasjeport med glassfelter:45x6 | Plan 2 | 1.01 | 2.11 | -0.0277043 | -2.1311 | 0024Dor0779989304 | New building | m³ | ffc0a4b9-6ff1-450c-9901-90887e5cf058--779989304 | 0024Dor0779989305 | New building | m³ | ffc0a4b9-6ff1-450c-9901-90887e5cf058--779989305 | 0024Dor0779989306 | New building | m³ | ffc0a4b9-6ff1-450c-9901-90887e5cf058--779989306
garasjeport med glassfelter:45x6 | Plan 2 | 1.01 | 2.11 | -0.0277043 | -2.1311 | 0024Dor0779989025 | New building | m³ | ffc0a4b9-6ff1-450c-9901-90887e5cf058--779989025 | 0024Dor0779989024 | New building | m³ | ffc0a4b9-6ff1-450c-9901-90887e5cf058--779989024 | 0024Dor0779989023 | New building | m³ | ffc0a4b9-6ff1-450c-9901-90887e5cf058--779989023
garasjeport med glassfelter:45x6 | Plan 2 | 1.01 | 2.11 | -0.0277043 | -2.1311 | 0024Dor0779988970 | New building | m³ | ffc0a4b9-6ff1-450c-9901-90887e5cf058--779988970 | 0024Dor0779988971 | New building | m³ | ffc0a4b9-6ff1-450c-9901-90887e5cf058--779988971 | 0024Dor0779988972 | New building | m³ | ffc0a4b9-6ff1-450c-9901-90887e5cf058--779988972
garasjeport med glassfelter:45x6 | Plan 2 | 1.01 | 2.11 | -0.0277043 | -2.1311 | 0024Dor0779986198 | New building | m³ | ffc0a4b9-6ff1-450c-9901-90887e5cf058--779986198 | 0024Dor0779986197 | New building | m³ | ffc0a4b9-6ff1-450c-9901-90887e5cf058--779986197 | 0024Dor0779986196 | New building | m³ | ffc0a4b9-6ff1-450c-9901-90887e5cf058--779986196
garasjeport med glassfelter:45x6 | Plan 2 | 1.01 | 2.11 | -0.0277043 | -2.1311 | 0024Dor0779987981 | New building | m³ | ffc0a4b9-6ff1-450c-9901-90887e5cf058--779987981 | 0024Dor0779987980 | New building | m³ | ffc0a4b9-6ff1-450c-9901-90887e5cf058--779987980 | 0024Dor0779987979 | New building | m³ | ffc0a4b9-6ff1-450c-9901-90887e5cf058--779987979
Door opening | Plan 2 | 1.11 | 2.11 | -0.0304473 | -2.3421 | 0024Dor0779994281 | New building | m³ | ffc0a4b9-6ff1-450c-9901-90887e5cf058--779994281 | 0024Dor0779994282 | New building | m³ | ffc0a4b9-6ff1-450c-9901-90887e5cf058--779994282 | 0024Dor0779994283 | New building | m³ | ffc0a4b9-6ff1-450c-9901-90887e5cf058--779994283
garasjeport med glassfelter:45x6 | Plan 2 | 1.01 | 2.11 | -0.0277043 | -2.1311 | 0024Dor0779993153 | New building | m³ | ffc0a4b9-6ff1-450c-9901-90887e5cf058--779993153 | 0024Dor0779993152 | New building | m³ | ffc0a4b9-6ff1-450c-9901-90887e5cf058--779993152 | 0024Dor0779993151 | New building | m³ | ffc0a4b9-6ff1-450c-9901-90887e5cf058--779993151
Door opening | Plan 2 | 0.9 | 2.11 | -0.024687 | -1.899 | 0024Dor0779992741 | New building | m³ | ffc0a4b9-6ff1-450c-9901-90887e5cf058--779992741 | 0024Dor0779992740 | New building | m³ | ffc0a4b9-6ff1-450c-9901-90887e5cf058--779992740 | 0024Dor0779992739 | New building | m³ | ffc0a4b9-6ff1-450c-9901-90887e5cf058--779992739
garasjeport med glassfelter:45x6 | Plan 2 | 1.01 | 2.11 | -0.0277043 | -2.1311 | 0024Dor0779992732 | New building | m³ | ffc0a4b9-6ff1-450c-9901-90887e5cf058--779992732 | 0024Dor0779992733 | New building | m³ | ffc0a4b9-6ff1-450c-9901-90887e5cf058--779992733 | 0024Dor0779992734 | New building | m³ | ffc0a4b9-6ff1-450c-9901-90887e5cf058--779992734
garasjeport med glassfelter:45x6 | Plan 2 | 1.01 | 2.11 | -0.0277043 | -2.1311 | 0024Dor0779983366 | New building | m³ | ffc0a4b9-6ff1-450c-9901-90887e5cf058--779983366 | 0024Dor0779983367 | New building | m³ | ffc0a4b9-6ff1-450c-9901-90887e5cf058--779983367 | 0024Dor0779983368 | New building | m³ | ffc0a4b9-6ff1-450c-9901-90887e5cf058--779983368
Door opening | Plan 2 | 0.9 | 2.1 | -0.0945 | -1.89 | 0024Dor0780023194 | New building | m² | ffc0a4b9-6ff1-450c-9901-90887e5cf058--780023194
Door opening | Plan 2 | 1.01 | 2.11 | -0.0277043 | -2.1311 | 0024Dor0780026904 | New building | m³ | ffc0a4b9-6ff1-450c-9901-90887e5cf058--780026904 | 0024Dor0780026905 | New building | m³ | ffc0a4b9-6ff1-450c-9901-90887e5cf058--780026905 | 0024Dor0780026906 | New building | m³ | ffc0a4b9-6ff1-450c-9901-90887e5cf058--780026906

# IfcRailing, Rail_Path
In: Plan 1
Allplan Attributes - Allright_Comp_ID: 0018Rai0779871143; Unit: Pc; V6: 0; V7: 0; V8: 0; V9: 0; Component: Rail_Object; Plugin_name: Rail_Path; Plugin_object_name: Rail_Macro; NOI_UUID: 2b163d4f-5c70-4d8b-a784-0af841b40480--779871143

# IfcRoof (5)
Allplan Attributes - Object Layer Attributes #1, Building alteration category: New building; Object Layer Attributes #1, Unit: m²; Object Layer Attributes #2, Building alteration category: New building; Object Layer Attributes #2, Unit: m²; Object Layer Attributes #3, Building alteration category: New building; Object Layer Attributes #3, Unit: m²
Name | In | TotalSurfaceArea (m2) | Object Layer Attributes #1, Allright_Comp_ID | Object Layer Attributes #1, Material | Object Layer Attributes #1, NOI_UUID | Object Layer Attributes #2, Allright_Comp_ID | Object Layer Attributes #2, NOI_UUID | Object Layer Attributes #3, Allright_Comp_ID | Object Layer Attributes #3, NOI_UUID
 | Konstruksjoner i grunnen | 361.68 | 0005RfC0000000002 | Golvbelegg | dea4e5d4-67a8-4f71-a690-1e4c8fd9c290--2 | 0005RfC0000000003 | dea4e5d4-67a8-4f71-a690-1e4c8fd9c290--3 | 0005RfC0780050251 | dea4e5d4-67a8-4f71-a690-1e4c8fd9c290--780050251
 | Plan 1 | 9.40915 | 0016RfC0000000187 | dERBIGUM | d953b974-3ce8-491b-9442-2c543fcc668c--187 | 0016RfC0000000188 | d953b974-3ce8-491b-9442-2c543fcc668c--188 | 0016RfC0000000189 | d953b974-3ce8-491b-9442-2c543fcc668c--189
 | Plan 1 | 10.6702 | 0016RfC0000003568 | dERBIGUM | d953b974-3ce8-491b-9442-2c543fcc668c--3568 | 0016RfC0000003569 | d953b974-3ce8-491b-9442-2c543fcc668c--3569 | 0016RfC0000003570 | d953b974-3ce8-491b-9442-2c543fcc668c--3570
 | Plan 2 | 49.2007 | 0034RfC0000000566 | Decra | 9b8806e7-4009-424f-bd57-ff5b061054b9--566 | 0034RfC0000000567 | 9b8806e7-4009-424f-bd57-ff5b061054b9--567 | 0034RfC0000000568 | 9b8806e7-4009-424f-bd57-ff5b061054b9--568 | Allplan Attributes - Object Layer Attributes #4, Allright_Comp_ID: 0034RfC0000000569; Object Layer Attributes #4, Building alteration category: New building; Object Layer Attributes #4, Unit: m²; Object Layer Attributes #4, NOI_UUID: 9b8806e7-4009-424f-bd57-ff5b061054b9--569
 | Plan 2 | 241.74 | 0034RfC0000000013 | Derbigum | 9b8806e7-4009-424f-bd57-ff5b061054b9--13 | 0034RfC0000000014 | 9b8806e7-4009-424f-bd57-ff5b061054b9--14 | 0034RfC0000000015 | 9b8806e7-4009-424f-bd57-ff5b061054b9--15

# IfcSlab (12)
Name | In | PredefinedType | Material | GrossVolume (m3) | NetVolume (m3) | GrossSideArea (m2) | Width (m) | Allright_Comp_ID | Building alteration category | Unit | Allplan Attributes, Material | NOI_UUID
 | Konstruksjoner i grunnen | FLOOR | Betong 150 mm | 1.1622 | 1.1622 | 7.748 | 0.15 | 0005Cng0779998797 | New building | m³ | Betong | dea4e5d4-67a8-4f71-a690-1e4c8fd9c290--779998797
 | Konstruksjoner i grunnen | FLOOR | Betong 150 mm | 1.33776 | 1.33776 | 8.91841 | 0.15 | 0005Cng0779999094 | New building | m³ | Betong | dea4e5d4-67a8-4f71-a690-1e4c8fd9c290--779999094
 | Konstruksjoner i grunnen | ROOF
 | Konstruksjoner i grunnen | FLOOR | Skraperist 50 mm | 0.045 | 0.045 | 0.9 | 0.05 | 0005Cng0779999018 | New building | m³ | Skraperist | dea4e5d4-67a8-4f71-a690-1e4c8fd9c290--779999018
 | Konstruksjoner i grunnen | FLOOR | Skraperist 50 mm | 0.045 | 0.045 | 0.9 | 0.05 | 0005Cng0779999092 | New building | m³ | Skraperist | dea4e5d4-67a8-4f71-a690-1e4c8fd9c290--779999092
 | Plan 1 | FLOOR | Betong 200 mm | 1.73725 | 1.73725 | 8.68627 | 0.2 | 0015Cng0016826100 | New building | m³ | Betong | cbab19c6-f7f3-4c25-9028-8574def17b1d--16826100
 | Plan 1 | FLOOR | Betong | 55.4695 | 55.4695 | 115.62 | 0.47976 | 0016Cng0000000692 | New building | m² | Betong | d953b974-3ce8-491b-9442-2c543fcc668c--692
2 x  | Plan 1 | ROOF
 | Plan 1 | FLOOR | Flyt golv 30 mm | 7.16205 | 6.83536 | 238.735 | 0.03 | 0016Cng0000000302 | New building | m² | Flyt golv | d953b974-3ce8-491b-9442-2c543fcc668c--302
2 x  | Plan 2 | ROOF

# IfcStair
In: Plan 1
Material: Betong
Pset_StairCommon - NumberOfRiser: 20; RiserHeight: 175 mm; TreadLength: 275 mm; NumberOfTreads: 21
Allplan Attributes - Allright_Comp_ID: 0018Str0779867919; Unit: Pc; Material: Betong; NOI_UUID: 2b163d4f-5c70-4d8b-a784-0af841b40480--779867919

# IfcWallStandardCase (167)
Allplan Attributes - Unit: m³; Object Layer Attributes #1, Building alteration category: New building
Name | In | Material | GrossVolume (m3) | NetVolume (m3) | GrossSideArea (m2) | NetSideArea (m2) | NominalLength (m) | NominalWidth (m) | GrossFootprintArea (m2) | NominalHeight (m) | Allright_Comp_ID | NOI_UUID | Object Layer Attributes #1, Allright_Comp_ID | Object Layer Attributes #1, Unit | Object Layer Attributes #1, NOI_UUID
 | Konstruksjoner i grunnen | Rissanviser 15 mm | 0.0348 | 0.0348 | 2.32 | 2.32 | 11.6 | 0.015 | 0.174 | 0.2 | 0005HWa0779847836 | dea4e5d4-67a8-4f71-a690-1e4c8fd9c290--779847836 | 0005Wal0779847839 | m | dea4e5d4-67a8-4f71-a690-1e4c8fd9c290--779847839 | Allplan Attributes - Object Layer Attributes #1, Material: Rissanviser
 | Konstruksjoner i grunnen | Rissanviser 15 mm | 0.036 | 0.036 | 2.4 | 2.4 | 12 | 0.015 | 0.18 | 0.2 | 0005HWa0779847919 | dea4e5d4-67a8-4f71-a690-1e4c8fd9c290--779847919 | 0005Wal0779847921 | m | dea4e5d4-67a8-4f71-a690-1e4c8fd9c290--779847921 | Allplan Attributes - Object Layer Attributes #1, Material: Rissanviser
 | Konstruksjoner i grunnen | Rissanviser 33.0825 mm | 0.050047 | 0.050047 | 3.33647 | 1.24587 | 16.6824 | 0.015 | 0.250235 | 0.2 | 0005HWa0779848044 | dea4e5d4-67a8-4f71-a690-1e4c8fd9c290--779848044 | 0005Wal0779848046 | m | dea4e5d4-67a8-4f71-a690-1e4c8fd9c290--779848046 | Allplan Attributes - Object Layer Attributes #1, Material: Rissanviser
 | Konstruksjoner i grunnen | Rissanviser 15 mm | 0.036 | 0.036 | 2.4 | 2.4 | 12 | 0.015 | 0.18 | 0.2 | 0005HWa0779847999 | dea4e5d4-67a8-4f71-a690-1e4c8fd9c290--779847999 | 0005Wal0779848001 | m | dea4e5d4-67a8-4f71-a690-1e4c8fd9c290--779848001 | Allplan Attributes - Object Layer Attributes #1, Material: Rissanviser
 | Konstruksjoner i grunnen | Rissanviser 22.6379 mm | 0.0354171 | 0.0354171 | 2.36114 | 2.36114 | 11.8057 | 0.015 | 0.177086 | 0.2 | 0005HWa0779847852 | dea4e5d4-67a8-4f71-a690-1e4c8fd9c290--779847852 | 0005Wal0779847854 | m | dea4e5d4-67a8-4f71-a690-1e4c8fd9c290--779847854 | Allplan Attributes - Object Layer Attributes #1, Material: Rissanviser
3 x  | Konstruksjoner i grunnen | Rissanviser 15 mm | 0.048621 | 0.048621 | 3.2414 | 3.2414 | 16.207 | 0.015 | 0.243105 | 0.2 | 0005HWa0779847814 | dea4e5d4-67a8-4f71-a690-1e4c8fd9c290--779847814 | 0005Wal0779847816 | m | dea4e5d4-67a8-4f71-a690-1e4c8fd9c290--779847816 | Allplan Attributes - Object Layer Attributes #1, Material: Rissanviser
3 x  | Konstruksjoner i grunnen | Rissanviser 15 mm | 0.0406709 | 0.0406709 | 2.71139 | 2.71139 | 13.557 | 0.015 | 0.203354 | 0.2 | 0005HWa0779847831 | dea4e5d4-67a8-4f71-a690-1e4c8fd9c290--779847831 | 0005Wal0779847833 | m | dea4e5d4-67a8-4f71-a690-1e4c8fd9c290--779847833 | Allplan Attributes - Object Layer Attributes #1, Material: Rissanviser
 | Konstruksjoner i grunnen | Betong 700 mm | 6.258 | 6.258 | 8.94 | 8.94 | 29.8 | 0.7 | 20.86 | 0.3 | 0009HWa0016812898 | 4201cc08-73ef-4c73-a438-824d10b54809--16812898 | 0009Wal0016812922 | m³ | 4201cc08-73ef-4c73-a438-824d10b54809--16812922 | Allplan Attributes - Object Layer Attributes #1, Material: Betong
 | Konstruksjoner i grunnen | Betong 700 mm | 2.331 | 2.331 | 3.33 | 3.33 | 11.1 | 0.7 | 7.77 | 0.3 | 0009HWa0016812897 | 4201cc08-73ef-4c73-a438-824d10b54809--16812897 | 0009Wal0016812926 | m³ | 4201cc08-73ef-4c73-a438-824d10b54809--16812926 | Allplan Attributes - Object Layer Attributes #1, Material: Betong
 | Konstruksjoner i grunnen | Betong 700 mm | 2.625 | 2.625 | 3.75 | 3.75 | 12.5 | 0.7 | 8.75 | 0.3 | 0009HWa0016812917 | 4201cc08-73ef-4c73-a438-824d10b54809--16812917 | 0009Wal0016812924 | m³ | 4201cc08-73ef-4c73-a438-824d10b54809--16812924
 | Konstruksjoner i grunnen | Betong 700 mm | 6.258 | 6.258 | 8.94 | 8.94 | 29.8 | 0.7 | 20.86 | 0.3 | 0009HWa0016812895 | 4201cc08-73ef-4c73-a438-824d10b54809--16812895 | 0009Wal0016812920 | m³ | 4201cc08-73ef-4c73-a438-824d10b54809--16812920 | Allplan Attributes - Object Layer Attributes #1, Material: Betong
 | Konstruksjoner i grunnen | Betong 1000 mm | 0.3 | 0.3 | 0.3 | 0.3 | 1 | 1 | 1 | 0.3 | 0009HWa0016812901 | 4201cc08-73ef-4c73-a438-824d10b54809--16812901 | 0009Wal0016812908 | m³ | 4201cc08-73ef-4c73-a438-824d10b54809--16812908 | Allplan Attributes - Object Layer Attributes #1, Material: Betong
 | Konstruksjoner i grunnen | Betong 1000 mm | 0.3 | 0.3 | 0.3 | 0.3 | 1 | 1 | 1 | 0.3 | 0009HWa0016813915 | 4201cc08-73ef-4c73-a438-824d10b54809--16813915 | 0009Wal0016813920 | m³ | 4201cc08-73ef-4c73-a438-824d10b54809--16813920 | Allplan Attributes - Object Layer Attributes #1, Material: Betong
 | Konstruksjoner i grunnen | Betong 1000 mm | 0.3 | 0.3 | 0.3 | 0.3 | 1 | 1 | 1 | 0.3 | 0009HWa0016814147 | 4201cc08-73ef-4c73-a438-824d10b54809--16814147 | 0009Wal0016814152 | m³ | 4201cc08-73ef-4c73-a438-824d10b54809--16814152 | Allplan Attributes - Object Layer Attributes #1, Material: Betong
 | Konstruksjoner i grunnen | Betong 1000 mm | 0.3 | 0.3 | 0.3 | 0.3 | 1 | 1 | 1 | 0.3 | 0009HWa0016814153 | 4201cc08-73ef-4c73-a438-824d10b54809--16814153 | 0009Wal0016814158 | m³ | 4201cc08-73ef-4c73-a438-824d10b54809--16814158 | Allplan Attributes - Object Layer Attributes #1, Material: Betong
 | Konstruksjoner i grunnen | Betong 1000 mm | 0.3 | 0.3 | 0.3 | 0.3 | 1 | 1 | 1 | 0.3 | 0009HWa0016814159 | 4201cc08-73ef-4c73-a438-824d10b54809--16814159 | 0009Wal0016814164 | m³ | 4201cc08-73ef-4c73-a438-824d10b54809--16814164 | Allplan Attributes - Object Layer Attributes #1, Material: Betong
 | Konstruksjoner i grunnen | Betong 1000 mm | 0.3 | 0.3 | 0.3 | 0.3 | 1 | 1 | 1 | 0.3 | 0009HWa0016814165 | 4201cc08-73ef-4c73-a438-824d10b54809--16814165 | 0009Wal0016814170 | m³ | 4201cc08-73ef-4c73-a438-824d10b54809--16814170 | Allplan Attributes - Object Layer Attributes #1, Material: Betong
 | Konstruksjoner i grunnen | Betong 1000 mm | 0.3 | 0.3 | 0.3 | 0.3 | 1 | 1 | 1 | 0.3 | 0009HWa0016814171 | 4201cc08-73ef-4c73-a438-824d10b54809--16814171 | 0009Wal0016814176 | m³ | 4201cc08-73ef-4c73-a438-824d10b54809--16814176 | Allplan Attributes - Object Layer Attributes #1, Material: Betong
 | Konstruksjoner i grunnen | Betong 1000 mm | 0.3 | 0.3 | 0.3 | 0.3 | 1 | 1 | 1 | 0.3 | 0009HWa0016814177 | 4201cc08-73ef-4c73-a438-824d10b54809--16814177 | 0009Wal0016814182 | m³ | 4201cc08-73ef-4c73-a438-824d10b54809--16814182 | Allplan Attributes - Object Layer Attributes #1, Material: Betong
 | Konstruksjoner i grunnen | Betong 1000 mm | 0.3 | 0.3 | 0.3 | 0.3 | 1 | 1 | 1 | 0.3 | 0009HWa0016814183 | 4201cc08-73ef-4c73-a438-824d10b54809--16814183 | 0009Wal0016814188 | m³ | 4201cc08-73ef-4c73-a438-824d10b54809--16814188 | Allplan Attributes - Object Layer Attributes #1, Material: Betong
 | Konstruksjoner i grunnen | Betong 1000 mm | 0.3 | 0.3 | 0.3 | 0.3 | 1 | 1 | 1 | 0.3 | 0009HWa0016814189 | 4201cc08-73ef-4c73-a438-824d10b54809--16814189 | 0009Wal0016814194 | m³ | 4201cc08-73ef-4c73-a438-824d10b54809--16814194 | Allplan Attributes - Object Layer Attributes #1, Material: Betong
2 x  | Konstruksjoner i grunnen | Betong 150 mm | 0.057 | 0.057 | 0.38 | 0.38 | 0.95 | 0.15 | 0.1425 | 0.4 | 0010HWa0016819854 | 7f7a4b69-a8bb-45a3-b6d6-f0093fb4d01a--16819854 | 0010Wal0016819958 | m³ | 7f7a4b69-a8bb-45a3-b6d6-f0093fb4d01a--16819958 | Allplan Attributes - Object Layer Attributes #1, Material: Betong
 | Konstruksjoner i grunnen | Betong 50 mm, Betong 150 mm | 1.563 | 1.563 |  |  | 11.9 | 0.2 | 2.4 | 0.6 | 0010HWa0016822792 | 7f7a4b69-a8bb-45a3-b6d6-f0093fb4d01a--16822792 | 0010Wal0016822793 | m² | 7f7a4b69-a8bb-45a3-b6d6-f0093fb4d01a--16822793 | Allplan Attributes - Object Layer Attributes #1, Material: Betong; Object Layer Attributes #1, Trade: Ext. insulation finish systems; Object Layer Attributes #2, Allright_Comp_ID: 0010Wal0779929666; Object Layer Attributes #2, Building alteration category: New building; Object Layer Attributes #2, Unit: m³; Object Layer Attributes #2, Material: Betong; Object Layer Attributes #2, NOI_UUID: 7f7a4b69-a8bb-45a3-b6d6-f0093fb4d01a--779929666; WallQuantities - GrossSideAreaRight: 5.85 m2; GrossSideAreaLeft: 8.47 m2; NetSideAreaRight: 5.85 m2; NetSideAreaLeft: 8.47 m2
 | Konstruksjoner i grunnen | Betong 50 mm, Betong 150 mm | 1.47775 | 1.47775 |  |  | 11.475 | 0.2 | 2.2775 | 0.6 | 0010HWa0016822752 | 7f7a4b69-a8bb-45a3-b6d6-f0093fb4d01a--16822752 | 0010Wal0016822753 | m² | 7f7a4b69-a8bb-45a3-b6d6-f0093fb4d01a--16822753 | WallQuantities - GrossSideAreaRight: 5.825 m2; GrossSideAreaLeft: 7.91 m2; NetSideAreaRight: 5.825 m2; NetSideAreaLeft: 7.91 m2; Allplan Attributes - Object Layer Attributes #1, Trade: Ext. insulation finish systems; Object Layer Attributes #2, Allright_Comp_ID: 0010Wal0779930582; Object Layer Attributes #2, Building alteration category: New building; Object Layer Attributes #2, Unit: m³; Object Layer Attributes #2, NOI_UUID: 7f7a4b69-a8bb-45a3-b6d6-f0093fb4d01a--779930582
 | Konstruksjoner i grunnen | Betong 150 mm, Betong 50 mm | 0.322 | 0.322 |  |  | 2.8 | 0.2 | 0.56 | 0.55 | 0010HWa0779930794 | 7f7a4b69-a8bb-45a3-b6d6-f0093fb4d01a--779930794 | 0010Wal0779930797 | m³ | 7f7a4b69-a8bb-45a3-b6d6-f0093fb4d01a--779930797 | Allplan Attributes - Object Layer Attributes #1, Material: Betong; Object Layer Attributes #2, Allright_Comp_ID: 0010Wal0779930796; Object Layer Attributes #2, Building alteration category: New building; Object Layer Attributes #2, Unit: m²; Object Layer Attributes #2, Material: Betong; Object Layer Attributes #2, NOI_UUID: 7f7a4b69-a8bb-45a3-b6d6-f0093fb4d01a--779930796; Object Layer Attributes #2, Trade: Ext. insulation finish systems; WallQuantities - GrossSideAreaRight: 1.68 m2; GrossSideAreaLeft: 1.4 m2; NetSideAreaRight: 1.68 m2; NetSideAreaLeft: 1.4 m2
 | Konstruksjoner i grunnen | Betong 150 mm, Betong 50 mm | 0.322 | 0.322 |  |  | 2.8 | 0.2 | 0.56 | 0.55 | 0010HWa0779930856 | 7f7a4b69-a8bb-45a3-b6d6-f0093fb4d01a--779930856 | 0010Wal0779930858 | m³ | 7f7a4b69-a8bb-45a3-b6d6-f0093fb4d01a--779930858 | WallQuantities - GrossSideAreaRight: 1.68 m2; GrossSideAreaLeft: 1.4 m2; NetSideAreaRight: 1.68 m2; NetSideAreaLeft: 1.4 m2; Allplan Attributes - Object Layer Attributes #2, Allright_Comp_ID: 0010Wal0779930859; Object Layer Attributes #2, Building alteration category: New building; Object Layer Attributes #2, Unit: m²; Object Layer Attributes #2, NOI_UUID: 7f7a4b69-a8bb-45a3-b6d6-f0093fb4d01a--779930859; Object Layer Attributes #2, Trade: Ext. insulation finish systems
 | Konstruksjoner i grunnen | Betong 150 mm, Betong 50 mm | 0.322 | 0.322 |  |  | 2.8 | 0.2 | 0.56 | 0.55 | 0010HWa0779930904 | 7f7a4b69-a8bb-45a3-b6d6-f0093fb4d01a--779930904 | 0010Wal0779930907 | m³ | 7f7a4b69-a8bb-45a3-b6d6-f0093fb4d01a--779930907 | WallQuantities - GrossSideAreaRight: 1.68 m2; GrossSideAreaLeft: 1.4 m2; NetSideAreaRight: 1.68 m2; NetSideAreaLeft: 1.4 m2; Allplan Attributes - Object Layer Attributes #2, Allright_Comp_ID: 0010Wal0779930906; Object Layer Attributes #2, Building alteration category: New building; Object Layer Attributes #2, Unit: m²; Object Layer Attributes #2, NOI_UUID: 7f7a4b69-a8bb-45a3-b6d6-f0093fb4d01a--779930906; Object Layer Attributes #2, Trade: Ext. insulation finish systems
 | Konstruksjoner i grunnen | Betong 350 mm | 0.0875 | 0.0875 | 0.25 | 0.25 | 0.5 | 0.35 | 0.175 | 0.5 | 0010HWa0016820426 | 7f7a4b69-a8bb-45a3-b6d6-f0093fb4d01a--16820426 | 0010Wal0016820431 | m³ | 7f7a4b69-a8bb-45a3-b6d6-f0093fb4d01a--16820431
 | Konstruksjoner i grunnen | Betong 350 mm | 0.0875 | 0.0875 | 0.25 | 0.25 | 0.5 | 0.35 | 0.175 | 0.5 | 0010HWa0016819737 | 7f7a4b69-a8bb-45a3-b6d6-f0093fb4d01a--16819737 | 0010Wal0016819918 | m³ | 7f7a4b69-a8bb-45a3-b6d6-f0093fb4d01a--16819918
 | Konstruksjoner i grunnen | Betong 350 mm | 0.0875 | 0.0875 | 0.25 | 0.25 | 0.5 | 0.35 | 0.175 | 0.5 | 0010HWa0016819741 | 7f7a4b69-a8bb-45a3-b6d6-f0093fb4d01a--16819741 | 0010Wal0016819922 | m³ | 7f7a4b69-a8bb-45a3-b6d6-f0093fb4d01a--16819922
 | Konstruksjoner i grunnen | Betong 350 mm | 0.0875 | 0.0875 | 0.25 | 0.25 | 0.5 | 0.35 | 0.175 | 0.5 | 0010HWa0016819743 | 7f7a4b69-a8bb-45a3-b6d6-f0093fb4d01a--16819743 | 0010Wal0016819924 | m³ | 7f7a4b69-a8bb-45a3-b6d6-f0093fb4d01a--16819924
 | Konstruksjoner i grunnen | Betong 350 mm | 0.0875 | 0.0875 | 0.25 | 0.25 | 0.5 | 0.35 | 0.175 | 0.5 | 0010HWa0016822501 | 7f7a4b69-a8bb-45a3-b6d6-f0093fb4d01a--16822501 | 0010Wal0016822503 | m³ | 7f7a4b69-a8bb-45a3-b6d6-f0093fb4d01a--16822503
 | Konstruksjoner i grunnen | Betong 350 mm | 0.0875 | 0.0875 | 0.25 | 0.25 | 0.5 | 0.35 | 0.175 | 0.5 | 0010HWa0016819722 | 7f7a4b69-a8bb-45a3-b6d6-f0093fb4d01a--16819722 | 0010Wal0016819893 | m³ | 7f7a4b69-a8bb-45a3-b6d6-f0093fb4d01a--16819893
 | Konstruksjoner i grunnen | Betong 350 mm | 0.0875 | 0.0875 | 0.25 | 0.25 | 0.5 | 0.35 | 0.175 | 0.5 | 0010HWa0016819724 | 7f7a4b69-a8bb-45a3-b6d6-f0093fb4d01a--16819724 | 0010Wal0016819891 | m³ | 7f7a4b69-a8bb-45a3-b6d6-f0093fb4d01a--16819891
 | Konstruksjoner i grunnen | Betong 350 mm | 0.0875 | 0.0875 | 0.25 | 0.25 | 0.5 | 0.35 | 0.175 | 0.5 | 0010HWa0016819732 | 7f7a4b69-a8bb-45a3-b6d6-f0093fb4d01a--16819732 | 0010Wal0016819889 | m³ | 7f7a4b69-a8bb-45a3-b6d6-f0093fb4d01a--16819889
 | Konstruksjoner i grunnen | Betong 350 mm | 0.0875 | 0.0875 | 0.25 | 0.25 | 0.5 | 0.35 | 0.175 | 0.5 | 0010HWa0016819726 | 7f7a4b69-a8bb-45a3-b6d6-f0093fb4d01a--16819726 | 0010Wal0016819887 | m³ | 7f7a4b69-a8bb-45a3-b6d6-f0093fb4d01a--16819887
 | Konstruksjoner i grunnen | Betong 350 mm | 0.0875 | 0.0875 | 0.25 | 0.25 | 0.5 | 0.35 | 0.175 | 0.5 | 0010HWa0016820421 | 7f7a4b69-a8bb-45a3-b6d6-f0093fb4d01a--16820421 | 0010Wal0016820432 | m³ | 7f7a4b69-a8bb-45a3-b6d6-f0093fb4d01a--16820432
 | Konstruksjoner i grunnen | Betong 350 mm | 0.0875 | 0.0875 | 0.25 | 0.25 | 0.5 | 0.35 | 0.175 | 0.5 | 0010HWa0016819751 | 7f7a4b69-a8bb-45a3-b6d6-f0093fb4d01a--16819751 | 0010Wal0016819840 | m³ | 7f7a4b69-a8bb-45a3-b6d6-f0093fb4d01a--16819840
 | Konstruksjoner i grunnen | Betong 350 mm | 0.0875 | 0.0875 | 0.25 | 0.25 | 0.5 | 0.35 | 0.175 | 0.5 | 0010HWa0779928879 | 7f7a4b69-a8bb-45a3-b6d6-f0093fb4d01a--779928879 | 0010Wal0779928888 | m³ | 7f7a4b69-a8bb-45a3-b6d6-f0093fb4d01a--779928888
 | Konstruksjoner i grunnen | Betong 350 mm | 0.0875 | 0.0875 | 0.25 | 0.25 | 0.5 | 0.35 | 0.175 | 0.5 | 0010HWa0016819859 | 7f7a4b69-a8bb-45a3-b6d6-f0093fb4d01a--16819859 | 0010Wal0016819879 | m³ | 7f7a4b69-a8bb-45a3-b6d6-f0093fb4d01a--16819879
 | Konstruksjoner i grunnen | Betong 350 mm | 0.0875 | 0.0875 | 0.25 | 0.25 | 0.5 | 0.35 | 0.175 | 0.5 | 0010HWa0779928906 | 7f7a4b69-a8bb-45a3-b6d6-f0093fb4d01a--779928906 | 0010Wal0779928914 | m³ | 7f7a4b69-a8bb-45a3-b6d6-f0093fb4d01a--779928914
 | Konstruksjoner i grunnen | Betong 350 mm | 0.0875 | 0.0875 | 0.25 | 0.25 | 0.5 | 0.35 | 0.175 | 0.5 | 0010HWa0779929319 | 7f7a4b69-a8bb-45a3-b6d6-f0093fb4d01a--779929319 | 0010Wal0779929321 | m³ | 7f7a4b69-a8bb-45a3-b6d6-f0093fb4d01a--779929321
 | Konstruksjoner i grunnen | Betong 350 mm | 0.0875 | 0.0875 | 0.25 | 0.25 | 0.5 | 0.35 | 0.175 | 0.5 | 0010HWa0779929345 | 7f7a4b69-a8bb-45a3-b6d6-f0093fb4d01a--779929345 | 0010Wal0779929347 | m³ | 7f7a4b69-a8bb-45a3-b6d6-f0093fb4d01a--779929347
 | Konstruksjoner i grunnen | Betong 350 mm | 0.0875 | 0.0875 | 0.25 | 0.25 | 0.5 | 0.35 | 0.175 | 0.5 | 0010HWa0779929372 | 7f7a4b69-a8bb-45a3-b6d6-f0093fb4d01a--779929372 | 0010Wal0779929374 | m³ | 7f7a4b69-a8bb-45a3-b6d6-f0093fb4d01a--779929374
 | Konstruksjoner i grunnen | Betong 350 mm | 0.0875 | 0.0875 | 0.25 | 0.25 | 0.5 | 0.35 | 0.175 | 0.5 | 0010HWa0779929382 | 7f7a4b69-a8bb-45a3-b6d6-f0093fb4d01a--779929382 | 0010Wal0779929384 | m³ | 7f7a4b69-a8bb-45a3-b6d6-f0093fb4d01a--779929384
 | Konstruksjoner i grunnen | Betong 350 mm | 0.0875 | 0.0875 | 0.25 | 0.25 | 0.5 | 0.35 | 0.175 | 0.5 | 0010HWa0779929392 | 7f7a4b69-a8bb-45a3-b6d6-f0093fb4d01a--779929392 | 0010Wal0779929394 | m³ | 7f7a4b69-a8bb-45a3-b6d6-f0093fb4d01a--779929394
 | Konstruksjoner i grunnen | Betong 350 mm | 0.0875 | 0.0875 | 0.25 | 0.25 | 0.5 | 0.35 | 0.175 | 0.5 | 0010HWa0779931389 | 7f7a4b69-a8bb-45a3-b6d6-f0093fb4d01a--779931389 | 0010Wal0779931391 | m³ | 7f7a4b69-a8bb-45a3-b6d6-f0093fb4d01a--779931391
 | Konstruksjoner i grunnen | Betong 350 mm | 0.0875 | 0.0875 | 0.25 | 0.25 | 0.5 | 0.35 | 0.175 | 0.5 | 0010HWa0779931408 | 7f7a4b69-a8bb-45a3-b6d6-f0093fb4d01a--779931408 | 0010Wal0779931410 | m³ | 7f7a4b69-a8bb-45a3-b6d6-f0093fb4d01a--779931410
 | Konstruksjoner i grunnen | Betong 350 mm | 0.0875 | 0.0875 | 0.25 | 0.25 | 0.5 | 0.35 | 0.175 | 0.5 | 0010HWa0779931419 | 7f7a4b69-a8bb-45a3-b6d6-f0093fb4d01a--779931419 | 0010Wal0779931421 | m³ | 7f7a4b69-a8bb-45a3-b6d6-f0093fb4d01a--779931421
 | Konstruksjoner i grunnen | Betong 350 mm | 0.0875 | 0.0875 | 0.25 | 0.25 | 0.5 | 0.35 | 0.175 | 0.5 | 0010HWa0779931430 | 7f7a4b69-a8bb-45a3-b6d6-f0093fb4d01a--779931430 | 0010Wal0779931432 | m³ | 7f7a4b69-a8bb-45a3-b6d6-f0093fb4d01a--779931432
 | Konstruksjoner i grunnen | Betong 350 mm | 0.07 | 0.07 | 0.2 | 0.2 | 0.4 | 0.35 | 0.14 | 0.5 | 0010HWa0016819730 | 7f7a4b69-a8bb-45a3-b6d6-f0093fb4d01a--16819730 | 0010Wal0016819885 | m³ | 7f7a4b69-a8bb-45a3-b6d6-f0093fb4d01a--16819885
 | Konstruksjoner i grunnen | Betong 350 mm | 0.06125 | 0.06125 | 0.175 | 0.175 | 0.35 | 0.35 | 0.1225 | 0.5 | 0010HWa0016819735 | 7f7a4b69-a8bb-45a3-b6d6-f0093fb4d01a--16819735 | 0010Wal0016819913 | m³ | 7f7a4b69-a8bb-45a3-b6d6-f0093fb4d01a--16819913 | Allplan Attributes - Object Layer Attributes #1, Material: Betong
 | Konstruksjoner i grunnen | Betong 350 mm | 0.06125 | 0.06125 | 0.175 | 0.175 | 0.35 | 0.35 | 0.1225 | 0.5 | 0010HWa0016819745 | 7f7a4b69-a8bb-45a3-b6d6-f0093fb4d01a--16819745 | 0010Wal0016819938 | m³ | 7f7a4b69-a8bb-45a3-b6d6-f0093fb4d01a--16819938
4 x  | Konstruksjoner i grunnen | Betong 150 mm, Betong 50 mm | 2.83675 | 2.83675 |  |  | 21.775 | 0.2 | 4.3625 | 0.6 | 0010HWa0016819712 | 7f7a4b69-a8bb-45a3-b6d6-f0093fb4d01a--16819712 | 0010Wal0016819960 | m³ | 7f7a4b69-a8bb-45a3-b6d6-f0093fb4d01a--16819960 | WallQuantities - GrossSideAreaRight: 15.295 m2; GrossSideAreaLeft: 10.85 m2; NetSideAreaRight: 15.295 m2; NetSideAreaLeft: 10.85 m2; Allplan Attributes - Object Layer Attributes #2, Allright_Comp_ID: 0010Wal0779929954; Object Layer Attributes #2, Building alteration category: New building; Object Layer Attributes #2, Unit: m²; Object Layer Attributes #2, NOI_UUID: 7f7a4b69-a8bb-45a3-b6d6-f0093fb4d01a--779929954; Object Layer Attributes #2, Trade: Ext. insulation finish systems
 | Konstruksjoner i grunnen | Betong 350 mm | 0.07 | 0.07 | 0.2 | 0.2 | 0.4 | 0.35 | 0.14 | 0.5 | 0010HWa0016819728 | 7f7a4b69-a8bb-45a3-b6d6-f0093fb4d01a--16819728 | 0010Wal0016819907 | m³ | 7f7a4b69-a8bb-45a3-b6d6-f0093fb4d01a--16819907
 | Konstruksjoner i grunnen | Betong 150 mm, Betong 50 mm | 3.94325 | 3.94325 |  |  | 30.225 | 0.2 | 6.0625 | 0.6 | 0010HWa0016819717 | 7f7a4b69-a8bb-45a3-b6d6-f0093fb4d01a--16819717 | 0010Wal0016819974 | m³ | 7f7a4b69-a8bb-45a3-b6d6-f0093fb4d01a--16819974 | WallQuantities - GrossSideAreaRight: 21.28 m2; GrossSideAreaLeft: 15.025 m2; NetSideAreaRight: 21.28 m2; NetSideAreaLeft: 15.025 m2; Allplan Attributes - Object Layer Attributes #2, Allright_Comp_ID: 0010Wal0779930305; Object Layer Attributes #2, Building alteration category: New building; Object Layer Attributes #2, Unit: m²; Object Layer Attributes #2, NOI_UUID: 7f7a4b69-a8bb-45a3-b6d6-f0093fb4d01a--779930305; Object Layer Attributes #2, Trade: Ext. insulation finish systems
 | Plan 1 | Paroc 200 200 mm | 9.76 | 9.3358 | 48.8 | 46.679 | 12.2 | 0.2 | 2.44 | 4 | 0013HWa0000000029 | d1eb0bd9-ddf6-4315-a806-967de25454b1--29 | 0013Wal0000000030 | m² | d1eb0bd9-ddf6-4315-a806-967de25454b1--30 | Allplan Attributes - Object Layer Attributes #1, Material: Paroc 200
 | Plan 1 | Paroc 200 200 mm | 7.92 | 7.4958 | 39.6 | 37.479 | 9.9 | 0.2 | 1.98 | 4 | 0013HWa0000000019 | d1eb0bd9-ddf6-4315-a806-967de25454b1--19 | 0013Wal0000000020 | m² | d1eb0bd9-ddf6-4315-a806-967de25454b1--20 | Allplan Attributes - Object Layer Attributes #1, Material: Paroc 200
 | Plan 1 | Paroc 200 200 mm | 7.76 | 4.624 | 38.8 | 23.12 | 9.7 | 0.2 | 1.94 | 4 | 0013HWa0779971036 | d1eb0bd9-ddf6-4315-a806-967de25454b1--779971036 | 0013Wal0779971142 | m² | d1eb0bd9-ddf6-4315-a806-967de25454b1--779971142 | Allplan Attributes - Object Layer Attributes #1, Material: Paroc 200
 | Plan 1 | Paroc 200 200 mm | 8.432 | 7.27538 | 42.16 | 36.3769 | 12.4 | 0.2 | 2.48 | 3.4 | 0013HWa0000000014 | d1eb0bd9-ddf6-4315-a806-967de25454b1--14 | 0013Wal0000000015 | m² | d1eb0bd9-ddf6-4315-a806-967de25454b1--15
 | Plan 1 | Lekter 46 mm, Kledning 19 mm | 1.04167 | 0.890157 |  |  | 4.723 | 0.065 | 0.306374 | 3.4 | 0013HWa0779992914 | d1eb0bd9-ddf6-4315-a806-967de25454b1--779992914 | 0013Wal0779992915 | m² | d1eb0bd9-ddf6-4315-a806-967de25454b1--779992915 | Allplan Attributes - Object Layer Attributes #1, Material: Lekter; Object Layer Attributes #2, Allright_Comp_ID: 0013Wal0779992916; Object Layer Attributes #2, Building alteration category: New building; Object Layer Attributes #2, Unit: m²; Object Layer Attributes #2, Material: Kledning; Object Layer Attributes #2, NOI_UUID: d1eb0bd9-ddf6-4315-a806-967de25454b1--779992916; Object Layer Attributes #2, Trade: Ext. insulation finish systems; WallQuantities - GrossSideAreaRight: 15.98 m2; GrossSideAreaLeft: 16.1364 m2; NetSideAreaRight: 13.649 m2; NetSideAreaLeft: 13.8054 m2
 | Plan 1 | Lekter 46 mm, Kledning 19 mm | 0.0471716 | 0.0471716 |  |  | 0.223 | 0.065 | 0.013874 | 3.4 | 0013HWa0779993006 | d1eb0bd9-ddf6-4315-a806-967de25454b1--779993006 | 0013Wal0779993007 | m² | d1eb0bd9-ddf6-4315-a806-967de25454b1--779993007 | WallQuantities - GrossSideAreaRight: 0.68 m2; GrossSideAreaLeft: 0.8364 m2; NetSideAreaRight: 0.68 m2; NetSideAreaLeft: 0.8364 m2; Allplan Attributes - Object Layer Attributes #2, Allright_Comp_ID: 0013Wal0779993008; Object Layer Attributes #2, Building alteration category: New building; Object Layer Attributes #2, Unit: m²; Object Layer Attributes #2, NOI_UUID: d1eb0bd9-ddf6-4315-a806-967de25454b1--779993008; Object Layer Attributes #2, Trade: Ext. insulation finish systems
 | Plan 1 | Lekter 46 mm, Kledning 19 mm | 0.660028 | 0.660028 |  |  | 2.9905 | 0.065 | 0.194126 | 3.4 | 0013HWa0779992815 | d1eb0bd9-ddf6-4315-a806-967de25454b1--779992815 | 0013Wal0779992827 | m² | d1eb0bd9-ddf6-4315-a806-967de25454b1--779992827 | WallQuantities - GrossSideAreaRight: 10.1354 m2; GrossSideAreaLeft: 10.2 m2; NetSideAreaRight: 10.1354 m2; NetSideAreaLeft: 10.2 m2; Allplan Attributes - Object Layer Attributes #2, Allright_Comp_ID: 0013Wal0779992830; Object Layer Attributes #2, Building alteration category: New building; Object Layer Attributes #2, Unit: m²; Object Layer Attributes #2, NOI_UUID: d1eb0bd9-ddf6-4315-a806-967de25454b1--779992830; Object Layer Attributes #2, Trade: Ext. insulation finish systems
 | Plan 1 | Lekter 46 mm, Kledning 19 mm | 0.71383 | 0.575965 |  |  | 3.23 | 0.065 | 0.20995 | 3.4 | 0013HWa0779993165 | d1eb0bd9-ddf6-4315-a806-967de25454b1--779993165 | 0013Wal0779993166 | m² | d1eb0bd9-ddf6-4315-a806-967de25454b1--779993166 | WallQuantities - GrossSideAreaRight: 10.982 m2; GrossSideAreaLeft: 10.982 m2; NetSideAreaRight: 8.861 m2; NetSideAreaLeft: 8.861 m2; Allplan Attributes - Object Layer Attributes #2, Allright_Comp_ID: 0013Wal0779993167; Object Layer Attributes #2, Building alteration category: New building; Object Layer Attributes #2, Unit: m²; Object Layer Attributes #2, NOI_UUID: d1eb0bd9-ddf6-4315-a806-967de25454b1--779993167; Object Layer Attributes #2, Trade: Ext. insulation finish systems
 | Plan 1 | Lekter 46 mm, Kledning 19 mm | 0.663 | 0.663 |  |  | 3 | 0.065 | 0.195 | 3.4 | 0013HWa0779993389 | d1eb0bd9-ddf6-4315-a806-967de25454b1--779993389 | 0013Wal0779993390 | m² | d1eb0bd9-ddf6-4315-a806-967de25454b1--779993390 | WallQuantities - GrossSideAreaRight: 10.2 m2; GrossSideAreaLeft: 10.2 m2; NetSideAreaRight: 10.2 m2; NetSideAreaLeft: 10.2 m2; Allplan Attributes - Object Layer Attributes #2, Allright_Comp_ID: 0013Wal0779993391; Object Layer Attributes #2, Building alteration category: New building; Object Layer Attributes #2, Unit: m²; Object Layer Attributes #2, NOI_UUID: d1eb0bd9-ddf6-4315-a806-967de25454b1--779993391; Object Layer Attributes #2, Trade: Ext. insulation finish systems
 | Plan 1 | Paroc 200 200 mm | 13.804 | 12.9735 | 69.02 | 64.8677 | 20.3 | 0.2 | 4.06 | 3.4 | 0013HWa0779971208 | d1eb0bd9-ddf6-4315-a806-967de25454b1--779971208 | 0013Wal0779971234 | m² | d1eb0bd9-ddf6-4315-a806-967de25454b1--779971234
 | Plan 1 | Lekter 46 mm, Kledning 19 mm | 1.18269 | 1.04483 |  |  | 5.3555 | 0.065 | 0.347851 | 3.4 | 0013HWa0779992958 | d1eb0bd9-ddf6-4315-a806-967de25454b1--779992958 | 0013Wal0779992959 | m² | d1eb0bd9-ddf6-4315-a806-967de25454b1--779992959 | WallQuantities - GrossSideAreaRight: 18.1764 m2; GrossSideAreaLeft: 18.241 m2; NetSideAreaRight: 16.0554 m2; NetSideAreaLeft: 16.12 m2; Allplan Attributes - Object Layer Attributes #2, Allright_Comp_ID: 0013Wal0779992960; Object Layer Attributes #2, Building alteration category: New building; Object Layer Attributes #2, Unit: m²; Object Layer Attributes #2, NOI_UUID: d1eb0bd9-ddf6-4315-a806-967de25454b1--779992960; Object Layer Attributes #2, Trade: Ext. insulation finish systems
Port01 | Plan 1 | Port 50 mm | 0.406 | 0.406 | 8.12 | 8.12 | 2.8 | 0.05 | 0.14 | 2.9 | 0013HWa0780004721 | d1eb0bd9-ddf6-4315-a806-967de25454b1--780004721 | 0013Wal0780004722 | m² | d1eb0bd9-ddf6-4315-a806-967de25454b1--780004722 | Allplan Attributes - Object Layer Attributes #1, Material: Port; Name: Port01; Object Layer Attributes #1, Hatching in plan: 1
Port01 | Plan 1 | Port 50 mm | 0.406 | 0.406 | 8.12 | 8.12 | 2.8 | 0.05 | 0.14 | 2.9 | 0013HWa0780004780 | d1eb0bd9-ddf6-4315-a806-967de25454b1--780004780 | 0013Wal0780004782 | m² | d1eb0bd9-ddf6-4315-a806-967de25454b1--780004782
 | Plan 1 | Paroc 200 200 mm | 13.804 | 9.97974 | 69.02 | 49.8987 | 20.3 | 0.2 | 4.06 | 3.4 | 0013HWa0000000041 | d1eb0bd9-ddf6-4315-a806-967de25454b1--41 | 0013Wal0000000042 | m² | d1eb0bd9-ddf6-4315-a806-967de25454b1--42
Port01 | Plan 1 | Port 50 mm | 0.406 | 0.406 | 8.12 | 8.12 | 2.8 | 0.05 | 0.14 | 2.9 | 0013HWa0780004793 | d1eb0bd9-ddf6-4315-a806-967de25454b1--780004793 | 0013Wal0780004801 | m² | d1eb0bd9-ddf6-4315-a806-967de25454b1--780004801
 | Plan 1 | gips 13 mm, riegel stål 100 100 mm, gips 13 mm | 4.67321 | 4.40597 |  |  | 11.7 | 0.126 | 1.4742 | 3.17 | 0014HWa0779979785 | b4870d4d-918a-46e5-81bc-d8f6664cc458--779979785 | 0014Wal0779979851 | m³ | b4870d4d-918a-46e5-81bc-d8f6664cc458--779979851 | WallQuantities - GrossSideAreaRight: 37.089 m2; GrossSideAreaLeft: 37.089 m2; NetSideAreaRight: 34.968 m2; NetSideAreaLeft: 34.968 m2; Allplan Attributes - Object Layer Attributes #2, Allright_Comp_ID: 0014Wal0779979854; Object Layer Attributes #2, Building alteration category: New building; Object Layer Attributes #2, Unit: m³; Object Layer Attributes #2, NOI_UUID: b4870d4d-918a-46e5-81bc-d8f6664cc458--779979854; Object Layer Attributes #3, Allright_Comp_ID: 0014Wal0779979857; Object Layer Attributes #3, Building alteration category: New building; Object Layer Attributes #3, Unit: m³; Object Layer Attributes #3, NOI_UUID: b4870d4d-918a-46e5-81bc-d8f6664cc458--779979857
 | Plan 1 | gips 13 mm, riegel stål 100 150 mm, gips 13 mm | 1.52649 | 1.52649 |  |  | 2.73267 | 0.176 | 0.481543 | 3.17 | 0014HWa0779969862 | b4870d4d-918a-46e5-81bc-d8f6664cc458--779969862 | 0014Wal0779969959 | m² | b4870d4d-918a-46e5-81bc-d8f6664cc458--779969959 | WallQuantities - GrossSideAreaRight: 8.63508 m2; GrossSideAreaLeft: 8.67629 m2; NetSideAreaRight: 8.63508 m2; NetSideAreaLeft: 8.67629 m2; Allplan Attributes - Object Layer Attributes #2, Allright_Comp_ID: 0014Wal0779969961; Object Layer Attributes #2, Building alteration category: New building; Object Layer Attributes #2, Unit: m²; Object Layer Attributes #2, NOI_UUID: b4870d4d-918a-46e5-81bc-d8f6664cc458--779969961; Object Layer Attributes #3, Allright_Comp_ID: 0014Wal0779969963; Object Layer Attributes #3, Building alteration category: New building; Object Layer Attributes #3, Unit: m²; Object Layer Attributes #3, NOI_UUID: b4870d4d-918a-46e5-81bc-d8f6664cc458--779969963
 | Plan 1 | gips 13 mm, riegel stål 100 150 mm, gips 13 mm | 3.52882 | 3.52882 |  |  | 6.32833 | 0.176 | 1.11319 | 3.17 | 0014HWa0779974019 | b4870d4d-918a-46e5-81bc-d8f6664cc458--779974019 | 0014Wal0779974020 | m³ | b4870d4d-918a-46e5-81bc-d8f6664cc458--779974020 | WallQuantities - GrossSideAreaRight: 20.0883 m2; GrossSideAreaLeft: 20.0471 m2; NetSideAreaRight: 20.0883 m2; NetSideAreaLeft: 20.0471 m2; Allplan Attributes - Object Layer Attributes #2, Allright_Comp_ID: 0014Wal0779974021; Object Layer Attributes #2, Building alteration category: New building; Object Layer Attributes #2, Unit: m³; Object Layer Attributes #2, NOI_UUID: b4870d4d-918a-46e5-81bc-d8f6664cc458--779974021; Object Layer Attributes #3, Allright_Comp_ID: 0014Wal0779974022; Object Layer Attributes #3, Building alteration category: New building; Object Layer Attributes #3, Unit: m³; Object Layer Attributes #3, NOI_UUID: b4870d4d-918a-46e5-81bc-d8f6664cc458--779974022
 | Plan 1 | gips 13 mm, riegel stål 100 150 mm, gips 13 mm | 5.16389 | 4.7906 |  |  | 9.22967 | 0.176 | 1.62899 | 3.17 | 0014HWa0779970465 | b4870d4d-918a-46e5-81bc-d8f6664cc458--779970465 | 0014Wal0779970466 | m³ | b4870d4d-918a-46e5-81bc-d8f6664cc458--779970466 | WallQuantities - GrossSideAreaRight: 29.3637 m2; GrossSideAreaLeft: 29.0467 m2; NetSideAreaRight: 27.2427 m2; NetSideAreaLeft: 26.9257 m2; Allplan Attributes - Object Layer Attributes #2, Allright_Comp_ID: 0014Wal0779970467; Object Layer Attributes #2, Building alteration category: New building; Object Layer Attributes #2, Unit: m³; Object Layer Attributes #2, NOI_UUID: b4870d4d-918a-46e5-81bc-d8f6664cc458--779970467; Object Layer Attributes #3, Allright_Comp_ID: 0014Wal0779970468; Object Layer Attributes #3, Building alteration category: New building; Object Layer Attributes #3, Unit: m³; Object Layer Attributes #3, NOI_UUID: b4870d4d-918a-46e5-81bc-d8f6664cc458--779970468
 | Plan 1 | gips 13 mm, bindingsverk 198 198 mm, gips 13 mm | 1.27672 | 1.27672 |  |  | 1.798 | 0.224 | 0.402752 | 3.17 | 0014HWa0779974319 | b4870d4d-918a-46e5-81bc-d8f6664cc458--779974319 | 0014Wal0779974323 | m² | b4870d4d-918a-46e5-81bc-d8f6664cc458--779974323 | WallQuantities - GrossSideAreaRight: 5.69966 m2; GrossSideAreaLeft: 5.69966 m2; NetSideAreaRight: 5.69966 m2; NetSideAreaLeft: 5.69966 m2; Allplan Attributes - Object Layer Attributes #2, Allright_Comp_ID: 0014Wal0779974322; Object Layer Attributes #2, Building alteration category: New building; Object Layer Attributes #2, Unit: m²; Object Layer Attributes #2, NOI_UUID: b4870d4d-918a-46e5-81bc-d8f6664cc458--779974322; Object Layer Attributes #3, Allright_Comp_ID: 0014Wal0779974321; Object Layer Attributes #3, Building alteration category: New building; Object Layer Attributes #3, Unit: m²; Object Layer Attributes #3, NOI_UUID: b4870d4d-918a-46e5-81bc-d8f6664cc458--779974321
 | Plan 1 | gips 13 mm, riegel stål 100 150 mm, gips 13 mm | 6.6868 | 5.90325 |  |  | 11.9333 | 0.176 | 2.1094 | 3.17 | 0014HWa0779974008 | b4870d4d-918a-46e5-81bc-d8f6664cc458--779974008 | 0014Wal0779974009 | m³ | b4870d4d-918a-46e5-81bc-d8f6664cc458--779974009 | WallQuantities - GrossSideAreaRight: 37.406 m2; GrossSideAreaLeft: 38.04 m2; NetSideAreaRight: 32.954 m2; NetSideAreaLeft: 33.588 m2; Allplan Attributes - Object Layer Attributes #2, Allright_Comp_ID: 0014Wal0779974010; Object Layer Attributes #2, Building alteration category: New building; Object Layer Attributes #2, Unit: m³; Object Layer Attributes #2, NOI_UUID: b4870d4d-918a-46e5-81bc-d8f6664cc458--779974010; Object Layer Attributes #3, Allright_Comp_ID: 0014Wal0779974011; Object Layer Attributes #3, Building alteration category: New building; Object Layer Attributes #3, Unit: m³; Object Layer Attributes #3, NOI_UUID: b4870d4d-918a-46e5-81bc-d8f6664cc458--779974011
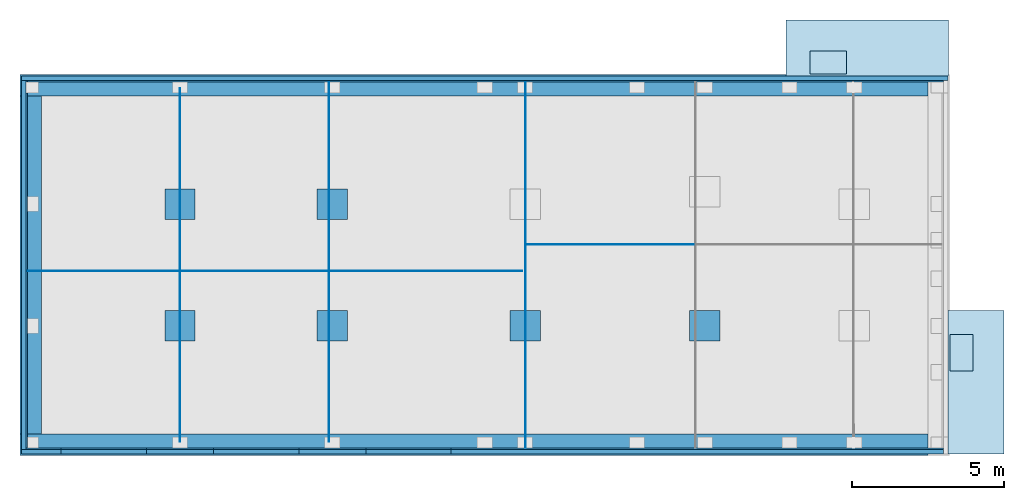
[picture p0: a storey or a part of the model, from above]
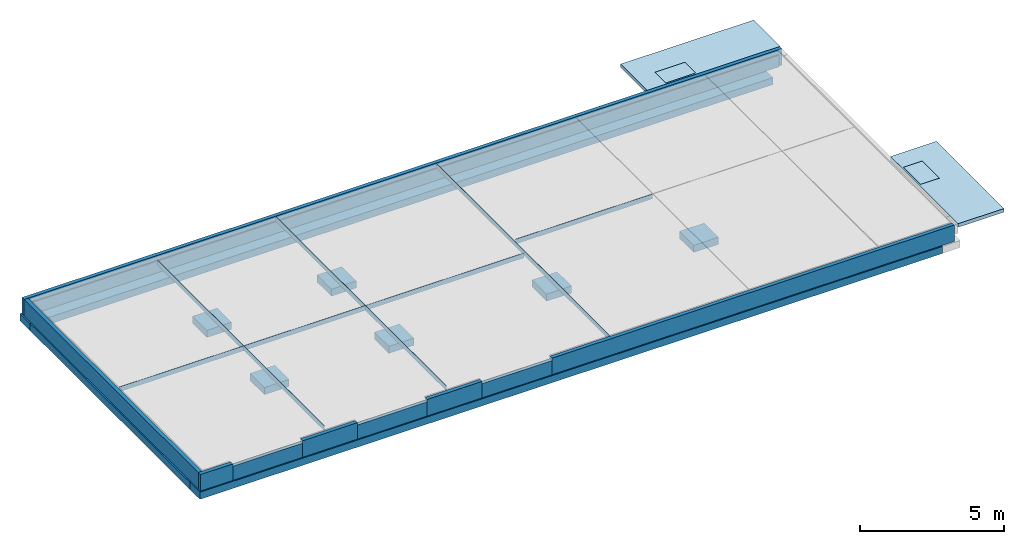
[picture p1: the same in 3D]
Properties of the parts of a building model (IFC2X3), part 6 of 7

# IfcWallStandardCase (167)
Name | In | Material | GrossVolume (m3) | NetVolume (m3) | GrossSideArea (m2) | NetSideArea (m2) | NominalLength (m) | NominalWidth (m) | GrossFootprintArea (m2) | NominalHeight (m) | Allright_Comp_ID | NOI_UUID | Object Layer Attributes #1, Allright_Comp_ID | Object Layer Attributes #1, Unit | Object Layer Attributes #1, NOI_UUID
 | Plan 1 | gips 13 mm, riegel stål 100 100 mm, gips 13 mm | 1.16218 | 0.920243 |  |  | 2.90667 | 0.126 | 0.366617 | 3.17 | 0014HWa0779979807 | b4870d4d-918a-46e5-81bc-d8f6664cc458--779979807 | 0014Wal0779979828 | m³ | b4870d4d-918a-46e5-81bc-d8f6664cc458--779979828 | Allplan Attributes - Object Layer Attributes #1, Material: gips; Object Layer Attributes #2, Allright_Comp_ID: 0014Wal0779979831; Object Layer Attributes #2, Building alteration category: New building; Object Layer Attributes #2, Unit: m³; Object Layer Attributes #2, Material: riegel stål 100; Object Layer Attributes #2, NOI_UUID: b4870d4d-918a-46e5-81bc-d8f6664cc458--779979831; Object Layer Attributes #3, Allright_Comp_ID: 0014Wal0779979834; Object Layer Attributes #3, Building alteration category: New building; Object Layer Attributes #3, Unit: m³; Object Layer Attributes #3, NOI_UUID: b4870d4d-918a-46e5-81bc-d8f6664cc458--779979834; Object Layer Attributes #3, Material: gips; WallQuantities - GrossSideAreaRight: 9.18666 m2; GrossSideAreaLeft: 9.22787 m2; NetSideAreaRight: 7.26656 m2; NetSideAreaLeft: 7.30777 m2
2 x  | Plan 1 | gips 13 mm, riegel stål 100 100 mm, gips 13 mm | 2.29404 | 1.54408 |  |  | 5.73744 | 0.126 | 0.723672 | 3.17 | 0014HWa0779974058 | b4870d4d-918a-46e5-81bc-d8f6664cc458--779974058 | 0014Wal0779974059 | m² | b4870d4d-918a-46e5-81bc-d8f6664cc458--779974059 | WallQuantities - GrossSideAreaRight: 18.174 m2; GrossSideAreaLeft: 18.174 m2; NetSideAreaRight: 12.2219 m2; NetSideAreaLeft: 12.2219 m2; Allplan Attributes - Object Layer Attributes #2, Allright_Comp_ID: 0014Wal0779974060; Object Layer Attributes #2, Building alteration category: New building; Object Layer Attributes #2, Unit: m²; Object Layer Attributes #2, NOI_UUID: b4870d4d-918a-46e5-81bc-d8f6664cc458--779974060; Object Layer Attributes #3, Allright_Comp_ID: 0014Wal0779974061; Object Layer Attributes #3, Building alteration category: New building; Object Layer Attributes #3, Unit: m²; Object Layer Attributes #3, NOI_UUID: b4870d4d-918a-46e5-81bc-d8f6664cc458--779974061
 | Plan 1 | gips 13 mm, riegel stål 100 100 mm, gips 13 mm | 0.995718 | 0.995718 |  |  | 2.47289 | 0.126 | 0.314107 | 3.17 | 0014HWa0779979808 | b4870d4d-918a-46e5-81bc-d8f6664cc458--779979808 | 0014Wal0779979816 | m³ | b4870d4d-918a-46e5-81bc-d8f6664cc458--779979816 | WallQuantities - GrossSideAreaRight: 7.97219 m2; GrossSideAreaLeft: 7.61398 m2; NetSideAreaRight: 7.97219 m2; NetSideAreaLeft: 7.61398 m2; Allplan Attributes - Object Layer Attributes #2, Allright_Comp_ID: 0014Wal0779979814; Object Layer Attributes #2, Building alteration category: New building; Object Layer Attributes #2, Unit: m³; Object Layer Attributes #2, NOI_UUID: b4870d4d-918a-46e5-81bc-d8f6664cc458--779979814; Object Layer Attributes #3, Allright_Comp_ID: 0014Wal0779979812; Object Layer Attributes #3, Building alteration category: New building; Object Layer Attributes #3, Unit: m³; Object Layer Attributes #3, NOI_UUID: b4870d4d-918a-46e5-81bc-d8f6664cc458--779979812
 | Plan 1 | gips 13 mm, riegel stål 100 100 mm, gips 13 mm | 1.12295 | 1.12295 |  |  | 2.81146 | 0.126 | 0.354244 | 3.17 | 0014HWa0779968404 | b4870d4d-918a-46e5-81bc-d8f6664cc458--779968404 | 0014Wal0779968405 | m³ | b4870d4d-918a-46e5-81bc-d8f6664cc458--779968405 | WallQuantities - GrossSideAreaRight: 8.91234 m2; GrossSideAreaLeft: 8.91234 m2; NetSideAreaRight: 8.91234 m2; NetSideAreaLeft: 8.91234 m2; Allplan Attributes - Object Layer Attributes #2, Allright_Comp_ID: 0014Wal0779968406; Object Layer Attributes #2, Building alteration category: New building; Object Layer Attributes #2, Unit: m³; Object Layer Attributes #2, NOI_UUID: b4870d4d-918a-46e5-81bc-d8f6664cc458--779968406; Object Layer Attributes #3, Allright_Comp_ID: 0014Wal0779968407; Object Layer Attributes #3, Building alteration category: New building; Object Layer Attributes #3, Unit: m³; Object Layer Attributes #3, NOI_UUID: b4870d4d-918a-46e5-81bc-d8f6664cc458--779968407
 | Plan 1 | gips 14.4136 mm, riegel stål 100 99.6829 mm, gips 13.0369 mm | 0.774674 | 0.504828 |  |  | 1.90907 | 0.12713 | 0.244377 | 3.17 | 0014HWa0779979745 | b4870d4d-918a-46e5-81bc-d8f6664cc458--779979745 | 0014Wal0779979761 | m² | b4870d4d-918a-46e5-81bc-d8f6664cc458--779979761 | WallQuantities - GrossSideAreaRight: 5.94145 m2; GrossSideAreaLeft: 6.09915 m2; NetSideAreaRight: 3.97808 m2; NetSideAreaLeft: 3.97809 m2; Allplan Attributes - Object Layer Attributes #2, Allright_Comp_ID: 0014Wal0779979764; Object Layer Attributes #2, Building alteration category: New building; Object Layer Attributes #2, Unit: m²; Object Layer Attributes #2, NOI_UUID: b4870d4d-918a-46e5-81bc-d8f6664cc458--779979764; Object Layer Attributes #3, Allright_Comp_ID: 0014Wal0779979767; Object Layer Attributes #3, Building alteration category: New building; Object Layer Attributes #3, Unit: m²; Object Layer Attributes #3, NOI_UUID: b4870d4d-918a-46e5-81bc-d8f6664cc458--779979767
 | Plan 1 | gips 13 mm, riegel stål 100 100 mm, gips 13 mm | 1.03688 | 0.769639 |  |  | 2.616 | 0.126 | 0.327093 | 3.17 | 0014HWa0779979746 | b4870d4d-918a-46e5-81bc-d8f6664cc458--779979746 | 0014Wal0779979875 | m² | b4870d4d-918a-46e5-81bc-d8f6664cc458--779979875 | WallQuantities - GrossSideAreaRight: 8.51779 m2; GrossSideAreaLeft: 8.15958 m2; NetSideAreaRight: 6.39679 m2; NetSideAreaLeft: 6.03858 m2; Allplan Attributes - Object Layer Attributes #2, Allright_Comp_ID: 0014Wal0779979878; Object Layer Attributes #2, Building alteration category: New building; Object Layer Attributes #2, Unit: m²; Object Layer Attributes #2, NOI_UUID: b4870d4d-918a-46e5-81bc-d8f6664cc458--779979878; Object Layer Attributes #3, Allright_Comp_ID: 0014Wal0779979881; Object Layer Attributes #3, Building alteration category: New building; Object Layer Attributes #3, Unit: m²; Object Layer Attributes #3, NOI_UUID: b4870d4d-918a-46e5-81bc-d8f6664cc458--779979881
 | Plan 1 | gips 13 mm, riegel stål 100 100 mm, gips 13 mm | 0.639072 | 0.639072 |  |  | 1.6 | 0.126 | 0.2016 | 3.17 | 0014HWa0779969833 | b4870d4d-918a-46e5-81bc-d8f6664cc458--779969833 | 0014Wal0779969954 | m² | b4870d4d-918a-46e5-81bc-d8f6664cc458--779969954 | WallQuantities - GrossSideAreaRight: 5.072 m2; GrossSideAreaLeft: 5.072 m2; NetSideAreaRight: 5.072 m2; NetSideAreaLeft: 5.072 m2; Allplan Attributes - Object Layer Attributes #2, Allright_Comp_ID: 0014Wal0779969957; Object Layer Attributes #2, Building alteration category: New building; Object Layer Attributes #2, Unit: m²; Object Layer Attributes #2, NOI_UUID: b4870d4d-918a-46e5-81bc-d8f6664cc458--779969957; Object Layer Attributes #3, Allright_Comp_ID: 0014Wal0779969990; Object Layer Attributes #3, Building alteration category: New building; Object Layer Attributes #3, Unit: m²; Object Layer Attributes #3, NOI_UUID: b4870d4d-918a-46e5-81bc-d8f6664cc458--779969990
 | Plan 1 | gips 13 mm, bindingsverk 198 198 mm, gips 13 mm | 1.04666 | 1.04666 |  |  | 1.474 | 0.224 | 0.330176 | 3.17 | 0014HWa0779969828 | b4870d4d-918a-46e5-81bc-d8f6664cc458--779969828 | 0014Wal0779969942 | m² | b4870d4d-918a-46e5-81bc-d8f6664cc458--779969942 | WallQuantities - GrossSideAreaRight: 4.67258 m2; GrossSideAreaLeft: 4.67258 m2; NetSideAreaRight: 4.67258 m2; NetSideAreaLeft: 4.67258 m2; Allplan Attributes - Object Layer Attributes #2, Allright_Comp_ID: 0014Wal0779969944; Object Layer Attributes #2, Building alteration category: New building; Object Layer Attributes #2, Unit: m²; Object Layer Attributes #2, NOI_UUID: b4870d4d-918a-46e5-81bc-d8f6664cc458--779969944; Object Layer Attributes #3, Allright_Comp_ID: 0014Wal0779969946; Object Layer Attributes #3, Building alteration category: New building; Object Layer Attributes #3, Unit: m²; Object Layer Attributes #3, NOI_UUID: b4870d4d-918a-46e5-81bc-d8f6664cc458--779969946
 | Plan 1 | gips 13 mm, riegel stål 100 100 mm, gips 13 mm | 0.492475 | 0.492475 |  |  | 1.253 | 0.126 | 0.155355 | 3.17 | 0014HWa0780022269 | b4870d4d-918a-46e5-81bc-d8f6664cc458--780022269 | 0014Wal0780022270 | m³ | b4870d4d-918a-46e5-81bc-d8f6664cc458--780022270 | WallQuantities - GrossSideAreaRight: 3.83887 m2; GrossSideAreaLeft: 4.19708 m2; NetSideAreaRight: 3.83887 m2; NetSideAreaLeft: 4.19708 m2; Allplan Attributes - Object Layer Attributes #2, Allright_Comp_ID: 0014Wal0780022271; Object Layer Attributes #2, Building alteration category: New building; Object Layer Attributes #2, Unit: m³; Object Layer Attributes #2, NOI_UUID: b4870d4d-918a-46e5-81bc-d8f6664cc458--780022271; Object Layer Attributes #3, Allright_Comp_ID: 0014Wal0780022272; Object Layer Attributes #3, Building alteration category: New building; Object Layer Attributes #3, Unit: m³; Object Layer Attributes #3, NOI_UUID: b4870d4d-918a-46e5-81bc-d8f6664cc458--780022272
 | Plan 1 | gips 13 mm, riegel stål 100 100 mm, gips 13 mm | 1.43111 | 1.16651 |  |  | 3.603 | 0.126 | 0.451455 | 3.17 | 0014HWa0779967750 | b4870d4d-918a-46e5-81bc-d8f6664cc458--779967750 | 0014Wal0779967754 | m³ | b4870d4d-918a-46e5-81bc-d8f6664cc458--779967754 | WallQuantities - GrossSideAreaRight: 11.2884 m2; GrossSideAreaLeft: 11.6466 m2; NetSideAreaRight: 9.18837 m2; NetSideAreaLeft: 9.54658 m2; Allplan Attributes - Object Layer Attributes #2, Allright_Comp_ID: 0014Wal0779967753; Object Layer Attributes #2, Building alteration category: New building; Object Layer Attributes #2, Unit: m³; Object Layer Attributes #2, NOI_UUID: b4870d4d-918a-46e5-81bc-d8f6664cc458--779967753; Object Layer Attributes #3, Allright_Comp_ID: 0014Wal0779967752; Object Layer Attributes #3, Building alteration category: New building; Object Layer Attributes #3, Unit: m³; Object Layer Attributes #3, NOI_UUID: b4870d4d-918a-46e5-81bc-d8f6664cc458--779967752
 | Plan 1 | gips 13 mm, riegel stål 100 100 mm, gips 13 mm | 0.935052 | 0.935052 |  |  | 2.321 | 0.126 | 0.294969 | 3.17 | 0014HWa0779969441 | b4870d4d-918a-46e5-81bc-d8f6664cc458--779969441 | 0014Wal0779969442 | m³ | b4870d4d-918a-46e5-81bc-d8f6664cc458--779969442 | WallQuantities - GrossSideAreaRight: 7.49071 m2; GrossSideAreaLeft: 7.1325 m2; NetSideAreaRight: 7.49071 m2; NetSideAreaLeft: 7.1325 m2; Allplan Attributes - Object Layer Attributes #2, Allright_Comp_ID: 0014Wal0779969443; Object Layer Attributes #2, Building alteration category: New building; Object Layer Attributes #2, Unit: m³; Object Layer Attributes #2, NOI_UUID: b4870d4d-918a-46e5-81bc-d8f6664cc458--779969443; Object Layer Attributes #3, Allright_Comp_ID: 0014Wal0779969444; Object Layer Attributes #3, Building alteration category: New building; Object Layer Attributes #3, Unit: m³; Object Layer Attributes #3, NOI_UUID: b4870d4d-918a-46e5-81bc-d8f6664cc458--779969444
 | Plan 1 | gips 13 mm, riegel stål 100 100 mm, gips 13 mm | 1.77437 | 1.53243 |  |  | 4.39333 | 0.126 | 0.559737 | 3.17 | 0014HWa0779971191 | b4870d4d-918a-46e5-81bc-d8f6664cc458--779971191 | 0014Wal0779971268 | m² | b4870d4d-918a-46e5-81bc-d8f6664cc458--779971268 | WallQuantities - GrossSideAreaRight: 13.7937 m2; GrossSideAreaLeft: 13.8349 m2; NetSideAreaRight: 11.8736 m2; NetSideAreaLeft: 11.9148 m2; Allplan Attributes - Object Layer Attributes #2, Allright_Comp_ID: 0014Wal0779971265; Object Layer Attributes #2, Building alteration category: New building; Object Layer Attributes #2, Unit: m²; Object Layer Attributes #2, NOI_UUID: b4870d4d-918a-46e5-81bc-d8f6664cc458--779971265; Object Layer Attributes #3, Allright_Comp_ID: 0014Wal0779971266; Object Layer Attributes #3, Building alteration category: New building; Object Layer Attributes #3, Unit: m²; Object Layer Attributes #3, NOI_UUID: b4870d4d-918a-46e5-81bc-d8f6664cc458--779971266
 | Plan 1 | gips 13 mm, bindingsverk 198 198 mm, gips 13 mm | 0.859907 | 0.859907 |  |  | 1.211 | 0.224 | 0.271264 | 3.17 | 0014HWa0779971212 | b4870d4d-918a-46e5-81bc-d8f6664cc458--779971212 | 0014Wal0779971256 | m² | b4870d4d-918a-46e5-81bc-d8f6664cc458--779971256 | Allplan Attributes - Object Layer Attributes #1, Material: gips; Object Layer Attributes #2, Allright_Comp_ID: 0014Wal0779971255; Object Layer Attributes #2, Building alteration category: New building; Object Layer Attributes #2, Unit: m²; Object Layer Attributes #2, Material: bindingsverk 198; Object Layer Attributes #2, NOI_UUID: b4870d4d-918a-46e5-81bc-d8f6664cc458--779971255; Object Layer Attributes #3, Allright_Comp_ID: 0014Wal0779971254; Object Layer Attributes #3, Building alteration category: New building; Object Layer Attributes #3, Unit: m²; Object Layer Attributes #3, NOI_UUID: b4870d4d-918a-46e5-81bc-d8f6664cc458--779971254; Object Layer Attributes #3, Material: gips; WallQuantities - GrossSideAreaRight: 3.83887 m2; GrossSideAreaLeft: 3.83887 m2; NetSideAreaRight: 3.83887 m2; NetSideAreaLeft: 3.83887 m2
2 x  | Plan 1 | gips 13 mm, riegel stål 100 100 mm, gips 13 mm | 2.78896 | 2.01241 |  |  | 6.98254 | 0.126 | 0.8798 | 3.17 | 0014HWa0779969296 | b4870d4d-918a-46e5-81bc-d8f6664cc458--779969296 | 0014Wal0779969297 | m³ | b4870d4d-918a-46e5-81bc-d8f6664cc458--779969297 | WallQuantities - GrossSideAreaRight: 22.4929 m2; GrossSideAreaLeft: 21.7764 m2; NetSideAreaRight: 16.3298 m2; NetSideAreaLeft: 15.6133 m2; Allplan Attributes - Object Layer Attributes #2, Allright_Comp_ID: 0014Wal0779969298; Object Layer Attributes #2, Building alteration category: New building; Object Layer Attributes #2, Unit: m³; Object Layer Attributes #2, NOI_UUID: b4870d4d-918a-46e5-81bc-d8f6664cc458--779969298; Object Layer Attributes #3, Allright_Comp_ID: 0014Wal0779969299; Object Layer Attributes #3, Building alteration category: New building; Object Layer Attributes #3, Unit: m³; Object Layer Attributes #3, NOI_UUID: b4870d4d-918a-46e5-81bc-d8f6664cc458--779969299
 | Plan 1 | gips 12.9624 mm, riegel stål 100 100 mm, gips 13.4728 mm | 1.49574 | 1.22736 |  |  | 3.74938 | 0.12643 | 0.471841 | 3.17 | 0014HWa0779969814 | b4870d4d-918a-46e5-81bc-d8f6664cc458--779969814 | 0014Wal0779969996 | m² | b4870d4d-918a-46e5-81bc-d8f6664cc458--779969996 | WallQuantities - GrossSideAreaRight: 11.7679 m2; GrossSideAreaLeft: 12.0849 m2; NetSideAreaRight: 9.63682 m2; NetSideAreaLeft: 9.95381 m2; Allplan Attributes - Object Layer Attributes #2, Allright_Comp_ID: 0014Wal0779969993; Object Layer Attributes #2, Building alteration category: New building; Object Layer Attributes #2, Unit: m²; Object Layer Attributes #2, NOI_UUID: b4870d4d-918a-46e5-81bc-d8f6664cc458--779969993; Object Layer Attributes #3, Allright_Comp_ID: 0014Wal0779969999; Object Layer Attributes #3, Building alteration category: New building; Object Layer Attributes #3, Unit: m²; Object Layer Attributes #3, NOI_UUID: b4870d4d-918a-46e5-81bc-d8f6664cc458--779969999
 | Plan 1 | gips 13 mm, riegel stål 100 100 mm, gips 13 mm | 1.49103 | 1.00717 |  |  | 3.733 | 0.126 | 0.470358 | 3.17 | 0014HWa0779969792 | b4870d4d-918a-46e5-81bc-d8f6664cc458--779969792 | 0014Wal0779969926 | m² | b4870d4d-918a-46e5-81bc-d8f6664cc458--779969926 | WallQuantities - GrossSideAreaRight: 11.8336 m2; GrossSideAreaLeft: 11.8336 m2; NetSideAreaRight: 7.99341 m2; NetSideAreaLeft: 7.99341 m2; Allplan Attributes - Object Layer Attributes #2, Allright_Comp_ID: 0014Wal0779969931; Object Layer Attributes #2, Building alteration category: New building; Object Layer Attributes #2, Unit: m²; Object Layer Attributes #2, NOI_UUID: b4870d4d-918a-46e5-81bc-d8f6664cc458--779969931; Object Layer Attributes #3, Allright_Comp_ID: 0014Wal0779969951; Object Layer Attributes #3, Building alteration category: New building; Object Layer Attributes #3, Unit: m²; Object Layer Attributes #3, NOI_UUID: b4870d4d-918a-46e5-81bc-d8f6664cc458--779969951
 | Plan 1 | gips 13 mm, riegel stål 100 100 mm, gips 13 mm | 2.66627 | 2.66627 |  |  | 6.62933 | 0.126 | 0.841096 | 3.17 | 0014HWa0779969974 | b4870d4d-918a-46e5-81bc-d8f6664cc458--779969974 | 0014Wal0779969984 | m² | b4870d4d-918a-46e5-81bc-d8f6664cc458--779969984 | Allplan Attributes - Object Layer Attributes #1, Material: gips; Object Layer Attributes #2, Allright_Comp_ID: 0014Wal0779969982; Object Layer Attributes #2, Building alteration category: New building; Object Layer Attributes #2, Unit: m²; Object Layer Attributes #2, Material: riegel stål 100; Object Layer Attributes #2, NOI_UUID: b4870d4d-918a-46e5-81bc-d8f6664cc458--779969982; Object Layer Attributes #3, Allright_Comp_ID: 0014Wal0779969979; Object Layer Attributes #3, Building alteration category: New building; Object Layer Attributes #3, Unit: m²; Object Layer Attributes #3, NOI_UUID: b4870d4d-918a-46e5-81bc-d8f6664cc458--779969979; Object Layer Attributes #3, Material: gips; WallQuantities - GrossSideAreaRight: 20.9093 m2; GrossSideAreaLeft: 20.9093 m2; NetSideAreaRight: 20.9093 m2; NetSideAreaLeft: 20.9093 m2
 | Plan 1 | gips 13 mm, riegel stål 100 100 mm, gips 13 mm | 1.53258 | 1.29065 |  |  | 3.817 | 0.126 | 0.483465 | 3.17 | 0014HWa0779969860 | b4870d4d-918a-46e5-81bc-d8f6664cc458--779969860 | 0014Wal0779969940 | m² | b4870d4d-918a-46e5-81bc-d8f6664cc458--779969940 | WallQuantities - GrossSideAreaRight: 12.233 m2; GrossSideAreaLeft: 11.8748 m2; NetSideAreaRight: 10.3129 m2; NetSideAreaLeft: 9.95472 m2; Allplan Attributes - Object Layer Attributes #2, Allright_Comp_ID: 0014Wal0779969936; Object Layer Attributes #2, Building alteration category: New building; Object Layer Attributes #2, Unit: m²; Object Layer Attributes #2, NOI_UUID: b4870d4d-918a-46e5-81bc-d8f6664cc458--779969936; Object Layer Attributes #3, Allright_Comp_ID: 0014Wal0779969933; Object Layer Attributes #3, Building alteration category: New building; Object Layer Attributes #3, Unit: m²; Object Layer Attributes #3, NOI_UUID: b4870d4d-918a-46e5-81bc-d8f6664cc458--779969933
 | Plan 1 | gips 13 mm, riegel stål 100 100 mm, gips 13 mm | 2.10926 | 1.60123 |  |  | 5.29011 | 0.126 | 0.665382 | 3.17 | 0014HWa0779971459 | b4870d4d-918a-46e5-81bc-d8f6664cc458--779971459 | 0014Wal0779971460 | m³ | b4870d4d-918a-46e5-81bc-d8f6664cc458--779971460 | WallQuantities - GrossSideAreaRight: 16.41 m2; GrossSideAreaLeft: 17.1719 m2; NetSideAreaRight: 12.3781 m2; NetSideAreaLeft: 13.1399 m2; Allplan Attributes - Object Layer Attributes #2, Allright_Comp_ID: 0014Wal0779971461; Object Layer Attributes #2, Building alteration category: New building; Object Layer Attributes #2, Unit: m³; Object Layer Attributes #2, NOI_UUID: b4870d4d-918a-46e5-81bc-d8f6664cc458--779971461; Object Layer Attributes #3, Allright_Comp_ID: 0014Wal0779971462; Object Layer Attributes #3, Building alteration category: New building; Object Layer Attributes #3, Unit: m³; Object Layer Attributes #3, NOI_UUID: b4870d4d-918a-46e5-81bc-d8f6664cc458--779971462
 | Plan 1 | gips 13 mm, riegel stål 100 100 mm, gips 13 mm | 0.640612 | 0.640612 |  |  | 1.60386 | 0.126 | 0.202086 | 3.17 | 0014HWa0779979772 | b4870d4d-918a-46e5-81bc-d8f6664cc458--779979772 | 0014Wal0779979779 | m³ | b4870d4d-918a-46e5-81bc-d8f6664cc458--779979779 | Allplan Attributes - Object Layer Attributes #1, Material: gips; Object Layer Attributes #2, Allright_Comp_ID: 0014Wal0779979777; Object Layer Attributes #2, Building alteration category: New building; Object Layer Attributes #2, Unit: m³; Object Layer Attributes #2, Material: riegel stål 100; Object Layer Attributes #2, NOI_UUID: b4870d4d-918a-46e5-81bc-d8f6664cc458--779979777; Object Layer Attributes #3, Allright_Comp_ID: 0014Wal0779979775; Object Layer Attributes #3, Building alteration category: New building; Object Layer Attributes #3, Unit: m³; Object Layer Attributes #3, NOI_UUID: b4870d4d-918a-46e5-81bc-d8f6664cc458--779979775; Object Layer Attributes #3, Material: gips; WallQuantities - GrossSideAreaRight: 5.08422 m2; GrossSideAreaLeft: 5.08422 m2; NetSideAreaRight: 5.08422 m2; NetSideAreaLeft: 5.08422 m2
 | Plan 1 | gips 13 mm, riegel stål 100 100 mm, gips 13 mm | 1.91572 | 1.64847 |  |  | 4.81627 | 0.126 | 0.604327 | 3.17 | 0014HWa0779968968 | b4870d4d-918a-46e5-81bc-d8f6664cc458--779968968 | 0014Wal0779968969 | m³ | b4870d4d-918a-46e5-81bc-d8f6664cc458--779968969 | WallQuantities - GrossSideAreaRight: 15.1344 m2; GrossSideAreaLeft: 15.4926 m2; NetSideAreaRight: 13.0134 m2; NetSideAreaLeft: 13.3716 m2; Allplan Attributes - Object Layer Attributes #2, Allright_Comp_ID: 0014Wal0779968970; Object Layer Attributes #2, Building alteration category: New building; Object Layer Attributes #2, Unit: m³; Object Layer Attributes #2, NOI_UUID: b4870d4d-918a-46e5-81bc-d8f6664cc458--779968970; Object Layer Attributes #3, Allright_Comp_ID: 0014Wal0779968971; Object Layer Attributes #3, Building alteration category: New building; Object Layer Attributes #3, Unit: m³; Object Layer Attributes #3, NOI_UUID: b4870d4d-918a-46e5-81bc-d8f6664cc458--779968971
 | Plan 1 | Betong 50 mm | 0.20125 | 0.10675 | 4.025 | 2.135 | 1.25 | 0.05 | 0.0625 | 3.22 | 0014HWa0780023136 | b4870d4d-918a-46e5-81bc-d8f6664cc458--780023136 | 0014Wal0780023158 | m² | b4870d4d-918a-46e5-81bc-d8f6664cc458--780023158 | Allplan Attributes - Object Layer Attributes #1, Material: Betong
 | Plan 1 | Betong 50 mm | 0.20125 | 0.20125 | 4.025 | 4.025 | 1.25 | 0.05 | 0.0625 | 3.22 | 0014HWa0780023132 | b4870d4d-918a-46e5-81bc-d8f6664cc458--780023132 | 0014Wal0780023162 | m² | b4870d4d-918a-46e5-81bc-d8f6664cc458--780023162 | Allplan Attributes - Object Layer Attributes #1, Material: Betong
 | Plan 1 | Betong 50 mm | 0.2576 | 0.2576 | 5.152 | 5.152 | 1.6 | 0.05 | 0.08 | 3.22 | 0014HWa0780023134 | b4870d4d-918a-46e5-81bc-d8f6664cc458--780023134 | 0014Wal0780023160 | m² | b4870d4d-918a-46e5-81bc-d8f6664cc458--780023160 | Allplan Attributes - Object Layer Attributes #1, Material: Betong
 | Plan 1 | Betong 50 mm | 0.2737 | 0.2737 | 5.474 | 5.474 | 1.7 | 0.05 | 0.085 | 3.22 | 0014HWa0780023139 | b4870d4d-918a-46e5-81bc-d8f6664cc458--780023139 | 0014Wal0780023154 | m² | b4870d4d-918a-46e5-81bc-d8f6664cc458--780023154 | Allplan Attributes - Object Layer Attributes #1, Material: Betong
 | Plan 1 | gips 13 mm, riegel stål 100 100 mm, gips 13 mm | 0.730149 | 0.730149 |  |  | 1.808 | 0.126 | 0.230331 | 3.17 | 0014HWa0780023798 | b4870d4d-918a-46e5-81bc-d8f6664cc458--780023798 | 0014Wal0780023799 | m³ | b4870d4d-918a-46e5-81bc-d8f6664cc458--780023799 | WallQuantities - GrossSideAreaRight: 5.8645 m2; GrossSideAreaLeft: 5.50629 m2; NetSideAreaRight: 5.8645 m2; NetSideAreaLeft: 5.50629 m2; Allplan Attributes - Object Layer Attributes #2, Allright_Comp_ID: 0014Wal0780023800; Object Layer Attributes #2, Building alteration category: New building; Object Layer Attributes #2, Unit: m³; Object Layer Attributes #2, NOI_UUID: b4870d4d-918a-46e5-81bc-d8f6664cc458--780023800; Object Layer Attributes #3, Allright_Comp_ID: 0014Wal0780023801; Object Layer Attributes #3, Building alteration category: New building; Object Layer Attributes #3, Unit: m³; Object Layer Attributes #3, NOI_UUID: b4870d4d-918a-46e5-81bc-d8f6664cc458--780023801
 | Plan 1 | gips 13 mm, riegel stål 100 100 mm, gips 13 mm | 0.502246 | 0.233728 |  |  | 1.27746 | 0.126 | 0.158437 | 3.17 | 0014HWa0780023859 | b4870d4d-918a-46e5-81bc-d8f6664cc458--780023859 | 0014Wal0780023860 | m³ | b4870d4d-918a-46e5-81bc-d8f6664cc458--780023860 | WallQuantities - GrossSideAreaRight: 4.27463 m2; GrossSideAreaLeft: 3.91642 m2; NetSideAreaRight: 2.14353 m2; NetSideAreaLeft: 1.78532 m2; Allplan Attributes - Object Layer Attributes #2, Allright_Comp_ID: 0014Wal0780023861; Object Layer Attributes #2, Building alteration category: New building; Object Layer Attributes #2, Unit: m³; Object Layer Attributes #2, NOI_UUID: b4870d4d-918a-46e5-81bc-d8f6664cc458--780023861; Object Layer Attributes #3, Allright_Comp_ID: 0014Wal0780023862; Object Layer Attributes #3, Building alteration category: New building; Object Layer Attributes #3, Unit: m³; Object Layer Attributes #3, NOI_UUID: b4870d4d-918a-46e5-81bc-d8f6664cc458--780023862
 | Plan 1 | gips 13 mm, riegel stål 100 100 mm, gips 13 mm | 4.79304 | 3.74682 |  |  | 12 | 0.126 | 1.512 | 3.17 | 0014HWa0000000064 | b4870d4d-918a-46e5-81bc-d8f6664cc458--64 | 0014Wal0000000065 | m³ | b4870d4d-918a-46e5-81bc-d8f6664cc458--65 | WallQuantities - GrossSideAreaRight: 38.04 m2; GrossSideAreaLeft: 38.04 m2; NetSideAreaRight: 29.7367 m2; NetSideAreaLeft: 29.7367 m2; Allplan Attributes - Object Layer Attributes #2, Allright_Comp_ID: 0014Wal0000000066; Object Layer Attributes #2, Building alteration category: New building; Object Layer Attributes #2, Unit: m³; Object Layer Attributes #2, NOI_UUID: b4870d4d-918a-46e5-81bc-d8f6664cc458--66; Object Layer Attributes #3, Allright_Comp_ID: 0014Wal0000000067; Object Layer Attributes #3, Building alteration category: New building; Object Layer Attributes #3, Unit: m³; Object Layer Attributes #3, NOI_UUID: b4870d4d-918a-46e5-81bc-d8f6664cc458--67
 | Plan 1 | Betong 50 mm | 0.12 | 0.12 | 2.4 | 2.4 | 12 | 0.05 | 0.6 | 0.2 | 0015HWa0016825571 | cbab19c6-f7f3-4c25-9028-8574def17b1d--16825571 | 0015Wal0016825572 | m | cbab19c6-f7f3-4c25-9028-8574def17b1d--16825572
 | Plan 1 | Betong 35 mm | 0.084 | 0.084 | 2.4 | 2.4 | 12 | 0.035 | 0.42 | 0.2 | 0015HWa0016825587 | cbab19c6-f7f3-4c25-9028-8574def17b1d--16825587 | 0015Wal0016825588 | m | cbab19c6-f7f3-4c25-9028-8574def17b1d--16825588
 | Plan 1 | Betong 35 mm | 0.084 | 0.084 | 2.4 | 2.4 | 12 | 0.035 | 0.42 | 0.2 | 0015HWa0016825592 | cbab19c6-f7f3-4c25-9028-8574def17b1d--16825592 | 0015Wal0016825593 | m | cbab19c6-f7f3-4c25-9028-8574def17b1d--16825593
 | Plan 1 | Betong 35 mm | 0.084 | 0.084 | 2.4 | 2.4 | 12 | 0.035 | 0.42 | 0.2 | 0015HWa0016825839 | cbab19c6-f7f3-4c25-9028-8574def17b1d--16825839 | 0015Wal0016825840 | m | cbab19c6-f7f3-4c25-9028-8574def17b1d--16825840
 | Plan 1 | Betong 35 mm | 0.084 | 0.084 | 2.4 | 2.4 | 12 | 0.035 | 0.42 | 0.2 | 0015HWa0016825842 | cbab19c6-f7f3-4c25-9028-8574def17b1d--16825842 | 0015Wal0016825844 | m | cbab19c6-f7f3-4c25-9028-8574def17b1d--16825844
 | Plan 1 | Betong 35 mm | 0.084 | 0.084 | 2.4 | 2.4 | 12 | 0.035 | 0.42 | 0.2 | 0015HWa0016825849 | cbab19c6-f7f3-4c25-9028-8574def17b1d--16825849 | 0015Wal0016825854 | m | cbab19c6-f7f3-4c25-9028-8574def17b1d--16825854
 | Plan 1 | Betong 35 mm | 0.084 | 0.084 | 2.4 | 2.4 | 12 | 0.035 | 0.42 | 0.2 | 0015HWa0016825851 | cbab19c6-f7f3-4c25-9028-8574def17b1d--16825851 | 0015Wal0016825853 | m | cbab19c6-f7f3-4c25-9028-8574def17b1d--16825853
 | Plan 1 | Betong 35 mm | 0.084 | 0.084 | 2.4 | 2.4 | 12 | 0.035 | 0.42 | 0.2 | 0015HWa0016825859 | cbab19c6-f7f3-4c25-9028-8574def17b1d--16825859 | 0015Wal0016825863 | m | cbab19c6-f7f3-4c25-9028-8574def17b1d--16825863
 | Plan 1 | Betong 35 mm | 0.084 | 0.084 | 2.4 | 2.4 | 12 | 0.035 | 0.42 | 0.2 | 0015HWa0016825861 | cbab19c6-f7f3-4c25-9028-8574def17b1d--16825861 | 0015Wal0016825864 | m | cbab19c6-f7f3-4c25-9028-8574def17b1d--16825864
 | Plan 1 | Betong 35 mm | 0.084 | 0.084 | 2.4 | 2.4 | 12 | 0.035 | 0.42 | 0.2 | 0015HWa0016825947 | cbab19c6-f7f3-4c25-9028-8574def17b1d--16825947 | 0015Wal0016825951 | m | cbab19c6-f7f3-4c25-9028-8574def17b1d--16825951
 | Plan 1 | Betong 35 mm | 0.027475 | 0.027475 | 0.785 | 0.785 | 3.925 | 0.035 | 0.137375 | 0.2 | 0015HWa0016825949 | cbab19c6-f7f3-4c25-9028-8574def17b1d--16825949 | 0015Wal0016825952 | m | cbab19c6-f7f3-4c25-9028-8574def17b1d--16825952
 | Plan 1 | Betong 50 mm | 0.03775 | 0.03775 | 0.755 | 0.755 | 3.775 | 0.05 | 0.18875 | 0.2 | 0015HWa0016826016 | cbab19c6-f7f3-4c25-9028-8574def17b1d--16826016 | 0015Wal0016826018 | m | cbab19c6-f7f3-4c25-9028-8574def17b1d--16826018
 | Plan 1 | Betong 25 mm | 0.0134473 | 0.0134473 | 0.537893 | 0.537893 | 2.68946 | 0.025 | 0.0672366 | 0.2 | 0015HWa0016826101 | cbab19c6-f7f3-4c25-9028-8574def17b1d--16826101 | 0015Wal0016826103 | m | cbab19c6-f7f3-4c25-9028-8574def17b1d--16826103
 | Plan 2 | Lekter 46 mm, Kledning 19 mm | 0.874547 | 0.740055 |  |  | 3.23 | 0.065 | 0.20995 | 4.16595 | 0023HWa0779993586 | 84cb5e05-e28d-4939-8977-531e4630a18c--779993586 | 0023Wal0779993587 | m² | 84cb5e05-e28d-4939-8977-531e4630a18c--779993587 | Allplan Attributes - Object Layer Attributes #1, Material: Lekter; Object Layer Attributes #2, Allright_Comp_ID: 0023Wal0779993588; Object Layer Attributes #2, Building alteration category: New building; Object Layer Attributes #2, Unit: m²; Object Layer Attributes #2, Material: Kledning; Object Layer Attributes #2, NOI_UUID: 84cb5e05-e28d-4939-8977-531e4630a18c--779993588; Object Layer Attributes #2, Trade: Ext. insulation finish systems; WallQuantities - GrossSideAreaRight: 13.4525 m2; GrossSideAreaLeft: 13.4595 m2; NetSideAreaRight: 11.3834 m2; NetSideAreaLeft: 11.3904 m2
 | Plan 2 | Lekter 46 mm, Kledning 19 mm | 0.798315 | 0.798315 |  |  | 2.958 | 0.065 | 0.191649 | 4.16595 | 0023HWa0779992730 | 84cb5e05-e28d-4939-8977-531e4630a18c--779992730 | 0023Wal0779992731 | m² | 84cb5e05-e28d-4939-8977-531e4630a18c--779992731 | Allplan Attributes - Object Layer Attributes #1, Material: Lekter; Object Layer Attributes #2, Allright_Comp_ID: 0023Wal0779992732; Object Layer Attributes #2, Building alteration category: New building; Object Layer Attributes #2, Unit: m²; Object Layer Attributes #2, Material: Kledning; Object Layer Attributes #2, NOI_UUID: 84cb5e05-e28d-4939-8977-531e4630a18c--779992732; Object Layer Attributes #2, Trade: Ext. insulation finish systems; WallQuantities - GrossSideAreaRight: 12.2239 m2; GrossSideAreaLeft: 12.4219 m2; NetSideAreaRight: 12.2239 m2; NetSideAreaLeft: 12.4219 m2
 | Plan 2 | Lekter 46 mm, Kledning 19 mm | 1.23799 | 1.08576 |  |  | 4.7555 | 0.065 | 0.308851 | 4.00852 | 0023HWa0779993078 | 84cb5e05-e28d-4939-8977-531e4630a18c--779993078 | 0023Wal0779993079 | m² | 84cb5e05-e28d-4939-8977-531e4630a18c--779993079 | Allplan Attributes - Object Layer Attributes #1, Material: Lekter; Object Layer Attributes #2, Allright_Comp_ID: 0023Wal0779993080; Object Layer Attributes #2, Building alteration category: New building; Object Layer Attributes #2, Unit: m²; Object Layer Attributes #2, Material: Kledning; Object Layer Attributes #2, NOI_UUID: 84cb5e05-e28d-4939-8977-531e4630a18c--779993080; Object Layer Attributes #2, Trade: Ext. insulation finish systems; WallQuantities - GrossSideAreaRight: 19.0229 m2; GrossSideAreaLeft: 19.1021 m2; NetSideAreaRight: 16.6808 m2; NetSideAreaLeft: 16.76 m2
 | Plan 2 | Paroc 200 200 mm | 9.3 | 8.13894 | 46.5 | 40.6947 | 12.4 | 0.2 | 2.48 | 3.75 | 0023HWa0000000027 | 84cb5e05-e28d-4939-8977-531e4630a18c--27 | 0023Wal0000000028 | m² | 84cb5e05-e28d-4939-8977-531e4630a18c--28 | Allplan Attributes - Object Layer Attributes #1, Material: Paroc 200
 | Plan 2 | Paroc 200 200 mm | 13.5739 | 11.5048 | 67.8697 | 57.5242 | 20.3 | 0.2 | 4.06 | 3.34333 | 0023HWa0000000017 | 84cb5e05-e28d-4939-8977-531e4630a18c--17 | 0023Wal0000000018 | m² | 84cb5e05-e28d-4939-8977-531e4630a18c--18 | Allplan Attributes - Object Layer Attributes #1, Material: Paroc 200
 | Plan 2 | Lekter 46 mm, Kledning 19 mm | 1.15991 | 1.02542 |  |  | 5.3555 | 0.065 | 0.347851 | 3.33405 | 0023HWa0779993368 | 84cb5e05-e28d-4939-8977-531e4630a18c--779993368 | 0023Wal0779993369 | m² | 84cb5e05-e28d-4939-8977-531e4630a18c--779993369 | Allplan Attributes - Object Layer Attributes #1, Material: Lekter; Object Layer Attributes #2, Allright_Comp_ID: 0023Wal0779993370; Object Layer Attributes #2, Building alteration category: New building; Object Layer Attributes #2, Unit: m²; Object Layer Attributes #2, Material: Kledning; Object Layer Attributes #2, NOI_UUID: 84cb5e05-e28d-4939-8977-531e4630a18c--779993370; Object Layer Attributes #2, Trade: Ext. insulation finish systems; WallQuantities - GrossSideAreaRight: 17.8296 m2; GrossSideAreaLeft: 17.8814 m2; NetSideAreaRight: 15.7605 m2; NetSideAreaLeft: 15.8123 m2
 | Plan 2 | Lekter 46 mm, Kledning 19 mm | 0.0463782 | 0.0463782 |  |  | 0.223 | 0.065 | 0.013874 | 3.34257 | 0023HWa0779993421 | 84cb5e05-e28d-4939-8977-531e4630a18c--779993421 | 0023Wal0779993422 | m² | 84cb5e05-e28d-4939-8977-531e4630a18c--779993422 | Allplan Attributes - Object Layer Attributes #1, Material: Lekter; Object Layer Attributes #2, Allright_Comp_ID: 0023Wal0779993423; Object Layer Attributes #2, Building alteration category: New building; Object Layer Attributes #2, Unit: m²; Object Layer Attributes #2, Material: Kledning; Object Layer Attributes #2, NOI_UUID: 84cb5e05-e28d-4939-8977-531e4630a18c--779993423; Object Layer Attributes #2, Trade: Ext. insulation finish systems; WallQuantities - GrossSideAreaRight: 0.668667 m2; GrossSideAreaLeft: 0.822083 m2; NetSideAreaRight: 0.668667 m2; NetSideAreaLeft: 0.822083 m2
 | Plan 2 | Lekter 46 mm, Kledning 19 mm | 0.650227 | 0.650227 |  |  | 3 | 0.065 | 0.195 | 3.33405 | 0023HWa0779994203 | 84cb5e05-e28d-4939-8977-531e4630a18c--779994203 | 0023Wal0779994204 | m² | 84cb5e05-e28d-4939-8977-531e4630a18c--779994204 | Allplan Attributes - Object Layer Attributes #1, Material: Lekter; Object Layer Attributes #2, Allright_Comp_ID: 0023Wal0779994205; Object Layer Attributes #2, Building alteration category: New building; Object Layer Attributes #2, Unit: m²; Object Layer Attributes #2, Material: Kledning; Object Layer Attributes #2, NOI_UUID: 84cb5e05-e28d-4939-8977-531e4630a18c--779994205; Object Layer Attributes #2, Trade: Ext. insulation finish systems; WallQuantities - GrossSideAreaRight: 10.0054 m2; GrossSideAreaLeft: 9.9989 m2; NetSideAreaRight: 10.0054 m2; NetSideAreaLeft: 9.9989 m2
 | Plan 2 | Paroc 200 200 mm | 16.7098 | 13.0891 | 83.549 | 65.4453 | 20.1 | 0.2 | 4.02 | 4.15667 | 0023HWa0000000039 | 84cb5e05-e28d-4939-8977-531e4630a18c--39 | 0023Wal0000000040 | m² | 84cb5e05-e28d-4939-8977-531e4630a18c--40 | Allplan Attributes - Object Layer Attributes #1, Material: Paroc 200
 | Plan 2 | Paroc 200 200 mm | 9.16627 | 8.19101 | 45.8313 | 40.955 | 12.2 | 0.2 | 2.44 | 3.75667 | 0023HWa0000000006 | 84cb5e05-e28d-4939-8977-531e4630a18c--6 | 0023Wal0000000009 | m² | 84cb5e05-e28d-4939-8977-531e4630a18c--9 | Allplan Attributes - Object Layer Attributes #1, Material: Paroc 200
 | Plan 2 | Lekter 46 mm, Kledning 19 mm | 3.0225 | 2.70554 |  |  | 12.4 | 0.065 | 0.806 | 3.75 | 0023HWa0779992985 | 84cb5e05-e28d-4939-8977-531e4630a18c--779992985 | 0023Wal0779992986 | m² | 84cb5e05-e28d-4939-8977-531e4630a18c--779992986 | Allplan Attributes - Object Layer Attributes #1, Material: Lekter; Object Layer Attributes #2, Allright_Comp_ID: 0023Wal0779992987; Object Layer Attributes #2, Building alteration category: New building; Object Layer Attributes #2, Unit: m²; Object Layer Attributes #2, Material: Kledning; Object Layer Attributes #2, NOI_UUID: 84cb5e05-e28d-4939-8977-531e4630a18c--779992987; Object Layer Attributes #2, Trade: Ext. insulation finish systems; WallQuantities - GrossSideAreaRight: 46.5 m2; GrossSideAreaLeft: 46.5 m2; NetSideAreaRight: 41.6237 m2; NetSideAreaLeft: 41.6237 m2
 | Plan 2 | gips 13 mm, riegel stål 100 100 mm, gips 13 mm | 3.79396 | 2.18285 |  |  | 8.49567 | 0.126 | 1.06648 | 3.55747 | 0024HWa0779986768 | ffc0a4b9-6ff1-450c-9901-90887e5cf058--779986768 | 0024Wal0779986890 | m³ | ffc0a4b9-6ff1-450c-9901-90887e5cf058--779986890 | WallQuantities - GrossSideAreaRight: 30.0461 m2; GrossSideAreaLeft: 30.5618 m2; NetSideAreaRight: 17.2595 m2; NetSideAreaLeft: 17.7752 m2; Allplan Attributes - Object Layer Attributes #2, Allright_Comp_ID: 0024Wal0779986886; Object Layer Attributes #2, Building alteration category: New building; Object Layer Attributes #2, Unit: m³; Object Layer Attributes #2, NOI_UUID: ffc0a4b9-6ff1-450c-9901-90887e5cf058--779986886; Object Layer Attributes #3, Allright_Comp_ID: 0024Wal0779986887; Object Layer Attributes #3, Building alteration category: New building; Object Layer Attributes #3, Unit: m³; Object Layer Attributes #3, NOI_UUID: ffc0a4b9-6ff1-450c-9901-90887e5cf058--779986887
 | Plan 2 | gips 13 mm, riegel stål 100 100 mm, gips 13 mm | 2.13558 | 1.86707 |  |  | 5.159 | 0.126 | 0.652557 | 3.27197 | 0024HWa0779983599 | ffc0a4b9-6ff1-450c-9901-90887e5cf058--779983599 | 0024Wal0779983603 | m³ | ffc0a4b9-6ff1-450c-9901-90887e5cf058--779983603 | WallQuantities - GrossSideAreaRight: 17.0248 m2; GrossSideAreaLeft: 16.6357 m2; NetSideAreaRight: 14.8937 m2; NetSideAreaLeft: 14.5046 m2; Allplan Attributes - Object Layer Attributes #2, Allright_Comp_ID: 0024Wal0779983602; Object Layer Attributes #2, Building alteration category: New building; Object Layer Attributes #2, Unit: m³; Object Layer Attributes #2, NOI_UUID: ffc0a4b9-6ff1-450c-9901-90887e5cf058--779983602; Object Layer Attributes #3, Allright_Comp_ID: 0024Wal0779983601; Object Layer Attributes #3, Building alteration category: New building; Object Layer Attributes #3, Unit: m³; Object Layer Attributes #3, NOI_UUID: ffc0a4b9-6ff1-450c-9901-90887e5cf058--779983601
 | Plan 2 | gips 13 mm, riegel stål 100 150 mm, gips 13 mm | 2.91948 | 2.91948 |  |  | 5.07067 | 0.176 | 0.893031 | 3.26924 | 0024HWa0779985646 | ffc0a4b9-6ff1-450c-9901-90887e5cf058--779985646 | 0024Wal0779985654 | m³ | ffc0a4b9-6ff1-450c-9901-90887e5cf058--779985654 | WallQuantities - GrossSideAreaRight: 16.5495 m2; GrossSideAreaLeft: 16.591 m2; NetSideAreaRight: 16.5495 m2; NetSideAreaLeft: 16.591 m2; Allplan Attributes - Object Layer Attributes #2, Allright_Comp_ID: 0024Wal0779985652; Object Layer Attributes #2, Building alteration category: New building; Object Layer Attributes #2, Unit: m³; Object Layer Attributes #2, NOI_UUID: ffc0a4b9-6ff1-450c-9901-90887e5cf058--779985652; Object Layer Attributes #3, Allright_Comp_ID: 0024Wal0779985653; Object Layer Attributes #3, Building alteration category: New building; Object Layer Attributes #3, Unit: m³; Object Layer Attributes #3, NOI_UUID: ffc0a4b9-6ff1-450c-9901-90887e5cf058--779985653
 | Plan 2 | gips 13 mm, riegel stål 100 100 mm, gips 13 mm | 6.50971 | 3.82452 |  |  | 15.0247 | 0.126 | 1.89096 | 3.44253 | 0024HWa0779986183 | ffc0a4b9-6ff1-450c-9901-90887e5cf058--779986183 | 0024Wal0779986201 | m³ | ffc0a4b9-6ff1-450c-9901-90887e5cf058--779986201 | WallQuantities - GrossSideAreaRight: 51.4921 m2; GrossSideAreaLeft: 52.0391 m2; NetSideAreaRight: 30.1811 m2; NetSideAreaLeft: 30.7281 m2; Allplan Attributes - Object Layer Attributes #2, Allright_Comp_ID: 0024Wal0779986199; Object Layer Attributes #2, Building alteration category: New building; Object Layer Attributes #2, Unit: m³; Object Layer Attributes #2, NOI_UUID: ffc0a4b9-6ff1-450c-9901-90887e5cf058--779986199; Object Layer Attributes #3, Allright_Comp_ID: 0024Wal0779986200; Object Layer Attributes #3, Building alteration category: New building; Object Layer Attributes #3, Unit: m³; Object Layer Attributes #3, NOI_UUID: ffc0a4b9-6ff1-450c-9901-90887e5cf058--779986200
 | Plan 2 | gips 13 mm, riegel stål 100 100 mm, gips 13 mm | 2.09105 | 2.09105 |  |  | 5.07933 | 0.126 | 0.639619 | 3.26931 | 0024HWa0779988906 | ffc0a4b9-6ff1-450c-9901-90887e5cf058--779988906 | 0024Wal0779988908 | m³ | ffc0a4b9-6ff1-450c-9901-90887e5cf058--779988908 | WallQuantities - GrossSideAreaRight: 16.6357 m2; GrossSideAreaLeft: 16.591 m2; NetSideAreaRight: 16.6357 m2; NetSideAreaLeft: 16.591 m2; Allplan Attributes - Object Layer Attributes #2, Allright_Comp_ID: 0024Wal0779988909; Object Layer Attributes #2, Building alteration category: New building; Object Layer Attributes #2, Unit: m³; Object Layer Attributes #2, NOI_UUID: ffc0a4b9-6ff1-450c-9901-90887e5cf058--779988909; Object Layer Attributes #3, Allright_Comp_ID: 0024Wal0779988910; Object Layer Attributes #3, Building alteration category: New building; Object Layer Attributes #3, Unit: m³; Object Layer Attributes #3, NOI_UUID: ffc0a4b9-6ff1-450c-9901-90887e5cf058--779988910
 | Plan 2 | gips 13 mm, riegel stål 100 100 mm, gips 13 mm | 2.09047 | 2.09047 |  |  | 5.075 | 0.126 | 0.63945 | 3.26917 | 0024HWa0779984327 | ffc0a4b9-6ff1-450c-9901-90887e5cf058--779984327 | 0024Wal0779984332 | m³ | ffc0a4b9-6ff1-450c-9901-90887e5cf058--779984332 | WallQuantities - GrossSideAreaRight: 16.591 m2; GrossSideAreaLeft: 16.591 m2; NetSideAreaRight: 16.591 m2; NetSideAreaLeft: 16.591 m2; Allplan Attributes - Object Layer Attributes #2, Allright_Comp_ID: 0024Wal0779984331; Object Layer Attributes #2, Building alteration category: New building; Object Layer Attributes #2, Unit: m³; Object Layer Attributes #2, NOI_UUID: ffc0a4b9-6ff1-450c-9901-90887e5cf058--779984331; Object Layer Attributes #3, Allright_Comp_ID: 0024Wal0779984330; Object Layer Attributes #3, Building alteration category: New building; Object Layer Attributes #3, Unit: m³; Object Layer Attributes #3, NOI_UUID: ffc0a4b9-6ff1-450c-9901-90887e5cf058--779984330
 | Plan 2 | gips 13 mm, riegel stål 100 100 mm, gips 13 mm | 2.38568 | 2.38568 |  |  | 5.075 | 0.126 | 0.63945 | 3.73083 | 0024HWa0779985400 | ffc0a4b9-6ff1-450c-9901-90887e5cf058--779985400 | 0024Wal0779985406 | m³ | ffc0a4b9-6ff1-450c-9901-90887e5cf058--779985406 | WallQuantities - GrossSideAreaRight: 18.934 m2; GrossSideAreaLeft: 18.934 m2; NetSideAreaRight: 18.934 m2; NetSideAreaLeft: 18.934 m2; Allplan Attributes - Object Layer Attributes #2, Allright_Comp_ID: 0024Wal0779985408; Object Layer Attributes #2, Building alteration category: New building; Object Layer Attributes #2, Unit: m³; Object Layer Attributes #2, NOI_UUID: ffc0a4b9-6ff1-450c-9901-90887e5cf058--779985408; Object Layer Attributes #3, Allright_Comp_ID: 0024Wal0779985407; Object Layer Attributes #3, Building alteration category: New building; Object Layer Attributes #3, Unit: m³; Object Layer Attributes #3, NOI_UUID: ffc0a4b9-6ff1-450c-9901-90887e5cf058--779985407
 | Plan 2 | gips 13 mm, riegel stål 100 100 mm, gips 13 mm | 2.38568 | 2.38568 |  |  | 5.075 | 0.126 | 0.63945 | 3.73083 | 0024HWa0779985237 | ffc0a4b9-6ff1-450c-9901-90887e5cf058--779985237 | 0024Wal0779985240 | m³ | ffc0a4b9-6ff1-450c-9901-90887e5cf058--779985240 | WallQuantities - GrossSideAreaRight: 18.934 m2; GrossSideAreaLeft: 18.934 m2; NetSideAreaRight: 18.934 m2; NetSideAreaLeft: 18.934 m2; Allplan Attributes - Object Layer Attributes #2, Allright_Comp_ID: 0024Wal0779985242; Object Layer Attributes #2, Building alteration category: New building; Object Layer Attributes #2, Unit: m³; Object Layer Attributes #2, NOI_UUID: ffc0a4b9-6ff1-450c-9901-90887e5cf058--779985242; Object Layer Attributes #3, Allright_Comp_ID: 0024Wal0779985241; Object Layer Attributes #3, Building alteration category: New building; Object Layer Attributes #3, Unit: m³; Object Layer Attributes #3, NOI_UUID: ffc0a4b9-6ff1-450c-9901-90887e5cf058--779985241
 | Plan 2 | gips 13 mm, riegel stål 100 150 mm, gips 13 mm | 3.39912 | 3.39912 |  |  | 5.159 | 0.176 | 0.911957 | 3.72803 | 0024HWa0779983781 | ffc0a4b9-6ff1-450c-9901-90887e5cf058--779983781 | 0024Wal0779983786 | m³ | ffc0a4b9-6ff1-450c-9901-90887e5cf058--779983786 | WallQuantities - GrossSideAreaRight: 19.3822 m2; GrossSideAreaLeft: 18.9803 m2; NetSideAreaRight: 19.3822 m2; NetSideAreaLeft: 18.9803 m2; Allplan Attributes - Object Layer Attributes #2, Allright_Comp_ID: 0024Wal0779983785; Object Layer Attributes #2, Building alteration category: New building; Object Layer Attributes #2, Unit: m³; Object Layer Attributes #2, NOI_UUID: ffc0a4b9-6ff1-450c-9901-90887e5cf058--779983785; Object Layer Attributes #3, Allright_Comp_ID: 0024Wal0779983784; Object Layer Attributes #3, Building alteration category: New building; Object Layer Attributes #3, Unit: m³; Object Layer Attributes #3, NOI_UUID: ffc0a4b9-6ff1-450c-9901-90887e5cf058--779983784
 | Plan 2 | gips 13 mm, riegel stål 100 100 mm, gips 13 mm | 1.02272 | 1.02272 |  |  | 2.25 | 0.126 | 0.2835 | 3.60747 | 0024HWa0779991923 | ffc0a4b9-6ff1-450c-9901-90887e5cf058--779991923 | 0024Wal0779991924 | m³ | ffc0a4b9-6ff1-450c-9901-90887e5cf058--779991924 | WallQuantities - GrossSideAreaRight: 8.10832 m2; GrossSideAreaLeft: 8.12527 m2; NetSideAreaRight: 8.10832 m2; NetSideAreaLeft: 8.12527 m2; Allplan Attributes - Object Layer Attributes #2, Allright_Comp_ID: 0024Wal0779991925; Object Layer Attributes #2, Building alteration category: New building; Object Layer Attributes #2, Unit: m³; Object Layer Attributes #2, NOI_UUID: ffc0a4b9-6ff1-450c-9901-90887e5cf058--779991925; Object Layer Attributes #3, Allright_Comp_ID: 0024Wal0779991926; Object Layer Attributes #3, Building alteration category: New building; Object Layer Attributes #3, Unit: m³; Object Layer Attributes #3, NOI_UUID: ffc0a4b9-6ff1-450c-9901-90887e5cf058--779991926
2 x  | Plan 2 | gips 13 mm, riegel stål 100 100 mm, gips 13 mm | 2.74702 | 2.1834 |  |  | 6.18853 | 0.126 | 0.772186 | 3.55747 | 0024HWa0779982651 | ffc0a4b9-6ff1-450c-9901-90887e5cf058--779982651 | 0024Wal0779982652 | m³ | ffc0a4b9-6ff1-450c-9901-90887e5cf058--779982652 | WallQuantities - GrossSideAreaRight: 22.3476 m2; GrossSideAreaLeft: 21.9925 m2; NetSideAreaRight: 17.8744 m2; NetSideAreaLeft: 17.5193 m2; Allplan Attributes - Object Layer Attributes #2, Allright_Comp_ID: 0024Wal0779982653; Object Layer Attributes #2, Building alteration category: New building; Object Layer Attributes #2, Unit: m³; Object Layer Attributes #2, NOI_UUID: ffc0a4b9-6ff1-450c-9901-90887e5cf058--779982653; Object Layer Attributes #3, Allright_Comp_ID: 0024Wal0779982654; Object Layer Attributes #3, Building alteration category: New building; Object Layer Attributes #3, Unit: m³; Object Layer Attributes #3, NOI_UUID: ffc0a4b9-6ff1-450c-9901-90887e5cf058--779982654
 | Plan 2 | gips 13 mm, riegel stål 100 100 mm, gips 13 mm | 1.81073 | 1.81073 |  |  | 3.95351 | 0.126 | 0.495635 | 3.65334 | 0024HWa0779983262 | ffc0a4b9-6ff1-450c-9901-90887e5cf058--779983262 | 0024Wal0779983265 | m³ | ffc0a4b9-6ff1-450c-9901-90887e5cf058--779983265 | WallQuantities - GrossSideAreaRight: 14.2513 m2; GrossSideAreaLeft: 14.7415 m2; NetSideAreaRight: 14.2513 m2; NetSideAreaLeft: 14.7415 m2; Allplan Attributes - Object Layer Attributes #2, Allright_Comp_ID: 0024Wal0779983266; Object Layer Attributes #2, Building alteration category: New building; Object Layer Attributes #2, Unit: m³; Object Layer Attributes #2, NOI_UUID: ffc0a4b9-6ff1-450c-9901-90887e5cf058--779983266; Object Layer Attributes #3, Allright_Comp_ID: 0024Wal0779983267; Object Layer Attributes #3, Building alteration category: New building; Object Layer Attributes #3, Unit: m³; Object Layer Attributes #3, NOI_UUID: ffc0a4b9-6ff1-450c-9901-90887e5cf058--779983267
 | Plan 2 | gips 13 mm, riegel stål 100 100 mm, gips 13 mm | 0.690528 | 0.690528 |  |  | 1.48 | 0.126 | 0.191526 | 3.6054 | 0024HWa0779984074 | ffc0a4b9-6ff1-450c-9901-90887e5cf058--779984074 | 0024Wal0779984075 | m³ | ffc0a4b9-6ff1-450c-9901-90887e5cf058--779984075 | WallQuantities - GrossSideAreaRight: 4.82403 m2; GrossSideAreaLeft: 5.63885 m2; NetSideAreaRight: 4.82403 m2; NetSideAreaLeft: 5.63885 m2; Allplan Attributes - Object Layer Attributes #2, Allright_Comp_ID: 0024Wal0779984076; Object Layer Attributes #2, Building alteration category: New building; Object Layer Attributes #2, Unit: m³; Object Layer Attributes #2, NOI_UUID: ffc0a4b9-6ff1-450c-9901-90887e5cf058--779984076; Object Layer Attributes #3, Allright_Comp_ID: 0024Wal0779984077; Object Layer Attributes #3, Building alteration category: New building; Object Layer Attributes #3, Unit: m³; Object Layer Attributes #3, NOI_UUID: ffc0a4b9-6ff1-450c-9901-90887e5cf058--779984077
 | Plan 2 | gips 13 mm, riegel stål 100 148 mm, gips 13 mm | 0.825959 | 0.825959 |  |  | 1.31891 | 0.174 | 0.22908 | 3.60563 | 0024HWa0779985250 | ffc0a4b9-6ff1-450c-9901-90887e5cf058--779985250 | 0024Wal0779985256 | m³ | ffc0a4b9-6ff1-450c-9901-90887e5cf058--779985256 | WallQuantities - GrossSideAreaRight: 4.79185 m2; GrossSideAreaLeft: 4.73028 m2; NetSideAreaRight: 4.79185 m2; NetSideAreaLeft: 4.73028 m2; Allplan Attributes - Object Layer Attributes #2, Allright_Comp_ID: 0024Wal0779985255; Object Layer Attributes #2, Building alteration category: New building; Object Layer Attributes #2, Unit: m³; Object Layer Attributes #2, NOI_UUID: ffc0a4b9-6ff1-450c-9901-90887e5cf058--779985255; Object Layer Attributes #3, Allright_Comp_ID: 0024Wal0779985254; Object Layer Attributes #3, Building alteration category: New building; Object Layer Attributes #3, Unit: m³; Object Layer Attributes #3, NOI_UUID: ffc0a4b9-6ff1-450c-9901-90887e5cf058--779985254
 | Plan 2 | gips 13 mm, riegel stål 100 100 mm, gips 13 mm | 2.89646 | 2.62794 |  |  | 6.883 | 0.126 | 0.869781 | 3.32943 | 0024HWa0779993086 | ffc0a4b9-6ff1-450c-9901-90887e5cf058--779993086 | 0024Wal0779993087 | m³ | ffc0a4b9-6ff1-450c-9901-90887e5cf058--779993087 | WallQuantities - GrossSideAreaRight: 22.664 m2; GrossSideAreaLeft: 23.066 m2; NetSideAreaRight: 20.5329 m2; NetSideAreaLeft: 20.9349 m2; Allplan Attributes - Object Layer Attributes #2, Allright_Comp_ID: 0024Wal0779993088; Object Layer Attributes #2, Building alteration category: New building; Object Layer Attributes #2, Unit: m³; Object Layer Attributes #2, NOI_UUID: ffc0a4b9-6ff1-450c-9901-90887e5cf058--779993088; Object Layer Attributes #3, Allright_Comp_ID: 0024Wal0779993089; Object Layer Attributes #3, Building alteration category: New building; Object Layer Attributes #3, Unit: m³; Object Layer Attributes #3, NOI_UUID: ffc0a4b9-6ff1-450c-9901-90887e5cf058--779993089
 | Plan 2 | gips 13 mm, riegel stål 100 100 mm, gips 13 mm | 1.18243 | 1.18243 |  |  | 2.79647 | 0.126 | 0.352355 | 3.3558 | 0024HWa0779982420 | ffc0a4b9-6ff1-450c-9901-90887e5cf058--779982420 | 0024Wal0779982515 | m³ | ffc0a4b9-6ff1-450c-9901-90887e5cf058--779982515 | WallQuantities - GrossSideAreaRight: 9.37385 m2; GrossSideAreaLeft: 9.39492 m2; NetSideAreaRight: 9.37385 m2; NetSideAreaLeft: 9.39492 m2; Allplan Attributes - Object Layer Attributes #2, Allright_Comp_ID: 0024Wal0779982507; Object Layer Attributes #2, Building alteration category: New building; Object Layer Attributes #2, Unit: m³; Object Layer Attributes #2, NOI_UUID: ffc0a4b9-6ff1-450c-9901-90887e5cf058--779982507; Object Layer Attributes #3, Allright_Comp_ID: 0024Wal0779982500; Object Layer Attributes #3, Building alteration category: New building; Object Layer Attributes #3, Unit: m³; Object Layer Attributes #3, NOI_UUID: ffc0a4b9-6ff1-450c-9901-90887e5cf058--779982500
 | Plan 2 | gips 13 mm, riegel stål 100 100 mm, gips 13 mm | 2.43231 | 1.92452 |  |  | 5.159 | 0.126 | 0.652557 | 3.72803 | 0024HWa0779992724 | ffc0a4b9-6ff1-450c-9901-90887e5cf058--779992724 | 0024Wal0779992745 | m³ | ffc0a4b9-6ff1-450c-9901-90887e5cf058--779992745 | WallQuantities - GrossSideAreaRight: 19.3822 m2; GrossSideAreaLeft: 18.9803 m2; NetSideAreaRight: 15.3521 m2; NetSideAreaLeft: 14.9502 m2; Allplan Attributes - Object Layer Attributes #2, Allright_Comp_ID: 0024Wal0779992744; Object Layer Attributes #2, Building alteration category: New building; Object Layer Attributes #2, Unit: m³; Object Layer Attributes #2, NOI_UUID: ffc0a4b9-6ff1-450c-9901-90887e5cf058--779992744; Object Layer Attributes #3, Allright_Comp_ID: 0024Wal0779992743; Object Layer Attributes #3, Building alteration category: New building; Object Layer Attributes #3, Unit: m³; Object Layer Attributes #3, NOI_UUID: ffc0a4b9-6ff1-450c-9901-90887e5cf058--779992743
 | Plan 2 | gips 13 mm, riegel stål 100 100 mm, gips 13 mm | 1.04684 | 0.778317 |  |  | 2.242 | 0.126 | 0.279969 | 3.73913 | 0024HWa0779982607 | ffc0a4b9-6ff1-450c-9901-90887e5cf058--779982607 | 0024Wal0779982608 | m³ | ffc0a4b9-6ff1-450c-9901-90887e5cf058--779982608 | WallQuantities - GrossSideAreaRight: 8.6399 m2; GrossSideAreaLeft: 8.23438 m2; NetSideAreaRight: 6.5088 m2; NetSideAreaLeft: 6.10328 m2; Allplan Attributes - Object Layer Attributes #2, Allright_Comp_ID: 0024Wal0779982609; Object Layer Attributes #2, Building alteration category: New building; Object Layer Attributes #2, Unit: m³; Object Layer Attributes #2, NOI_UUID: ffc0a4b9-6ff1-450c-9901-90887e5cf058--779982609; Object Layer Attributes #3, Allright_Comp_ID: 0024Wal0779982610; Object Layer Attributes #3, Building alteration category: New building; Object Layer Attributes #3, Unit: m³; Object Layer Attributes #3, NOI_UUID: ffc0a4b9-6ff1-450c-9901-90887e5cf058--779982610
 | Plan 2 | gips 13 mm, riegel stål 100 100 mm, gips 13 mm | 1.18061 | 1.18061 |  |  | 2.434 | 0.126 | 0.309207 | 3.81887 | 0024HWa0780026020 | ffc0a4b9-6ff1-450c-9901-90887e5cf058--780026020 | 0024Wal0780026021 | m³ | ffc0a4b9-6ff1-450c-9901-90887e5cf058--780026021 | WallQuantities - GrossSideAreaRight: 9.02957 m2; GrossSideAreaLeft: 9.45205 m2; NetSideAreaRight: 9.02957 m2; NetSideAreaLeft: 9.45205 m2; Allplan Attributes - Object Layer Attributes #2, Allright_Comp_ID: 0024Wal0780026022; Object Layer Attributes #2, Building alteration category: New building; Object Layer Attributes #2, Unit: m³; Object Layer Attributes #2, NOI_UUID: ffc0a4b9-6ff1-450c-9901-90887e5cf058--780026022; Object Layer Attributes #3, Allright_Comp_ID: 0024Wal0780026023; Object Layer Attributes #3, Building alteration category: New building; Object Layer Attributes #3, Unit: m³; Object Layer Attributes #3, NOI_UUID: ffc0a4b9-6ff1-450c-9901-90887e5cf058--780026023
 | Plan 2 | gips 13 mm, riegel stål 100 148 mm, gips 13 mm | 2.88684 | 2.88684 |  |  | 5.075 | 0.174 | 0.88305 | 3.26917 | 0024HWa0779985492 | ffc0a4b9-6ff1-450c-9901-90887e5cf058--779985492 | 0024Wal0779985495 | m³ | ffc0a4b9-6ff1-450c-9901-90887e5cf058--779985495 | WallQuantities - GrossSideAreaRight: 16.591 m2; GrossSideAreaLeft: 16.591 m2; NetSideAreaRight: 16.591 m2; NetSideAreaLeft: 16.591 m2; Allplan Attributes - Object Layer Attributes #2, Allright_Comp_ID: 0024Wal0779985494; Object Layer Attributes #2, Building alteration category: New building; Object Layer Attributes #2, Unit: m³; Object Layer Attributes #2, NOI_UUID: ffc0a4b9-6ff1-450c-9901-90887e5cf058--779985494; Object Layer Attributes #3, Allright_Comp_ID: 0024Wal0779985493; Object Layer Attributes #3, Building alteration category: New building; Object Layer Attributes #3, Unit: m³; Object Layer Attributes #3, NOI_UUID: ffc0a4b9-6ff1-450c-9901-90887e5cf058--779985493
 | Plan 2 | gips 13 mm, riegel stål 100 150 mm, gips 13 mm | 1.52976 | 1.52976 |  |  | 2.73161 | 0.176 | 0.480171 | 3.18587 | 0024HWa0779989055 | ffc0a4b9-6ff1-450c-9901-90887e5cf058--779989055 | 0024Wal0779989061 | m³ | ffc0a4b9-6ff1-450c-9901-90887e5cf058--779989061 | WallQuantities - GrossSideAreaRight: 8.74507 m2; GrossSideAreaLeft: 8.67395 m2; NetSideAreaRight: 8.74507 m2; NetSideAreaLeft: 8.67395 m2; Allplan Attributes - Object Layer Attributes #2, Allright_Comp_ID: 0024Wal0779989060; Object Layer Attributes #2, Building alteration category: New building; Object Layer Attributes #2, Unit: m³; Object Layer Attributes #2, NOI_UUID: ffc0a4b9-6ff1-450c-9901-90887e5cf058--779989060; Object Layer Attributes #3, Allright_Comp_ID: 0024Wal0779989059; Object Layer Attributes #3, Building alteration category: New building; Object Layer Attributes #3, Unit: m³; Object Layer Attributes #3, NOI_UUID: ffc0a4b9-6ff1-450c-9901-90887e5cf058--779989059
 | Plan 2 | Betong 50 mm | 0.250521 | 0.156021 | 5.01042 | 3.12042 | 1.25 | 0.05 | 0.0625 | 4.00833 | 0024HWa0780023189 | ffc0a4b9-6ff1-450c-9901-90887e5cf058--780023189 | 0024Wal0780023210 | m² | ffc0a4b9-6ff1-450c-9901-90887e5cf058--780023210 | Allplan Attributes - Object Layer Attributes #1, Material: Betong
 | Plan 2 | Betong 50 mm | 0.257396 | 0.257396 | 5.14792 | 5.14792 | 1.25 | 0.05 | 0.0625 | 4.11833 | 0024HWa0780023198 | ffc0a4b9-6ff1-450c-9901-90887e5cf058--780023198 | 0024Wal0780023212 | m² | ffc0a4b9-6ff1-450c-9901-90887e5cf058--780023212 | Allplan Attributes - Object Layer Attributes #1, Material: Betong
 | Plan 2 | Betong 50 mm | 0.325067 | 0.325067 | 6.50133 | 6.50133 | 1.6 | 0.05 | 0.08 | 4.06333 | 0024HWa0780023200 | ffc0a4b9-6ff1-450c-9901-90887e5cf058--780023200 | 0024Wal0780023203 | m² | ffc0a4b9-6ff1-450c-9901-90887e5cf058--780023203 | Allplan Attributes - Object Layer Attributes #1, Material: Betong
 | Plan 2 | Betong 50 mm | 0.345383 | 0.345383 | 6.90767 | 6.90767 | 1.7 | 0.05 | 0.085 | 4.06333 | 0024HWa0780023204 | ffc0a4b9-6ff1-450c-9901-90887e5cf058--780023204 | 0024Wal0780023207 | m² | ffc0a4b9-6ff1-450c-9901-90887e5cf058--780023207 | Allplan Attributes - Object Layer Attributes #1, Material: Betong
 | Plan 2 | gips 13 mm, riegel stål 100 100 mm, gips 13 mm | 0.845165 | 0.845165 |  |  | 1.766 | 0.126 | 0.219993 | 3.84113 | 0024HWa0780025943 | ffc0a4b9-6ff1-450c-9901-90887e5cf058--780025943 | 0024Wal0780025944 | m³ | ffc0a4b9-6ff1-450c-9901-90887e5cf058--780025944 | WallQuantities - GrossSideAreaRight: 7.05181 m2; GrossSideAreaLeft: 6.62453 m2; NetSideAreaRight: 7.05181 m2; NetSideAreaLeft: 6.62453 m2; Allplan Attributes - Object Layer Attributes #2, Allright_Comp_ID: 0024Wal0780025945; Object Layer Attributes #2, Building alteration category: New building; Object Layer Attributes #2, Unit: m³; Object Layer Attributes #2, NOI_UUID: ffc0a4b9-6ff1-450c-9901-90887e5cf058--780025945; Object Layer Attributes #3, Allright_Comp_ID: 0024Wal0780025946; Object Layer Attributes #3, Building alteration category: New building; Object Layer Attributes #3, Unit: m³; Object Layer Attributes #3, NOI_UUID: ffc0a4b9-6ff1-450c-9901-90887e5cf058--780025946
 | Plan 2 | gips 13 mm, riegel stål 100 100 mm, gips 13 mm | 0.604583 | 0.336064 |  |  | 1.24908 | 0.126 | 0.159907 | 3.78087 | 0024HWa0780026044 | ffc0a4b9-6ff1-450c-9901-90887e5cf058--780026044 | 0024Wal0780026045 | m³ | ffc0a4b9-6ff1-450c-9901-90887e5cf058--780026045 | WallQuantities - GrossSideAreaRight: 4.87655 m2; GrossSideAreaLeft: 4.45861 m2; NetSideAreaRight: 2.74545 m2; NetSideAreaLeft: 2.32751 m2; Allplan Attributes - Object Layer Attributes #2, Allright_Comp_ID: 0024Wal0780026046; Object Layer Attributes #2, Building alteration category: New building; Object Layer Attributes #2, Unit: m³; Object Layer Attributes #2, NOI_UUID: ffc0a4b9-6ff1-450c-9901-90887e5cf058--780026046; Object Layer Attributes #3, Allright_Comp_ID: 0024Wal0780026047; Object Layer Attributes #3, Building alteration category: New building; Object Layer Attributes #3, Unit: m³; Object Layer Attributes #3, NOI_UUID: ffc0a4b9-6ff1-450c-9901-90887e5cf058--780026047

# IfcWindow: IV001
In: Plan 1
Type - OperationType: USERDEFINED; ParameterTakesPrecedence: no; Sizeable: no
OverallHeight: 2110 mm; OverallWidth: 1010 mm
Allplan Attributes - Allright_Comp_ID: 0014Sym0780032213; Unit: Pc; V6: 0; V7: 0; V8: 0; V9: 0; Release: 3.0; Name: IV001; Plugin_name: MainObject; Plugin_object_name: SmartPartCompressed; GlazingAreaFraction_Consider: 100; NOI_UUID: b4870d4d-918a-46e5-81bc-d8f6664cc458--780032213; IFC Object type: IfcWindow; Version: 5.0; Glass surface: 1.6465; Height_window_sill_outside: 0; Height_window_sill_inside: 0; Offset_opening_bottom: 0; Offset_opening_top: 10; Offset_opening_left: 10; Offset_opening_right: 10; Deduction_opening_bottom: 70; Deduction_opening_left: 70; Deduction_opening_right: 70; Deduction_opening_top: 70

# IfcWindow: IV002
In: Plan 1
Type - OperationType: USERDEFINED; ParameterTakesPrecedence: no; Sizeable: no
OverallHeight: 2110 mm; OverallWidth: 1010 mm
Allplan Attributes - Allright_Comp_ID: 0014Sym0780032234; Unit: Pc; V6: 0; V7: 0; V8: 0; V9: 0; Release: 3.0; Name: IV002; Plugin_name: MainObject; Plugin_object_name: SmartPartCompressed; GlazingAreaFraction_Consider: 100; NOI_UUID: b4870d4d-918a-46e5-81bc-d8f6664cc458--780032234; IFC Object type: IfcWindow; Version: 5.0; Glass surface: 1.6465; Height_window_sill_outside: 0; Height_window_sill_inside: 0; Offset_opening_bottom: 0; Offset_opening_top: 10; Offset_opening_left: 10; Offset_opening_right: 10; Deduction_opening_bottom: 70; Deduction_opening_left: 70; Deduction_opening_right: 70; Deduction_opening_top: 70

# IfcWindow: IV101
In: Plan 2
Type - OperationType: USERDEFINED; ParameterTakesPrecedence: no; Sizeable: no
OverallHeight: 2110 mm; OverallWidth: 1010 mm
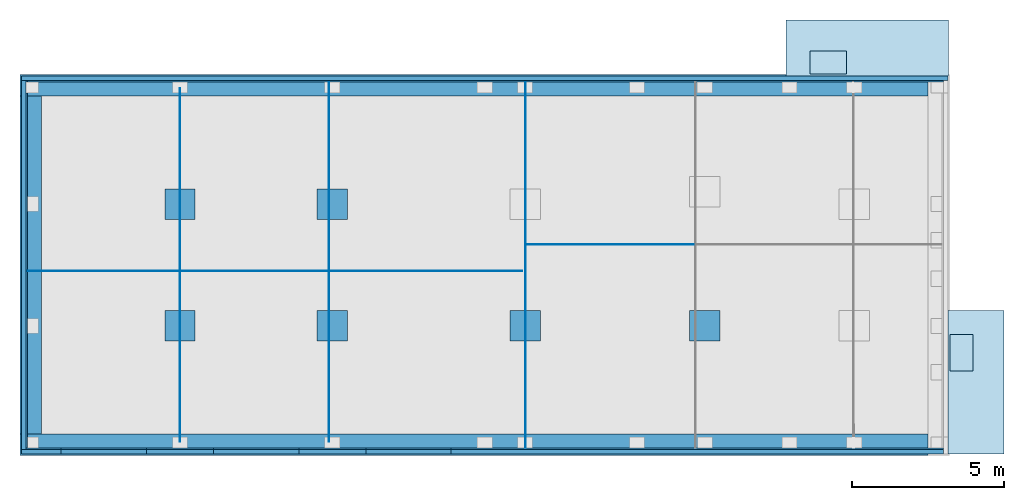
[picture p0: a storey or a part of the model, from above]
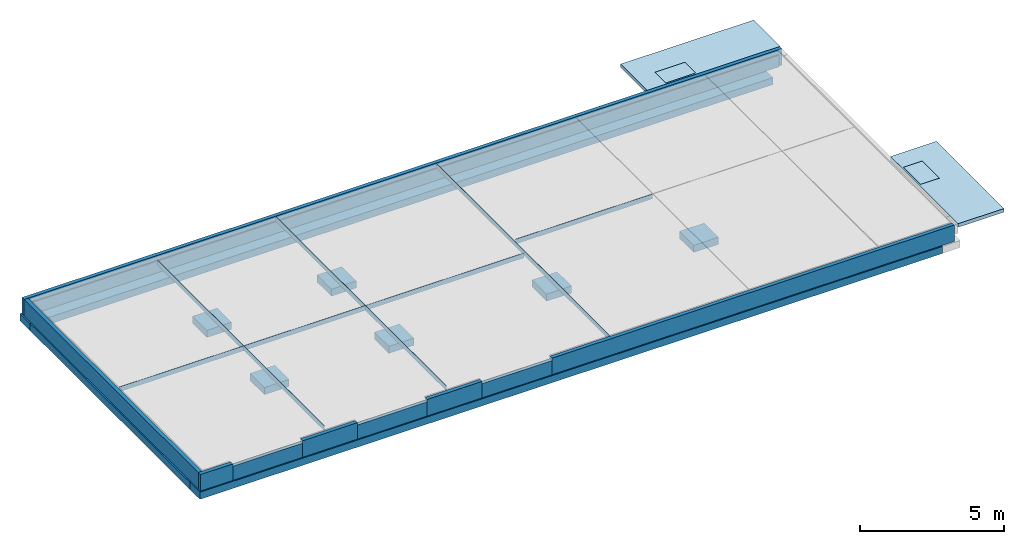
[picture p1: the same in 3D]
Properties of the parts of a building model (IFC2X3), part 7 of 7

# IfcWindow: IV101
Allplan Attributes - Allright_Comp_ID: 0024Sym0780028701; Unit: Pc; V6: 0; V7: 0; V8: 0; V9: 0; Release: 3.0; Name: IV101; Plugin_name: MainObject; Plugin_object_name: SmartPartCompressed; GlazingAreaFraction_Consider: 100; NOI_UUID: ffc0a4b9-6ff1-450c-9901-90887e5cf058--780028701; IFC Object type: IfcWindow; Version: 5.0; Glass surface: 1.6465; Height_window_sill_outside: 0; Height_window_sill_inside: 0; Offset_opening_bottom: 0; Offset_opening_top: 10; Offset_opening_left: 10; Offset_opening_right: 10; Deduction_opening_bottom: 70; Deduction_opening_left: 70; Deduction_opening_right: 70; Deduction_opening_top: 70

# IfcWindow: IV102
In: Plan 2
Type - OperationType: USERDEFINED; ParameterTakesPrecedence: no; Sizeable: no
OverallHeight: 2110 mm; OverallWidth: 1010 mm
Allplan Attributes - Allright_Comp_ID: 0024Sym0780028781; Unit: Pc; V6: 0; V7: 0; V8: 0; V9: 0; Release: 3.0; Name: IV102; Plugin_name: MainObject; Plugin_object_name: SmartPartCompressed; GlazingAreaFraction_Consider: 100; NOI_UUID: ffc0a4b9-6ff1-450c-9901-90887e5cf058--780028781; IFC Object type: IfcWindow; Version: 5.0; Glass surface: 1.6465; Height_window_sill_outside: 0; Height_window_sill_inside: 0; Offset_opening_bottom: 0; Offset_opening_top: 10; Offset_opening_left: 10; Offset_opening_right: 10; Deduction_opening_bottom: 70; Deduction_opening_left: 70; Deduction_opening_right: 70; Deduction_opening_top: 70

# IfcWindow: IV103
In: Plan 2
Type - OperationType: USERDEFINED; ParameterTakesPrecedence: no; Sizeable: no
OverallHeight: 2110 mm; OverallWidth: 1010 mm
Allplan Attributes - Allright_Comp_ID: 0024Sym0780028807; Unit: Pc; V6: 0; V7: 0; V8: 0; V9: 0; Release: 3.0; Name: IV103; Plugin_name: MainObject; Plugin_object_name: SmartPartCompressed; GlazingAreaFraction_Consider: 100; NOI_UUID: ffc0a4b9-6ff1-450c-9901-90887e5cf058--780028807; IFC Object type: IfcWindow; Version: 5.0; Glass surface: 1.6465; Height_window_sill_outside: 0; Height_window_sill_inside: 0; Offset_opening_bottom: 0; Offset_opening_top: 10; Offset_opening_left: 10; Offset_opening_right: 10; Deduction_opening_bottom: 70; Deduction_opening_left: 70; Deduction_opening_right: 70; Deduction_opening_top: 70

# IfcWindow: IV104
In: Plan 2
Type - OperationType: USERDEFINED; ParameterTakesPrecedence: no; Sizeable: no
OverallHeight: 2110 mm; OverallWidth: 1010 mm
Allplan Attributes - Allright_Comp_ID: 0024Sym0780028855; Unit: Pc; V6: 0; V7: 0; V8: 0; V9: 0; Release: 3.0; Name: IV104; Plugin_name: MainObject; Plugin_object_name: SmartPartCompressed; GlazingAreaFraction_Consider: 100; NOI_UUID: ffc0a4b9-6ff1-450c-9901-90887e5cf058--780028855; IFC Object type: IfcWindow; Version: 5.0; Glass surface: 1.6465; Height_window_sill_outside: 0; Height_window_sill_inside: 0; Offset_opening_bottom: 0; Offset_opening_top: 10; Offset_opening_left: 10; Offset_opening_right: 10; Deduction_opening_bottom: 70; Deduction_opening_left: 70; Deduction_opening_right: 70; Deduction_opening_top: 70

# IfcWindow: IV105
In: Plan 2
Type - OperationType: USERDEFINED; ParameterTakesPrecedence: no; Sizeable: no
OverallHeight: 2110 mm; OverallWidth: 1010 mm
Allplan Attributes - Allright_Comp_ID: 0024Sym0780028833; Unit: Pc; V6: 0; V7: 0; V8: 0; V9: 0; Release: 3.0; Name: IV105; Plugin_name: MainObject; Plugin_object_name: SmartPartCompressed; GlazingAreaFraction_Consider: 100; NOI_UUID: ffc0a4b9-6ff1-450c-9901-90887e5cf058--780028833; IFC Object type: IfcWindow; Version: 5.0; Glass surface: 1.6465; Height_window_sill_outside: 0; Height_window_sill_inside: 0; Offset_opening_bottom: 0; Offset_opening_top: 10; Offset_opening_left: 10; Offset_opening_right: 10; Deduction_opening_bottom: 70; Deduction_opening_left: 70; Deduction_opening_right: 70; Deduction_opening_top: 70

# IfcWindow: IV106
In: Plan 2
Type - OperationType: USERDEFINED; ParameterTakesPrecedence: no; Sizeable: no
OverallHeight: 2110 mm; OverallWidth: 1010 mm
Allplan Attributes - Allright_Comp_ID: 0024Sym0780028888; Unit: Pc; V6: 0; V7: 0; V8: 0; V9: 0; Release: 3.0; Name: IV106; Plugin_name: MainObject; Plugin_object_name: SmartPartCompressed; GlazingAreaFraction_Consider: 100; NOI_UUID: ffc0a4b9-6ff1-450c-9901-90887e5cf058--780028888; IFC Object type: IfcWindow; Version: 5.0; Glass surface: 1.6465; Height_window_sill_outside: 0; Height_window_sill_inside: 0; Offset_opening_bottom: 0; Offset_opening_top: 10; Offset_opening_left: 10; Offset_opening_right: 10; Deduction_opening_bottom: 70; Deduction_opening_left: 70; Deduction_opening_right: 70; Deduction_opening_top: 70

# IfcWindow: IV107
In: Plan 2
Type - OperationType: USERDEFINED; ParameterTakesPrecedence: no; Sizeable: no
OverallHeight: 2110 mm; OverallWidth: 1010 mm
Allplan Attributes - Allright_Comp_ID: 0024Sym0780028866; Unit: Pc; V6: 0; V7: 0; V8: 0; V9: 0; Release: 3.0; Name: IV107; Plugin_name: MainObject; Plugin_object_name: SmartPartCompressed; GlazingAreaFraction_Consider: 100; NOI_UUID: ffc0a4b9-6ff1-450c-9901-90887e5cf058--780028866; IFC Object type: IfcWindow; Version: 5.0; Glass surface: 1.6465; Height_window_sill_outside: 0; Height_window_sill_inside: 0; Offset_opening_bottom: 0; Offset_opening_top: 10; Offset_opening_left: 10; Offset_opening_right: 10; Deduction_opening_bottom: 70; Deduction_opening_left: 70; Deduction_opening_right: 70; Deduction_opening_top: 70

# IfcWindow: IV108
In: Plan 2
Type - OperationType: USERDEFINED; ParameterTakesPrecedence: no; Sizeable: no
OverallHeight: 2110 mm; OverallWidth: 1010 mm
Allplan Attributes - Allright_Comp_ID: 0024Sym0780028877; Unit: Pc; V6: 0; V7: 0; V8: 0; V9: 0; Release: 3.0; Name: IV108; Plugin_name: MainObject; Plugin_object_name: SmartPartCompressed; GlazingAreaFraction_Consider: 100; NOI_UUID: ffc0a4b9-6ff1-450c-9901-90887e5cf058--780028877; IFC Object type: IfcWindow; Version: 5.0; Glass surface: 1.6465; Height_window_sill_outside: 0; Height_window_sill_inside: 0; Offset_opening_bottom: 0; Offset_opening_top: 10; Offset_opening_left: 10; Offset_opening_right: 10; Deduction_opening_bottom: 70; Deduction_opening_left: 70; Deduction_opening_right: 70; Deduction_opening_top: 70

# IfcWindow: IV109
In: Plan 2
Type - OperationType: USERDEFINED; ParameterTakesPrecedence: no; Sizeable: no
OverallHeight: 2110 mm; OverallWidth: 1010 mm
Allplan Attributes - Allright_Comp_ID: 0024Sym0780028844; Unit: Pc; V6: 0; V7: 0; V8: 0; V9: 0; Release: 3.0; Name: IV109; Plugin_name: MainObject; Plugin_object_name: SmartPartCompressed; GlazingAreaFraction_Consider: 100; NOI_UUID: ffc0a4b9-6ff1-450c-9901-90887e5cf058--780028844; IFC Object type: IfcWindow; Version: 5.0; Glass surface: 1.6465; Height_window_sill_outside: 0; Height_window_sill_inside: 0; Offset_opening_bottom: 0; Offset_opening_top: 10; Offset_opening_left: 10; Offset_opening_right: 10; Deduction_opening_bottom: 70; Deduction_opening_left: 70; Deduction_opening_right: 70; Deduction_opening_top: 70

# IfcWindow: V101
In: Plan 1
Type - OperationType: USERDEFINED; ParameterTakesPrecedence: no; Sizeable: no
OverallHeight: 1110 mm; OverallWidth: 610 mm
Allplan Attributes - Allright_Comp_ID: 0013Sym0780051110; Unit: Pc; V6: 0; V7: 0; V8: 0; V9: 0; Release: 3.0; Name: V101; Plugin_name: MainObject; Plugin_object_name: SmartPartCompressed; GlazingAreaFraction_Consider: 100; NOI_UUID: d1eb0bd9-ddf6-4315-a806-967de25454b1--780051110; IFC Object type: IfcWindow; Version: 5.0; Glass surface: 0.3999; Height_window_sill_outside: 0; Height_window_sill_inside: 0; Offset_opening_bottom: 10; Offset_opening_top: 10; Offset_opening_left: 10; Offset_opening_right: 10; Deduction_opening_bottom: 60; Deduction_opening_left: 60; Deduction_opening_right: 60; Deduction_opening_top: 60

# IfcWindow: V102
In: Plan 1
Type - OperationType: USERDEFINED; ParameterTakesPrecedence: no; Sizeable: no
OverallHeight: 2410 mm; OverallWidth: 2410 mm
Allplan Attributes - Allright_Comp_ID: 0013Sym0780051140; Unit: Pc; V6: 0; V7: 0; V8: 0; V9: 0; Release: 3.0; Name: V102; Plugin_name: MainObject; Plugin_object_name: SmartPartCompressed; GlazingAreaFraction_Consider: 100; NOI_UUID: d1eb0bd9-ddf6-4315-a806-967de25454b1--780051140; IFC Object type: IfcWindow; Version: 5.0; Glass surface: 5.0176; Height_window_sill_outside: 0; Height_window_sill_inside: 0; Offset_opening_bottom: 10; Offset_opening_top: 10; Offset_opening_left: 10; Offset_opening_right: 10; Deduction_opening_bottom: 60; Deduction_opening_left: 60; Deduction_opening_right: 60; Deduction_opening_top: 60

# IfcWindow: V103
In: Plan 1
Type - OperationType: USERDEFINED; ParameterTakesPrecedence: no; Sizeable: no
OverallHeight: 2410 mm; OverallWidth: 1110 mm
Allplan Attributes - Allright_Comp_ID: 0013Sym0780051161; Unit: Pc; V6: 0; V7: 0; V8: 0; V9: 0; Release: 3.0; Name: V103; Plugin_name: MainObject; Plugin_object_name: SmartPartCompressed; GlazingAreaFraction_Consider: 100; NOI_UUID: d1eb0bd9-ddf6-4315-a806-967de25454b1--780051161; IFC Object type: IfcWindow; Version: 5.0; Glass surface: 2.2176; Height_window_sill_outside: 0; Height_window_sill_inside: 0; Offset_opening_bottom: 10; Offset_opening_top: 10; Offset_opening_left: 10; Offset_opening_right: 10; Deduction_opening_bottom: 60; Deduction_opening_left: 60; Deduction_opening_right: 60; Deduction_opening_top: 60

# IfcWindow: V104
In: Plan 1
Type - OperationType: USERDEFINED; ParameterTakesPrecedence: no; Sizeable: no
OverallHeight: 1110 mm; OverallWidth: 1710 mm
Allplan Attributes - Allright_Comp_ID: 0013Sym0780051278; Unit: Pc; V6: 0; V7: 0; V8: 0; V9: 0; Release: 3.0; Name: V104; Plugin_name: MainObject; Plugin_object_name: SmartPartCompressed; GlazingAreaFraction_Consider: 100; NOI_UUID: d1eb0bd9-ddf6-4315-a806-967de25454b1--780051278; IFC Object type: IfcWindow; Version: 5.0; Glass surface: 1.4328; Height_window_sill_outside: 0; Height_window_sill_inside: 0; Offset_opening_bottom: 10; Offset_opening_top: 10; Offset_opening_left: 10; Offset_opening_right: 10; Deduction_opening_bottom: 50; Deduction_opening_left: 50; Deduction_opening_right: 50; Deduction_opening_top: 50

# IfcWindow: V105
In: Plan 1
Type - OperationType: USERDEFINED; ParameterTakesPrecedence: no; Sizeable: no
OverallHeight: 1110 mm; OverallWidth: 610 mm
Allplan Attributes - Allright_Comp_ID: 0013Sym0780051470; Unit: Pc; V6: 0; V7: 0; V8: 0; V9: 0; Release: 3.0; Name: V105; Plugin_name: MainObject; Plugin_object_name: SmartPartCompressed; GlazingAreaFraction_Consider: 100; NOI_UUID: d1eb0bd9-ddf6-4315-a806-967de25454b1--780051470; IFC Object type: IfcWindow; Version: 5.0; Glass surface: 0.3999; Height_window_sill_outside: 0; Height_window_sill_inside: 0; Offset_opening_bottom: 10; Offset_opening_top: 10; Offset_opening_left: 10; Offset_opening_right: 10; Deduction_opening_bottom: 60; Deduction_opening_left: 60; Deduction_opening_right: 60; Deduction_opening_top: 60

# IfcWindow: V106
In: Plan 1
Type - OperationType: USERDEFINED; ParameterTakesPrecedence: no; Sizeable: no
OverallHeight: 1110 mm; OverallWidth: 610 mm
Allplan Attributes - Allright_Comp_ID: 0013Sym0780051454; Unit: Pc; V6: 0; V7: 0; V8: 0; V9: 0; Release: 3.0; Name: V106; Plugin_name: MainObject; Plugin_object_name: SmartPartCompressed; GlazingAreaFraction_Consider: 100; NOI_UUID: d1eb0bd9-ddf6-4315-a806-967de25454b1--780051454; IFC Object type: IfcWindow; Version: 5.0; Glass surface: 0.3999; Height_window_sill_outside: 0; Height_window_sill_inside: 0; Offset_opening_bottom: 10; Offset_opening_top: 10; Offset_opening_left: 10; Offset_opening_right: 10; Deduction_opening_bottom: 60; Deduction_opening_left: 60; Deduction_opening_right: 60; Deduction_opening_top: 60

# IfcWindow: V107
In: Plan 1
Type - OperationType: USERDEFINED; ParameterTakesPrecedence: no; Sizeable: no
OverallHeight: 1110 mm; OverallWidth: 610 mm
Allplan Attributes - Allright_Comp_ID: 0013Sym0780051398; Unit: Pc; V6: 0; V7: 0; V8: 0; V9: 0; Release: 3.0; Name: V107; Plugin_name: MainObject; Plugin_object_name: SmartPartCompressed; GlazingAreaFraction_Consider: 100; NOI_UUID: d1eb0bd9-ddf6-4315-a806-967de25454b1--780051398; IFC Object type: IfcWindow; Version: 5.0; Glass surface: 0.3999; Height_window_sill_outside: 0; Height_window_sill_inside: 0; Offset_opening_bottom: 10; Offset_opening_top: 10; Offset_opening_left: 10; Offset_opening_right: 10; Deduction_opening_bottom: 60; Deduction_opening_left: 60; Deduction_opening_right: 60; Deduction_opening_top: 60

# IfcWindow: V201
In: Plan 2
Type - OperationType: USERDEFINED; ParameterTakesPrecedence: no; Sizeable: no
OverallHeight: 1210 mm; OverallWidth: 1710 mm
Allplan Attributes - Allright_Comp_ID: 0023Sym0780007127; Unit: Pc; V6: 0; V7: 0; V8: 0; V9: 0; Release: 3.0; Name: V201; Plugin_name: MainObject; Plugin_object_name: SmartPartCompressed; GlazingAreaFraction_Consider: 100; NOI_UUID: 84cb5e05-e28d-4939-8977-531e4630a18c--780007127; IFC Object type: IfcWindow; Version: 5.0; Glass surface: 1.6786; Height_window_sill_outside: 0; Height_window_sill_inside: 0; Offset_opening_bottom: 10; Offset_opening_top: 10; Offset_opening_left: 10; Offset_opening_right: 10; Deduction_opening_bottom: 50; Deduction_opening_left: 50; Deduction_opening_right: 50; Deduction_opening_top: 50

# IfcWindow: V202
In: Plan 2
Type - OperationType: USERDEFINED; ParameterTakesPrecedence: no; Sizeable: no
OverallHeight: 1210 mm; OverallWidth: 1710 mm
Allplan Attributes - Allright_Comp_ID: 0023Sym0780007130; Unit: Pc; V6: 0; V7: 0; V8: 0; V9: 0; Release: 3.0; Name: V202; Plugin_name: MainObject; Plugin_object_name: SmartPartCompressed; GlazingAreaFraction_Consider: 100; NOI_UUID: 84cb5e05-e28d-4939-8977-531e4630a18c--780007130; IFC Object type: IfcWindow; Version: 5.0; Glass surface: 1.6786; Height_window_sill_outside: 0; Height_window_sill_inside: 0; Offset_opening_bottom: 10; Offset_opening_top: 10; Offset_opening_left: 10; Offset_opening_right: 10; Deduction_opening_bottom: 50; Deduction_opening_left: 50; Deduction_opening_right: 50; Deduction_opening_top: 50

# IfcWindow: V203
In: Plan 2
Type - OperationType: USERDEFINED; ParameterTakesPrecedence: no; Sizeable: no
OverallHeight: 1210 mm; OverallWidth: 1710 mm
Allplan Attributes - Allright_Comp_ID: 0023Sym0780007165; Unit: Pc; V6: 0; V7: 0; V8: 0; V9: 0; Release: 3.0; Name: V203; Plugin_name: MainObject; Plugin_object_name: SmartPartCompressed; GlazingAreaFraction_Consider: 100; NOI_UUID: 84cb5e05-e28d-4939-8977-531e4630a18c--780007165; IFC Object type: IfcWindow; Version: 5.0; Glass surface: 1.5808; Height_window_sill_outside: 0; Height_window_sill_inside: 0; Offset_opening_bottom: 10; Offset_opening_top: 10; Offset_opening_left: 10; Offset_opening_right: 10; Deduction_opening_bottom: 50; Deduction_opening_left: 50; Deduction_opening_right: 50; Deduction_opening_top: 50

# IfcWindow: V204
In: Plan 2
Type - OperationType: USERDEFINED; ParameterTakesPrecedence: no; Sizeable: no
OverallHeight: 2410 mm; OverallWidth: 1110 mm
Allplan Attributes - Allright_Comp_ID: 0023Sym0780007421; Unit: Pc; V6: 0; V7: 0; V8: 0; V9: 0; Release: 3.0; Name: V204; Plugin_name: MainObject; Plugin_object_name: SmartPartCompressed; GlazingAreaFraction_Consider: 100; NOI_UUID: 84cb5e05-e28d-4939-8977-531e4630a18c--780007421; IFC Object type: IfcWindow; Version: 5.0; Glass surface: 2.2176; Height_window_sill_outside: 0; Height_window_sill_inside: 0; Offset_opening_bottom: 10; Offset_opening_top: 10; Offset_opening_left: 10; Offset_opening_right: 10; Deduction_opening_bottom: 60; Deduction_opening_left: 60; Deduction_opening_right: 60; Deduction_opening_top: 60

# IfcWindow: V205
In: Plan 2
Type - OperationType: USERDEFINED; ParameterTakesPrecedence: no; Sizeable: no
OverallHeight: 2410 mm; OverallWidth: 2410 mm
Allplan Attributes - Allright_Comp_ID: 0023Sym0780007527; Unit: Pc; V6: 0; V7: 0; V8: 0; V9: 0; Release: 3.0; Name: V205; Plugin_name: MainObject; Plugin_object_name: SmartPartCompressed; GlazingAreaFraction_Consider: 100; NOI_UUID: 84cb5e05-e28d-4939-8977-531e4630a18c--780007527; IFC Object type: IfcWindow; Version: 5.0; Glass surface: 5.0176; Height_window_sill_outside: 0; Height_window_sill_inside: 0; Offset_opening_bottom: 10; Offset_opening_top: 10; Offset_opening_left: 10; Offset_opening_right: 10; Deduction_opening_bottom: 60; Deduction_opening_left: 60; Deduction_opening_right: 60; Deduction_opening_top: 60

# IfcWindow: V206
In: Plan 2
Type - OperationType: USERDEFINED; ParameterTakesPrecedence: no; Sizeable: no
OverallHeight: 2410 mm; OverallWidth: 1110 mm
Allplan Attributes - Allright_Comp_ID: 0023Sym0780007467; Unit: Pc; V6: 0; V7: 0; V8: 0; V9: 0; Release: 3.0; Name: V206; Plugin_name: MainObject; Plugin_object_name: SmartPartCompressed; GlazingAreaFraction_Consider: 100; NOI_UUID: 84cb5e05-e28d-4939-8977-531e4630a18c--780007467; IFC Object type: IfcWindow; Version: 5.0; Glass surface: 2.2176; Height_window_sill_outside: 0; Height_window_sill_inside: 0; Offset_opening_bottom: 10; Offset_opening_top: 10; Offset_opening_left: 10; Offset_opening_right: 10; Deduction_opening_bottom: 60; Deduction_opening_left: 60; Deduction_opening_right: 60; Deduction_opening_top: 60

# IfcWindow: V207
In: Plan 2
Type - OperationType: USERDEFINED; ParameterTakesPrecedence: no; Sizeable: no
OverallHeight: 1210 mm; OverallWidth: 610 mm
Allplan Attributes - Allright_Comp_ID: 0023Sym0780007641; Unit: Pc; V6: 0; V7: 0; V8: 0; V9: 0; Release: 3.0; Name: V207; Plugin_name: MainObject; Plugin_object_name: SmartPartCompressed; GlazingAreaFraction_Consider: 100; NOI_UUID: 84cb5e05-e28d-4939-8977-531e4630a18c--780007641; IFC Object type: IfcWindow; Version: 5.0; Glass surface: 0.4429; Height_window_sill_outside: 0; Height_window_sill_inside: 0; Offset_opening_bottom: 10; Offset_opening_top: 10; Offset_opening_left: 10; Offset_opening_right: 10; Deduction_opening_bottom: 60; Deduction_opening_left: 60; Deduction_opening_right: 60; Deduction_opening_top: 60

# IfcWindow: V208
In: Plan 2
Type - OperationType: USERDEFINED; ParameterTakesPrecedence: no; Sizeable: no
OverallHeight: 2110 mm; OverallWidth: 1110 mm
Allplan Attributes - Allright_Comp_ID: 0023Sym0780007666; Unit: Pc; V6: 0; V7: 0; V8: 0; V9: 0; Release: 3.0; Name: V208; Plugin_name: MainObject; Plugin_object_name: SmartPartCompressed; GlazingAreaFraction_Consider: 100; NOI_UUID: 84cb5e05-e28d-4939-8977-531e4630a18c--780007666; IFC Object type: IfcWindow; Version: 5.0; Glass surface: 1.9206; Height_window_sill_outside: 0; Height_window_sill_inside: 0; Offset_opening_bottom: 10; Offset_opening_top: 10; Offset_opening_left: 10; Offset_opening_right: 10; Deduction_opening_bottom: 60; Deduction_opening_left: 60; Deduction_opening_right: 60; Deduction_opening_top: 60

# IfcWindow: V209 (2)
In: Plan 2
Type - OperationType: USERDEFINED; ParameterTakesPrecedence: no; Sizeable: no
OverallWidth: 1110 mm
Allplan Attributes - Unit: Pc; V6: 0; V7: 0; V8: 0; V9: 0; Release: 3.0; Name: V209; Plugin_name: MainObject; Plugin_object_name: SmartPartCompressed; GlazingAreaFraction_Consider: 100; IFC Object type: IfcWindow; Version: 5.0; Height_window_sill_outside: 0; Height_window_sill_inside: 0; Offset_opening_bottom: 10; Offset_opening_top: 10; Offset_opening_left: 10; Offset_opening_right: 10; Deduction_opening_bottom: 60; Deduction_opening_left: 60; Deduction_opening_right: 60; Deduction_opening_top: 60
Name | OverallHeight (mm) | Allright_Comp_ID | NOI_UUID | Glass surface
V209 | 2110 | 0023Sym0780007746 | 84cb5e05-e28d-4939-8977-531e4630a18c--780007746 | 1.9206
V209 | 2410 | 0023Sym0780007716 | 84cb5e05-e28d-4939-8977-531e4630a18c--780007716 | 2.2176

# IfcWindow: V210
In: Plan 2
Type - OperationType: USERDEFINED; ParameterTakesPrecedence: no; Sizeable: no
OverallHeight: 1210 mm; OverallWidth: 1710 mm
Allplan Attributes - Allright_Comp_ID: 0023Sym0780007305; Unit: Pc; V6: 0; V7: 0; V8: 0; V9: 0; Release: 3.0; Name: V210; Plugin_name: MainObject; Plugin_object_name: SmartPartCompressed; GlazingAreaFraction_Consider: 100; NOI_UUID: 84cb5e05-e28d-4939-8977-531e4630a18c--780007305; IFC Object type: IfcWindow; Version: 5.0; Glass surface: 1.5808; Height_window_sill_outside: 0; Height_window_sill_inside: 0; Offset_opening_bottom: 10; Offset_opening_top: 10; Offset_opening_left: 10; Offset_opening_right: 10; Deduction_opening_bottom: 50; Deduction_opening_left: 50; Deduction_opening_right: 50; Deduction_opening_top: 50

# IfcWindow: V211
In: Plan 2
Type - OperationType: USERDEFINED; ParameterTakesPrecedence: no; Sizeable: no
OverallHeight: 1210 mm; OverallWidth: 1710 mm
Allplan Attributes - Allright_Comp_ID: 0023Sym0780007323; Unit: Pc; V6: 0; V7: 0; V8: 0; V9: 0; Release: 3.0; Name: V211; Plugin_name: MainObject; Plugin_object_name: SmartPartCompressed; GlazingAreaFraction_Consider: 100; NOI_UUID: 84cb5e05-e28d-4939-8977-531e4630a18c--780007323; IFC Object type: IfcWindow; Version: 5.0; Glass surface: 1.5808; Height_window_sill_outside: 0; Height_window_sill_inside: 0; Offset_opening_bottom: 10; Offset_opening_top: 10; Offset_opening_left: 10; Offset_opening_right: 10; Deduction_opening_bottom: 50; Deduction_opening_left: 50; Deduction_opening_right: 50; Deduction_opening_top: 50

# IfcWindow: V212
In: Plan 2
Type - OperationType: USERDEFINED; ParameterTakesPrecedence: no; Sizeable: no
OverallHeight: 1210 mm; OverallWidth: 1710 mm
Allplan Attributes - Allright_Comp_ID: 0023Sym0780007332; Unit: Pc; V6: 0; V7: 0; V8: 0; V9: 0; Release: 3.0; Name: V212; Plugin_name: MainObject; Plugin_object_name: SmartPartCompressed; GlazingAreaFraction_Consider: 100; NOI_UUID: 84cb5e05-e28d-4939-8977-531e4630a18c--780007332; IFC Object type: IfcWindow; Version: 5.0; Glass surface: 1.5808; Height_window_sill_outside: 0; Height_window_sill_inside: 0; Offset_opening_bottom: 10; Offset_opening_top: 10; Offset_opening_left: 10; Offset_opening_right: 10; Deduction_opening_bottom: 50; Deduction_opening_left: 50; Deduction_opening_right: 50; Deduction_opening_top: 50

# IfcWindow: V213
In: Plan 2
Type - OperationType: USERDEFINED; ParameterTakesPrecedence: no; Sizeable: no
OverallHeight: 1210 mm; OverallWidth: 1710 mm
Allplan Attributes - Allright_Comp_ID: 0023Sym0780007314; Unit: Pc; V6: 0; V7: 0; V8: 0; V9: 0; Release: 3.0; Name: V213; Plugin_name: MainObject; Plugin_object_name: SmartPartCompressed; GlazingAreaFraction_Consider: 100; NOI_UUID: 84cb5e05-e28d-4939-8977-531e4630a18c--780007314; IFC Object type: IfcWindow; Version: 5.0; Glass surface: 1.5808; Height_window_sill_outside: 0; Height_window_sill_inside: 0; Offset_opening_bottom: 10; Offset_opening_top: 10; Offset_opening_left: 10; Offset_opening_right: 10; Deduction_opening_bottom: 50; Deduction_opening_left: 50; Deduction_opening_right: 50; Deduction_opening_top: 50

# IfcWindow: V214
In: Plan 2
Type - OperationType: USERDEFINED; ParameterTakesPrecedence: no; Sizeable: no
OverallHeight: 1210 mm; OverallWidth: 1710 mm
Allplan Attributes - Allright_Comp_ID: 0023Sym0780007341; Unit: Pc; V6: 0; V7: 0; V8: 0; V9: 0; Release: 3.0; Name: V214; Plugin_name: MainObject; Plugin_object_name: SmartPartCompressed; GlazingAreaFraction_Consider: 100; NOI_UUID: 84cb5e05-e28d-4939-8977-531e4630a18c--780007341; IFC Object type: IfcWindow; Version: 5.0; Glass surface: 1.5808; Height_window_sill_outside: 0; Height_window_sill_inside: 0; Offset_opening_bottom: 10; Offset_opening_top: 10; Offset_opening_left: 10; Offset_opening_right: 10; Deduction_opening_bottom: 50; Deduction_opening_left: 50; Deduction_opening_right: 50; Deduction_opening_top: 50

# IfcWindow: V215
In: Plan 2
Type - OperationType: USERDEFINED; ParameterTakesPrecedence: no; Sizeable: no
OverallHeight: 1210 mm; OverallWidth: 1410 mm
Allplan Attributes - Allright_Comp_ID: 0023Sym0780007857; Unit: Pc; V6: 0; V7: 0; V8: 0; V9: 0; Release: 3.0; Name: V215; Plugin_name: MainObject; Plugin_object_name: SmartPartCompressed; GlazingAreaFraction_Consider: 100; NOI_UUID: 84cb5e05-e28d-4939-8977-531e4630a18c--780007857; IFC Object type: IfcWindow; Version: 5.0; Glass surface: 1.2526; Height_window_sill_outside: 0; Height_window_sill_inside: 0; Offset_opening_bottom: 10; Offset_opening_top: 10; Offset_opening_left: 10; Offset_opening_right: 10; Deduction_opening_bottom: 50; Deduction_opening_left: 50; Deduction_opening_right: 50; Deduction_opening_top: 50

# IfcWindow: V216
In: Plan 2
Type - OperationType: USERDEFINED; ParameterTakesPrecedence: no; Sizeable: no
OverallHeight: 1210 mm; OverallWidth: 1210 mm
Allplan Attributes - Allright_Comp_ID: 0023Sym0780007984; Unit: Pc; V6: 0; V7: 0; V8: 0; V9: 0; Release: 3.0; Name: V216; Plugin_name: MainObject; Plugin_object_name: SmartPartCompressed; GlazingAreaFraction_Consider: 100; NOI_UUID: 84cb5e05-e28d-4939-8977-531e4630a18c--780007984; IFC Object type: IfcWindow; Version: 5.0; Glass surface: 1.0609; Height_window_sill_outside: 0; Height_window_sill_inside: 0; Offset_opening_bottom: 10; Offset_opening_top: 10; Offset_opening_left: 10; Offset_opening_right: 10; Deduction_opening_bottom: 60; Deduction_opening_left: 60; Deduction_opening_right: 60; Deduction_opening_top: 60

# IfcWindow: V217
In: Plan 2
Type - OperationType: USERDEFINED; ParameterTakesPrecedence: no; Sizeable: no
OverallHeight: 1210 mm; OverallWidth: 1410 mm
Allplan Attributes - Allright_Comp_ID: 0023Sym0780007893; Unit: Pc; V6: 0; V7: 0; V8: 0; V9: 0; Release: 3.0; Name: V217; Plugin_name: MainObject; Plugin_object_name: SmartPartCompressed; GlazingAreaFraction_Consider: 100; NOI_UUID: 84cb5e05-e28d-4939-8977-531e4630a18c--780007893; IFC Object type: IfcWindow; Version: 5.0; Glass surface: 1.2526; Height_window_sill_outside: 0; Height_window_sill_inside: 0; Offset_opening_bottom: 10; Offset_opening_top: 10; Offset_opening_left: 10; Offset_opening_right: 10; Deduction_opening_bottom: 50; Deduction_opening_left: 50; Deduction_opening_right: 50; Deduction_opening_top: 50
